VERSION 5.7 ;
BUSBITCHARS "[]" ;
DIVIDERCHAR "/" ;
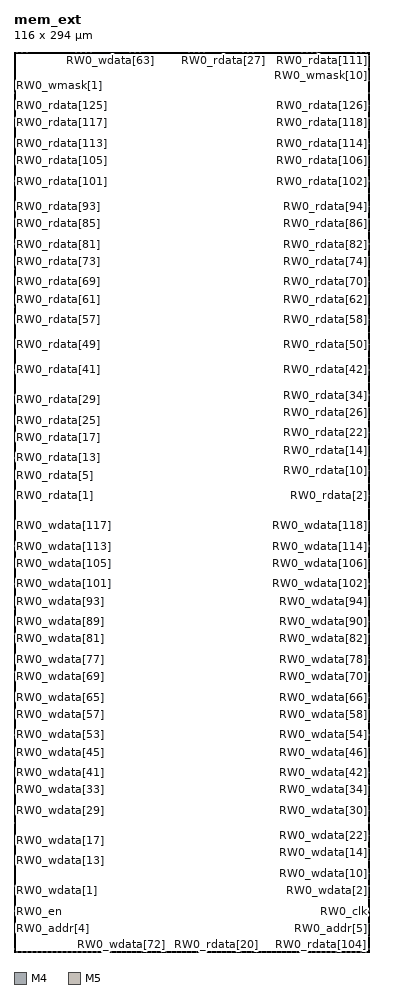
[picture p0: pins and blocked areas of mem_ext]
MACRO mem_ext
  FOREIGN mem_ext 0 0 ;
  CLASS BLOCK ;
  ORIGIN 0 0 ;
  SYMMETRY X Y R90 ;
  SIZE 116.000 BY 294.000 ;
  SITE asap7sc7p5t ;
  PIN RW0_addr[0]
    DIRECTION INPUT ;
    USE SIGNAL ;
    SHAPE ABUTMENT ;
    PORT
      LAYER M4 ;
      RECT 0.000 0.972 0.096 1.068 ;
    END
  END RW0_addr[0]
  PIN RW0_addr[1]
    DIRECTION INPUT ;
    USE SIGNAL ;
    SHAPE ABUTMENT ;
    PORT
      LAYER M4 ;
      RECT 115.904 0.972 116.000 1.068 ;
    END
  END RW0_addr[1]
  PIN RW0_addr[2]
    DIRECTION INPUT ;
    USE SIGNAL ;
    SHAPE ABUTMENT ;
    PORT
      LAYER M5 ;
      RECT 0.972 293.904 1.068 294.000 ;
    END
  END RW0_addr[2]
  PIN RW0_addr[3]
    DIRECTION INPUT ;
    USE SIGNAL ;
    SHAPE ABUTMENT ;
    PORT
      LAYER M5 ;
      RECT 0.972 0.000 1.068 0.096 ;
    END
  END RW0_addr[3]
  PIN RW0_addr[4]
    DIRECTION INPUT ;
    USE SIGNAL ;
    SHAPE ABUTMENT ;
    PORT
      LAYER M4 ;
      RECT 0.000 5.100 0.096 5.196 ;
    END
  END RW0_addr[4]
  PIN RW0_addr[5]
    DIRECTION INPUT ;
    USE SIGNAL ;
    SHAPE ABUTMENT ;
    PORT
      LAYER M4 ;
      RECT 115.904 5.100 116.000 5.196 ;
    END
  END RW0_addr[5]
  PIN RW0_addr[6]
    DIRECTION INPUT ;
    USE SIGNAL ;
    SHAPE ABUTMENT ;
    PORT
      LAYER M5 ;
      RECT 2.556 293.904 2.652 294.000 ;
    END
  END RW0_addr[6]
  PIN RW0_addr[7]
    DIRECTION INPUT ;
    USE SIGNAL ;
    SHAPE ABUTMENT ;
    PORT
      LAYER M5 ;
      RECT 2.604 0.000 2.700 0.096 ;
    END
  END RW0_addr[7]
  PIN RW0_addr[8]
    DIRECTION INPUT ;
    USE SIGNAL ;
    SHAPE ABUTMENT ;
    PORT
      LAYER M4 ;
      RECT 0.000 9.180 0.096 9.276 ;
    END
  END RW0_addr[8]
  PIN RW0_addr[9]
    DIRECTION INPUT ;
    USE SIGNAL ;
    SHAPE ABUTMENT ;
    PORT
      LAYER M4 ;
      RECT 115.904 9.180 116.000 9.276 ;
    END
  END RW0_addr[9]
  PIN RW0_addr[10]
    DIRECTION INPUT ;
    USE SIGNAL ;
    SHAPE ABUTMENT ;
    PORT
      LAYER M5 ;
      RECT 4.188 293.904 4.284 294.000 ;
    END
  END RW0_addr[10]
  PIN RW0_addr[11]
    DIRECTION INPUT ;
    USE SIGNAL ;
    SHAPE ABUTMENT ;
    PORT
      LAYER M5 ;
      RECT 4.236 0.000 4.332 0.096 ;
    END
  END RW0_addr[11]
  PIN RW0_en
    DIRECTION INPUT ;
    USE SIGNAL ;
    SHAPE ABUTMENT ;
    PORT
      LAYER M4 ;
      RECT 0.000 13.308 0.096 13.404 ;
    END
  END RW0_en
  PIN RW0_clk
    DIRECTION INPUT ;
    USE SIGNAL ;
    SHAPE ABUTMENT ;
    PORT
      LAYER M4 ;
      RECT 115.904 13.308 116.000 13.404 ;
    END
  END RW0_clk
  PIN RW0_wmode
    DIRECTION INPUT ;
    USE SIGNAL ;
    SHAPE ABUTMENT ;
    PORT
      LAYER M5 ;
      RECT 5.772 293.904 5.868 294.000 ;
    END
  END RW0_wmode
  PIN RW0_wdata[0]
    DIRECTION INPUT ;
    USE SIGNAL ;
    SHAPE ABUTMENT ;
    PORT
      LAYER M5 ;
      RECT 5.868 0.000 5.964 0.096 ;
    END
  END RW0_wdata[0]
  PIN RW0_wdata[1]
    DIRECTION INPUT ;
    USE SIGNAL ;
    SHAPE ABUTMENT ;
    PORT
      LAYER M4 ;
      RECT 0.000 17.436 0.096 17.532 ;
    END
  END RW0_wdata[1]
  PIN RW0_wdata[2]
    DIRECTION INPUT ;
    USE SIGNAL ;
    SHAPE ABUTMENT ;
    PORT
      LAYER M4 ;
      RECT 115.904 17.436 116.000 17.532 ;
    END
  END RW0_wdata[2]
  PIN RW0_wdata[3]
    DIRECTION INPUT ;
    USE SIGNAL ;
    SHAPE ABUTMENT ;
    PORT
      LAYER M5 ;
      RECT 7.404 293.904 7.500 294.000 ;
    END
  END RW0_wdata[3]
  PIN RW0_wdata[4]
    DIRECTION INPUT ;
    USE SIGNAL ;
    SHAPE ABUTMENT ;
    PORT
      LAYER M5 ;
      RECT 7.500 0.000 7.596 0.096 ;
    END
  END RW0_wdata[4]
  PIN RW0_wdata[5]
    DIRECTION INPUT ;
    USE SIGNAL ;
    SHAPE ABUTMENT ;
    PORT
      LAYER M4 ;
      RECT 0.000 21.516 0.096 21.612 ;
    END
  END RW0_wdata[5]
  PIN RW0_wdata[6]
    DIRECTION INPUT ;
    USE SIGNAL ;
    SHAPE ABUTMENT ;
    PORT
      LAYER M4 ;
      RECT 115.904 21.516 116.000 21.612 ;
    END
  END RW0_wdata[6]
  PIN RW0_wdata[7]
    DIRECTION INPUT ;
    USE SIGNAL ;
    SHAPE ABUTMENT ;
    PORT
      LAYER M5 ;
      RECT 8.988 293.904 9.084 294.000 ;
    END
  END RW0_wdata[7]
  PIN RW0_wdata[8]
    DIRECTION INPUT ;
    USE SIGNAL ;
    SHAPE ABUTMENT ;
    PORT
      LAYER M5 ;
      RECT 9.132 0.000 9.228 0.096 ;
    END
  END RW0_wdata[8]
  PIN RW0_wdata[9]
    DIRECTION INPUT ;
    USE SIGNAL ;
    SHAPE ABUTMENT ;
    PORT
      LAYER M4 ;
      RECT 0.000 25.644 0.096 25.740 ;
    END
  END RW0_wdata[9]
  PIN RW0_wdata[10]
    DIRECTION INPUT ;
    USE SIGNAL ;
    SHAPE ABUTMENT ;
    PORT
      LAYER M4 ;
      RECT 115.904 25.644 116.000 25.740 ;
    END
  END RW0_wdata[10]
  PIN RW0_wdata[11]
    DIRECTION INPUT ;
    USE SIGNAL ;
    SHAPE ABUTMENT ;
    PORT
      LAYER M5 ;
      RECT 10.620 293.904 10.716 294.000 ;
    END
  END RW0_wdata[11]
  PIN RW0_wdata[12]
    DIRECTION INPUT ;
    USE SIGNAL ;
    SHAPE ABUTMENT ;
    PORT
      LAYER M5 ;
      RECT 10.716 0.000 10.812 0.096 ;
    END
  END RW0_wdata[12]
  PIN RW0_wdata[13]
    DIRECTION INPUT ;
    USE SIGNAL ;
    SHAPE ABUTMENT ;
    PORT
      LAYER M4 ;
      RECT 0.000 29.772 0.096 29.868 ;
    END
  END RW0_wdata[13]
  PIN RW0_wdata[14]
    DIRECTION INPUT ;
    USE SIGNAL ;
    SHAPE ABUTMENT ;
    PORT
      LAYER M4 ;
      RECT 115.904 29.772 116.000 29.868 ;
    END
  END RW0_wdata[14]
  PIN RW0_wdata[15]
    DIRECTION INPUT ;
    USE SIGNAL ;
    SHAPE ABUTMENT ;
    PORT
      LAYER M5 ;
      RECT 12.204 293.904 12.300 294.000 ;
    END
  END RW0_wdata[15]
  PIN RW0_wdata[16]
    DIRECTION INPUT ;
    USE SIGNAL ;
    SHAPE ABUTMENT ;
    PORT
      LAYER M5 ;
      RECT 12.348 0.000 12.444 0.096 ;
    END
  END RW0_wdata[16]
  PIN RW0_wdata[17]
    DIRECTION INPUT ;
    USE SIGNAL ;
    SHAPE ABUTMENT ;
    PORT
      LAYER M4 ;
      RECT 0.000 33.852 0.096 33.948 ;
    END
  END RW0_wdata[17]
  PIN RW0_wdata[18]
    DIRECTION INPUT ;
    USE SIGNAL ;
    SHAPE ABUTMENT ;
    PORT
      LAYER M4 ;
      RECT 115.904 33.852 116.000 33.948 ;
    END
  END RW0_wdata[18]
  PIN RW0_wdata[19]
    DIRECTION INPUT ;
    USE SIGNAL ;
    SHAPE ABUTMENT ;
    PORT
      LAYER M5 ;
      RECT 13.788 293.904 13.884 294.000 ;
    END
  END RW0_wdata[19]
  PIN RW0_wdata[20]
    DIRECTION INPUT ;
    USE SIGNAL ;
    SHAPE ABUTMENT ;
    PORT
      LAYER M5 ;
      RECT 13.980 0.000 14.076 0.096 ;
    END
  END RW0_wdata[20]
  PIN RW0_wdata[21]
    DIRECTION INPUT ;
    USE SIGNAL ;
    SHAPE ABUTMENT ;
    PORT
      LAYER M4 ;
      RECT 0.000 37.980 0.096 38.076 ;
    END
  END RW0_wdata[21]
  PIN RW0_wdata[22]
    DIRECTION INPUT ;
    USE SIGNAL ;
    SHAPE ABUTMENT ;
    PORT
      LAYER M4 ;
      RECT 115.904 37.980 116.000 38.076 ;
    END
  END RW0_wdata[22]
  PIN RW0_wdata[23]
    DIRECTION INPUT ;
    USE SIGNAL ;
    SHAPE ABUTMENT ;
    PORT
      LAYER M5 ;
      RECT 15.420 293.904 15.516 294.000 ;
    END
  END RW0_wdata[23]
  PIN RW0_wdata[24]
    DIRECTION INPUT ;
    USE SIGNAL ;
    SHAPE ABUTMENT ;
    PORT
      LAYER M5 ;
      RECT 15.612 0.000 15.708 0.096 ;
    END
  END RW0_wdata[24]
  PIN RW0_wdata[25]
    DIRECTION INPUT ;
    USE SIGNAL ;
    SHAPE ABUTMENT ;
    PORT
      LAYER M4 ;
      RECT 0.000 42.108 0.096 42.204 ;
    END
  END RW0_wdata[25]
  PIN RW0_wdata[26]
    DIRECTION INPUT ;
    USE SIGNAL ;
    SHAPE ABUTMENT ;
    PORT
      LAYER M4 ;
      RECT 115.904 42.108 116.000 42.204 ;
    END
  END RW0_wdata[26]
  PIN RW0_wdata[27]
    DIRECTION INPUT ;
    USE SIGNAL ;
    SHAPE ABUTMENT ;
    PORT
      LAYER M5 ;
      RECT 17.004 293.904 17.100 294.000 ;
    END
  END RW0_wdata[27]
  PIN RW0_wdata[28]
    DIRECTION INPUT ;
    USE SIGNAL ;
    SHAPE ABUTMENT ;
    PORT
      LAYER M5 ;
      RECT 17.244 0.000 17.340 0.096 ;
    END
  END RW0_wdata[28]
  PIN RW0_wdata[29]
    DIRECTION INPUT ;
    USE SIGNAL ;
    SHAPE ABUTMENT ;
    PORT
      LAYER M4 ;
      RECT 0.000 46.188 0.096 46.284 ;
    END
  END RW0_wdata[29]
  PIN RW0_wdata[30]
    DIRECTION INPUT ;
    USE SIGNAL ;
    SHAPE ABUTMENT ;
    PORT
      LAYER M4 ;
      RECT 115.904 46.188 116.000 46.284 ;
    END
  END RW0_wdata[30]
  PIN RW0_wdata[31]
    DIRECTION INPUT ;
    USE SIGNAL ;
    SHAPE ABUTMENT ;
    PORT
      LAYER M5 ;
      RECT 18.636 293.904 18.732 294.000 ;
    END
  END RW0_wdata[31]
  PIN RW0_wdata[32]
    DIRECTION INPUT ;
    USE SIGNAL ;
    SHAPE ABUTMENT ;
    PORT
      LAYER M5 ;
      RECT 18.876 0.000 18.972 0.096 ;
    END
  END RW0_wdata[32]
  PIN RW0_wdata[33]
    DIRECTION INPUT ;
    USE SIGNAL ;
    SHAPE ABUTMENT ;
    PORT
      LAYER M4 ;
      RECT 0.000 50.316 0.096 50.412 ;
    END
  END RW0_wdata[33]
  PIN RW0_wdata[34]
    DIRECTION INPUT ;
    USE SIGNAL ;
    SHAPE ABUTMENT ;
    PORT
      LAYER M4 ;
      RECT 115.904 50.316 116.000 50.412 ;
    END
  END RW0_wdata[34]
  PIN RW0_wdata[35]
    DIRECTION INPUT ;
    USE SIGNAL ;
    SHAPE ABUTMENT ;
    PORT
      LAYER M5 ;
      RECT 20.220 293.904 20.316 294.000 ;
    END
  END RW0_wdata[35]
  PIN RW0_wdata[36]
    DIRECTION INPUT ;
    USE SIGNAL ;
    SHAPE ABUTMENT ;
    PORT
      LAYER M5 ;
      RECT 20.508 0.000 20.604 0.096 ;
    END
  END RW0_wdata[36]
  PIN RW0_wdata[37]
    DIRECTION INPUT ;
    USE SIGNAL ;
    SHAPE ABUTMENT ;
    PORT
      LAYER M4 ;
      RECT 0.000 54.444 0.096 54.540 ;
    END
  END RW0_wdata[37]
  PIN RW0_wdata[38]
    DIRECTION INPUT ;
    USE SIGNAL ;
    SHAPE ABUTMENT ;
    PORT
      LAYER M4 ;
      RECT 115.904 54.444 116.000 54.540 ;
    END
  END RW0_wdata[38]
  PIN RW0_wdata[39]
    DIRECTION INPUT ;
    USE SIGNAL ;
    SHAPE ABUTMENT ;
    PORT
      LAYER M5 ;
      RECT 21.852 293.904 21.948 294.000 ;
    END
  END RW0_wdata[39]
  PIN RW0_wdata[40]
    DIRECTION INPUT ;
    USE SIGNAL ;
    SHAPE ABUTMENT ;
    PORT
      LAYER M5 ;
      RECT 22.140 0.000 22.236 0.096 ;
    END
  END RW0_wdata[40]
  PIN RW0_wdata[41]
    DIRECTION INPUT ;
    USE SIGNAL ;
    SHAPE ABUTMENT ;
    PORT
      LAYER M4 ;
      RECT 0.000 58.524 0.096 58.620 ;
    END
  END RW0_wdata[41]
  PIN RW0_wdata[42]
    DIRECTION INPUT ;
    USE SIGNAL ;
    SHAPE ABUTMENT ;
    PORT
      LAYER M4 ;
      RECT 115.904 58.524 116.000 58.620 ;
    END
  END RW0_wdata[42]
  PIN RW0_wdata[43]
    DIRECTION INPUT ;
    USE SIGNAL ;
    SHAPE ABUTMENT ;
    PORT
      LAYER M5 ;
      RECT 23.436 293.904 23.532 294.000 ;
    END
  END RW0_wdata[43]
  PIN RW0_wdata[44]
    DIRECTION INPUT ;
    USE SIGNAL ;
    SHAPE ABUTMENT ;
    PORT
      LAYER M5 ;
      RECT 23.772 0.000 23.868 0.096 ;
    END
  END RW0_wdata[44]
  PIN RW0_wdata[45]
    DIRECTION INPUT ;
    USE SIGNAL ;
    SHAPE ABUTMENT ;
    PORT
      LAYER M4 ;
      RECT 0.000 62.652 0.096 62.748 ;
    END
  END RW0_wdata[45]
  PIN RW0_wdata[46]
    DIRECTION INPUT ;
    USE SIGNAL ;
    SHAPE ABUTMENT ;
    PORT
      LAYER M4 ;
      RECT 115.904 62.652 116.000 62.748 ;
    END
  END RW0_wdata[46]
  PIN RW0_wdata[47]
    DIRECTION INPUT ;
    USE SIGNAL ;
    SHAPE ABUTMENT ;
    PORT
      LAYER M5 ;
      RECT 25.068 293.904 25.164 294.000 ;
    END
  END RW0_wdata[47]
  PIN RW0_wdata[48]
    DIRECTION INPUT ;
    USE SIGNAL ;
    SHAPE ABUTMENT ;
    PORT
      LAYER M5 ;
      RECT 25.404 0.000 25.500 0.096 ;
    END
  END RW0_wdata[48]
  PIN RW0_wdata[49]
    DIRECTION INPUT ;
    USE SIGNAL ;
    SHAPE ABUTMENT ;
    PORT
      LAYER M4 ;
      RECT 0.000 66.780 0.096 66.876 ;
    END
  END RW0_wdata[49]
  PIN RW0_wdata[50]
    DIRECTION INPUT ;
    USE SIGNAL ;
    SHAPE ABUTMENT ;
    PORT
      LAYER M4 ;
      RECT 115.904 66.780 116.000 66.876 ;
    END
  END RW0_wdata[50]
  PIN RW0_wdata[51]
    DIRECTION INPUT ;
    USE SIGNAL ;
    SHAPE ABUTMENT ;
    PORT
      LAYER M5 ;
      RECT 26.652 293.904 26.748 294.000 ;
    END
  END RW0_wdata[51]
  PIN RW0_wdata[52]
    DIRECTION INPUT ;
    USE SIGNAL ;
    SHAPE ABUTMENT ;
    PORT
      LAYER M5 ;
      RECT 27.036 0.000 27.132 0.096 ;
    END
  END RW0_wdata[52]
  PIN RW0_wdata[53]
    DIRECTION INPUT ;
    USE SIGNAL ;
    SHAPE ABUTMENT ;
    PORT
      LAYER M4 ;
      RECT 0.000 70.860 0.096 70.956 ;
    END
  END RW0_wdata[53]
  PIN RW0_wdata[54]
    DIRECTION INPUT ;
    USE SIGNAL ;
    SHAPE ABUTMENT ;
    PORT
      LAYER M4 ;
      RECT 115.904 70.860 116.000 70.956 ;
    END
  END RW0_wdata[54]
  PIN RW0_wdata[55]
    DIRECTION INPUT ;
    USE SIGNAL ;
    SHAPE ABUTMENT ;
    PORT
      LAYER M5 ;
      RECT 28.236 293.904 28.332 294.000 ;
    END
  END RW0_wdata[55]
  PIN RW0_wdata[56]
    DIRECTION INPUT ;
    USE SIGNAL ;
    SHAPE ABUTMENT ;
    PORT
      LAYER M5 ;
      RECT 28.668 0.000 28.764 0.096 ;
    END
  END RW0_wdata[56]
  PIN RW0_wdata[57]
    DIRECTION INPUT ;
    USE SIGNAL ;
    SHAPE ABUTMENT ;
    PORT
      LAYER M4 ;
      RECT 0.000 74.988 0.096 75.084 ;
    END
  END RW0_wdata[57]
  PIN RW0_wdata[58]
    DIRECTION INPUT ;
    USE SIGNAL ;
    SHAPE ABUTMENT ;
    PORT
      LAYER M4 ;
      RECT 115.904 74.988 116.000 75.084 ;
    END
  END RW0_wdata[58]
  PIN RW0_wdata[59]
    DIRECTION INPUT ;
    USE SIGNAL ;
    SHAPE ABUTMENT ;
    PORT
      LAYER M5 ;
      RECT 29.868 293.904 29.964 294.000 ;
    END
  END RW0_wdata[59]
  PIN RW0_wdata[60]
    DIRECTION INPUT ;
    USE SIGNAL ;
    SHAPE ABUTMENT ;
    PORT
      LAYER M5 ;
      RECT 30.252 0.000 30.348 0.096 ;
    END
  END RW0_wdata[60]
  PIN RW0_wdata[61]
    DIRECTION INPUT ;
    USE SIGNAL ;
    SHAPE ABUTMENT ;
    PORT
      LAYER M4 ;
      RECT 0.000 79.116 0.096 79.212 ;
    END
  END RW0_wdata[61]
  PIN RW0_wdata[62]
    DIRECTION INPUT ;
    USE SIGNAL ;
    SHAPE ABUTMENT ;
    PORT
      LAYER M4 ;
      RECT 115.904 79.116 116.000 79.212 ;
    END
  END RW0_wdata[62]
  PIN RW0_wdata[63]
    DIRECTION INPUT ;
    USE SIGNAL ;
    SHAPE ABUTMENT ;
    PORT
      LAYER M5 ;
      RECT 31.452 293.904 31.548 294.000 ;
    END
  END RW0_wdata[63]
  PIN RW0_wdata[64]
    DIRECTION INPUT ;
    USE SIGNAL ;
    SHAPE ABUTMENT ;
    PORT
      LAYER M5 ;
      RECT 31.884 0.000 31.980 0.096 ;
    END
  END RW0_wdata[64]
  PIN RW0_wdata[65]
    DIRECTION INPUT ;
    USE SIGNAL ;
    SHAPE ABUTMENT ;
    PORT
      LAYER M4 ;
      RECT 0.000 83.196 0.096 83.292 ;
    END
  END RW0_wdata[65]
  PIN RW0_wdata[66]
    DIRECTION INPUT ;
    USE SIGNAL ;
    SHAPE ABUTMENT ;
    PORT
      LAYER M4 ;
      RECT 115.904 83.196 116.000 83.292 ;
    END
  END RW0_wdata[66]
  PIN RW0_wdata[67]
    DIRECTION INPUT ;
    USE SIGNAL ;
    SHAPE ABUTMENT ;
    PORT
      LAYER M5 ;
      RECT 33.084 293.904 33.180 294.000 ;
    END
  END RW0_wdata[67]
  PIN RW0_wdata[68]
    DIRECTION INPUT ;
    USE SIGNAL ;
    SHAPE ABUTMENT ;
    PORT
      LAYER M5 ;
      RECT 33.516 0.000 33.612 0.096 ;
    END
  END RW0_wdata[68]
  PIN RW0_wdata[69]
    DIRECTION INPUT ;
    USE SIGNAL ;
    SHAPE ABUTMENT ;
    PORT
      LAYER M4 ;
      RECT 0.000 87.324 0.096 87.420 ;
    END
  END RW0_wdata[69]
  PIN RW0_wdata[70]
    DIRECTION INPUT ;
    USE SIGNAL ;
    SHAPE ABUTMENT ;
    PORT
      LAYER M4 ;
      RECT 115.904 87.324 116.000 87.420 ;
    END
  END RW0_wdata[70]
  PIN RW0_wdata[71]
    DIRECTION INPUT ;
    USE SIGNAL ;
    SHAPE ABUTMENT ;
    PORT
      LAYER M5 ;
      RECT 34.668 293.904 34.764 294.000 ;
    END
  END RW0_wdata[71]
  PIN RW0_wdata[72]
    DIRECTION INPUT ;
    USE SIGNAL ;
    SHAPE ABUTMENT ;
    PORT
      LAYER M5 ;
      RECT 35.148 0.000 35.244 0.096 ;
    END
  END RW0_wdata[72]
  PIN RW0_wdata[73]
    DIRECTION INPUT ;
    USE SIGNAL ;
    SHAPE ABUTMENT ;
    PORT
      LAYER M4 ;
      RECT 0.000 91.452 0.096 91.548 ;
    END
  END RW0_wdata[73]
  PIN RW0_wdata[74]
    DIRECTION INPUT ;
    USE SIGNAL ;
    SHAPE ABUTMENT ;
    PORT
      LAYER M4 ;
      RECT 115.904 91.452 116.000 91.548 ;
    END
  END RW0_wdata[74]
  PIN RW0_wdata[75]
    DIRECTION INPUT ;
    USE SIGNAL ;
    SHAPE ABUTMENT ;
    PORT
      LAYER M5 ;
      RECT 36.300 293.904 36.396 294.000 ;
    END
  END RW0_wdata[75]
  PIN RW0_wdata[76]
    DIRECTION INPUT ;
    USE SIGNAL ;
    SHAPE ABUTMENT ;
    PORT
      LAYER M5 ;
      RECT 36.780 0.000 36.876 0.096 ;
    END
  END RW0_wdata[76]
  PIN RW0_wdata[77]
    DIRECTION INPUT ;
    USE SIGNAL ;
    SHAPE ABUTMENT ;
    PORT
      LAYER M4 ;
      RECT 0.000 95.532 0.096 95.628 ;
    END
  END RW0_wdata[77]
  PIN RW0_wdata[78]
    DIRECTION INPUT ;
    USE SIGNAL ;
    SHAPE ABUTMENT ;
    PORT
      LAYER M4 ;
      RECT 115.904 95.532 116.000 95.628 ;
    END
  END RW0_wdata[78]
  PIN RW0_wdata[79]
    DIRECTION INPUT ;
    USE SIGNAL ;
    SHAPE ABUTMENT ;
    PORT
      LAYER M5 ;
      RECT 37.884 293.904 37.980 294.000 ;
    END
  END RW0_wdata[79]
  PIN RW0_wdata[80]
    DIRECTION INPUT ;
    USE SIGNAL ;
    SHAPE ABUTMENT ;
    PORT
      LAYER M5 ;
      RECT 38.412 0.000 38.508 0.096 ;
    END
  END RW0_wdata[80]
  PIN RW0_wdata[81]
    DIRECTION INPUT ;
    USE SIGNAL ;
    SHAPE ABUTMENT ;
    PORT
      LAYER M4 ;
      RECT 0.000 99.660 0.096 99.756 ;
    END
  END RW0_wdata[81]
  PIN RW0_wdata[82]
    DIRECTION INPUT ;
    USE SIGNAL ;
    SHAPE ABUTMENT ;
    PORT
      LAYER M4 ;
      RECT 115.904 99.660 116.000 99.756 ;
    END
  END RW0_wdata[82]
  PIN RW0_wdata[83]
    DIRECTION INPUT ;
    USE SIGNAL ;
    SHAPE ABUTMENT ;
    PORT
      LAYER M5 ;
      RECT 39.468 293.904 39.564 294.000 ;
    END
  END RW0_wdata[83]
  PIN RW0_wdata[84]
    DIRECTION INPUT ;
    USE SIGNAL ;
    SHAPE ABUTMENT ;
    PORT
      LAYER M5 ;
      RECT 40.044 0.000 40.140 0.096 ;
    END
  END RW0_wdata[84]
  PIN RW0_wdata[85]
    DIRECTION INPUT ;
    USE SIGNAL ;
    SHAPE ABUTMENT ;
    PORT
      LAYER M4 ;
      RECT 0.000 103.788 0.096 103.884 ;
    END
  END RW0_wdata[85]
  PIN RW0_wdata[86]
    DIRECTION INPUT ;
    USE SIGNAL ;
    SHAPE ABUTMENT ;
    PORT
      LAYER M4 ;
      RECT 115.904 103.788 116.000 103.884 ;
    END
  END RW0_wdata[86]
  PIN RW0_wdata[87]
    DIRECTION INPUT ;
    USE SIGNAL ;
    SHAPE ABUTMENT ;
    PORT
      LAYER M5 ;
      RECT 41.100 293.904 41.196 294.000 ;
    END
  END RW0_wdata[87]
  PIN RW0_wdata[88]
    DIRECTION INPUT ;
    USE SIGNAL ;
    SHAPE ABUTMENT ;
    PORT
      LAYER M5 ;
      RECT 41.676 0.000 41.772 0.096 ;
    END
  END RW0_wdata[88]
  PIN RW0_wdata[89]
    DIRECTION INPUT ;
    USE SIGNAL ;
    SHAPE ABUTMENT ;
    PORT
      LAYER M4 ;
      RECT 0.000 107.868 0.096 107.964 ;
    END
  END RW0_wdata[89]
  PIN RW0_wdata[90]
    DIRECTION INPUT ;
    USE SIGNAL ;
    SHAPE ABUTMENT ;
    PORT
      LAYER M4 ;
      RECT 115.904 107.868 116.000 107.964 ;
    END
  END RW0_wdata[90]
  PIN RW0_wdata[91]
    DIRECTION INPUT ;
    USE SIGNAL ;
    SHAPE ABUTMENT ;
    PORT
      LAYER M5 ;
      RECT 42.684 293.904 42.780 294.000 ;
    END
  END RW0_wdata[91]
  PIN RW0_wdata[92]
    DIRECTION INPUT ;
    USE SIGNAL ;
    SHAPE ABUTMENT ;
    PORT
      LAYER M5 ;
      RECT 43.308 0.000 43.404 0.096 ;
    END
  END RW0_wdata[92]
  PIN RW0_wdata[93]
    DIRECTION INPUT ;
    USE SIGNAL ;
    SHAPE ABUTMENT ;
    PORT
      LAYER M4 ;
      RECT 0.000 111.996 0.096 112.092 ;
    END
  END RW0_wdata[93]
  PIN RW0_wdata[94]
    DIRECTION INPUT ;
    USE SIGNAL ;
    SHAPE ABUTMENT ;
    PORT
      LAYER M4 ;
      RECT 115.904 111.996 116.000 112.092 ;
    END
  END RW0_wdata[94]
  PIN RW0_wdata[95]
    DIRECTION INPUT ;
    USE SIGNAL ;
    SHAPE ABUTMENT ;
    PORT
      LAYER M5 ;
      RECT 44.316 293.904 44.412 294.000 ;
    END
  END RW0_wdata[95]
  PIN RW0_wdata[96]
    DIRECTION INPUT ;
    USE SIGNAL ;
    SHAPE ABUTMENT ;
    PORT
      LAYER M5 ;
      RECT 44.940 0.000 45.036 0.096 ;
    END
  END RW0_wdata[96]
  PIN RW0_wdata[97]
    DIRECTION INPUT ;
    USE SIGNAL ;
    SHAPE ABUTMENT ;
    PORT
      LAYER M4 ;
      RECT 0.000 116.124 0.096 116.220 ;
    END
  END RW0_wdata[97]
  PIN RW0_wdata[98]
    DIRECTION INPUT ;
    USE SIGNAL ;
    SHAPE ABUTMENT ;
    PORT
      LAYER M4 ;
      RECT 115.904 116.124 116.000 116.220 ;
    END
  END RW0_wdata[98]
  PIN RW0_wdata[99]
    DIRECTION INPUT ;
    USE SIGNAL ;
    SHAPE ABUTMENT ;
    PORT
      LAYER M5 ;
      RECT 45.900 293.904 45.996 294.000 ;
    END
  END RW0_wdata[99]
  PIN RW0_wdata[100]
    DIRECTION INPUT ;
    USE SIGNAL ;
    SHAPE ABUTMENT ;
    PORT
      LAYER M5 ;
      RECT 46.572 0.000 46.668 0.096 ;
    END
  END RW0_wdata[100]
  PIN RW0_wdata[101]
    DIRECTION INPUT ;
    USE SIGNAL ;
    SHAPE ABUTMENT ;
    PORT
      LAYER M4 ;
      RECT 0.000 120.204 0.096 120.300 ;
    END
  END RW0_wdata[101]
  PIN RW0_wdata[102]
    DIRECTION INPUT ;
    USE SIGNAL ;
    SHAPE ABUTMENT ;
    PORT
      LAYER M4 ;
      RECT 115.904 120.204 116.000 120.300 ;
    END
  END RW0_wdata[102]
  PIN RW0_wdata[103]
    DIRECTION INPUT ;
    USE SIGNAL ;
    SHAPE ABUTMENT ;
    PORT
      LAYER M5 ;
      RECT 47.532 293.904 47.628 294.000 ;
    END
  END RW0_wdata[103]
  PIN RW0_wdata[104]
    DIRECTION INPUT ;
    USE SIGNAL ;
    SHAPE ABUTMENT ;
    PORT
      LAYER M5 ;
      RECT 48.204 0.000 48.300 0.096 ;
    END
  END RW0_wdata[104]
  PIN RW0_wdata[105]
    DIRECTION INPUT ;
    USE SIGNAL ;
    SHAPE ABUTMENT ;
    PORT
      LAYER M4 ;
      RECT 0.000 124.332 0.096 124.428 ;
    END
  END RW0_wdata[105]
  PIN RW0_wdata[106]
    DIRECTION INPUT ;
    USE SIGNAL ;
    SHAPE ABUTMENT ;
    PORT
      LAYER M4 ;
      RECT 115.904 124.332 116.000 124.428 ;
    END
  END RW0_wdata[106]
  PIN RW0_wdata[107]
    DIRECTION INPUT ;
    USE SIGNAL ;
    SHAPE ABUTMENT ;
    PORT
      LAYER M5 ;
      RECT 49.116 293.904 49.212 294.000 ;
    END
  END RW0_wdata[107]
  PIN RW0_wdata[108]
    DIRECTION INPUT ;
    USE SIGNAL ;
    SHAPE ABUTMENT ;
    PORT
      LAYER M5 ;
      RECT 49.788 0.000 49.884 0.096 ;
    END
  END RW0_wdata[108]
  PIN RW0_wdata[109]
    DIRECTION INPUT ;
    USE SIGNAL ;
    SHAPE ABUTMENT ;
    PORT
      LAYER M4 ;
      RECT 0.000 128.460 0.096 128.556 ;
    END
  END RW0_wdata[109]
  PIN RW0_wdata[110]
    DIRECTION INPUT ;
    USE SIGNAL ;
    SHAPE ABUTMENT ;
    PORT
      LAYER M4 ;
      RECT 115.904 128.460 116.000 128.556 ;
    END
  END RW0_wdata[110]
  PIN RW0_wdata[111]
    DIRECTION INPUT ;
    USE SIGNAL ;
    SHAPE ABUTMENT ;
    PORT
      LAYER M5 ;
      RECT 50.748 293.904 50.844 294.000 ;
    END
  END RW0_wdata[111]
  PIN RW0_wdata[112]
    DIRECTION INPUT ;
    USE SIGNAL ;
    SHAPE ABUTMENT ;
    PORT
      LAYER M5 ;
      RECT 51.420 0.000 51.516 0.096 ;
    END
  END RW0_wdata[112]
  PIN RW0_wdata[113]
    DIRECTION INPUT ;
    USE SIGNAL ;
    SHAPE ABUTMENT ;
    PORT
      LAYER M4 ;
      RECT 0.000 132.540 0.096 132.636 ;
    END
  END RW0_wdata[113]
  PIN RW0_wdata[114]
    DIRECTION INPUT ;
    USE SIGNAL ;
    SHAPE ABUTMENT ;
    PORT
      LAYER M4 ;
      RECT 115.904 132.540 116.000 132.636 ;
    END
  END RW0_wdata[114]
  PIN RW0_wdata[115]
    DIRECTION INPUT ;
    USE SIGNAL ;
    SHAPE ABUTMENT ;
    PORT
      LAYER M5 ;
      RECT 52.332 293.904 52.428 294.000 ;
    END
  END RW0_wdata[115]
  PIN RW0_wdata[116]
    DIRECTION INPUT ;
    USE SIGNAL ;
    SHAPE ABUTMENT ;
    PORT
      LAYER M5 ;
      RECT 53.052 0.000 53.148 0.096 ;
    END
  END RW0_wdata[116]
  PIN RW0_wdata[117]
    DIRECTION INPUT ;
    USE SIGNAL ;
    SHAPE ABUTMENT ;
    PORT
      LAYER M4 ;
      RECT 0.000 136.668 0.096 136.764 ;
    END
  END RW0_wdata[117]
  PIN RW0_wdata[118]
    DIRECTION INPUT ;
    USE SIGNAL ;
    SHAPE ABUTMENT ;
    PORT
      LAYER M4 ;
      RECT 115.904 136.668 116.000 136.764 ;
    END
  END RW0_wdata[118]
  PIN RW0_wdata[119]
    DIRECTION INPUT ;
    USE SIGNAL ;
    SHAPE ABUTMENT ;
    PORT
      LAYER M5 ;
      RECT 53.916 293.904 54.012 294.000 ;
    END
  END RW0_wdata[119]
  PIN RW0_wdata[120]
    DIRECTION INPUT ;
    USE SIGNAL ;
    SHAPE ABUTMENT ;
    PORT
      LAYER M5 ;
      RECT 54.684 0.000 54.780 0.096 ;
    END
  END RW0_wdata[120]
  PIN RW0_wdata[121]
    DIRECTION INPUT ;
    USE SIGNAL ;
    SHAPE ABUTMENT ;
    PORT
      LAYER M4 ;
      RECT 0.000 140.796 0.096 140.892 ;
    END
  END RW0_wdata[121]
  PIN RW0_wdata[122]
    DIRECTION INPUT ;
    USE SIGNAL ;
    SHAPE ABUTMENT ;
    PORT
      LAYER M4 ;
      RECT 115.904 140.796 116.000 140.892 ;
    END
  END RW0_wdata[122]
  PIN RW0_wdata[123]
    DIRECTION INPUT ;
    USE SIGNAL ;
    SHAPE ABUTMENT ;
    PORT
      LAYER M5 ;
      RECT 55.548 293.904 55.644 294.000 ;
    END
  END RW0_wdata[123]
  PIN RW0_wdata[124]
    DIRECTION INPUT ;
    USE SIGNAL ;
    SHAPE ABUTMENT ;
    PORT
      LAYER M5 ;
      RECT 56.316 0.000 56.412 0.096 ;
    END
  END RW0_wdata[124]
  PIN RW0_wdata[125]
    DIRECTION INPUT ;
    USE SIGNAL ;
    SHAPE ABUTMENT ;
    PORT
      LAYER M4 ;
      RECT 0.000 144.876 0.096 144.972 ;
    END
  END RW0_wdata[125]
  PIN RW0_wdata[126]
    DIRECTION INPUT ;
    USE SIGNAL ;
    SHAPE ABUTMENT ;
    PORT
      LAYER M4 ;
      RECT 115.904 144.876 116.000 144.972 ;
    END
  END RW0_wdata[126]
  PIN RW0_wdata[127]
    DIRECTION INPUT ;
    USE SIGNAL ;
    SHAPE ABUTMENT ;
    PORT
      LAYER M5 ;
      RECT 57.132 293.904 57.228 294.000 ;
    END
  END RW0_wdata[127]
  PIN RW0_rdata[0]
    DIRECTION OUTPUT ;
    USE SIGNAL ;
    SHAPE ABUTMENT ;
    PORT
      LAYER M5 ;
      RECT 57.948 0.000 58.044 0.096 ;
    END
  END RW0_rdata[0]
  PIN RW0_rdata[1]
    DIRECTION OUTPUT ;
    USE SIGNAL ;
    SHAPE ABUTMENT ;
    PORT
      LAYER M4 ;
      RECT 0.000 149.004 0.096 149.100 ;
    END
  END RW0_rdata[1]
  PIN RW0_rdata[2]
    DIRECTION OUTPUT ;
    USE SIGNAL ;
    SHAPE ABUTMENT ;
    PORT
      LAYER M4 ;
      RECT 115.904 149.004 116.000 149.100 ;
    END
  END RW0_rdata[2]
  PIN RW0_rdata[3]
    DIRECTION OUTPUT ;
    USE SIGNAL ;
    SHAPE ABUTMENT ;
    PORT
      LAYER M5 ;
      RECT 58.764 293.904 58.860 294.000 ;
    END
  END RW0_rdata[3]
  PIN RW0_rdata[4]
    DIRECTION OUTPUT ;
    USE SIGNAL ;
    SHAPE ABUTMENT ;
    PORT
      LAYER M5 ;
      RECT 59.580 0.000 59.676 0.096 ;
    END
  END RW0_rdata[4]
  PIN RW0_rdata[5]
    DIRECTION OUTPUT ;
    USE SIGNAL ;
    SHAPE ABUTMENT ;
    PORT
      LAYER M4 ;
      RECT 0.000 153.084 0.096 153.180 ;
    END
  END RW0_rdata[5]
  PIN RW0_rdata[6]
    DIRECTION OUTPUT ;
    USE SIGNAL ;
    SHAPE ABUTMENT ;
    PORT
      LAYER M4 ;
      RECT 115.904 153.084 116.000 153.180 ;
    END
  END RW0_rdata[6]
  PIN RW0_rdata[7]
    DIRECTION OUTPUT ;
    USE SIGNAL ;
    SHAPE ABUTMENT ;
    PORT
      LAYER M5 ;
      RECT 60.348 293.904 60.444 294.000 ;
    END
  END RW0_rdata[7]
  PIN RW0_rdata[8]
    DIRECTION OUTPUT ;
    USE SIGNAL ;
    SHAPE ABUTMENT ;
    PORT
      LAYER M5 ;
      RECT 61.212 0.000 61.308 0.096 ;
    END
  END RW0_rdata[8]
  PIN RW0_rdata[9]
    DIRECTION OUTPUT ;
    USE SIGNAL ;
    SHAPE ABUTMENT ;
    PORT
      LAYER M4 ;
      RECT 0.000 157.212 0.096 157.308 ;
    END
  END RW0_rdata[9]
  PIN RW0_rdata[10]
    DIRECTION OUTPUT ;
    USE SIGNAL ;
    SHAPE ABUTMENT ;
    PORT
      LAYER M4 ;
      RECT 115.904 157.212 116.000 157.308 ;
    END
  END RW0_rdata[10]
  PIN RW0_rdata[11]
    DIRECTION OUTPUT ;
    USE SIGNAL ;
    SHAPE ABUTMENT ;
    PORT
      LAYER M5 ;
      RECT 61.980 293.904 62.076 294.000 ;
    END
  END RW0_rdata[11]
  PIN RW0_rdata[12]
    DIRECTION OUTPUT ;
    USE SIGNAL ;
    SHAPE ABUTMENT ;
    PORT
      LAYER M5 ;
      RECT 62.844 0.000 62.940 0.096 ;
    END
  END RW0_rdata[12]
  PIN RW0_rdata[13]
    DIRECTION OUTPUT ;
    USE SIGNAL ;
    SHAPE ABUTMENT ;
    PORT
      LAYER M4 ;
      RECT 0.000 161.340 0.096 161.436 ;
    END
  END RW0_rdata[13]
  PIN RW0_rdata[14]
    DIRECTION OUTPUT ;
    USE SIGNAL ;
    SHAPE ABUTMENT ;
    PORT
      LAYER M4 ;
      RECT 115.904 161.340 116.000 161.436 ;
    END
  END RW0_rdata[14]
  PIN RW0_rdata[15]
    DIRECTION OUTPUT ;
    USE SIGNAL ;
    SHAPE ABUTMENT ;
    PORT
      LAYER M5 ;
      RECT 63.564 293.904 63.660 294.000 ;
    END
  END RW0_rdata[15]
  PIN RW0_rdata[16]
    DIRECTION OUTPUT ;
    USE SIGNAL ;
    SHAPE ABUTMENT ;
    PORT
      LAYER M5 ;
      RECT 64.476 0.000 64.572 0.096 ;
    END
  END RW0_rdata[16]
  PIN RW0_rdata[17]
    DIRECTION OUTPUT ;
    USE SIGNAL ;
    SHAPE ABUTMENT ;
    PORT
      LAYER M4 ;
      RECT 0.000 165.420 0.096 165.516 ;
    END
  END RW0_rdata[17]
  PIN RW0_rdata[18]
    DIRECTION OUTPUT ;
    USE SIGNAL ;
    SHAPE ABUTMENT ;
    PORT
      LAYER M4 ;
      RECT 115.904 165.420 116.000 165.516 ;
    END
  END RW0_rdata[18]
  PIN RW0_rdata[19]
    DIRECTION OUTPUT ;
    USE SIGNAL ;
    SHAPE ABUTMENT ;
    PORT
      LAYER M5 ;
      RECT 65.148 293.904 65.244 294.000 ;
    END
  END RW0_rdata[19]
  PIN RW0_rdata[20]
    DIRECTION OUTPUT ;
    USE SIGNAL ;
    SHAPE ABUTMENT ;
    PORT
      LAYER M5 ;
      RECT 66.108 0.000 66.204 0.096 ;
    END
  END RW0_rdata[20]
  PIN RW0_rdata[21]
    DIRECTION OUTPUT ;
    USE SIGNAL ;
    SHAPE ABUTMENT ;
    PORT
      LAYER M4 ;
      RECT 0.000 169.548 0.096 169.644 ;
    END
  END RW0_rdata[21]
  PIN RW0_rdata[22]
    DIRECTION OUTPUT ;
    USE SIGNAL ;
    SHAPE ABUTMENT ;
    PORT
      LAYER M4 ;
      RECT 115.904 169.548 116.000 169.644 ;
    END
  END RW0_rdata[22]
  PIN RW0_rdata[23]
    DIRECTION OUTPUT ;
    USE SIGNAL ;
    SHAPE ABUTMENT ;
    PORT
      LAYER M5 ;
      RECT 66.780 293.904 66.876 294.000 ;
    END
  END RW0_rdata[23]
  PIN RW0_rdata[24]
    DIRECTION OUTPUT ;
    USE SIGNAL ;
    SHAPE ABUTMENT ;
    PORT
      LAYER M5 ;
      RECT 67.692 0.000 67.788 0.096 ;
    END
  END RW0_rdata[24]
  PIN RW0_rdata[25]
    DIRECTION OUTPUT ;
    USE SIGNAL ;
    SHAPE ABUTMENT ;
    PORT
      LAYER M4 ;
      RECT 0.000 173.676 0.096 173.772 ;
    END
  END RW0_rdata[25]
  PIN RW0_rdata[26]
    DIRECTION OUTPUT ;
    USE SIGNAL ;
    SHAPE ABUTMENT ;
    PORT
      LAYER M4 ;
      RECT 115.904 173.676 116.000 173.772 ;
    END
  END RW0_rdata[26]
  PIN RW0_rdata[27]
    DIRECTION OUTPUT ;
    USE SIGNAL ;
    SHAPE ABUTMENT ;
    PORT
      LAYER M5 ;
      RECT 68.364 293.904 68.460 294.000 ;
    END
  END RW0_rdata[27]
  PIN RW0_rdata[28]
    DIRECTION OUTPUT ;
    USE SIGNAL ;
    SHAPE ABUTMENT ;
    PORT
      LAYER M5 ;
      RECT 69.324 0.000 69.420 0.096 ;
    END
  END RW0_rdata[28]
  PIN RW0_rdata[29]
    DIRECTION OUTPUT ;
    USE SIGNAL ;
    SHAPE ABUTMENT ;
    PORT
      LAYER M4 ;
      RECT 0.000 177.756 0.096 177.852 ;
    END
  END RW0_rdata[29]
  PIN RW0_rdata[30]
    DIRECTION OUTPUT ;
    USE SIGNAL ;
    SHAPE ABUTMENT ;
    PORT
      LAYER M4 ;
      RECT 115.904 177.756 116.000 177.852 ;
    END
  END RW0_rdata[30]
  PIN RW0_rdata[31]
    DIRECTION OUTPUT ;
    USE SIGNAL ;
    SHAPE ABUTMENT ;
    PORT
      LAYER M5 ;
      RECT 69.996 293.904 70.092 294.000 ;
    END
  END RW0_rdata[31]
  PIN RW0_rdata[32]
    DIRECTION OUTPUT ;
    USE SIGNAL ;
    SHAPE ABUTMENT ;
    PORT
      LAYER M5 ;
      RECT 70.956 0.000 71.052 0.096 ;
    END
  END RW0_rdata[32]
  PIN RW0_rdata[33]
    DIRECTION OUTPUT ;
    USE SIGNAL ;
    SHAPE ABUTMENT ;
    PORT
      LAYER M4 ;
      RECT 0.000 181.884 0.096 181.980 ;
    END
  END RW0_rdata[33]
  PIN RW0_rdata[34]
    DIRECTION OUTPUT ;
    USE SIGNAL ;
    SHAPE ABUTMENT ;
    PORT
      LAYER M4 ;
      RECT 115.904 181.884 116.000 181.980 ;
    END
  END RW0_rdata[34]
  PIN RW0_rdata[35]
    DIRECTION OUTPUT ;
    USE SIGNAL ;
    SHAPE ABUTMENT ;
    PORT
      LAYER M5 ;
      RECT 71.580 293.904 71.676 294.000 ;
    END
  END RW0_rdata[35]
  PIN RW0_rdata[36]
    DIRECTION OUTPUT ;
    USE SIGNAL ;
    SHAPE ABUTMENT ;
    PORT
      LAYER M5 ;
      RECT 72.588 0.000 72.684 0.096 ;
    END
  END RW0_rdata[36]
  PIN RW0_rdata[37]
    DIRECTION OUTPUT ;
    USE SIGNAL ;
    SHAPE ABUTMENT ;
    PORT
      LAYER M4 ;
      RECT 0.000 186.012 0.096 186.108 ;
    END
  END RW0_rdata[37]
  PIN RW0_rdata[38]
    DIRECTION OUTPUT ;
    USE SIGNAL ;
    SHAPE ABUTMENT ;
    PORT
      LAYER M4 ;
      RECT 115.904 186.012 116.000 186.108 ;
    END
  END RW0_rdata[38]
  PIN RW0_rdata[39]
    DIRECTION OUTPUT ;
    USE SIGNAL ;
    SHAPE ABUTMENT ;
    PORT
      LAYER M5 ;
      RECT 73.212 293.904 73.308 294.000 ;
    END
  END RW0_rdata[39]
  PIN RW0_rdata[40]
    DIRECTION OUTPUT ;
    USE SIGNAL ;
    SHAPE ABUTMENT ;
    PORT
      LAYER M5 ;
      RECT 74.220 0.000 74.316 0.096 ;
    END
  END RW0_rdata[40]
  PIN RW0_rdata[41]
    DIRECTION OUTPUT ;
    USE SIGNAL ;
    SHAPE ABUTMENT ;
    PORT
      LAYER M4 ;
      RECT 0.000 190.092 0.096 190.188 ;
    END
  END RW0_rdata[41]
  PIN RW0_rdata[42]
    DIRECTION OUTPUT ;
    USE SIGNAL ;
    SHAPE ABUTMENT ;
    PORT
      LAYER M4 ;
      RECT 115.904 190.092 116.000 190.188 ;
    END
  END RW0_rdata[42]
  PIN RW0_rdata[43]
    DIRECTION OUTPUT ;
    USE SIGNAL ;
    SHAPE ABUTMENT ;
    PORT
      LAYER M5 ;
      RECT 74.796 293.904 74.892 294.000 ;
    END
  END RW0_rdata[43]
  PIN RW0_rdata[44]
    DIRECTION OUTPUT ;
    USE SIGNAL ;
    SHAPE ABUTMENT ;
    PORT
      LAYER M5 ;
      RECT 75.852 0.000 75.948 0.096 ;
    END
  END RW0_rdata[44]
  PIN RW0_rdata[45]
    DIRECTION OUTPUT ;
    USE SIGNAL ;
    SHAPE ABUTMENT ;
    PORT
      LAYER M4 ;
      RECT 0.000 194.220 0.096 194.316 ;
    END
  END RW0_rdata[45]
  PIN RW0_rdata[46]
    DIRECTION OUTPUT ;
    USE SIGNAL ;
    SHAPE ABUTMENT ;
    PORT
      LAYER M4 ;
      RECT 115.904 194.220 116.000 194.316 ;
    END
  END RW0_rdata[46]
  PIN RW0_rdata[47]
    DIRECTION OUTPUT ;
    USE SIGNAL ;
    SHAPE ABUTMENT ;
    PORT
      LAYER M5 ;
      RECT 76.428 293.904 76.524 294.000 ;
    END
  END RW0_rdata[47]
  PIN RW0_rdata[48]
    DIRECTION OUTPUT ;
    USE SIGNAL ;
    SHAPE ABUTMENT ;
    PORT
      LAYER M5 ;
      RECT 77.484 0.000 77.580 0.096 ;
    END
  END RW0_rdata[48]
  PIN RW0_rdata[49]
    DIRECTION OUTPUT ;
    USE SIGNAL ;
    SHAPE ABUTMENT ;
    PORT
      LAYER M4 ;
      RECT 0.000 198.348 0.096 198.444 ;
    END
  END RW0_rdata[49]
  PIN RW0_rdata[50]
    DIRECTION OUTPUT ;
    USE SIGNAL ;
    SHAPE ABUTMENT ;
    PORT
      LAYER M4 ;
      RECT 115.904 198.348 116.000 198.444 ;
    END
  END RW0_rdata[50]
  PIN RW0_rdata[51]
    DIRECTION OUTPUT ;
    USE SIGNAL ;
    SHAPE ABUTMENT ;
    PORT
      LAYER M5 ;
      RECT 78.012 293.904 78.108 294.000 ;
    END
  END RW0_rdata[51]
  PIN RW0_rdata[52]
    DIRECTION OUTPUT ;
    USE SIGNAL ;
    SHAPE ABUTMENT ;
    PORT
      LAYER M5 ;
      RECT 79.116 0.000 79.212 0.096 ;
    END
  END RW0_rdata[52]
  PIN RW0_rdata[53]
    DIRECTION OUTPUT ;
    USE SIGNAL ;
    SHAPE ABUTMENT ;
    PORT
      LAYER M4 ;
      RECT 0.000 202.428 0.096 202.524 ;
    END
  END RW0_rdata[53]
  PIN RW0_rdata[54]
    DIRECTION OUTPUT ;
    USE SIGNAL ;
    SHAPE ABUTMENT ;
    PORT
      LAYER M4 ;
      RECT 115.904 202.428 116.000 202.524 ;
    END
  END RW0_rdata[54]
  PIN RW0_rdata[55]
    DIRECTION OUTPUT ;
    USE SIGNAL ;
    SHAPE ABUTMENT ;
    PORT
      LAYER M5 ;
      RECT 79.596 293.904 79.692 294.000 ;
    END
  END RW0_rdata[55]
  PIN RW0_rdata[56]
    DIRECTION OUTPUT ;
    USE SIGNAL ;
    SHAPE ABUTMENT ;
    PORT
      LAYER M5 ;
      RECT 80.748 0.000 80.844 0.096 ;
    END
  END RW0_rdata[56]
  PIN RW0_rdata[57]
    DIRECTION OUTPUT ;
    USE SIGNAL ;
    SHAPE ABUTMENT ;
    PORT
      LAYER M4 ;
      RECT 0.000 206.556 0.096 206.652 ;
    END
  END RW0_rdata[57]
  PIN RW0_rdata[58]
    DIRECTION OUTPUT ;
    USE SIGNAL ;
    SHAPE ABUTMENT ;
    PORT
      LAYER M4 ;
      RECT 115.904 206.556 116.000 206.652 ;
    END
  END RW0_rdata[58]
  PIN RW0_rdata[59]
    DIRECTION OUTPUT ;
    USE SIGNAL ;
    SHAPE ABUTMENT ;
    PORT
      LAYER M5 ;
      RECT 81.228 293.904 81.324 294.000 ;
    END
  END RW0_rdata[59]
  PIN RW0_rdata[60]
    DIRECTION OUTPUT ;
    USE SIGNAL ;
    SHAPE ABUTMENT ;
    PORT
      LAYER M5 ;
      RECT 82.380 0.000 82.476 0.096 ;
    END
  END RW0_rdata[60]
  PIN RW0_rdata[61]
    DIRECTION OUTPUT ;
    USE SIGNAL ;
    SHAPE ABUTMENT ;
    PORT
      LAYER M4 ;
      RECT 0.000 210.684 0.096 210.780 ;
    END
  END RW0_rdata[61]
  PIN RW0_rdata[62]
    DIRECTION OUTPUT ;
    USE SIGNAL ;
    SHAPE ABUTMENT ;
    PORT
      LAYER M4 ;
      RECT 115.904 210.684 116.000 210.780 ;
    END
  END RW0_rdata[62]
  PIN RW0_rdata[63]
    DIRECTION OUTPUT ;
    USE SIGNAL ;
    SHAPE ABUTMENT ;
    PORT
      LAYER M5 ;
      RECT 82.812 293.904 82.908 294.000 ;
    END
  END RW0_rdata[63]
  PIN RW0_rdata[64]
    DIRECTION OUTPUT ;
    USE SIGNAL ;
    SHAPE ABUTMENT ;
    PORT
      LAYER M5 ;
      RECT 84.012 0.000 84.108 0.096 ;
    END
  END RW0_rdata[64]
  PIN RW0_rdata[65]
    DIRECTION OUTPUT ;
    USE SIGNAL ;
    SHAPE ABUTMENT ;
    PORT
      LAYER M4 ;
      RECT 0.000 214.764 0.096 214.860 ;
    END
  END RW0_rdata[65]
  PIN RW0_rdata[66]
    DIRECTION OUTPUT ;
    USE SIGNAL ;
    SHAPE ABUTMENT ;
    PORT
      LAYER M4 ;
      RECT 115.904 214.764 116.000 214.860 ;
    END
  END RW0_rdata[66]
  PIN RW0_rdata[67]
    DIRECTION OUTPUT ;
    USE SIGNAL ;
    SHAPE ABUTMENT ;
    PORT
      LAYER M5 ;
      RECT 84.444 293.904 84.540 294.000 ;
    END
  END RW0_rdata[67]
  PIN RW0_rdata[68]
    DIRECTION OUTPUT ;
    USE SIGNAL ;
    SHAPE ABUTMENT ;
    PORT
      LAYER M5 ;
      RECT 85.644 0.000 85.740 0.096 ;
    END
  END RW0_rdata[68]
  PIN RW0_rdata[69]
    DIRECTION OUTPUT ;
    USE SIGNAL ;
    SHAPE ABUTMENT ;
    PORT
      LAYER M4 ;
      RECT 0.000 218.892 0.096 218.988 ;
    END
  END RW0_rdata[69]
  PIN RW0_rdata[70]
    DIRECTION OUTPUT ;
    USE SIGNAL ;
    SHAPE ABUTMENT ;
    PORT
      LAYER M4 ;
      RECT 115.904 218.892 116.000 218.988 ;
    END
  END RW0_rdata[70]
  PIN RW0_rdata[71]
    DIRECTION OUTPUT ;
    USE SIGNAL ;
    SHAPE ABUTMENT ;
    PORT
      LAYER M5 ;
      RECT 86.028 293.904 86.124 294.000 ;
    END
  END RW0_rdata[71]
  PIN RW0_rdata[72]
    DIRECTION OUTPUT ;
    USE SIGNAL ;
    SHAPE ABUTMENT ;
    PORT
      LAYER M5 ;
      RECT 87.228 0.000 87.324 0.096 ;
    END
  END RW0_rdata[72]
  PIN RW0_rdata[73]
    DIRECTION OUTPUT ;
    USE SIGNAL ;
    SHAPE ABUTMENT ;
    PORT
      LAYER M4 ;
      RECT 0.000 223.020 0.096 223.116 ;
    END
  END RW0_rdata[73]
  PIN RW0_rdata[74]
    DIRECTION OUTPUT ;
    USE SIGNAL ;
    SHAPE ABUTMENT ;
    PORT
      LAYER M4 ;
      RECT 115.904 223.020 116.000 223.116 ;
    END
  END RW0_rdata[74]
  PIN RW0_rdata[75]
    DIRECTION OUTPUT ;
    USE SIGNAL ;
    SHAPE ABUTMENT ;
    PORT
      LAYER M5 ;
      RECT 87.660 293.904 87.756 294.000 ;
    END
  END RW0_rdata[75]
  PIN RW0_rdata[76]
    DIRECTION OUTPUT ;
    USE SIGNAL ;
    SHAPE ABUTMENT ;
    PORT
      LAYER M5 ;
      RECT 88.860 0.000 88.956 0.096 ;
    END
  END RW0_rdata[76]
  PIN RW0_rdata[77]
    DIRECTION OUTPUT ;
    USE SIGNAL ;
    SHAPE ABUTMENT ;
    PORT
      LAYER M4 ;
      RECT 0.000 227.100 0.096 227.196 ;
    END
  END RW0_rdata[77]
  PIN RW0_rdata[78]
    DIRECTION OUTPUT ;
    USE SIGNAL ;
    SHAPE ABUTMENT ;
    PORT
      LAYER M4 ;
      RECT 115.904 227.100 116.000 227.196 ;
    END
  END RW0_rdata[78]
  PIN RW0_rdata[79]
    DIRECTION OUTPUT ;
    USE SIGNAL ;
    SHAPE ABUTMENT ;
    PORT
      LAYER M5 ;
      RECT 89.244 293.904 89.340 294.000 ;
    END
  END RW0_rdata[79]
  PIN RW0_rdata[80]
    DIRECTION OUTPUT ;
    USE SIGNAL ;
    SHAPE ABUTMENT ;
    PORT
      LAYER M5 ;
      RECT 90.492 0.000 90.588 0.096 ;
    END
  END RW0_rdata[80]
  PIN RW0_rdata[81]
    DIRECTION OUTPUT ;
    USE SIGNAL ;
    SHAPE ABUTMENT ;
    PORT
      LAYER M4 ;
      RECT 0.000 231.228 0.096 231.324 ;
    END
  END RW0_rdata[81]
  PIN RW0_rdata[82]
    DIRECTION OUTPUT ;
    USE SIGNAL ;
    SHAPE ABUTMENT ;
    PORT
      LAYER M4 ;
      RECT 115.904 231.228 116.000 231.324 ;
    END
  END RW0_rdata[82]
  PIN RW0_rdata[83]
    DIRECTION OUTPUT ;
    USE SIGNAL ;
    SHAPE ABUTMENT ;
    PORT
      LAYER M5 ;
      RECT 90.828 293.904 90.924 294.000 ;
    END
  END RW0_rdata[83]
  PIN RW0_rdata[84]
    DIRECTION OUTPUT ;
    USE SIGNAL ;
    SHAPE ABUTMENT ;
    PORT
      LAYER M5 ;
      RECT 92.124 0.000 92.220 0.096 ;
    END
  END RW0_rdata[84]
  PIN RW0_rdata[85]
    DIRECTION OUTPUT ;
    USE SIGNAL ;
    SHAPE ABUTMENT ;
    PORT
      LAYER M4 ;
      RECT 0.000 235.356 0.096 235.452 ;
    END
  END RW0_rdata[85]
  PIN RW0_rdata[86]
    DIRECTION OUTPUT ;
    USE SIGNAL ;
    SHAPE ABUTMENT ;
    PORT
      LAYER M4 ;
      RECT 115.904 235.356 116.000 235.452 ;
    END
  END RW0_rdata[86]
  PIN RW0_rdata[87]
    DIRECTION OUTPUT ;
    USE SIGNAL ;
    SHAPE ABUTMENT ;
    PORT
      LAYER M5 ;
      RECT 92.460 293.904 92.556 294.000 ;
    END
  END RW0_rdata[87]
  PIN RW0_rdata[88]
    DIRECTION OUTPUT ;
    USE SIGNAL ;
    SHAPE ABUTMENT ;
    PORT
      LAYER M5 ;
      RECT 93.756 0.000 93.852 0.096 ;
    END
  END RW0_rdata[88]
  PIN RW0_rdata[89]
    DIRECTION OUTPUT ;
    USE SIGNAL ;
    SHAPE ABUTMENT ;
    PORT
      LAYER M4 ;
      RECT 0.000 239.436 0.096 239.532 ;
    END
  END RW0_rdata[89]
  PIN RW0_rdata[90]
    DIRECTION OUTPUT ;
    USE SIGNAL ;
    SHAPE ABUTMENT ;
    PORT
      LAYER M4 ;
      RECT 115.904 239.436 116.000 239.532 ;
    END
  END RW0_rdata[90]
  PIN RW0_rdata[91]
    DIRECTION OUTPUT ;
    USE SIGNAL ;
    SHAPE ABUTMENT ;
    PORT
      LAYER M5 ;
      RECT 94.044 293.904 94.140 294.000 ;
    END
  END RW0_rdata[91]
  PIN RW0_rdata[92]
    DIRECTION OUTPUT ;
    USE SIGNAL ;
    SHAPE ABUTMENT ;
    PORT
      LAYER M5 ;
      RECT 95.388 0.000 95.484 0.096 ;
    END
  END RW0_rdata[92]
  PIN RW0_rdata[93]
    DIRECTION OUTPUT ;
    USE SIGNAL ;
    SHAPE ABUTMENT ;
    PORT
      LAYER M4 ;
      RECT 0.000 243.564 0.096 243.660 ;
    END
  END RW0_rdata[93]
  PIN RW0_rdata[94]
    DIRECTION OUTPUT ;
    USE SIGNAL ;
    SHAPE ABUTMENT ;
    PORT
      LAYER M4 ;
      RECT 115.904 243.564 116.000 243.660 ;
    END
  END RW0_rdata[94]
  PIN RW0_rdata[95]
    DIRECTION OUTPUT ;
    USE SIGNAL ;
    SHAPE ABUTMENT ;
    PORT
      LAYER M5 ;
      RECT 95.676 293.904 95.772 294.000 ;
    END
  END RW0_rdata[95]
  PIN RW0_rdata[96]
    DIRECTION OUTPUT ;
    USE SIGNAL ;
    SHAPE ABUTMENT ;
    PORT
      LAYER M5 ;
      RECT 97.020 0.000 97.116 0.096 ;
    END
  END RW0_rdata[96]
  PIN RW0_rdata[97]
    DIRECTION OUTPUT ;
    USE SIGNAL ;
    SHAPE ABUTMENT ;
    PORT
      LAYER M4 ;
      RECT 0.000 247.692 0.096 247.788 ;
    END
  END RW0_rdata[97]
  PIN RW0_rdata[98]
    DIRECTION OUTPUT ;
    USE SIGNAL ;
    SHAPE ABUTMENT ;
    PORT
      LAYER M4 ;
      RECT 115.904 247.692 116.000 247.788 ;
    END
  END RW0_rdata[98]
  PIN RW0_rdata[99]
    DIRECTION OUTPUT ;
    USE SIGNAL ;
    SHAPE ABUTMENT ;
    PORT
      LAYER M5 ;
      RECT 97.260 293.904 97.356 294.000 ;
    END
  END RW0_rdata[99]
  PIN RW0_rdata[100]
    DIRECTION OUTPUT ;
    USE SIGNAL ;
    SHAPE ABUTMENT ;
    PORT
      LAYER M5 ;
      RECT 98.652 0.000 98.748 0.096 ;
    END
  END RW0_rdata[100]
  PIN RW0_rdata[101]
    DIRECTION OUTPUT ;
    USE SIGNAL ;
    SHAPE ABUTMENT ;
    PORT
      LAYER M4 ;
      RECT 0.000 251.772 0.096 251.868 ;
    END
  END RW0_rdata[101]
  PIN RW0_rdata[102]
    DIRECTION OUTPUT ;
    USE SIGNAL ;
    SHAPE ABUTMENT ;
    PORT
      LAYER M4 ;
      RECT 115.904 251.772 116.000 251.868 ;
    END
  END RW0_rdata[102]
  PIN RW0_rdata[103]
    DIRECTION OUTPUT ;
    USE SIGNAL ;
    SHAPE ABUTMENT ;
    PORT
      LAYER M5 ;
      RECT 98.892 293.904 98.988 294.000 ;
    END
  END RW0_rdata[103]
  PIN RW0_rdata[104]
    DIRECTION OUTPUT ;
    USE SIGNAL ;
    SHAPE ABUTMENT ;
    PORT
      LAYER M5 ;
      RECT 100.284 0.000 100.380 0.096 ;
    END
  END RW0_rdata[104]
  PIN RW0_rdata[105]
    DIRECTION OUTPUT ;
    USE SIGNAL ;
    SHAPE ABUTMENT ;
    PORT
      LAYER M4 ;
      RECT 0.000 255.900 0.096 255.996 ;
    END
  END RW0_rdata[105]
  PIN RW0_rdata[106]
    DIRECTION OUTPUT ;
    USE SIGNAL ;
    SHAPE ABUTMENT ;
    PORT
      LAYER M4 ;
      RECT 115.904 255.900 116.000 255.996 ;
    END
  END RW0_rdata[106]
  PIN RW0_rdata[107]
    DIRECTION OUTPUT ;
    USE SIGNAL ;
    SHAPE ABUTMENT ;
    PORT
      LAYER M5 ;
      RECT 100.476 293.904 100.572 294.000 ;
    END
  END RW0_rdata[107]
  PIN RW0_rdata[108]
    DIRECTION OUTPUT ;
    USE SIGNAL ;
    SHAPE ABUTMENT ;
    PORT
      LAYER M5 ;
      RECT 101.916 0.000 102.012 0.096 ;
    END
  END RW0_rdata[108]
  PIN RW0_rdata[109]
    DIRECTION OUTPUT ;
    USE SIGNAL ;
    SHAPE ABUTMENT ;
    PORT
      LAYER M4 ;
      RECT 0.000 260.028 0.096 260.124 ;
    END
  END RW0_rdata[109]
  PIN RW0_rdata[110]
    DIRECTION OUTPUT ;
    USE SIGNAL ;
    SHAPE ABUTMENT ;
    PORT
      LAYER M4 ;
      RECT 115.904 260.028 116.000 260.124 ;
    END
  END RW0_rdata[110]
  PIN RW0_rdata[111]
    DIRECTION OUTPUT ;
    USE SIGNAL ;
    SHAPE ABUTMENT ;
    PORT
      LAYER M5 ;
      RECT 102.108 293.904 102.204 294.000 ;
    END
  END RW0_rdata[111]
  PIN RW0_rdata[112]
    DIRECTION OUTPUT ;
    USE SIGNAL ;
    SHAPE ABUTMENT ;
    PORT
      LAYER M5 ;
      RECT 103.548 0.000 103.644 0.096 ;
    END
  END RW0_rdata[112]
  PIN RW0_rdata[113]
    DIRECTION OUTPUT ;
    USE SIGNAL ;
    SHAPE ABUTMENT ;
    PORT
      LAYER M4 ;
      RECT 0.000 264.108 0.096 264.204 ;
    END
  END RW0_rdata[113]
  PIN RW0_rdata[114]
    DIRECTION OUTPUT ;
    USE SIGNAL ;
    SHAPE ABUTMENT ;
    PORT
      LAYER M4 ;
      RECT 115.904 264.108 116.000 264.204 ;
    END
  END RW0_rdata[114]
  PIN RW0_rdata[115]
    DIRECTION OUTPUT ;
    USE SIGNAL ;
    SHAPE ABUTMENT ;
    PORT
      LAYER M5 ;
      RECT 103.692 293.904 103.788 294.000 ;
    END
  END RW0_rdata[115]
  PIN RW0_rdata[116]
    DIRECTION OUTPUT ;
    USE SIGNAL ;
    SHAPE ABUTMENT ;
    PORT
      LAYER M5 ;
      RECT 105.180 0.000 105.276 0.096 ;
    END
  END RW0_rdata[116]
  PIN RW0_rdata[117]
    DIRECTION OUTPUT ;
    USE SIGNAL ;
    SHAPE ABUTMENT ;
    PORT
      LAYER M4 ;
      RECT 0.000 268.236 0.096 268.332 ;
    END
  END RW0_rdata[117]
  PIN RW0_rdata[118]
    DIRECTION OUTPUT ;
    USE SIGNAL ;
    SHAPE ABUTMENT ;
    PORT
      LAYER M4 ;
      RECT 115.904 268.236 116.000 268.332 ;
    END
  END RW0_rdata[118]
  PIN RW0_rdata[119]
    DIRECTION OUTPUT ;
    USE SIGNAL ;
    SHAPE ABUTMENT ;
    PORT
      LAYER M5 ;
      RECT 105.276 293.904 105.372 294.000 ;
    END
  END RW0_rdata[119]
  PIN RW0_rdata[120]
    DIRECTION OUTPUT ;
    USE SIGNAL ;
    SHAPE ABUTMENT ;
    PORT
      LAYER M5 ;
      RECT 106.764 0.000 106.860 0.096 ;
    END
  END RW0_rdata[120]
  PIN RW0_rdata[121]
    DIRECTION OUTPUT ;
    USE SIGNAL ;
    SHAPE ABUTMENT ;
    PORT
      LAYER M4 ;
      RECT 0.000 272.364 0.096 272.460 ;
    END
  END RW0_rdata[121]
  PIN RW0_rdata[122]
    DIRECTION OUTPUT ;
    USE SIGNAL ;
    SHAPE ABUTMENT ;
    PORT
      LAYER M4 ;
      RECT 115.904 272.364 116.000 272.460 ;
    END
  END RW0_rdata[122]
  PIN RW0_rdata[123]
    DIRECTION OUTPUT ;
    USE SIGNAL ;
    SHAPE ABUTMENT ;
    PORT
      LAYER M5 ;
      RECT 106.908 293.904 107.004 294.000 ;
    END
  END RW0_rdata[123]
  PIN RW0_rdata[124]
    DIRECTION OUTPUT ;
    USE SIGNAL ;
    SHAPE ABUTMENT ;
    PORT
      LAYER M5 ;
      RECT 108.396 0.000 108.492 0.096 ;
    END
  END RW0_rdata[124]
  PIN RW0_rdata[125]
    DIRECTION OUTPUT ;
    USE SIGNAL ;
    SHAPE ABUTMENT ;
    PORT
      LAYER M4 ;
      RECT 0.000 276.444 0.096 276.540 ;
    END
  END RW0_rdata[125]
  PIN RW0_rdata[126]
    DIRECTION OUTPUT ;
    USE SIGNAL ;
    SHAPE ABUTMENT ;
    PORT
      LAYER M4 ;
      RECT 115.904 276.444 116.000 276.540 ;
    END
  END RW0_rdata[126]
  PIN RW0_rdata[127]
    DIRECTION OUTPUT ;
    USE SIGNAL ;
    SHAPE ABUTMENT ;
    PORT
      LAYER M5 ;
      RECT 108.492 293.904 108.588 294.000 ;
    END
  END RW0_rdata[127]
  PIN RW0_wmask[0]
    DIRECTION INPUT ;
    USE SIGNAL ;
    SHAPE ABUTMENT ;
    PORT
      LAYER M5 ;
      RECT 110.028 0.000 110.124 0.096 ;
    END
  END RW0_wmask[0]
  PIN RW0_wmask[1]
    DIRECTION INPUT ;
    USE SIGNAL ;
    SHAPE ABUTMENT ;
    PORT
      LAYER M4 ;
      RECT 0.000 280.572 0.096 280.668 ;
    END
  END RW0_wmask[1]
  PIN RW0_wmask[2]
    DIRECTION INPUT ;
    USE SIGNAL ;
    SHAPE ABUTMENT ;
    PORT
      LAYER M4 ;
      RECT 115.904 280.572 116.000 280.668 ;
    END
  END RW0_wmask[2]
  PIN RW0_wmask[3]
    DIRECTION INPUT ;
    USE SIGNAL ;
    SHAPE ABUTMENT ;
    PORT
      LAYER M5 ;
      RECT 110.124 293.904 110.220 294.000 ;
    END
  END RW0_wmask[3]
  PIN RW0_wmask[4]
    DIRECTION INPUT ;
    USE SIGNAL ;
    SHAPE ABUTMENT ;
    PORT
      LAYER M5 ;
      RECT 111.660 0.000 111.756 0.096 ;
    END
  END RW0_wmask[4]
  PIN RW0_wmask[5]
    DIRECTION INPUT ;
    USE SIGNAL ;
    SHAPE ABUTMENT ;
    PORT
      LAYER M4 ;
      RECT 0.000 284.700 0.096 284.796 ;
    END
  END RW0_wmask[5]
  PIN RW0_wmask[6]
    DIRECTION INPUT ;
    USE SIGNAL ;
    SHAPE ABUTMENT ;
    PORT
      LAYER M4 ;
      RECT 115.904 284.700 116.000 284.796 ;
    END
  END RW0_wmask[6]
  PIN RW0_wmask[7]
    DIRECTION INPUT ;
    USE SIGNAL ;
    SHAPE ABUTMENT ;
    PORT
      LAYER M5 ;
      RECT 111.708 293.904 111.804 294.000 ;
    END
  END RW0_wmask[7]
  PIN RW0_wmask[8]
    DIRECTION INPUT ;
    USE SIGNAL ;
    SHAPE ABUTMENT ;
    PORT
      LAYER M5 ;
      RECT 113.292 0.000 113.388 0.096 ;
    END
  END RW0_wmask[8]
  PIN RW0_wmask[9]
    DIRECTION INPUT ;
    USE SIGNAL ;
    SHAPE ABUTMENT ;
    PORT
      LAYER M4 ;
      RECT 0.000 288.780 0.096 288.876 ;
    END
  END RW0_wmask[9]
  PIN RW0_wmask[10]
    DIRECTION INPUT ;
    USE SIGNAL ;
    SHAPE ABUTMENT ;
    PORT
      LAYER M4 ;
      RECT 115.904 288.780 116.000 288.876 ;
    END
  END RW0_wmask[10]
  PIN RW0_wmask[11]
    DIRECTION INPUT ;
    USE SIGNAL ;
    SHAPE ABUTMENT ;
    PORT
      LAYER M5 ;
      RECT 113.340 293.904 113.436 294.000 ;
    END
  END RW0_wmask[11]
  PIN RW0_wmask[12]
    DIRECTION INPUT ;
    USE SIGNAL ;
    SHAPE ABUTMENT ;
    PORT
      LAYER M5 ;
      RECT 114.924 0.000 115.020 0.096 ;
    END
  END RW0_wmask[12]
  PIN RW0_wmask[13]
    DIRECTION INPUT ;
    USE SIGNAL ;
    SHAPE ABUTMENT ;
    PORT
      LAYER M4 ;
      RECT 0.000 292.908 0.096 293.004 ;
    END
  END RW0_wmask[13]
  PIN RW0_wmask[14]
    DIRECTION INPUT ;
    USE SIGNAL ;
    SHAPE ABUTMENT ;
    PORT
      LAYER M4 ;
      RECT 115.904 292.908 116.000 293.004 ;
    END
  END RW0_wmask[14]
  PIN RW0_wmask[15]
    DIRECTION INPUT ;
    USE SIGNAL ;
    SHAPE ABUTMENT ;
    PORT
      LAYER M5 ;
      RECT 114.924 293.904 115.020 294.000 ;
    END
  END RW0_wmask[15]
END mem_ext

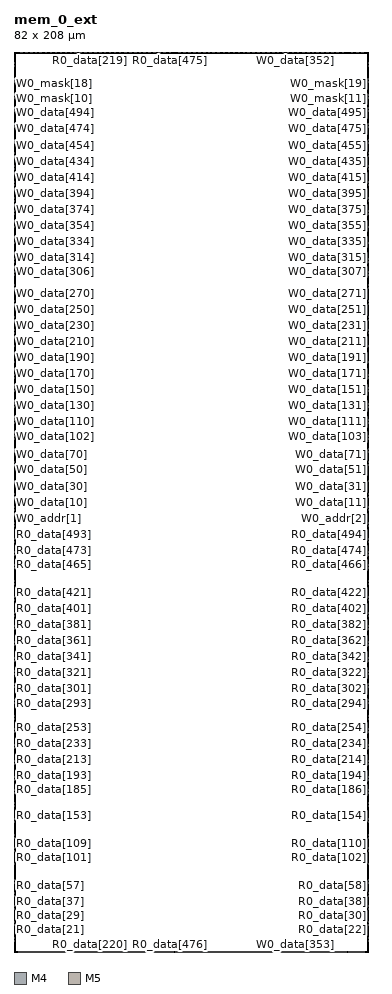
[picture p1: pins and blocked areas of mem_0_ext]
MACRO mem_0_ext
  FOREIGN mem_0_ext 0 0 ;
  CLASS BLOCK ;
  ORIGIN 0 0 ;
  SYMMETRY X Y R90 ;
  SIZE 82.000 BY 208.000 ;
  SITE asap7sc7p5t ;
  PIN R0_addr[0]
    DIRECTION INPUT ;
    USE SIGNAL ;
    SHAPE ABUTMENT ;
    PORT
      LAYER M4 ;
      RECT 0.000 0.972 0.096 1.068 ;
    END
  END R0_addr[0]
  PIN R0_addr[1]
    DIRECTION INPUT ;
    USE SIGNAL ;
    SHAPE ABUTMENT ;
    PORT
      LAYER M4 ;
      RECT 81.904 0.972 82.000 1.068 ;
    END
  END R0_addr[1]
  PIN R0_addr[2]
    DIRECTION INPUT ;
    USE SIGNAL ;
    SHAPE ABUTMENT ;
    PORT
      LAYER M5 ;
      RECT 0.972 207.904 1.068 208.000 ;
    END
  END R0_addr[2]
  PIN R0_addr[3]
    DIRECTION INPUT ;
    USE SIGNAL ;
    SHAPE ABUTMENT ;
    PORT
      LAYER M5 ;
      RECT 0.972 0.000 1.068 0.096 ;
    END
  END R0_addr[3]
  PIN R0_addr[4]
    DIRECTION INPUT ;
    USE SIGNAL ;
    SHAPE ABUTMENT ;
    PORT
      LAYER M4 ;
      RECT 0.000 1.692 0.096 1.788 ;
    END
  END R0_addr[4]
  PIN R0_addr[5]
    DIRECTION INPUT ;
    USE SIGNAL ;
    SHAPE ABUTMENT ;
    PORT
      LAYER M4 ;
      RECT 81.904 1.692 82.000 1.788 ;
    END
  END R0_addr[5]
  PIN R0_addr[6]
    DIRECTION INPUT ;
    USE SIGNAL ;
    SHAPE ABUTMENT ;
    PORT
      LAYER M5 ;
      RECT 1.260 207.904 1.356 208.000 ;
    END
  END R0_addr[6]
  PIN R0_addr[7]
    DIRECTION INPUT ;
    USE SIGNAL ;
    SHAPE ABUTMENT ;
    PORT
      LAYER M5 ;
      RECT 1.260 0.000 1.356 0.096 ;
    END
  END R0_addr[7]
  PIN R0_addr[8]
    DIRECTION INPUT ;
    USE SIGNAL ;
    SHAPE ABUTMENT ;
    PORT
      LAYER M4 ;
      RECT 0.000 2.460 0.096 2.556 ;
    END
  END R0_addr[8]
  PIN R0_en
    DIRECTION INPUT ;
    USE SIGNAL ;
    SHAPE ABUTMENT ;
    PORT
      LAYER M4 ;
      RECT 81.904 2.460 82.000 2.556 ;
    END
  END R0_en
  PIN R0_clk
    DIRECTION INPUT ;
    USE SIGNAL ;
    SHAPE ABUTMENT ;
    PORT
      LAYER M5 ;
      RECT 1.548 207.904 1.644 208.000 ;
    END
  END R0_clk
  PIN R0_data[0]
    DIRECTION OUTPUT ;
    USE SIGNAL ;
    SHAPE ABUTMENT ;
    PORT
      LAYER M5 ;
      RECT 1.548 0.000 1.644 0.096 ;
    END
  END R0_data[0]
  PIN R0_data[1]
    DIRECTION OUTPUT ;
    USE SIGNAL ;
    SHAPE ABUTMENT ;
    PORT
      LAYER M4 ;
      RECT 0.000 3.180 0.096 3.276 ;
    END
  END R0_data[1]
  PIN R0_data[2]
    DIRECTION OUTPUT ;
    USE SIGNAL ;
    SHAPE ABUTMENT ;
    PORT
      LAYER M4 ;
      RECT 81.904 3.180 82.000 3.276 ;
    END
  END R0_data[2]
  PIN R0_data[3]
    DIRECTION OUTPUT ;
    USE SIGNAL ;
    SHAPE ABUTMENT ;
    PORT
      LAYER M5 ;
      RECT 1.836 207.904 1.932 208.000 ;
    END
  END R0_data[3]
  PIN R0_data[4]
    DIRECTION OUTPUT ;
    USE SIGNAL ;
    SHAPE ABUTMENT ;
    PORT
      LAYER M5 ;
      RECT 1.836 0.000 1.932 0.096 ;
    END
  END R0_data[4]
  PIN R0_data[5]
    DIRECTION OUTPUT ;
    USE SIGNAL ;
    SHAPE ABUTMENT ;
    PORT
      LAYER M4 ;
      RECT 0.000 3.948 0.096 4.044 ;
    END
  END R0_data[5]
  PIN R0_data[6]
    DIRECTION OUTPUT ;
    USE SIGNAL ;
    SHAPE ABUTMENT ;
    PORT
      LAYER M4 ;
      RECT 81.904 3.948 82.000 4.044 ;
    END
  END R0_data[6]
  PIN R0_data[7]
    DIRECTION OUTPUT ;
    USE SIGNAL ;
    SHAPE ABUTMENT ;
    PORT
      LAYER M5 ;
      RECT 2.124 207.904 2.220 208.000 ;
    END
  END R0_data[7]
  PIN R0_data[8]
    DIRECTION OUTPUT ;
    USE SIGNAL ;
    SHAPE ABUTMENT ;
    PORT
      LAYER M5 ;
      RECT 2.124 0.000 2.220 0.096 ;
    END
  END R0_data[8]
  PIN R0_data[9]
    DIRECTION OUTPUT ;
    USE SIGNAL ;
    SHAPE ABUTMENT ;
    PORT
      LAYER M4 ;
      RECT 0.000 4.668 0.096 4.764 ;
    END
  END R0_data[9]
  PIN R0_data[10]
    DIRECTION OUTPUT ;
    USE SIGNAL ;
    SHAPE ABUTMENT ;
    PORT
      LAYER M4 ;
      RECT 81.904 4.668 82.000 4.764 ;
    END
  END R0_data[10]
  PIN R0_data[11]
    DIRECTION OUTPUT ;
    USE SIGNAL ;
    SHAPE ABUTMENT ;
    PORT
      LAYER M5 ;
      RECT 2.412 207.904 2.508 208.000 ;
    END
  END R0_data[11]
  PIN R0_data[12]
    DIRECTION OUTPUT ;
    USE SIGNAL ;
    SHAPE ABUTMENT ;
    PORT
      LAYER M5 ;
      RECT 2.412 0.000 2.508 0.096 ;
    END
  END R0_data[12]
  PIN R0_data[13]
    DIRECTION OUTPUT ;
    USE SIGNAL ;
    SHAPE ABUTMENT ;
    PORT
      LAYER M4 ;
      RECT 0.000 5.436 0.096 5.532 ;
    END
  END R0_data[13]
  PIN R0_data[14]
    DIRECTION OUTPUT ;
    USE SIGNAL ;
    SHAPE ABUTMENT ;
    PORT
      LAYER M4 ;
      RECT 81.904 5.436 82.000 5.532 ;
    END
  END R0_data[14]
  PIN R0_data[15]
    DIRECTION OUTPUT ;
    USE SIGNAL ;
    SHAPE ABUTMENT ;
    PORT
      LAYER M5 ;
      RECT 2.700 207.904 2.796 208.000 ;
    END
  END R0_data[15]
  PIN R0_data[16]
    DIRECTION OUTPUT ;
    USE SIGNAL ;
    SHAPE ABUTMENT ;
    PORT
      LAYER M5 ;
      RECT 2.700 0.000 2.796 0.096 ;
    END
  END R0_data[16]
  PIN R0_data[17]
    DIRECTION OUTPUT ;
    USE SIGNAL ;
    SHAPE ABUTMENT ;
    PORT
      LAYER M4 ;
      RECT 0.000 6.156 0.096 6.252 ;
    END
  END R0_data[17]
  PIN R0_data[18]
    DIRECTION OUTPUT ;
    USE SIGNAL ;
    SHAPE ABUTMENT ;
    PORT
      LAYER M4 ;
      RECT 81.904 6.156 82.000 6.252 ;
    END
  END R0_data[18]
  PIN R0_data[19]
    DIRECTION OUTPUT ;
    USE SIGNAL ;
    SHAPE ABUTMENT ;
    PORT
      LAYER M5 ;
      RECT 2.988 207.904 3.084 208.000 ;
    END
  END R0_data[19]
  PIN R0_data[20]
    DIRECTION OUTPUT ;
    USE SIGNAL ;
    SHAPE ABUTMENT ;
    PORT
      LAYER M5 ;
      RECT 2.988 0.000 3.084 0.096 ;
    END
  END R0_data[20]
  PIN R0_data[21]
    DIRECTION OUTPUT ;
    USE SIGNAL ;
    SHAPE ABUTMENT ;
    PORT
      LAYER M4 ;
      RECT 0.000 6.924 0.096 7.020 ;
    END
  END R0_data[21]
  PIN R0_data[22]
    DIRECTION OUTPUT ;
    USE SIGNAL ;
    SHAPE ABUTMENT ;
    PORT
      LAYER M4 ;
      RECT 81.904 6.924 82.000 7.020 ;
    END
  END R0_data[22]
  PIN R0_data[23]
    DIRECTION OUTPUT ;
    USE SIGNAL ;
    SHAPE ABUTMENT ;
    PORT
      LAYER M5 ;
      RECT 3.276 207.904 3.372 208.000 ;
    END
  END R0_data[23]
  PIN R0_data[24]
    DIRECTION OUTPUT ;
    USE SIGNAL ;
    SHAPE ABUTMENT ;
    PORT
      LAYER M5 ;
      RECT 3.276 0.000 3.372 0.096 ;
    END
  END R0_data[24]
  PIN R0_data[25]
    DIRECTION OUTPUT ;
    USE SIGNAL ;
    SHAPE ABUTMENT ;
    PORT
      LAYER M4 ;
      RECT 0.000 7.644 0.096 7.740 ;
    END
  END R0_data[25]
  PIN R0_data[26]
    DIRECTION OUTPUT ;
    USE SIGNAL ;
    SHAPE ABUTMENT ;
    PORT
      LAYER M4 ;
      RECT 81.904 7.644 82.000 7.740 ;
    END
  END R0_data[26]
  PIN R0_data[27]
    DIRECTION OUTPUT ;
    USE SIGNAL ;
    SHAPE ABUTMENT ;
    PORT
      LAYER M5 ;
      RECT 3.564 207.904 3.660 208.000 ;
    END
  END R0_data[27]
  PIN R0_data[28]
    DIRECTION OUTPUT ;
    USE SIGNAL ;
    SHAPE ABUTMENT ;
    PORT
      LAYER M5 ;
      RECT 3.564 0.000 3.660 0.096 ;
    END
  END R0_data[28]
  PIN R0_data[29]
    DIRECTION OUTPUT ;
    USE SIGNAL ;
    SHAPE ABUTMENT ;
    PORT
      LAYER M4 ;
      RECT 0.000 8.412 0.096 8.508 ;
    END
  END R0_data[29]
  PIN R0_data[30]
    DIRECTION OUTPUT ;
    USE SIGNAL ;
    SHAPE ABUTMENT ;
    PORT
      LAYER M4 ;
      RECT 81.904 8.412 82.000 8.508 ;
    END
  END R0_data[30]
  PIN R0_data[31]
    DIRECTION OUTPUT ;
    USE SIGNAL ;
    SHAPE ABUTMENT ;
    PORT
      LAYER M5 ;
      RECT 3.852 207.904 3.948 208.000 ;
    END
  END R0_data[31]
  PIN R0_data[32]
    DIRECTION OUTPUT ;
    USE SIGNAL ;
    SHAPE ABUTMENT ;
    PORT
      LAYER M5 ;
      RECT 3.852 0.000 3.948 0.096 ;
    END
  END R0_data[32]
  PIN R0_data[33]
    DIRECTION OUTPUT ;
    USE SIGNAL ;
    SHAPE ABUTMENT ;
    PORT
      LAYER M4 ;
      RECT 0.000 9.132 0.096 9.228 ;
    END
  END R0_data[33]
  PIN R0_data[34]
    DIRECTION OUTPUT ;
    USE SIGNAL ;
    SHAPE ABUTMENT ;
    PORT
      LAYER M4 ;
      RECT 81.904 9.132 82.000 9.228 ;
    END
  END R0_data[34]
  PIN R0_data[35]
    DIRECTION OUTPUT ;
    USE SIGNAL ;
    SHAPE ABUTMENT ;
    PORT
      LAYER M5 ;
      RECT 4.140 207.904 4.236 208.000 ;
    END
  END R0_data[35]
  PIN R0_data[36]
    DIRECTION OUTPUT ;
    USE SIGNAL ;
    SHAPE ABUTMENT ;
    PORT
      LAYER M5 ;
      RECT 4.140 0.000 4.236 0.096 ;
    END
  END R0_data[36]
  PIN R0_data[37]
    DIRECTION OUTPUT ;
    USE SIGNAL ;
    SHAPE ABUTMENT ;
    PORT
      LAYER M4 ;
      RECT 0.000 9.900 0.096 9.996 ;
    END
  END R0_data[37]
  PIN R0_data[38]
    DIRECTION OUTPUT ;
    USE SIGNAL ;
    SHAPE ABUTMENT ;
    PORT
      LAYER M4 ;
      RECT 81.904 9.900 82.000 9.996 ;
    END
  END R0_data[38]
  PIN R0_data[39]
    DIRECTION OUTPUT ;
    USE SIGNAL ;
    SHAPE ABUTMENT ;
    PORT
      LAYER M5 ;
      RECT 4.428 207.904 4.524 208.000 ;
    END
  END R0_data[39]
  PIN R0_data[40]
    DIRECTION OUTPUT ;
    USE SIGNAL ;
    SHAPE ABUTMENT ;
    PORT
      LAYER M5 ;
      RECT 4.428 0.000 4.524 0.096 ;
    END
  END R0_data[40]
  PIN R0_data[41]
    DIRECTION OUTPUT ;
    USE SIGNAL ;
    SHAPE ABUTMENT ;
    PORT
      LAYER M4 ;
      RECT 0.000 10.620 0.096 10.716 ;
    END
  END R0_data[41]
  PIN R0_data[42]
    DIRECTION OUTPUT ;
    USE SIGNAL ;
    SHAPE ABUTMENT ;
    PORT
      LAYER M4 ;
      RECT 81.904 10.620 82.000 10.716 ;
    END
  END R0_data[42]
  PIN R0_data[43]
    DIRECTION OUTPUT ;
    USE SIGNAL ;
    SHAPE ABUTMENT ;
    PORT
      LAYER M5 ;
      RECT 4.716 207.904 4.812 208.000 ;
    END
  END R0_data[43]
  PIN R0_data[44]
    DIRECTION OUTPUT ;
    USE SIGNAL ;
    SHAPE ABUTMENT ;
    PORT
      LAYER M5 ;
      RECT 4.716 0.000 4.812 0.096 ;
    END
  END R0_data[44]
  PIN R0_data[45]
    DIRECTION OUTPUT ;
    USE SIGNAL ;
    SHAPE ABUTMENT ;
    PORT
      LAYER M4 ;
      RECT 0.000 11.388 0.096 11.484 ;
    END
  END R0_data[45]
  PIN R0_data[46]
    DIRECTION OUTPUT ;
    USE SIGNAL ;
    SHAPE ABUTMENT ;
    PORT
      LAYER M4 ;
      RECT 81.904 11.388 82.000 11.484 ;
    END
  END R0_data[46]
  PIN R0_data[47]
    DIRECTION OUTPUT ;
    USE SIGNAL ;
    SHAPE ABUTMENT ;
    PORT
      LAYER M5 ;
      RECT 5.052 207.904 5.148 208.000 ;
    END
  END R0_data[47]
  PIN R0_data[48]
    DIRECTION OUTPUT ;
    USE SIGNAL ;
    SHAPE ABUTMENT ;
    PORT
      LAYER M5 ;
      RECT 5.052 0.000 5.148 0.096 ;
    END
  END R0_data[48]
  PIN R0_data[49]
    DIRECTION OUTPUT ;
    USE SIGNAL ;
    SHAPE ABUTMENT ;
    PORT
      LAYER M4 ;
      RECT 0.000 12.108 0.096 12.204 ;
    END
  END R0_data[49]
  PIN R0_data[50]
    DIRECTION OUTPUT ;
    USE SIGNAL ;
    SHAPE ABUTMENT ;
    PORT
      LAYER M4 ;
      RECT 81.904 12.108 82.000 12.204 ;
    END
  END R0_data[50]
  PIN R0_data[51]
    DIRECTION OUTPUT ;
    USE SIGNAL ;
    SHAPE ABUTMENT ;
    PORT
      LAYER M5 ;
      RECT 5.340 207.904 5.436 208.000 ;
    END
  END R0_data[51]
  PIN R0_data[52]
    DIRECTION OUTPUT ;
    USE SIGNAL ;
    SHAPE ABUTMENT ;
    PORT
      LAYER M5 ;
      RECT 5.340 0.000 5.436 0.096 ;
    END
  END R0_data[52]
  PIN R0_data[53]
    DIRECTION OUTPUT ;
    USE SIGNAL ;
    SHAPE ABUTMENT ;
    PORT
      LAYER M4 ;
      RECT 0.000 12.876 0.096 12.972 ;
    END
  END R0_data[53]
  PIN R0_data[54]
    DIRECTION OUTPUT ;
    USE SIGNAL ;
    SHAPE ABUTMENT ;
    PORT
      LAYER M4 ;
      RECT 81.904 12.876 82.000 12.972 ;
    END
  END R0_data[54]
  PIN R0_data[55]
    DIRECTION OUTPUT ;
    USE SIGNAL ;
    SHAPE ABUTMENT ;
    PORT
      LAYER M5 ;
      RECT 5.628 207.904 5.724 208.000 ;
    END
  END R0_data[55]
  PIN R0_data[56]
    DIRECTION OUTPUT ;
    USE SIGNAL ;
    SHAPE ABUTMENT ;
    PORT
      LAYER M5 ;
      RECT 5.628 0.000 5.724 0.096 ;
    END
  END R0_data[56]
  PIN R0_data[57]
    DIRECTION OUTPUT ;
    USE SIGNAL ;
    SHAPE ABUTMENT ;
    PORT
      LAYER M4 ;
      RECT 0.000 13.596 0.096 13.692 ;
    END
  END R0_data[57]
  PIN R0_data[58]
    DIRECTION OUTPUT ;
    USE SIGNAL ;
    SHAPE ABUTMENT ;
    PORT
      LAYER M4 ;
      RECT 81.904 13.596 82.000 13.692 ;
    END
  END R0_data[58]
  PIN R0_data[59]
    DIRECTION OUTPUT ;
    USE SIGNAL ;
    SHAPE ABUTMENT ;
    PORT
      LAYER M5 ;
      RECT 5.916 207.904 6.012 208.000 ;
    END
  END R0_data[59]
  PIN R0_data[60]
    DIRECTION OUTPUT ;
    USE SIGNAL ;
    SHAPE ABUTMENT ;
    PORT
      LAYER M5 ;
      RECT 5.916 0.000 6.012 0.096 ;
    END
  END R0_data[60]
  PIN R0_data[61]
    DIRECTION OUTPUT ;
    USE SIGNAL ;
    SHAPE ABUTMENT ;
    PORT
      LAYER M4 ;
      RECT 0.000 14.364 0.096 14.460 ;
    END
  END R0_data[61]
  PIN R0_data[62]
    DIRECTION OUTPUT ;
    USE SIGNAL ;
    SHAPE ABUTMENT ;
    PORT
      LAYER M4 ;
      RECT 81.904 14.364 82.000 14.460 ;
    END
  END R0_data[62]
  PIN R0_data[63]
    DIRECTION OUTPUT ;
    USE SIGNAL ;
    SHAPE ABUTMENT ;
    PORT
      LAYER M5 ;
      RECT 6.204 207.904 6.300 208.000 ;
    END
  END R0_data[63]
  PIN R0_data[64]
    DIRECTION OUTPUT ;
    USE SIGNAL ;
    SHAPE ABUTMENT ;
    PORT
      LAYER M5 ;
      RECT 6.204 0.000 6.300 0.096 ;
    END
  END R0_data[64]
  PIN R0_data[65]
    DIRECTION OUTPUT ;
    USE SIGNAL ;
    SHAPE ABUTMENT ;
    PORT
      LAYER M4 ;
      RECT 0.000 15.084 0.096 15.180 ;
    END
  END R0_data[65]
  PIN R0_data[66]
    DIRECTION OUTPUT ;
    USE SIGNAL ;
    SHAPE ABUTMENT ;
    PORT
      LAYER M4 ;
      RECT 81.904 15.084 82.000 15.180 ;
    END
  END R0_data[66]
  PIN R0_data[67]
    DIRECTION OUTPUT ;
    USE SIGNAL ;
    SHAPE ABUTMENT ;
    PORT
      LAYER M5 ;
      RECT 6.492 207.904 6.588 208.000 ;
    END
  END R0_data[67]
  PIN R0_data[68]
    DIRECTION OUTPUT ;
    USE SIGNAL ;
    SHAPE ABUTMENT ;
    PORT
      LAYER M5 ;
      RECT 6.492 0.000 6.588 0.096 ;
    END
  END R0_data[68]
  PIN R0_data[69]
    DIRECTION OUTPUT ;
    USE SIGNAL ;
    SHAPE ABUTMENT ;
    PORT
      LAYER M4 ;
      RECT 0.000 15.852 0.096 15.948 ;
    END
  END R0_data[69]
  PIN R0_data[70]
    DIRECTION OUTPUT ;
    USE SIGNAL ;
    SHAPE ABUTMENT ;
    PORT
      LAYER M4 ;
      RECT 81.904 15.852 82.000 15.948 ;
    END
  END R0_data[70]
  PIN R0_data[71]
    DIRECTION OUTPUT ;
    USE SIGNAL ;
    SHAPE ABUTMENT ;
    PORT
      LAYER M5 ;
      RECT 6.780 207.904 6.876 208.000 ;
    END
  END R0_data[71]
  PIN R0_data[72]
    DIRECTION OUTPUT ;
    USE SIGNAL ;
    SHAPE ABUTMENT ;
    PORT
      LAYER M5 ;
      RECT 6.780 0.000 6.876 0.096 ;
    END
  END R0_data[72]
  PIN R0_data[73]
    DIRECTION OUTPUT ;
    USE SIGNAL ;
    SHAPE ABUTMENT ;
    PORT
      LAYER M4 ;
      RECT 0.000 16.572 0.096 16.668 ;
    END
  END R0_data[73]
  PIN R0_data[74]
    DIRECTION OUTPUT ;
    USE SIGNAL ;
    SHAPE ABUTMENT ;
    PORT
      LAYER M4 ;
      RECT 81.904 16.572 82.000 16.668 ;
    END
  END R0_data[74]
  PIN R0_data[75]
    DIRECTION OUTPUT ;
    USE SIGNAL ;
    SHAPE ABUTMENT ;
    PORT
      LAYER M5 ;
      RECT 7.068 207.904 7.164 208.000 ;
    END
  END R0_data[75]
  PIN R0_data[76]
    DIRECTION OUTPUT ;
    USE SIGNAL ;
    SHAPE ABUTMENT ;
    PORT
      LAYER M5 ;
      RECT 7.068 0.000 7.164 0.096 ;
    END
  END R0_data[76]
  PIN R0_data[77]
    DIRECTION OUTPUT ;
    USE SIGNAL ;
    SHAPE ABUTMENT ;
    PORT
      LAYER M4 ;
      RECT 0.000 17.340 0.096 17.436 ;
    END
  END R0_data[77]
  PIN R0_data[78]
    DIRECTION OUTPUT ;
    USE SIGNAL ;
    SHAPE ABUTMENT ;
    PORT
      LAYER M4 ;
      RECT 81.904 17.340 82.000 17.436 ;
    END
  END R0_data[78]
  PIN R0_data[79]
    DIRECTION OUTPUT ;
    USE SIGNAL ;
    SHAPE ABUTMENT ;
    PORT
      LAYER M5 ;
      RECT 7.356 207.904 7.452 208.000 ;
    END
  END R0_data[79]
  PIN R0_data[80]
    DIRECTION OUTPUT ;
    USE SIGNAL ;
    SHAPE ABUTMENT ;
    PORT
      LAYER M5 ;
      RECT 7.356 0.000 7.452 0.096 ;
    END
  END R0_data[80]
  PIN R0_data[81]
    DIRECTION OUTPUT ;
    USE SIGNAL ;
    SHAPE ABUTMENT ;
    PORT
      LAYER M4 ;
      RECT 0.000 18.060 0.096 18.156 ;
    END
  END R0_data[81]
  PIN R0_data[82]
    DIRECTION OUTPUT ;
    USE SIGNAL ;
    SHAPE ABUTMENT ;
    PORT
      LAYER M4 ;
      RECT 81.904 18.060 82.000 18.156 ;
    END
  END R0_data[82]
  PIN R0_data[83]
    DIRECTION OUTPUT ;
    USE SIGNAL ;
    SHAPE ABUTMENT ;
    PORT
      LAYER M5 ;
      RECT 7.644 207.904 7.740 208.000 ;
    END
  END R0_data[83]
  PIN R0_data[84]
    DIRECTION OUTPUT ;
    USE SIGNAL ;
    SHAPE ABUTMENT ;
    PORT
      LAYER M5 ;
      RECT 7.644 0.000 7.740 0.096 ;
    END
  END R0_data[84]
  PIN R0_data[85]
    DIRECTION OUTPUT ;
    USE SIGNAL ;
    SHAPE ABUTMENT ;
    PORT
      LAYER M4 ;
      RECT 0.000 18.828 0.096 18.924 ;
    END
  END R0_data[85]
  PIN R0_data[86]
    DIRECTION OUTPUT ;
    USE SIGNAL ;
    SHAPE ABUTMENT ;
    PORT
      LAYER M4 ;
      RECT 81.904 18.828 82.000 18.924 ;
    END
  END R0_data[86]
  PIN R0_data[87]
    DIRECTION OUTPUT ;
    USE SIGNAL ;
    SHAPE ABUTMENT ;
    PORT
      LAYER M5 ;
      RECT 7.932 207.904 8.028 208.000 ;
    END
  END R0_data[87]
  PIN R0_data[88]
    DIRECTION OUTPUT ;
    USE SIGNAL ;
    SHAPE ABUTMENT ;
    PORT
      LAYER M5 ;
      RECT 7.932 0.000 8.028 0.096 ;
    END
  END R0_data[88]
  PIN R0_data[89]
    DIRECTION OUTPUT ;
    USE SIGNAL ;
    SHAPE ABUTMENT ;
    PORT
      LAYER M4 ;
      RECT 0.000 19.548 0.096 19.644 ;
    END
  END R0_data[89]
  PIN R0_data[90]
    DIRECTION OUTPUT ;
    USE SIGNAL ;
    SHAPE ABUTMENT ;
    PORT
      LAYER M4 ;
      RECT 81.904 19.548 82.000 19.644 ;
    END
  END R0_data[90]
  PIN R0_data[91]
    DIRECTION OUTPUT ;
    USE SIGNAL ;
    SHAPE ABUTMENT ;
    PORT
      LAYER M5 ;
      RECT 8.220 207.904 8.316 208.000 ;
    END
  END R0_data[91]
  PIN R0_data[92]
    DIRECTION OUTPUT ;
    USE SIGNAL ;
    SHAPE ABUTMENT ;
    PORT
      LAYER M5 ;
      RECT 8.220 0.000 8.316 0.096 ;
    END
  END R0_data[92]
  PIN R0_data[93]
    DIRECTION OUTPUT ;
    USE SIGNAL ;
    SHAPE ABUTMENT ;
    PORT
      LAYER M4 ;
      RECT 0.000 20.316 0.096 20.412 ;
    END
  END R0_data[93]
  PIN R0_data[94]
    DIRECTION OUTPUT ;
    USE SIGNAL ;
    SHAPE ABUTMENT ;
    PORT
      LAYER M4 ;
      RECT 81.904 20.316 82.000 20.412 ;
    END
  END R0_data[94]
  PIN R0_data[95]
    DIRECTION OUTPUT ;
    USE SIGNAL ;
    SHAPE ABUTMENT ;
    PORT
      LAYER M5 ;
      RECT 8.508 207.904 8.604 208.000 ;
    END
  END R0_data[95]
  PIN R0_data[96]
    DIRECTION OUTPUT ;
    USE SIGNAL ;
    SHAPE ABUTMENT ;
    PORT
      LAYER M5 ;
      RECT 8.508 0.000 8.604 0.096 ;
    END
  END R0_data[96]
  PIN R0_data[97]
    DIRECTION OUTPUT ;
    USE SIGNAL ;
    SHAPE ABUTMENT ;
    PORT
      LAYER M4 ;
      RECT 0.000 21.036 0.096 21.132 ;
    END
  END R0_data[97]
  PIN R0_data[98]
    DIRECTION OUTPUT ;
    USE SIGNAL ;
    SHAPE ABUTMENT ;
    PORT
      LAYER M4 ;
      RECT 81.904 21.036 82.000 21.132 ;
    END
  END R0_data[98]
  PIN R0_data[99]
    DIRECTION OUTPUT ;
    USE SIGNAL ;
    SHAPE ABUTMENT ;
    PORT
      LAYER M5 ;
      RECT 8.796 207.904 8.892 208.000 ;
    END
  END R0_data[99]
  PIN R0_data[100]
    DIRECTION OUTPUT ;
    USE SIGNAL ;
    SHAPE ABUTMENT ;
    PORT
      LAYER M5 ;
      RECT 8.796 0.000 8.892 0.096 ;
    END
  END R0_data[100]
  PIN R0_data[101]
    DIRECTION OUTPUT ;
    USE SIGNAL ;
    SHAPE ABUTMENT ;
    PORT
      LAYER M4 ;
      RECT 0.000 21.804 0.096 21.900 ;
    END
  END R0_data[101]
  PIN R0_data[102]
    DIRECTION OUTPUT ;
    USE SIGNAL ;
    SHAPE ABUTMENT ;
    PORT
      LAYER M4 ;
      RECT 81.904 21.804 82.000 21.900 ;
    END
  END R0_data[102]
  PIN R0_data[103]
    DIRECTION OUTPUT ;
    USE SIGNAL ;
    SHAPE ABUTMENT ;
    PORT
      LAYER M5 ;
      RECT 9.084 207.904 9.180 208.000 ;
    END
  END R0_data[103]
  PIN R0_data[104]
    DIRECTION OUTPUT ;
    USE SIGNAL ;
    SHAPE ABUTMENT ;
    PORT
      LAYER M5 ;
      RECT 9.084 0.000 9.180 0.096 ;
    END
  END R0_data[104]
  PIN R0_data[105]
    DIRECTION OUTPUT ;
    USE SIGNAL ;
    SHAPE ABUTMENT ;
    PORT
      LAYER M4 ;
      RECT 0.000 22.524 0.096 22.620 ;
    END
  END R0_data[105]
  PIN R0_data[106]
    DIRECTION OUTPUT ;
    USE SIGNAL ;
    SHAPE ABUTMENT ;
    PORT
      LAYER M4 ;
      RECT 81.904 22.524 82.000 22.620 ;
    END
  END R0_data[106]
  PIN R0_data[107]
    DIRECTION OUTPUT ;
    USE SIGNAL ;
    SHAPE ABUTMENT ;
    PORT
      LAYER M5 ;
      RECT 9.372 207.904 9.468 208.000 ;
    END
  END R0_data[107]
  PIN R0_data[108]
    DIRECTION OUTPUT ;
    USE SIGNAL ;
    SHAPE ABUTMENT ;
    PORT
      LAYER M5 ;
      RECT 9.372 0.000 9.468 0.096 ;
    END
  END R0_data[108]
  PIN R0_data[109]
    DIRECTION OUTPUT ;
    USE SIGNAL ;
    SHAPE ABUTMENT ;
    PORT
      LAYER M4 ;
      RECT 0.000 23.292 0.096 23.388 ;
    END
  END R0_data[109]
  PIN R0_data[110]
    DIRECTION OUTPUT ;
    USE SIGNAL ;
    SHAPE ABUTMENT ;
    PORT
      LAYER M4 ;
      RECT 81.904 23.292 82.000 23.388 ;
    END
  END R0_data[110]
  PIN R0_data[111]
    DIRECTION OUTPUT ;
    USE SIGNAL ;
    SHAPE ABUTMENT ;
    PORT
      LAYER M5 ;
      RECT 9.660 207.904 9.756 208.000 ;
    END
  END R0_data[111]
  PIN R0_data[112]
    DIRECTION OUTPUT ;
    USE SIGNAL ;
    SHAPE ABUTMENT ;
    PORT
      LAYER M5 ;
      RECT 9.660 0.000 9.756 0.096 ;
    END
  END R0_data[112]
  PIN R0_data[113]
    DIRECTION OUTPUT ;
    USE SIGNAL ;
    SHAPE ABUTMENT ;
    PORT
      LAYER M4 ;
      RECT 0.000 24.012 0.096 24.108 ;
    END
  END R0_data[113]
  PIN R0_data[114]
    DIRECTION OUTPUT ;
    USE SIGNAL ;
    SHAPE ABUTMENT ;
    PORT
      LAYER M4 ;
      RECT 81.904 24.012 82.000 24.108 ;
    END
  END R0_data[114]
  PIN R0_data[115]
    DIRECTION OUTPUT ;
    USE SIGNAL ;
    SHAPE ABUTMENT ;
    PORT
      LAYER M5 ;
      RECT 9.948 207.904 10.044 208.000 ;
    END
  END R0_data[115]
  PIN R0_data[116]
    DIRECTION OUTPUT ;
    USE SIGNAL ;
    SHAPE ABUTMENT ;
    PORT
      LAYER M5 ;
      RECT 9.948 0.000 10.044 0.096 ;
    END
  END R0_data[116]
  PIN R0_data[117]
    DIRECTION OUTPUT ;
    USE SIGNAL ;
    SHAPE ABUTMENT ;
    PORT
      LAYER M4 ;
      RECT 0.000 24.780 0.096 24.876 ;
    END
  END R0_data[117]
  PIN R0_data[118]
    DIRECTION OUTPUT ;
    USE SIGNAL ;
    SHAPE ABUTMENT ;
    PORT
      LAYER M4 ;
      RECT 81.904 24.780 82.000 24.876 ;
    END
  END R0_data[118]
  PIN R0_data[119]
    DIRECTION OUTPUT ;
    USE SIGNAL ;
    SHAPE ABUTMENT ;
    PORT
      LAYER M5 ;
      RECT 10.236 207.904 10.332 208.000 ;
    END
  END R0_data[119]
  PIN R0_data[120]
    DIRECTION OUTPUT ;
    USE SIGNAL ;
    SHAPE ABUTMENT ;
    PORT
      LAYER M5 ;
      RECT 10.236 0.000 10.332 0.096 ;
    END
  END R0_data[120]
  PIN R0_data[121]
    DIRECTION OUTPUT ;
    USE SIGNAL ;
    SHAPE ABUTMENT ;
    PORT
      LAYER M4 ;
      RECT 0.000 25.500 0.096 25.596 ;
    END
  END R0_data[121]
  PIN R0_data[122]
    DIRECTION OUTPUT ;
    USE SIGNAL ;
    SHAPE ABUTMENT ;
    PORT
      LAYER M4 ;
      RECT 81.904 25.500 82.000 25.596 ;
    END
  END R0_data[122]
  PIN R0_data[123]
    DIRECTION OUTPUT ;
    USE SIGNAL ;
    SHAPE ABUTMENT ;
    PORT
      LAYER M5 ;
      RECT 10.524 207.904 10.620 208.000 ;
    END
  END R0_data[123]
  PIN R0_data[124]
    DIRECTION OUTPUT ;
    USE SIGNAL ;
    SHAPE ABUTMENT ;
    PORT
      LAYER M5 ;
      RECT 10.524 0.000 10.620 0.096 ;
    END
  END R0_data[124]
  PIN R0_data[125]
    DIRECTION OUTPUT ;
    USE SIGNAL ;
    SHAPE ABUTMENT ;
    PORT
      LAYER M4 ;
      RECT 0.000 26.268 0.096 26.364 ;
    END
  END R0_data[125]
  PIN R0_data[126]
    DIRECTION OUTPUT ;
    USE SIGNAL ;
    SHAPE ABUTMENT ;
    PORT
      LAYER M4 ;
      RECT 81.904 26.268 82.000 26.364 ;
    END
  END R0_data[126]
  PIN R0_data[127]
    DIRECTION OUTPUT ;
    USE SIGNAL ;
    SHAPE ABUTMENT ;
    PORT
      LAYER M5 ;
      RECT 10.812 207.904 10.908 208.000 ;
    END
  END R0_data[127]
  PIN R0_data[128]
    DIRECTION OUTPUT ;
    USE SIGNAL ;
    SHAPE ABUTMENT ;
    PORT
      LAYER M5 ;
      RECT 10.812 0.000 10.908 0.096 ;
    END
  END R0_data[128]
  PIN R0_data[129]
    DIRECTION OUTPUT ;
    USE SIGNAL ;
    SHAPE ABUTMENT ;
    PORT
      LAYER M4 ;
      RECT 0.000 26.988 0.096 27.084 ;
    END
  END R0_data[129]
  PIN R0_data[130]
    DIRECTION OUTPUT ;
    USE SIGNAL ;
    SHAPE ABUTMENT ;
    PORT
      LAYER M4 ;
      RECT 81.904 26.988 82.000 27.084 ;
    END
  END R0_data[130]
  PIN R0_data[131]
    DIRECTION OUTPUT ;
    USE SIGNAL ;
    SHAPE ABUTMENT ;
    PORT
      LAYER M5 ;
      RECT 11.100 207.904 11.196 208.000 ;
    END
  END R0_data[131]
  PIN R0_data[132]
    DIRECTION OUTPUT ;
    USE SIGNAL ;
    SHAPE ABUTMENT ;
    PORT
      LAYER M5 ;
      RECT 11.100 0.000 11.196 0.096 ;
    END
  END R0_data[132]
  PIN R0_data[133]
    DIRECTION OUTPUT ;
    USE SIGNAL ;
    SHAPE ABUTMENT ;
    PORT
      LAYER M4 ;
      RECT 0.000 27.756 0.096 27.852 ;
    END
  END R0_data[133]
  PIN R0_data[134]
    DIRECTION OUTPUT ;
    USE SIGNAL ;
    SHAPE ABUTMENT ;
    PORT
      LAYER M4 ;
      RECT 81.904 27.756 82.000 27.852 ;
    END
  END R0_data[134]
  PIN R0_data[135]
    DIRECTION OUTPUT ;
    USE SIGNAL ;
    SHAPE ABUTMENT ;
    PORT
      LAYER M5 ;
      RECT 11.388 207.904 11.484 208.000 ;
    END
  END R0_data[135]
  PIN R0_data[136]
    DIRECTION OUTPUT ;
    USE SIGNAL ;
    SHAPE ABUTMENT ;
    PORT
      LAYER M5 ;
      RECT 11.388 0.000 11.484 0.096 ;
    END
  END R0_data[136]
  PIN R0_data[137]
    DIRECTION OUTPUT ;
    USE SIGNAL ;
    SHAPE ABUTMENT ;
    PORT
      LAYER M4 ;
      RECT 0.000 28.476 0.096 28.572 ;
    END
  END R0_data[137]
  PIN R0_data[138]
    DIRECTION OUTPUT ;
    USE SIGNAL ;
    SHAPE ABUTMENT ;
    PORT
      LAYER M4 ;
      RECT 81.904 28.476 82.000 28.572 ;
    END
  END R0_data[138]
  PIN R0_data[139]
    DIRECTION OUTPUT ;
    USE SIGNAL ;
    SHAPE ABUTMENT ;
    PORT
      LAYER M5 ;
      RECT 11.676 207.904 11.772 208.000 ;
    END
  END R0_data[139]
  PIN R0_data[140]
    DIRECTION OUTPUT ;
    USE SIGNAL ;
    SHAPE ABUTMENT ;
    PORT
      LAYER M5 ;
      RECT 11.676 0.000 11.772 0.096 ;
    END
  END R0_data[140]
  PIN R0_data[141]
    DIRECTION OUTPUT ;
    USE SIGNAL ;
    SHAPE ABUTMENT ;
    PORT
      LAYER M4 ;
      RECT 0.000 29.244 0.096 29.340 ;
    END
  END R0_data[141]
  PIN R0_data[142]
    DIRECTION OUTPUT ;
    USE SIGNAL ;
    SHAPE ABUTMENT ;
    PORT
      LAYER M4 ;
      RECT 81.904 29.244 82.000 29.340 ;
    END
  END R0_data[142]
  PIN R0_data[143]
    DIRECTION OUTPUT ;
    USE SIGNAL ;
    SHAPE ABUTMENT ;
    PORT
      LAYER M5 ;
      RECT 11.964 207.904 12.060 208.000 ;
    END
  END R0_data[143]
  PIN R0_data[144]
    DIRECTION OUTPUT ;
    USE SIGNAL ;
    SHAPE ABUTMENT ;
    PORT
      LAYER M5 ;
      RECT 11.964 0.000 12.060 0.096 ;
    END
  END R0_data[144]
  PIN R0_data[145]
    DIRECTION OUTPUT ;
    USE SIGNAL ;
    SHAPE ABUTMENT ;
    PORT
      LAYER M4 ;
      RECT 0.000 29.964 0.096 30.060 ;
    END
  END R0_data[145]
  PIN R0_data[146]
    DIRECTION OUTPUT ;
    USE SIGNAL ;
    SHAPE ABUTMENT ;
    PORT
      LAYER M4 ;
      RECT 81.904 29.964 82.000 30.060 ;
    END
  END R0_data[146]
  PIN R0_data[147]
    DIRECTION OUTPUT ;
    USE SIGNAL ;
    SHAPE ABUTMENT ;
    PORT
      LAYER M5 ;
      RECT 12.252 207.904 12.348 208.000 ;
    END
  END R0_data[147]
  PIN R0_data[148]
    DIRECTION OUTPUT ;
    USE SIGNAL ;
    SHAPE ABUTMENT ;
    PORT
      LAYER M5 ;
      RECT 12.252 0.000 12.348 0.096 ;
    END
  END R0_data[148]
  PIN R0_data[149]
    DIRECTION OUTPUT ;
    USE SIGNAL ;
    SHAPE ABUTMENT ;
    PORT
      LAYER M4 ;
      RECT 0.000 30.732 0.096 30.828 ;
    END
  END R0_data[149]
  PIN R0_data[150]
    DIRECTION OUTPUT ;
    USE SIGNAL ;
    SHAPE ABUTMENT ;
    PORT
      LAYER M4 ;
      RECT 81.904 30.732 82.000 30.828 ;
    END
  END R0_data[150]
  PIN R0_data[151]
    DIRECTION OUTPUT ;
    USE SIGNAL ;
    SHAPE ABUTMENT ;
    PORT
      LAYER M5 ;
      RECT 12.540 207.904 12.636 208.000 ;
    END
  END R0_data[151]
  PIN R0_data[152]
    DIRECTION OUTPUT ;
    USE SIGNAL ;
    SHAPE ABUTMENT ;
    PORT
      LAYER M5 ;
      RECT 12.540 0.000 12.636 0.096 ;
    END
  END R0_data[152]
  PIN R0_data[153]
    DIRECTION OUTPUT ;
    USE SIGNAL ;
    SHAPE ABUTMENT ;
    PORT
      LAYER M4 ;
      RECT 0.000 31.452 0.096 31.548 ;
    END
  END R0_data[153]
  PIN R0_data[154]
    DIRECTION OUTPUT ;
    USE SIGNAL ;
    SHAPE ABUTMENT ;
    PORT
      LAYER M4 ;
      RECT 81.904 31.452 82.000 31.548 ;
    END
  END R0_data[154]
  PIN R0_data[155]
    DIRECTION OUTPUT ;
    USE SIGNAL ;
    SHAPE ABUTMENT ;
    PORT
      LAYER M5 ;
      RECT 12.828 207.904 12.924 208.000 ;
    END
  END R0_data[155]
  PIN R0_data[156]
    DIRECTION OUTPUT ;
    USE SIGNAL ;
    SHAPE ABUTMENT ;
    PORT
      LAYER M5 ;
      RECT 12.828 0.000 12.924 0.096 ;
    END
  END R0_data[156]
  PIN R0_data[157]
    DIRECTION OUTPUT ;
    USE SIGNAL ;
    SHAPE ABUTMENT ;
    PORT
      LAYER M4 ;
      RECT 0.000 32.220 0.096 32.316 ;
    END
  END R0_data[157]
  PIN R0_data[158]
    DIRECTION OUTPUT ;
    USE SIGNAL ;
    SHAPE ABUTMENT ;
    PORT
      LAYER M4 ;
      RECT 81.904 32.220 82.000 32.316 ;
    END
  END R0_data[158]
  PIN R0_data[159]
    DIRECTION OUTPUT ;
    USE SIGNAL ;
    SHAPE ABUTMENT ;
    PORT
      LAYER M5 ;
      RECT 13.164 207.904 13.260 208.000 ;
    END
  END R0_data[159]
  PIN R0_data[160]
    DIRECTION OUTPUT ;
    USE SIGNAL ;
    SHAPE ABUTMENT ;
    PORT
      LAYER M5 ;
      RECT 13.164 0.000 13.260 0.096 ;
    END
  END R0_data[160]
  PIN R0_data[161]
    DIRECTION OUTPUT ;
    USE SIGNAL ;
    SHAPE ABUTMENT ;
    PORT
      LAYER M4 ;
      RECT 0.000 32.940 0.096 33.036 ;
    END
  END R0_data[161]
  PIN R0_data[162]
    DIRECTION OUTPUT ;
    USE SIGNAL ;
    SHAPE ABUTMENT ;
    PORT
      LAYER M4 ;
      RECT 81.904 32.940 82.000 33.036 ;
    END
  END R0_data[162]
  PIN R0_data[163]
    DIRECTION OUTPUT ;
    USE SIGNAL ;
    SHAPE ABUTMENT ;
    PORT
      LAYER M5 ;
      RECT 13.452 207.904 13.548 208.000 ;
    END
  END R0_data[163]
  PIN R0_data[164]
    DIRECTION OUTPUT ;
    USE SIGNAL ;
    SHAPE ABUTMENT ;
    PORT
      LAYER M5 ;
      RECT 13.452 0.000 13.548 0.096 ;
    END
  END R0_data[164]
  PIN R0_data[165]
    DIRECTION OUTPUT ;
    USE SIGNAL ;
    SHAPE ABUTMENT ;
    PORT
      LAYER M4 ;
      RECT 0.000 33.708 0.096 33.804 ;
    END
  END R0_data[165]
  PIN R0_data[166]
    DIRECTION OUTPUT ;
    USE SIGNAL ;
    SHAPE ABUTMENT ;
    PORT
      LAYER M4 ;
      RECT 81.904 33.708 82.000 33.804 ;
    END
  END R0_data[166]
  PIN R0_data[167]
    DIRECTION OUTPUT ;
    USE SIGNAL ;
    SHAPE ABUTMENT ;
    PORT
      LAYER M5 ;
      RECT 13.740 207.904 13.836 208.000 ;
    END
  END R0_data[167]
  PIN R0_data[168]
    DIRECTION OUTPUT ;
    USE SIGNAL ;
    SHAPE ABUTMENT ;
    PORT
      LAYER M5 ;
      RECT 13.740 0.000 13.836 0.096 ;
    END
  END R0_data[168]
  PIN R0_data[169]
    DIRECTION OUTPUT ;
    USE SIGNAL ;
    SHAPE ABUTMENT ;
    PORT
      LAYER M4 ;
      RECT 0.000 34.428 0.096 34.524 ;
    END
  END R0_data[169]
  PIN R0_data[170]
    DIRECTION OUTPUT ;
    USE SIGNAL ;
    SHAPE ABUTMENT ;
    PORT
      LAYER M4 ;
      RECT 81.904 34.428 82.000 34.524 ;
    END
  END R0_data[170]
  PIN R0_data[171]
    DIRECTION OUTPUT ;
    USE SIGNAL ;
    SHAPE ABUTMENT ;
    PORT
      LAYER M5 ;
      RECT 14.028 207.904 14.124 208.000 ;
    END
  END R0_data[171]
  PIN R0_data[172]
    DIRECTION OUTPUT ;
    USE SIGNAL ;
    SHAPE ABUTMENT ;
    PORT
      LAYER M5 ;
      RECT 14.028 0.000 14.124 0.096 ;
    END
  END R0_data[172]
  PIN R0_data[173]
    DIRECTION OUTPUT ;
    USE SIGNAL ;
    SHAPE ABUTMENT ;
    PORT
      LAYER M4 ;
      RECT 0.000 35.196 0.096 35.292 ;
    END
  END R0_data[173]
  PIN R0_data[174]
    DIRECTION OUTPUT ;
    USE SIGNAL ;
    SHAPE ABUTMENT ;
    PORT
      LAYER M4 ;
      RECT 81.904 35.196 82.000 35.292 ;
    END
  END R0_data[174]
  PIN R0_data[175]
    DIRECTION OUTPUT ;
    USE SIGNAL ;
    SHAPE ABUTMENT ;
    PORT
      LAYER M5 ;
      RECT 14.316 207.904 14.412 208.000 ;
    END
  END R0_data[175]
  PIN R0_data[176]
    DIRECTION OUTPUT ;
    USE SIGNAL ;
    SHAPE ABUTMENT ;
    PORT
      LAYER M5 ;
      RECT 14.316 0.000 14.412 0.096 ;
    END
  END R0_data[176]
  PIN R0_data[177]
    DIRECTION OUTPUT ;
    USE SIGNAL ;
    SHAPE ABUTMENT ;
    PORT
      LAYER M4 ;
      RECT 0.000 35.916 0.096 36.012 ;
    END
  END R0_data[177]
  PIN R0_data[178]
    DIRECTION OUTPUT ;
    USE SIGNAL ;
    SHAPE ABUTMENT ;
    PORT
      LAYER M4 ;
      RECT 81.904 35.916 82.000 36.012 ;
    END
  END R0_data[178]
  PIN R0_data[179]
    DIRECTION OUTPUT ;
    USE SIGNAL ;
    SHAPE ABUTMENT ;
    PORT
      LAYER M5 ;
      RECT 14.604 207.904 14.700 208.000 ;
    END
  END R0_data[179]
  PIN R0_data[180]
    DIRECTION OUTPUT ;
    USE SIGNAL ;
    SHAPE ABUTMENT ;
    PORT
      LAYER M5 ;
      RECT 14.604 0.000 14.700 0.096 ;
    END
  END R0_data[180]
  PIN R0_data[181]
    DIRECTION OUTPUT ;
    USE SIGNAL ;
    SHAPE ABUTMENT ;
    PORT
      LAYER M4 ;
      RECT 0.000 36.684 0.096 36.780 ;
    END
  END R0_data[181]
  PIN R0_data[182]
    DIRECTION OUTPUT ;
    USE SIGNAL ;
    SHAPE ABUTMENT ;
    PORT
      LAYER M4 ;
      RECT 81.904 36.684 82.000 36.780 ;
    END
  END R0_data[182]
  PIN R0_data[183]
    DIRECTION OUTPUT ;
    USE SIGNAL ;
    SHAPE ABUTMENT ;
    PORT
      LAYER M5 ;
      RECT 14.892 207.904 14.988 208.000 ;
    END
  END R0_data[183]
  PIN R0_data[184]
    DIRECTION OUTPUT ;
    USE SIGNAL ;
    SHAPE ABUTMENT ;
    PORT
      LAYER M5 ;
      RECT 14.892 0.000 14.988 0.096 ;
    END
  END R0_data[184]
  PIN R0_data[185]
    DIRECTION OUTPUT ;
    USE SIGNAL ;
    SHAPE ABUTMENT ;
    PORT
      LAYER M4 ;
      RECT 0.000 37.404 0.096 37.500 ;
    END
  END R0_data[185]
  PIN R0_data[186]
    DIRECTION OUTPUT ;
    USE SIGNAL ;
    SHAPE ABUTMENT ;
    PORT
      LAYER M4 ;
      RECT 81.904 37.404 82.000 37.500 ;
    END
  END R0_data[186]
  PIN R0_data[187]
    DIRECTION OUTPUT ;
    USE SIGNAL ;
    SHAPE ABUTMENT ;
    PORT
      LAYER M5 ;
      RECT 15.180 207.904 15.276 208.000 ;
    END
  END R0_data[187]
  PIN R0_data[188]
    DIRECTION OUTPUT ;
    USE SIGNAL ;
    SHAPE ABUTMENT ;
    PORT
      LAYER M5 ;
      RECT 15.180 0.000 15.276 0.096 ;
    END
  END R0_data[188]
  PIN R0_data[189]
    DIRECTION OUTPUT ;
    USE SIGNAL ;
    SHAPE ABUTMENT ;
    PORT
      LAYER M4 ;
      RECT 0.000 38.172 0.096 38.268 ;
    END
  END R0_data[189]
  PIN R0_data[190]
    DIRECTION OUTPUT ;
    USE SIGNAL ;
    SHAPE ABUTMENT ;
    PORT
      LAYER M4 ;
      RECT 81.904 38.172 82.000 38.268 ;
    END
  END R0_data[190]
  PIN R0_data[191]
    DIRECTION OUTPUT ;
    USE SIGNAL ;
    SHAPE ABUTMENT ;
    PORT
      LAYER M5 ;
      RECT 15.468 207.904 15.564 208.000 ;
    END
  END R0_data[191]
  PIN R0_data[192]
    DIRECTION OUTPUT ;
    USE SIGNAL ;
    SHAPE ABUTMENT ;
    PORT
      LAYER M5 ;
      RECT 15.468 0.000 15.564 0.096 ;
    END
  END R0_data[192]
  PIN R0_data[193]
    DIRECTION OUTPUT ;
    USE SIGNAL ;
    SHAPE ABUTMENT ;
    PORT
      LAYER M4 ;
      RECT 0.000 38.892 0.096 38.988 ;
    END
  END R0_data[193]
  PIN R0_data[194]
    DIRECTION OUTPUT ;
    USE SIGNAL ;
    SHAPE ABUTMENT ;
    PORT
      LAYER M4 ;
      RECT 81.904 38.892 82.000 38.988 ;
    END
  END R0_data[194]
  PIN R0_data[195]
    DIRECTION OUTPUT ;
    USE SIGNAL ;
    SHAPE ABUTMENT ;
    PORT
      LAYER M5 ;
      RECT 15.756 207.904 15.852 208.000 ;
    END
  END R0_data[195]
  PIN R0_data[196]
    DIRECTION OUTPUT ;
    USE SIGNAL ;
    SHAPE ABUTMENT ;
    PORT
      LAYER M5 ;
      RECT 15.756 0.000 15.852 0.096 ;
    END
  END R0_data[196]
  PIN R0_data[197]
    DIRECTION OUTPUT ;
    USE SIGNAL ;
    SHAPE ABUTMENT ;
    PORT
      LAYER M4 ;
      RECT 0.000 39.660 0.096 39.756 ;
    END
  END R0_data[197]
  PIN R0_data[198]
    DIRECTION OUTPUT ;
    USE SIGNAL ;
    SHAPE ABUTMENT ;
    PORT
      LAYER M4 ;
      RECT 81.904 39.660 82.000 39.756 ;
    END
  END R0_data[198]
  PIN R0_data[199]
    DIRECTION OUTPUT ;
    USE SIGNAL ;
    SHAPE ABUTMENT ;
    PORT
      LAYER M5 ;
      RECT 16.044 207.904 16.140 208.000 ;
    END
  END R0_data[199]
  PIN R0_data[200]
    DIRECTION OUTPUT ;
    USE SIGNAL ;
    SHAPE ABUTMENT ;
    PORT
      LAYER M5 ;
      RECT 16.044 0.000 16.140 0.096 ;
    END
  END R0_data[200]
  PIN R0_data[201]
    DIRECTION OUTPUT ;
    USE SIGNAL ;
    SHAPE ABUTMENT ;
    PORT
      LAYER M4 ;
      RECT 0.000 40.380 0.096 40.476 ;
    END
  END R0_data[201]
  PIN R0_data[202]
    DIRECTION OUTPUT ;
    USE SIGNAL ;
    SHAPE ABUTMENT ;
    PORT
      LAYER M4 ;
      RECT 81.904 40.380 82.000 40.476 ;
    END
  END R0_data[202]
  PIN R0_data[203]
    DIRECTION OUTPUT ;
    USE SIGNAL ;
    SHAPE ABUTMENT ;
    PORT
      LAYER M5 ;
      RECT 16.332 207.904 16.428 208.000 ;
    END
  END R0_data[203]
  PIN R0_data[204]
    DIRECTION OUTPUT ;
    USE SIGNAL ;
    SHAPE ABUTMENT ;
    PORT
      LAYER M5 ;
      RECT 16.332 0.000 16.428 0.096 ;
    END
  END R0_data[204]
  PIN R0_data[205]
    DIRECTION OUTPUT ;
    USE SIGNAL ;
    SHAPE ABUTMENT ;
    PORT
      LAYER M4 ;
      RECT 0.000 41.148 0.096 41.244 ;
    END
  END R0_data[205]
  PIN R0_data[206]
    DIRECTION OUTPUT ;
    USE SIGNAL ;
    SHAPE ABUTMENT ;
    PORT
      LAYER M4 ;
      RECT 81.904 41.148 82.000 41.244 ;
    END
  END R0_data[206]
  PIN R0_data[207]
    DIRECTION OUTPUT ;
    USE SIGNAL ;
    SHAPE ABUTMENT ;
    PORT
      LAYER M5 ;
      RECT 16.620 207.904 16.716 208.000 ;
    END
  END R0_data[207]
  PIN R0_data[208]
    DIRECTION OUTPUT ;
    USE SIGNAL ;
    SHAPE ABUTMENT ;
    PORT
      LAYER M5 ;
      RECT 16.620 0.000 16.716 0.096 ;
    END
  END R0_data[208]
  PIN R0_data[209]
    DIRECTION OUTPUT ;
    USE SIGNAL ;
    SHAPE ABUTMENT ;
    PORT
      LAYER M4 ;
      RECT 0.000 41.868 0.096 41.964 ;
    END
  END R0_data[209]
  PIN R0_data[210]
    DIRECTION OUTPUT ;
    USE SIGNAL ;
    SHAPE ABUTMENT ;
    PORT
      LAYER M4 ;
      RECT 81.904 41.868 82.000 41.964 ;
    END
  END R0_data[210]
  PIN R0_data[211]
    DIRECTION OUTPUT ;
    USE SIGNAL ;
    SHAPE ABUTMENT ;
    PORT
      LAYER M5 ;
      RECT 16.908 207.904 17.004 208.000 ;
    END
  END R0_data[211]
  PIN R0_data[212]
    DIRECTION OUTPUT ;
    USE SIGNAL ;
    SHAPE ABUTMENT ;
    PORT
      LAYER M5 ;
      RECT 16.908 0.000 17.004 0.096 ;
    END
  END R0_data[212]
  PIN R0_data[213]
    DIRECTION OUTPUT ;
    USE SIGNAL ;
    SHAPE ABUTMENT ;
    PORT
      LAYER M4 ;
      RECT 0.000 42.588 0.096 42.684 ;
    END
  END R0_data[213]
  PIN R0_data[214]
    DIRECTION OUTPUT ;
    USE SIGNAL ;
    SHAPE ABUTMENT ;
    PORT
      LAYER M4 ;
      RECT 81.904 42.588 82.000 42.684 ;
    END
  END R0_data[214]
  PIN R0_data[215]
    DIRECTION OUTPUT ;
    USE SIGNAL ;
    SHAPE ABUTMENT ;
    PORT
      LAYER M5 ;
      RECT 17.196 207.904 17.292 208.000 ;
    END
  END R0_data[215]
  PIN R0_data[216]
    DIRECTION OUTPUT ;
    USE SIGNAL ;
    SHAPE ABUTMENT ;
    PORT
      LAYER M5 ;
      RECT 17.196 0.000 17.292 0.096 ;
    END
  END R0_data[216]
  PIN R0_data[217]
    DIRECTION OUTPUT ;
    USE SIGNAL ;
    SHAPE ABUTMENT ;
    PORT
      LAYER M4 ;
      RECT 0.000 43.356 0.096 43.452 ;
    END
  END R0_data[217]
  PIN R0_data[218]
    DIRECTION OUTPUT ;
    USE SIGNAL ;
    SHAPE ABUTMENT ;
    PORT
      LAYER M4 ;
      RECT 81.904 43.356 82.000 43.452 ;
    END
  END R0_data[218]
  PIN R0_data[219]
    DIRECTION OUTPUT ;
    USE SIGNAL ;
    SHAPE ABUTMENT ;
    PORT
      LAYER M5 ;
      RECT 17.484 207.904 17.580 208.000 ;
    END
  END R0_data[219]
  PIN R0_data[220]
    DIRECTION OUTPUT ;
    USE SIGNAL ;
    SHAPE ABUTMENT ;
    PORT
      LAYER M5 ;
      RECT 17.484 0.000 17.580 0.096 ;
    END
  END R0_data[220]
  PIN R0_data[221]
    DIRECTION OUTPUT ;
    USE SIGNAL ;
    SHAPE ABUTMENT ;
    PORT
      LAYER M4 ;
      RECT 0.000 44.076 0.096 44.172 ;
    END
  END R0_data[221]
  PIN R0_data[222]
    DIRECTION OUTPUT ;
    USE SIGNAL ;
    SHAPE ABUTMENT ;
    PORT
      LAYER M4 ;
      RECT 81.904 44.076 82.000 44.172 ;
    END
  END R0_data[222]
  PIN R0_data[223]
    DIRECTION OUTPUT ;
    USE SIGNAL ;
    SHAPE ABUTMENT ;
    PORT
      LAYER M5 ;
      RECT 17.772 207.904 17.868 208.000 ;
    END
  END R0_data[223]
  PIN R0_data[224]
    DIRECTION OUTPUT ;
    USE SIGNAL ;
    SHAPE ABUTMENT ;
    PORT
      LAYER M5 ;
      RECT 17.772 0.000 17.868 0.096 ;
    END
  END R0_data[224]
  PIN R0_data[225]
    DIRECTION OUTPUT ;
    USE SIGNAL ;
    SHAPE ABUTMENT ;
    PORT
      LAYER M4 ;
      RECT 0.000 44.844 0.096 44.940 ;
    END
  END R0_data[225]
  PIN R0_data[226]
    DIRECTION OUTPUT ;
    USE SIGNAL ;
    SHAPE ABUTMENT ;
    PORT
      LAYER M4 ;
      RECT 81.904 44.844 82.000 44.940 ;
    END
  END R0_data[226]
  PIN R0_data[227]
    DIRECTION OUTPUT ;
    USE SIGNAL ;
    SHAPE ABUTMENT ;
    PORT
      LAYER M5 ;
      RECT 18.060 207.904 18.156 208.000 ;
    END
  END R0_data[227]
  PIN R0_data[228]
    DIRECTION OUTPUT ;
    USE SIGNAL ;
    SHAPE ABUTMENT ;
    PORT
      LAYER M5 ;
      RECT 18.060 0.000 18.156 0.096 ;
    END
  END R0_data[228]
  PIN R0_data[229]
    DIRECTION OUTPUT ;
    USE SIGNAL ;
    SHAPE ABUTMENT ;
    PORT
      LAYER M4 ;
      RECT 0.000 45.564 0.096 45.660 ;
    END
  END R0_data[229]
  PIN R0_data[230]
    DIRECTION OUTPUT ;
    USE SIGNAL ;
    SHAPE ABUTMENT ;
    PORT
      LAYER M4 ;
      RECT 81.904 45.564 82.000 45.660 ;
    END
  END R0_data[230]
  PIN R0_data[231]
    DIRECTION OUTPUT ;
    USE SIGNAL ;
    SHAPE ABUTMENT ;
    PORT
      LAYER M5 ;
      RECT 18.348 207.904 18.444 208.000 ;
    END
  END R0_data[231]
  PIN R0_data[232]
    DIRECTION OUTPUT ;
    USE SIGNAL ;
    SHAPE ABUTMENT ;
    PORT
      LAYER M5 ;
      RECT 18.348 0.000 18.444 0.096 ;
    END
  END R0_data[232]
  PIN R0_data[233]
    DIRECTION OUTPUT ;
    USE SIGNAL ;
    SHAPE ABUTMENT ;
    PORT
      LAYER M4 ;
      RECT 0.000 46.332 0.096 46.428 ;
    END
  END R0_data[233]
  PIN R0_data[234]
    DIRECTION OUTPUT ;
    USE SIGNAL ;
    SHAPE ABUTMENT ;
    PORT
      LAYER M4 ;
      RECT 81.904 46.332 82.000 46.428 ;
    END
  END R0_data[234]
  PIN R0_data[235]
    DIRECTION OUTPUT ;
    USE SIGNAL ;
    SHAPE ABUTMENT ;
    PORT
      LAYER M5 ;
      RECT 18.636 207.904 18.732 208.000 ;
    END
  END R0_data[235]
  PIN R0_data[236]
    DIRECTION OUTPUT ;
    USE SIGNAL ;
    SHAPE ABUTMENT ;
    PORT
      LAYER M5 ;
      RECT 18.636 0.000 18.732 0.096 ;
    END
  END R0_data[236]
  PIN R0_data[237]
    DIRECTION OUTPUT ;
    USE SIGNAL ;
    SHAPE ABUTMENT ;
    PORT
      LAYER M4 ;
      RECT 0.000 47.052 0.096 47.148 ;
    END
  END R0_data[237]
  PIN R0_data[238]
    DIRECTION OUTPUT ;
    USE SIGNAL ;
    SHAPE ABUTMENT ;
    PORT
      LAYER M4 ;
      RECT 81.904 47.052 82.000 47.148 ;
    END
  END R0_data[238]
  PIN R0_data[239]
    DIRECTION OUTPUT ;
    USE SIGNAL ;
    SHAPE ABUTMENT ;
    PORT
      LAYER M5 ;
      RECT 18.924 207.904 19.020 208.000 ;
    END
  END R0_data[239]
  PIN R0_data[240]
    DIRECTION OUTPUT ;
    USE SIGNAL ;
    SHAPE ABUTMENT ;
    PORT
      LAYER M5 ;
      RECT 18.924 0.000 19.020 0.096 ;
    END
  END R0_data[240]
  PIN R0_data[241]
    DIRECTION OUTPUT ;
    USE SIGNAL ;
    SHAPE ABUTMENT ;
    PORT
      LAYER M4 ;
      RECT 0.000 47.820 0.096 47.916 ;
    END
  END R0_data[241]
  PIN R0_data[242]
    DIRECTION OUTPUT ;
    USE SIGNAL ;
    SHAPE ABUTMENT ;
    PORT
      LAYER M4 ;
      RECT 81.904 47.820 82.000 47.916 ;
    END
  END R0_data[242]
  PIN R0_data[243]
    DIRECTION OUTPUT ;
    USE SIGNAL ;
    SHAPE ABUTMENT ;
    PORT
      LAYER M5 ;
      RECT 19.212 207.904 19.308 208.000 ;
    END
  END R0_data[243]
  PIN R0_data[244]
    DIRECTION OUTPUT ;
    USE SIGNAL ;
    SHAPE ABUTMENT ;
    PORT
      LAYER M5 ;
      RECT 19.212 0.000 19.308 0.096 ;
    END
  END R0_data[244]
  PIN R0_data[245]
    DIRECTION OUTPUT ;
    USE SIGNAL ;
    SHAPE ABUTMENT ;
    PORT
      LAYER M4 ;
      RECT 0.000 48.540 0.096 48.636 ;
    END
  END R0_data[245]
  PIN R0_data[246]
    DIRECTION OUTPUT ;
    USE SIGNAL ;
    SHAPE ABUTMENT ;
    PORT
      LAYER M4 ;
      RECT 81.904 48.540 82.000 48.636 ;
    END
  END R0_data[246]
  PIN R0_data[247]
    DIRECTION OUTPUT ;
    USE SIGNAL ;
    SHAPE ABUTMENT ;
    PORT
      LAYER M5 ;
      RECT 19.500 207.904 19.596 208.000 ;
    END
  END R0_data[247]
  PIN R0_data[248]
    DIRECTION OUTPUT ;
    USE SIGNAL ;
    SHAPE ABUTMENT ;
    PORT
      LAYER M5 ;
      RECT 19.500 0.000 19.596 0.096 ;
    END
  END R0_data[248]
  PIN R0_data[249]
    DIRECTION OUTPUT ;
    USE SIGNAL ;
    SHAPE ABUTMENT ;
    PORT
      LAYER M4 ;
      RECT 0.000 49.308 0.096 49.404 ;
    END
  END R0_data[249]
  PIN R0_data[250]
    DIRECTION OUTPUT ;
    USE SIGNAL ;
    SHAPE ABUTMENT ;
    PORT
      LAYER M4 ;
      RECT 81.904 49.308 82.000 49.404 ;
    END
  END R0_data[250]
  PIN R0_data[251]
    DIRECTION OUTPUT ;
    USE SIGNAL ;
    SHAPE ABUTMENT ;
    PORT
      LAYER M5 ;
      RECT 19.788 207.904 19.884 208.000 ;
    END
  END R0_data[251]
  PIN R0_data[252]
    DIRECTION OUTPUT ;
    USE SIGNAL ;
    SHAPE ABUTMENT ;
    PORT
      LAYER M5 ;
      RECT 19.788 0.000 19.884 0.096 ;
    END
  END R0_data[252]
  PIN R0_data[253]
    DIRECTION OUTPUT ;
    USE SIGNAL ;
    SHAPE ABUTMENT ;
    PORT
      LAYER M4 ;
      RECT 0.000 50.028 0.096 50.124 ;
    END
  END R0_data[253]
  PIN R0_data[254]
    DIRECTION OUTPUT ;
    USE SIGNAL ;
    SHAPE ABUTMENT ;
    PORT
      LAYER M4 ;
      RECT 81.904 50.028 82.000 50.124 ;
    END
  END R0_data[254]
  PIN R0_data[255]
    DIRECTION OUTPUT ;
    USE SIGNAL ;
    SHAPE ABUTMENT ;
    PORT
      LAYER M5 ;
      RECT 20.076 207.904 20.172 208.000 ;
    END
  END R0_data[255]
  PIN R0_data[256]
    DIRECTION OUTPUT ;
    USE SIGNAL ;
    SHAPE ABUTMENT ;
    PORT
      LAYER M5 ;
      RECT 20.076 0.000 20.172 0.096 ;
    END
  END R0_data[256]
  PIN R0_data[257]
    DIRECTION OUTPUT ;
    USE SIGNAL ;
    SHAPE ABUTMENT ;
    PORT
      LAYER M4 ;
      RECT 0.000 50.796 0.096 50.892 ;
    END
  END R0_data[257]
  PIN R0_data[258]
    DIRECTION OUTPUT ;
    USE SIGNAL ;
    SHAPE ABUTMENT ;
    PORT
      LAYER M4 ;
      RECT 81.904 50.796 82.000 50.892 ;
    END
  END R0_data[258]
  PIN R0_data[259]
    DIRECTION OUTPUT ;
    USE SIGNAL ;
    SHAPE ABUTMENT ;
    PORT
      LAYER M5 ;
      RECT 20.364 207.904 20.460 208.000 ;
    END
  END R0_data[259]
  PIN R0_data[260]
    DIRECTION OUTPUT ;
    USE SIGNAL ;
    SHAPE ABUTMENT ;
    PORT
      LAYER M5 ;
      RECT 20.364 0.000 20.460 0.096 ;
    END
  END R0_data[260]
  PIN R0_data[261]
    DIRECTION OUTPUT ;
    USE SIGNAL ;
    SHAPE ABUTMENT ;
    PORT
      LAYER M4 ;
      RECT 0.000 51.516 0.096 51.612 ;
    END
  END R0_data[261]
  PIN R0_data[262]
    DIRECTION OUTPUT ;
    USE SIGNAL ;
    SHAPE ABUTMENT ;
    PORT
      LAYER M4 ;
      RECT 81.904 51.516 82.000 51.612 ;
    END
  END R0_data[262]
  PIN R0_data[263]
    DIRECTION OUTPUT ;
    USE SIGNAL ;
    SHAPE ABUTMENT ;
    PORT
      LAYER M5 ;
      RECT 20.652 207.904 20.748 208.000 ;
    END
  END R0_data[263]
  PIN R0_data[264]
    DIRECTION OUTPUT ;
    USE SIGNAL ;
    SHAPE ABUTMENT ;
    PORT
      LAYER M5 ;
      RECT 20.652 0.000 20.748 0.096 ;
    END
  END R0_data[264]
  PIN R0_data[265]
    DIRECTION OUTPUT ;
    USE SIGNAL ;
    SHAPE ABUTMENT ;
    PORT
      LAYER M4 ;
      RECT 0.000 52.284 0.096 52.380 ;
    END
  END R0_data[265]
  PIN R0_data[266]
    DIRECTION OUTPUT ;
    USE SIGNAL ;
    SHAPE ABUTMENT ;
    PORT
      LAYER M4 ;
      RECT 81.904 52.284 82.000 52.380 ;
    END
  END R0_data[266]
  PIN R0_data[267]
    DIRECTION OUTPUT ;
    USE SIGNAL ;
    SHAPE ABUTMENT ;
    PORT
      LAYER M5 ;
      RECT 20.940 207.904 21.036 208.000 ;
    END
  END R0_data[267]
  PIN R0_data[268]
    DIRECTION OUTPUT ;
    USE SIGNAL ;
    SHAPE ABUTMENT ;
    PORT
      LAYER M5 ;
      RECT 20.940 0.000 21.036 0.096 ;
    END
  END R0_data[268]
  PIN R0_data[269]
    DIRECTION OUTPUT ;
    USE SIGNAL ;
    SHAPE ABUTMENT ;
    PORT
      LAYER M4 ;
      RECT 0.000 53.004 0.096 53.100 ;
    END
  END R0_data[269]
  PIN R0_data[270]
    DIRECTION OUTPUT ;
    USE SIGNAL ;
    SHAPE ABUTMENT ;
    PORT
      LAYER M4 ;
      RECT 81.904 53.004 82.000 53.100 ;
    END
  END R0_data[270]
  PIN R0_data[271]
    DIRECTION OUTPUT ;
    USE SIGNAL ;
    SHAPE ABUTMENT ;
    PORT
      LAYER M5 ;
      RECT 21.276 207.904 21.372 208.000 ;
    END
  END R0_data[271]
  PIN R0_data[272]
    DIRECTION OUTPUT ;
    USE SIGNAL ;
    SHAPE ABUTMENT ;
    PORT
      LAYER M5 ;
      RECT 21.276 0.000 21.372 0.096 ;
    END
  END R0_data[272]
  PIN R0_data[273]
    DIRECTION OUTPUT ;
    USE SIGNAL ;
    SHAPE ABUTMENT ;
    PORT
      LAYER M4 ;
      RECT 0.000 53.772 0.096 53.868 ;
    END
  END R0_data[273]
  PIN R0_data[274]
    DIRECTION OUTPUT ;
    USE SIGNAL ;
    SHAPE ABUTMENT ;
    PORT
      LAYER M4 ;
      RECT 81.904 53.772 82.000 53.868 ;
    END
  END R0_data[274]
  PIN R0_data[275]
    DIRECTION OUTPUT ;
    USE SIGNAL ;
    SHAPE ABUTMENT ;
    PORT
      LAYER M5 ;
      RECT 21.564 207.904 21.660 208.000 ;
    END
  END R0_data[275]
  PIN R0_data[276]
    DIRECTION OUTPUT ;
    USE SIGNAL ;
    SHAPE ABUTMENT ;
    PORT
      LAYER M5 ;
      RECT 21.564 0.000 21.660 0.096 ;
    END
  END R0_data[276]
  PIN R0_data[277]
    DIRECTION OUTPUT ;
    USE SIGNAL ;
    SHAPE ABUTMENT ;
    PORT
      LAYER M4 ;
      RECT 0.000 54.492 0.096 54.588 ;
    END
  END R0_data[277]
  PIN R0_data[278]
    DIRECTION OUTPUT ;
    USE SIGNAL ;
    SHAPE ABUTMENT ;
    PORT
      LAYER M4 ;
      RECT 81.904 54.492 82.000 54.588 ;
    END
  END R0_data[278]
  PIN R0_data[279]
    DIRECTION OUTPUT ;
    USE SIGNAL ;
    SHAPE ABUTMENT ;
    PORT
      LAYER M5 ;
      RECT 21.852 207.904 21.948 208.000 ;
    END
  END R0_data[279]
  PIN R0_data[280]
    DIRECTION OUTPUT ;
    USE SIGNAL ;
    SHAPE ABUTMENT ;
    PORT
      LAYER M5 ;
      RECT 21.852 0.000 21.948 0.096 ;
    END
  END R0_data[280]
  PIN R0_data[281]
    DIRECTION OUTPUT ;
    USE SIGNAL ;
    SHAPE ABUTMENT ;
    PORT
      LAYER M4 ;
      RECT 0.000 55.260 0.096 55.356 ;
    END
  END R0_data[281]
  PIN R0_data[282]
    DIRECTION OUTPUT ;
    USE SIGNAL ;
    SHAPE ABUTMENT ;
    PORT
      LAYER M4 ;
      RECT 81.904 55.260 82.000 55.356 ;
    END
  END R0_data[282]
  PIN R0_data[283]
    DIRECTION OUTPUT ;
    USE SIGNAL ;
    SHAPE ABUTMENT ;
    PORT
      LAYER M5 ;
      RECT 22.140 207.904 22.236 208.000 ;
    END
  END R0_data[283]
  PIN R0_data[284]
    DIRECTION OUTPUT ;
    USE SIGNAL ;
    SHAPE ABUTMENT ;
    PORT
      LAYER M5 ;
      RECT 22.140 0.000 22.236 0.096 ;
    END
  END R0_data[284]
  PIN R0_data[285]
    DIRECTION OUTPUT ;
    USE SIGNAL ;
    SHAPE ABUTMENT ;
    PORT
      LAYER M4 ;
      RECT 0.000 55.980 0.096 56.076 ;
    END
  END R0_data[285]
  PIN R0_data[286]
    DIRECTION OUTPUT ;
    USE SIGNAL ;
    SHAPE ABUTMENT ;
    PORT
      LAYER M4 ;
      RECT 81.904 55.980 82.000 56.076 ;
    END
  END R0_data[286]
  PIN R0_data[287]
    DIRECTION OUTPUT ;
    USE SIGNAL ;
    SHAPE ABUTMENT ;
    PORT
      LAYER M5 ;
      RECT 22.428 207.904 22.524 208.000 ;
    END
  END R0_data[287]
  PIN R0_data[288]
    DIRECTION OUTPUT ;
    USE SIGNAL ;
    SHAPE ABUTMENT ;
    PORT
      LAYER M5 ;
      RECT 22.428 0.000 22.524 0.096 ;
    END
  END R0_data[288]
  PIN R0_data[289]
    DIRECTION OUTPUT ;
    USE SIGNAL ;
    SHAPE ABUTMENT ;
    PORT
      LAYER M4 ;
      RECT 0.000 56.748 0.096 56.844 ;
    END
  END R0_data[289]
  PIN R0_data[290]
    DIRECTION OUTPUT ;
    USE SIGNAL ;
    SHAPE ABUTMENT ;
    PORT
      LAYER M4 ;
      RECT 81.904 56.748 82.000 56.844 ;
    END
  END R0_data[290]
  PIN R0_data[291]
    DIRECTION OUTPUT ;
    USE SIGNAL ;
    SHAPE ABUTMENT ;
    PORT
      LAYER M5 ;
      RECT 22.716 207.904 22.812 208.000 ;
    END
  END R0_data[291]
  PIN R0_data[292]
    DIRECTION OUTPUT ;
    USE SIGNAL ;
    SHAPE ABUTMENT ;
    PORT
      LAYER M5 ;
      RECT 22.716 0.000 22.812 0.096 ;
    END
  END R0_data[292]
  PIN R0_data[293]
    DIRECTION OUTPUT ;
    USE SIGNAL ;
    SHAPE ABUTMENT ;
    PORT
      LAYER M4 ;
      RECT 0.000 57.468 0.096 57.564 ;
    END
  END R0_data[293]
  PIN R0_data[294]
    DIRECTION OUTPUT ;
    USE SIGNAL ;
    SHAPE ABUTMENT ;
    PORT
      LAYER M4 ;
      RECT 81.904 57.468 82.000 57.564 ;
    END
  END R0_data[294]
  PIN R0_data[295]
    DIRECTION OUTPUT ;
    USE SIGNAL ;
    SHAPE ABUTMENT ;
    PORT
      LAYER M5 ;
      RECT 23.004 207.904 23.100 208.000 ;
    END
  END R0_data[295]
  PIN R0_data[296]
    DIRECTION OUTPUT ;
    USE SIGNAL ;
    SHAPE ABUTMENT ;
    PORT
      LAYER M5 ;
      RECT 23.004 0.000 23.100 0.096 ;
    END
  END R0_data[296]
  PIN R0_data[297]
    DIRECTION OUTPUT ;
    USE SIGNAL ;
    SHAPE ABUTMENT ;
    PORT
      LAYER M4 ;
      RECT 0.000 58.236 0.096 58.332 ;
    END
  END R0_data[297]
  PIN R0_data[298]
    DIRECTION OUTPUT ;
    USE SIGNAL ;
    SHAPE ABUTMENT ;
    PORT
      LAYER M4 ;
      RECT 81.904 58.236 82.000 58.332 ;
    END
  END R0_data[298]
  PIN R0_data[299]
    DIRECTION OUTPUT ;
    USE SIGNAL ;
    SHAPE ABUTMENT ;
    PORT
      LAYER M5 ;
      RECT 23.292 207.904 23.388 208.000 ;
    END
  END R0_data[299]
  PIN R0_data[300]
    DIRECTION OUTPUT ;
    USE SIGNAL ;
    SHAPE ABUTMENT ;
    PORT
      LAYER M5 ;
      RECT 23.292 0.000 23.388 0.096 ;
    END
  END R0_data[300]
  PIN R0_data[301]
    DIRECTION OUTPUT ;
    USE SIGNAL ;
    SHAPE ABUTMENT ;
    PORT
      LAYER M4 ;
      RECT 0.000 58.956 0.096 59.052 ;
    END
  END R0_data[301]
  PIN R0_data[302]
    DIRECTION OUTPUT ;
    USE SIGNAL ;
    SHAPE ABUTMENT ;
    PORT
      LAYER M4 ;
      RECT 81.904 58.956 82.000 59.052 ;
    END
  END R0_data[302]
  PIN R0_data[303]
    DIRECTION OUTPUT ;
    USE SIGNAL ;
    SHAPE ABUTMENT ;
    PORT
      LAYER M5 ;
      RECT 23.580 207.904 23.676 208.000 ;
    END
  END R0_data[303]
  PIN R0_data[304]
    DIRECTION OUTPUT ;
    USE SIGNAL ;
    SHAPE ABUTMENT ;
    PORT
      LAYER M5 ;
      RECT 23.580 0.000 23.676 0.096 ;
    END
  END R0_data[304]
  PIN R0_data[305]
    DIRECTION OUTPUT ;
    USE SIGNAL ;
    SHAPE ABUTMENT ;
    PORT
      LAYER M4 ;
      RECT 0.000 59.724 0.096 59.820 ;
    END
  END R0_data[305]
  PIN R0_data[306]
    DIRECTION OUTPUT ;
    USE SIGNAL ;
    SHAPE ABUTMENT ;
    PORT
      LAYER M4 ;
      RECT 81.904 59.724 82.000 59.820 ;
    END
  END R0_data[306]
  PIN R0_data[307]
    DIRECTION OUTPUT ;
    USE SIGNAL ;
    SHAPE ABUTMENT ;
    PORT
      LAYER M5 ;
      RECT 23.868 207.904 23.964 208.000 ;
    END
  END R0_data[307]
  PIN R0_data[308]
    DIRECTION OUTPUT ;
    USE SIGNAL ;
    SHAPE ABUTMENT ;
    PORT
      LAYER M5 ;
      RECT 23.868 0.000 23.964 0.096 ;
    END
  END R0_data[308]
  PIN R0_data[309]
    DIRECTION OUTPUT ;
    USE SIGNAL ;
    SHAPE ABUTMENT ;
    PORT
      LAYER M4 ;
      RECT 0.000 60.444 0.096 60.540 ;
    END
  END R0_data[309]
  PIN R0_data[310]
    DIRECTION OUTPUT ;
    USE SIGNAL ;
    SHAPE ABUTMENT ;
    PORT
      LAYER M4 ;
      RECT 81.904 60.444 82.000 60.540 ;
    END
  END R0_data[310]
  PIN R0_data[311]
    DIRECTION OUTPUT ;
    USE SIGNAL ;
    SHAPE ABUTMENT ;
    PORT
      LAYER M5 ;
      RECT 24.156 207.904 24.252 208.000 ;
    END
  END R0_data[311]
  PIN R0_data[312]
    DIRECTION OUTPUT ;
    USE SIGNAL ;
    SHAPE ABUTMENT ;
    PORT
      LAYER M5 ;
      RECT 24.156 0.000 24.252 0.096 ;
    END
  END R0_data[312]
  PIN R0_data[313]
    DIRECTION OUTPUT ;
    USE SIGNAL ;
    SHAPE ABUTMENT ;
    PORT
      LAYER M4 ;
      RECT 0.000 61.212 0.096 61.308 ;
    END
  END R0_data[313]
  PIN R0_data[314]
    DIRECTION OUTPUT ;
    USE SIGNAL ;
    SHAPE ABUTMENT ;
    PORT
      LAYER M4 ;
      RECT 81.904 61.212 82.000 61.308 ;
    END
  END R0_data[314]
  PIN R0_data[315]
    DIRECTION OUTPUT ;
    USE SIGNAL ;
    SHAPE ABUTMENT ;
    PORT
      LAYER M5 ;
      RECT 24.444 207.904 24.540 208.000 ;
    END
  END R0_data[315]
  PIN R0_data[316]
    DIRECTION OUTPUT ;
    USE SIGNAL ;
    SHAPE ABUTMENT ;
    PORT
      LAYER M5 ;
      RECT 24.444 0.000 24.540 0.096 ;
    END
  END R0_data[316]
  PIN R0_data[317]
    DIRECTION OUTPUT ;
    USE SIGNAL ;
    SHAPE ABUTMENT ;
    PORT
      LAYER M4 ;
      RECT 0.000 61.932 0.096 62.028 ;
    END
  END R0_data[317]
  PIN R0_data[318]
    DIRECTION OUTPUT ;
    USE SIGNAL ;
    SHAPE ABUTMENT ;
    PORT
      LAYER M4 ;
      RECT 81.904 61.932 82.000 62.028 ;
    END
  END R0_data[318]
  PIN R0_data[319]
    DIRECTION OUTPUT ;
    USE SIGNAL ;
    SHAPE ABUTMENT ;
    PORT
      LAYER M5 ;
      RECT 24.732 207.904 24.828 208.000 ;
    END
  END R0_data[319]
  PIN R0_data[320]
    DIRECTION OUTPUT ;
    USE SIGNAL ;
    SHAPE ABUTMENT ;
    PORT
      LAYER M5 ;
      RECT 24.732 0.000 24.828 0.096 ;
    END
  END R0_data[320]
  PIN R0_data[321]
    DIRECTION OUTPUT ;
    USE SIGNAL ;
    SHAPE ABUTMENT ;
    PORT
      LAYER M4 ;
      RECT 0.000 62.700 0.096 62.796 ;
    END
  END R0_data[321]
  PIN R0_data[322]
    DIRECTION OUTPUT ;
    USE SIGNAL ;
    SHAPE ABUTMENT ;
    PORT
      LAYER M4 ;
      RECT 81.904 62.700 82.000 62.796 ;
    END
  END R0_data[322]
  PIN R0_data[323]
    DIRECTION OUTPUT ;
    USE SIGNAL ;
    SHAPE ABUTMENT ;
    PORT
      LAYER M5 ;
      RECT 25.020 207.904 25.116 208.000 ;
    END
  END R0_data[323]
  PIN R0_data[324]
    DIRECTION OUTPUT ;
    USE SIGNAL ;
    SHAPE ABUTMENT ;
    PORT
      LAYER M5 ;
      RECT 25.020 0.000 25.116 0.096 ;
    END
  END R0_data[324]
  PIN R0_data[325]
    DIRECTION OUTPUT ;
    USE SIGNAL ;
    SHAPE ABUTMENT ;
    PORT
      LAYER M4 ;
      RECT 0.000 63.420 0.096 63.516 ;
    END
  END R0_data[325]
  PIN R0_data[326]
    DIRECTION OUTPUT ;
    USE SIGNAL ;
    SHAPE ABUTMENT ;
    PORT
      LAYER M4 ;
      RECT 81.904 63.420 82.000 63.516 ;
    END
  END R0_data[326]
  PIN R0_data[327]
    DIRECTION OUTPUT ;
    USE SIGNAL ;
    SHAPE ABUTMENT ;
    PORT
      LAYER M5 ;
      RECT 25.308 207.904 25.404 208.000 ;
    END
  END R0_data[327]
  PIN R0_data[328]
    DIRECTION OUTPUT ;
    USE SIGNAL ;
    SHAPE ABUTMENT ;
    PORT
      LAYER M5 ;
      RECT 25.308 0.000 25.404 0.096 ;
    END
  END R0_data[328]
  PIN R0_data[329]
    DIRECTION OUTPUT ;
    USE SIGNAL ;
    SHAPE ABUTMENT ;
    PORT
      LAYER M4 ;
      RECT 0.000 64.188 0.096 64.284 ;
    END
  END R0_data[329]
  PIN R0_data[330]
    DIRECTION OUTPUT ;
    USE SIGNAL ;
    SHAPE ABUTMENT ;
    PORT
      LAYER M4 ;
      RECT 81.904 64.188 82.000 64.284 ;
    END
  END R0_data[330]
  PIN R0_data[331]
    DIRECTION OUTPUT ;
    USE SIGNAL ;
    SHAPE ABUTMENT ;
    PORT
      LAYER M5 ;
      RECT 25.596 207.904 25.692 208.000 ;
    END
  END R0_data[331]
  PIN R0_data[332]
    DIRECTION OUTPUT ;
    USE SIGNAL ;
    SHAPE ABUTMENT ;
    PORT
      LAYER M5 ;
      RECT 25.596 0.000 25.692 0.096 ;
    END
  END R0_data[332]
  PIN R0_data[333]
    DIRECTION OUTPUT ;
    USE SIGNAL ;
    SHAPE ABUTMENT ;
    PORT
      LAYER M4 ;
      RECT 0.000 64.908 0.096 65.004 ;
    END
  END R0_data[333]
  PIN R0_data[334]
    DIRECTION OUTPUT ;
    USE SIGNAL ;
    SHAPE ABUTMENT ;
    PORT
      LAYER M4 ;
      RECT 81.904 64.908 82.000 65.004 ;
    END
  END R0_data[334]
  PIN R0_data[335]
    DIRECTION OUTPUT ;
    USE SIGNAL ;
    SHAPE ABUTMENT ;
    PORT
      LAYER M5 ;
      RECT 25.884 207.904 25.980 208.000 ;
    END
  END R0_data[335]
  PIN R0_data[336]
    DIRECTION OUTPUT ;
    USE SIGNAL ;
    SHAPE ABUTMENT ;
    PORT
      LAYER M5 ;
      RECT 25.884 0.000 25.980 0.096 ;
    END
  END R0_data[336]
  PIN R0_data[337]
    DIRECTION OUTPUT ;
    USE SIGNAL ;
    SHAPE ABUTMENT ;
    PORT
      LAYER M4 ;
      RECT 0.000 65.676 0.096 65.772 ;
    END
  END R0_data[337]
  PIN R0_data[338]
    DIRECTION OUTPUT ;
    USE SIGNAL ;
    SHAPE ABUTMENT ;
    PORT
      LAYER M4 ;
      RECT 81.904 65.676 82.000 65.772 ;
    END
  END R0_data[338]
  PIN R0_data[339]
    DIRECTION OUTPUT ;
    USE SIGNAL ;
    SHAPE ABUTMENT ;
    PORT
      LAYER M5 ;
      RECT 26.172 207.904 26.268 208.000 ;
    END
  END R0_data[339]
  PIN R0_data[340]
    DIRECTION OUTPUT ;
    USE SIGNAL ;
    SHAPE ABUTMENT ;
    PORT
      LAYER M5 ;
      RECT 26.172 0.000 26.268 0.096 ;
    END
  END R0_data[340]
  PIN R0_data[341]
    DIRECTION OUTPUT ;
    USE SIGNAL ;
    SHAPE ABUTMENT ;
    PORT
      LAYER M4 ;
      RECT 0.000 66.396 0.096 66.492 ;
    END
  END R0_data[341]
  PIN R0_data[342]
    DIRECTION OUTPUT ;
    USE SIGNAL ;
    SHAPE ABUTMENT ;
    PORT
      LAYER M4 ;
      RECT 81.904 66.396 82.000 66.492 ;
    END
  END R0_data[342]
  PIN R0_data[343]
    DIRECTION OUTPUT ;
    USE SIGNAL ;
    SHAPE ABUTMENT ;
    PORT
      LAYER M5 ;
      RECT 26.460 207.904 26.556 208.000 ;
    END
  END R0_data[343]
  PIN R0_data[344]
    DIRECTION OUTPUT ;
    USE SIGNAL ;
    SHAPE ABUTMENT ;
    PORT
      LAYER M5 ;
      RECT 26.460 0.000 26.556 0.096 ;
    END
  END R0_data[344]
  PIN R0_data[345]
    DIRECTION OUTPUT ;
    USE SIGNAL ;
    SHAPE ABUTMENT ;
    PORT
      LAYER M4 ;
      RECT 0.000 67.164 0.096 67.260 ;
    END
  END R0_data[345]
  PIN R0_data[346]
    DIRECTION OUTPUT ;
    USE SIGNAL ;
    SHAPE ABUTMENT ;
    PORT
      LAYER M4 ;
      RECT 81.904 67.164 82.000 67.260 ;
    END
  END R0_data[346]
  PIN R0_data[347]
    DIRECTION OUTPUT ;
    USE SIGNAL ;
    SHAPE ABUTMENT ;
    PORT
      LAYER M5 ;
      RECT 26.748 207.904 26.844 208.000 ;
    END
  END R0_data[347]
  PIN R0_data[348]
    DIRECTION OUTPUT ;
    USE SIGNAL ;
    SHAPE ABUTMENT ;
    PORT
      LAYER M5 ;
      RECT 26.748 0.000 26.844 0.096 ;
    END
  END R0_data[348]
  PIN R0_data[349]
    DIRECTION OUTPUT ;
    USE SIGNAL ;
    SHAPE ABUTMENT ;
    PORT
      LAYER M4 ;
      RECT 0.000 67.884 0.096 67.980 ;
    END
  END R0_data[349]
  PIN R0_data[350]
    DIRECTION OUTPUT ;
    USE SIGNAL ;
    SHAPE ABUTMENT ;
    PORT
      LAYER M4 ;
      RECT 81.904 67.884 82.000 67.980 ;
    END
  END R0_data[350]
  PIN R0_data[351]
    DIRECTION OUTPUT ;
    USE SIGNAL ;
    SHAPE ABUTMENT ;
    PORT
      LAYER M5 ;
      RECT 27.036 207.904 27.132 208.000 ;
    END
  END R0_data[351]
  PIN R0_data[352]
    DIRECTION OUTPUT ;
    USE SIGNAL ;
    SHAPE ABUTMENT ;
    PORT
      LAYER M5 ;
      RECT 27.036 0.000 27.132 0.096 ;
    END
  END R0_data[352]
  PIN R0_data[353]
    DIRECTION OUTPUT ;
    USE SIGNAL ;
    SHAPE ABUTMENT ;
    PORT
      LAYER M4 ;
      RECT 0.000 68.652 0.096 68.748 ;
    END
  END R0_data[353]
  PIN R0_data[354]
    DIRECTION OUTPUT ;
    USE SIGNAL ;
    SHAPE ABUTMENT ;
    PORT
      LAYER M4 ;
      RECT 81.904 68.652 82.000 68.748 ;
    END
  END R0_data[354]
  PIN R0_data[355]
    DIRECTION OUTPUT ;
    USE SIGNAL ;
    SHAPE ABUTMENT ;
    PORT
      LAYER M5 ;
      RECT 27.324 207.904 27.420 208.000 ;
    END
  END R0_data[355]
  PIN R0_data[356]
    DIRECTION OUTPUT ;
    USE SIGNAL ;
    SHAPE ABUTMENT ;
    PORT
      LAYER M5 ;
      RECT 27.324 0.000 27.420 0.096 ;
    END
  END R0_data[356]
  PIN R0_data[357]
    DIRECTION OUTPUT ;
    USE SIGNAL ;
    SHAPE ABUTMENT ;
    PORT
      LAYER M4 ;
      RECT 0.000 69.372 0.096 69.468 ;
    END
  END R0_data[357]
  PIN R0_data[358]
    DIRECTION OUTPUT ;
    USE SIGNAL ;
    SHAPE ABUTMENT ;
    PORT
      LAYER M4 ;
      RECT 81.904 69.372 82.000 69.468 ;
    END
  END R0_data[358]
  PIN R0_data[359]
    DIRECTION OUTPUT ;
    USE SIGNAL ;
    SHAPE ABUTMENT ;
    PORT
      LAYER M5 ;
      RECT 27.612 207.904 27.708 208.000 ;
    END
  END R0_data[359]
  PIN R0_data[360]
    DIRECTION OUTPUT ;
    USE SIGNAL ;
    SHAPE ABUTMENT ;
    PORT
      LAYER M5 ;
      RECT 27.612 0.000 27.708 0.096 ;
    END
  END R0_data[360]
  PIN R0_data[361]
    DIRECTION OUTPUT ;
    USE SIGNAL ;
    SHAPE ABUTMENT ;
    PORT
      LAYER M4 ;
      RECT 0.000 70.140 0.096 70.236 ;
    END
  END R0_data[361]
  PIN R0_data[362]
    DIRECTION OUTPUT ;
    USE SIGNAL ;
    SHAPE ABUTMENT ;
    PORT
      LAYER M4 ;
      RECT 81.904 70.140 82.000 70.236 ;
    END
  END R0_data[362]
  PIN R0_data[363]
    DIRECTION OUTPUT ;
    USE SIGNAL ;
    SHAPE ABUTMENT ;
    PORT
      LAYER M5 ;
      RECT 27.900 207.904 27.996 208.000 ;
    END
  END R0_data[363]
  PIN R0_data[364]
    DIRECTION OUTPUT ;
    USE SIGNAL ;
    SHAPE ABUTMENT ;
    PORT
      LAYER M5 ;
      RECT 27.900 0.000 27.996 0.096 ;
    END
  END R0_data[364]
  PIN R0_data[365]
    DIRECTION OUTPUT ;
    USE SIGNAL ;
    SHAPE ABUTMENT ;
    PORT
      LAYER M4 ;
      RECT 0.000 70.860 0.096 70.956 ;
    END
  END R0_data[365]
  PIN R0_data[366]
    DIRECTION OUTPUT ;
    USE SIGNAL ;
    SHAPE ABUTMENT ;
    PORT
      LAYER M4 ;
      RECT 81.904 70.860 82.000 70.956 ;
    END
  END R0_data[366]
  PIN R0_data[367]
    DIRECTION OUTPUT ;
    USE SIGNAL ;
    SHAPE ABUTMENT ;
    PORT
      LAYER M5 ;
      RECT 28.188 207.904 28.284 208.000 ;
    END
  END R0_data[367]
  PIN R0_data[368]
    DIRECTION OUTPUT ;
    USE SIGNAL ;
    SHAPE ABUTMENT ;
    PORT
      LAYER M5 ;
      RECT 28.188 0.000 28.284 0.096 ;
    END
  END R0_data[368]
  PIN R0_data[369]
    DIRECTION OUTPUT ;
    USE SIGNAL ;
    SHAPE ABUTMENT ;
    PORT
      LAYER M4 ;
      RECT 0.000 71.628 0.096 71.724 ;
    END
  END R0_data[369]
  PIN R0_data[370]
    DIRECTION OUTPUT ;
    USE SIGNAL ;
    SHAPE ABUTMENT ;
    PORT
      LAYER M4 ;
      RECT 81.904 71.628 82.000 71.724 ;
    END
  END R0_data[370]
  PIN R0_data[371]
    DIRECTION OUTPUT ;
    USE SIGNAL ;
    SHAPE ABUTMENT ;
    PORT
      LAYER M5 ;
      RECT 28.476 207.904 28.572 208.000 ;
    END
  END R0_data[371]
  PIN R0_data[372]
    DIRECTION OUTPUT ;
    USE SIGNAL ;
    SHAPE ABUTMENT ;
    PORT
      LAYER M5 ;
      RECT 28.476 0.000 28.572 0.096 ;
    END
  END R0_data[372]
  PIN R0_data[373]
    DIRECTION OUTPUT ;
    USE SIGNAL ;
    SHAPE ABUTMENT ;
    PORT
      LAYER M4 ;
      RECT 0.000 72.348 0.096 72.444 ;
    END
  END R0_data[373]
  PIN R0_data[374]
    DIRECTION OUTPUT ;
    USE SIGNAL ;
    SHAPE ABUTMENT ;
    PORT
      LAYER M4 ;
      RECT 81.904 72.348 82.000 72.444 ;
    END
  END R0_data[374]
  PIN R0_data[375]
    DIRECTION OUTPUT ;
    USE SIGNAL ;
    SHAPE ABUTMENT ;
    PORT
      LAYER M5 ;
      RECT 28.764 207.904 28.860 208.000 ;
    END
  END R0_data[375]
  PIN R0_data[376]
    DIRECTION OUTPUT ;
    USE SIGNAL ;
    SHAPE ABUTMENT ;
    PORT
      LAYER M5 ;
      RECT 28.764 0.000 28.860 0.096 ;
    END
  END R0_data[376]
  PIN R0_data[377]
    DIRECTION OUTPUT ;
    USE SIGNAL ;
    SHAPE ABUTMENT ;
    PORT
      LAYER M4 ;
      RECT 0.000 73.116 0.096 73.212 ;
    END
  END R0_data[377]
  PIN R0_data[378]
    DIRECTION OUTPUT ;
    USE SIGNAL ;
    SHAPE ABUTMENT ;
    PORT
      LAYER M4 ;
      RECT 81.904 73.116 82.000 73.212 ;
    END
  END R0_data[378]
  PIN R0_data[379]
    DIRECTION OUTPUT ;
    USE SIGNAL ;
    SHAPE ABUTMENT ;
    PORT
      LAYER M5 ;
      RECT 29.100 207.904 29.196 208.000 ;
    END
  END R0_data[379]
  PIN R0_data[380]
    DIRECTION OUTPUT ;
    USE SIGNAL ;
    SHAPE ABUTMENT ;
    PORT
      LAYER M5 ;
      RECT 29.100 0.000 29.196 0.096 ;
    END
  END R0_data[380]
  PIN R0_data[381]
    DIRECTION OUTPUT ;
    USE SIGNAL ;
    SHAPE ABUTMENT ;
    PORT
      LAYER M4 ;
      RECT 0.000 73.836 0.096 73.932 ;
    END
  END R0_data[381]
  PIN R0_data[382]
    DIRECTION OUTPUT ;
    USE SIGNAL ;
    SHAPE ABUTMENT ;
    PORT
      LAYER M4 ;
      RECT 81.904 73.836 82.000 73.932 ;
    END
  END R0_data[382]
  PIN R0_data[383]
    DIRECTION OUTPUT ;
    USE SIGNAL ;
    SHAPE ABUTMENT ;
    PORT
      LAYER M5 ;
      RECT 29.388 207.904 29.484 208.000 ;
    END
  END R0_data[383]
  PIN R0_data[384]
    DIRECTION OUTPUT ;
    USE SIGNAL ;
    SHAPE ABUTMENT ;
    PORT
      LAYER M5 ;
      RECT 29.388 0.000 29.484 0.096 ;
    END
  END R0_data[384]
  PIN R0_data[385]
    DIRECTION OUTPUT ;
    USE SIGNAL ;
    SHAPE ABUTMENT ;
    PORT
      LAYER M4 ;
      RECT 0.000 74.604 0.096 74.700 ;
    END
  END R0_data[385]
  PIN R0_data[386]
    DIRECTION OUTPUT ;
    USE SIGNAL ;
    SHAPE ABUTMENT ;
    PORT
      LAYER M4 ;
      RECT 81.904 74.604 82.000 74.700 ;
    END
  END R0_data[386]
  PIN R0_data[387]
    DIRECTION OUTPUT ;
    USE SIGNAL ;
    SHAPE ABUTMENT ;
    PORT
      LAYER M5 ;
      RECT 29.676 207.904 29.772 208.000 ;
    END
  END R0_data[387]
  PIN R0_data[388]
    DIRECTION OUTPUT ;
    USE SIGNAL ;
    SHAPE ABUTMENT ;
    PORT
      LAYER M5 ;
      RECT 29.676 0.000 29.772 0.096 ;
    END
  END R0_data[388]
  PIN R0_data[389]
    DIRECTION OUTPUT ;
    USE SIGNAL ;
    SHAPE ABUTMENT ;
    PORT
      LAYER M4 ;
      RECT 0.000 75.324 0.096 75.420 ;
    END
  END R0_data[389]
  PIN R0_data[390]
    DIRECTION OUTPUT ;
    USE SIGNAL ;
    SHAPE ABUTMENT ;
    PORT
      LAYER M4 ;
      RECT 81.904 75.324 82.000 75.420 ;
    END
  END R0_data[390]
  PIN R0_data[391]
    DIRECTION OUTPUT ;
    USE SIGNAL ;
    SHAPE ABUTMENT ;
    PORT
      LAYER M5 ;
      RECT 29.964 207.904 30.060 208.000 ;
    END
  END R0_data[391]
  PIN R0_data[392]
    DIRECTION OUTPUT ;
    USE SIGNAL ;
    SHAPE ABUTMENT ;
    PORT
      LAYER M5 ;
      RECT 29.964 0.000 30.060 0.096 ;
    END
  END R0_data[392]
  PIN R0_data[393]
    DIRECTION OUTPUT ;
    USE SIGNAL ;
    SHAPE ABUTMENT ;
    PORT
      LAYER M4 ;
      RECT 0.000 76.092 0.096 76.188 ;
    END
  END R0_data[393]
  PIN R0_data[394]
    DIRECTION OUTPUT ;
    USE SIGNAL ;
    SHAPE ABUTMENT ;
    PORT
      LAYER M4 ;
      RECT 81.904 76.092 82.000 76.188 ;
    END
  END R0_data[394]
  PIN R0_data[395]
    DIRECTION OUTPUT ;
    USE SIGNAL ;
    SHAPE ABUTMENT ;
    PORT
      LAYER M5 ;
      RECT 30.252 207.904 30.348 208.000 ;
    END
  END R0_data[395]
  PIN R0_data[396]
    DIRECTION OUTPUT ;
    USE SIGNAL ;
    SHAPE ABUTMENT ;
    PORT
      LAYER M5 ;
      RECT 30.252 0.000 30.348 0.096 ;
    END
  END R0_data[396]
  PIN R0_data[397]
    DIRECTION OUTPUT ;
    USE SIGNAL ;
    SHAPE ABUTMENT ;
    PORT
      LAYER M4 ;
      RECT 0.000 76.812 0.096 76.908 ;
    END
  END R0_data[397]
  PIN R0_data[398]
    DIRECTION OUTPUT ;
    USE SIGNAL ;
    SHAPE ABUTMENT ;
    PORT
      LAYER M4 ;
      RECT 81.904 76.812 82.000 76.908 ;
    END
  END R0_data[398]
  PIN R0_data[399]
    DIRECTION OUTPUT ;
    USE SIGNAL ;
    SHAPE ABUTMENT ;
    PORT
      LAYER M5 ;
      RECT 30.540 207.904 30.636 208.000 ;
    END
  END R0_data[399]
  PIN R0_data[400]
    DIRECTION OUTPUT ;
    USE SIGNAL ;
    SHAPE ABUTMENT ;
    PORT
      LAYER M5 ;
      RECT 30.540 0.000 30.636 0.096 ;
    END
  END R0_data[400]
  PIN R0_data[401]
    DIRECTION OUTPUT ;
    USE SIGNAL ;
    SHAPE ABUTMENT ;
    PORT
      LAYER M4 ;
      RECT 0.000 77.580 0.096 77.676 ;
    END
  END R0_data[401]
  PIN R0_data[402]
    DIRECTION OUTPUT ;
    USE SIGNAL ;
    SHAPE ABUTMENT ;
    PORT
      LAYER M4 ;
      RECT 81.904 77.580 82.000 77.676 ;
    END
  END R0_data[402]
  PIN R0_data[403]
    DIRECTION OUTPUT ;
    USE SIGNAL ;
    SHAPE ABUTMENT ;
    PORT
      LAYER M5 ;
      RECT 30.828 207.904 30.924 208.000 ;
    END
  END R0_data[403]
  PIN R0_data[404]
    DIRECTION OUTPUT ;
    USE SIGNAL ;
    SHAPE ABUTMENT ;
    PORT
      LAYER M5 ;
      RECT 30.828 0.000 30.924 0.096 ;
    END
  END R0_data[404]
  PIN R0_data[405]
    DIRECTION OUTPUT ;
    USE SIGNAL ;
    SHAPE ABUTMENT ;
    PORT
      LAYER M4 ;
      RECT 0.000 78.300 0.096 78.396 ;
    END
  END R0_data[405]
  PIN R0_data[406]
    DIRECTION OUTPUT ;
    USE SIGNAL ;
    SHAPE ABUTMENT ;
    PORT
      LAYER M4 ;
      RECT 81.904 78.300 82.000 78.396 ;
    END
  END R0_data[406]
  PIN R0_data[407]
    DIRECTION OUTPUT ;
    USE SIGNAL ;
    SHAPE ABUTMENT ;
    PORT
      LAYER M5 ;
      RECT 31.116 207.904 31.212 208.000 ;
    END
  END R0_data[407]
  PIN R0_data[408]
    DIRECTION OUTPUT ;
    USE SIGNAL ;
    SHAPE ABUTMENT ;
    PORT
      LAYER M5 ;
      RECT 31.116 0.000 31.212 0.096 ;
    END
  END R0_data[408]
  PIN R0_data[409]
    DIRECTION OUTPUT ;
    USE SIGNAL ;
    SHAPE ABUTMENT ;
    PORT
      LAYER M4 ;
      RECT 0.000 79.068 0.096 79.164 ;
    END
  END R0_data[409]
  PIN R0_data[410]
    DIRECTION OUTPUT ;
    USE SIGNAL ;
    SHAPE ABUTMENT ;
    PORT
      LAYER M4 ;
      RECT 81.904 79.068 82.000 79.164 ;
    END
  END R0_data[410]
  PIN R0_data[411]
    DIRECTION OUTPUT ;
    USE SIGNAL ;
    SHAPE ABUTMENT ;
    PORT
      LAYER M5 ;
      RECT 31.404 207.904 31.500 208.000 ;
    END
  END R0_data[411]
  PIN R0_data[412]
    DIRECTION OUTPUT ;
    USE SIGNAL ;
    SHAPE ABUTMENT ;
    PORT
      LAYER M5 ;
      RECT 31.404 0.000 31.500 0.096 ;
    END
  END R0_data[412]
  PIN R0_data[413]
    DIRECTION OUTPUT ;
    USE SIGNAL ;
    SHAPE ABUTMENT ;
    PORT
      LAYER M4 ;
      RECT 0.000 79.788 0.096 79.884 ;
    END
  END R0_data[413]
  PIN R0_data[414]
    DIRECTION OUTPUT ;
    USE SIGNAL ;
    SHAPE ABUTMENT ;
    PORT
      LAYER M4 ;
      RECT 81.904 79.788 82.000 79.884 ;
    END
  END R0_data[414]
  PIN R0_data[415]
    DIRECTION OUTPUT ;
    USE SIGNAL ;
    SHAPE ABUTMENT ;
    PORT
      LAYER M5 ;
      RECT 31.692 207.904 31.788 208.000 ;
    END
  END R0_data[415]
  PIN R0_data[416]
    DIRECTION OUTPUT ;
    USE SIGNAL ;
    SHAPE ABUTMENT ;
    PORT
      LAYER M5 ;
      RECT 31.692 0.000 31.788 0.096 ;
    END
  END R0_data[416]
  PIN R0_data[417]
    DIRECTION OUTPUT ;
    USE SIGNAL ;
    SHAPE ABUTMENT ;
    PORT
      LAYER M4 ;
      RECT 0.000 80.556 0.096 80.652 ;
    END
  END R0_data[417]
  PIN R0_data[418]
    DIRECTION OUTPUT ;
    USE SIGNAL ;
    SHAPE ABUTMENT ;
    PORT
      LAYER M4 ;
      RECT 81.904 80.556 82.000 80.652 ;
    END
  END R0_data[418]
  PIN R0_data[419]
    DIRECTION OUTPUT ;
    USE SIGNAL ;
    SHAPE ABUTMENT ;
    PORT
      LAYER M5 ;
      RECT 31.980 207.904 32.076 208.000 ;
    END
  END R0_data[419]
  PIN R0_data[420]
    DIRECTION OUTPUT ;
    USE SIGNAL ;
    SHAPE ABUTMENT ;
    PORT
      LAYER M5 ;
      RECT 31.980 0.000 32.076 0.096 ;
    END
  END R0_data[420]
  PIN R0_data[421]
    DIRECTION OUTPUT ;
    USE SIGNAL ;
    SHAPE ABUTMENT ;
    PORT
      LAYER M4 ;
      RECT 0.000 81.276 0.096 81.372 ;
    END
  END R0_data[421]
  PIN R0_data[422]
    DIRECTION OUTPUT ;
    USE SIGNAL ;
    SHAPE ABUTMENT ;
    PORT
      LAYER M4 ;
      RECT 81.904 81.276 82.000 81.372 ;
    END
  END R0_data[422]
  PIN R0_data[423]
    DIRECTION OUTPUT ;
    USE SIGNAL ;
    SHAPE ABUTMENT ;
    PORT
      LAYER M5 ;
      RECT 32.268 207.904 32.364 208.000 ;
    END
  END R0_data[423]
  PIN R0_data[424]
    DIRECTION OUTPUT ;
    USE SIGNAL ;
    SHAPE ABUTMENT ;
    PORT
      LAYER M5 ;
      RECT 32.268 0.000 32.364 0.096 ;
    END
  END R0_data[424]
  PIN R0_data[425]
    DIRECTION OUTPUT ;
    USE SIGNAL ;
    SHAPE ABUTMENT ;
    PORT
      LAYER M4 ;
      RECT 0.000 82.044 0.096 82.140 ;
    END
  END R0_data[425]
  PIN R0_data[426]
    DIRECTION OUTPUT ;
    USE SIGNAL ;
    SHAPE ABUTMENT ;
    PORT
      LAYER M4 ;
      RECT 81.904 82.044 82.000 82.140 ;
    END
  END R0_data[426]
  PIN R0_data[427]
    DIRECTION OUTPUT ;
    USE SIGNAL ;
    SHAPE ABUTMENT ;
    PORT
      LAYER M5 ;
      RECT 32.556 207.904 32.652 208.000 ;
    END
  END R0_data[427]
  PIN R0_data[428]
    DIRECTION OUTPUT ;
    USE SIGNAL ;
    SHAPE ABUTMENT ;
    PORT
      LAYER M5 ;
      RECT 32.556 0.000 32.652 0.096 ;
    END
  END R0_data[428]
  PIN R0_data[429]
    DIRECTION OUTPUT ;
    USE SIGNAL ;
    SHAPE ABUTMENT ;
    PORT
      LAYER M4 ;
      RECT 0.000 82.764 0.096 82.860 ;
    END
  END R0_data[429]
  PIN R0_data[430]
    DIRECTION OUTPUT ;
    USE SIGNAL ;
    SHAPE ABUTMENT ;
    PORT
      LAYER M4 ;
      RECT 81.904 82.764 82.000 82.860 ;
    END
  END R0_data[430]
  PIN R0_data[431]
    DIRECTION OUTPUT ;
    USE SIGNAL ;
    SHAPE ABUTMENT ;
    PORT
      LAYER M5 ;
      RECT 32.844 207.904 32.940 208.000 ;
    END
  END R0_data[431]
  PIN R0_data[432]
    DIRECTION OUTPUT ;
    USE SIGNAL ;
    SHAPE ABUTMENT ;
    PORT
      LAYER M5 ;
      RECT 32.844 0.000 32.940 0.096 ;
    END
  END R0_data[432]
  PIN R0_data[433]
    DIRECTION OUTPUT ;
    USE SIGNAL ;
    SHAPE ABUTMENT ;
    PORT
      LAYER M4 ;
      RECT 0.000 83.484 0.096 83.580 ;
    END
  END R0_data[433]
  PIN R0_data[434]
    DIRECTION OUTPUT ;
    USE SIGNAL ;
    SHAPE ABUTMENT ;
    PORT
      LAYER M4 ;
      RECT 81.904 83.484 82.000 83.580 ;
    END
  END R0_data[434]
  PIN R0_data[435]
    DIRECTION OUTPUT ;
    USE SIGNAL ;
    SHAPE ABUTMENT ;
    PORT
      LAYER M5 ;
      RECT 33.132 207.904 33.228 208.000 ;
    END
  END R0_data[435]
  PIN R0_data[436]
    DIRECTION OUTPUT ;
    USE SIGNAL ;
    SHAPE ABUTMENT ;
    PORT
      LAYER M5 ;
      RECT 33.132 0.000 33.228 0.096 ;
    END
  END R0_data[436]
  PIN R0_data[437]
    DIRECTION OUTPUT ;
    USE SIGNAL ;
    SHAPE ABUTMENT ;
    PORT
      LAYER M4 ;
      RECT 0.000 84.252 0.096 84.348 ;
    END
  END R0_data[437]
  PIN R0_data[438]
    DIRECTION OUTPUT ;
    USE SIGNAL ;
    SHAPE ABUTMENT ;
    PORT
      LAYER M4 ;
      RECT 81.904 84.252 82.000 84.348 ;
    END
  END R0_data[438]
  PIN R0_data[439]
    DIRECTION OUTPUT ;
    USE SIGNAL ;
    SHAPE ABUTMENT ;
    PORT
      LAYER M5 ;
      RECT 33.420 207.904 33.516 208.000 ;
    END
  END R0_data[439]
  PIN R0_data[440]
    DIRECTION OUTPUT ;
    USE SIGNAL ;
    SHAPE ABUTMENT ;
    PORT
      LAYER M5 ;
      RECT 33.420 0.000 33.516 0.096 ;
    END
  END R0_data[440]
  PIN R0_data[441]
    DIRECTION OUTPUT ;
    USE SIGNAL ;
    SHAPE ABUTMENT ;
    PORT
      LAYER M4 ;
      RECT 0.000 84.972 0.096 85.068 ;
    END
  END R0_data[441]
  PIN R0_data[442]
    DIRECTION OUTPUT ;
    USE SIGNAL ;
    SHAPE ABUTMENT ;
    PORT
      LAYER M4 ;
      RECT 81.904 84.972 82.000 85.068 ;
    END
  END R0_data[442]
  PIN R0_data[443]
    DIRECTION OUTPUT ;
    USE SIGNAL ;
    SHAPE ABUTMENT ;
    PORT
      LAYER M5 ;
      RECT 33.708 207.904 33.804 208.000 ;
    END
  END R0_data[443]
  PIN R0_data[444]
    DIRECTION OUTPUT ;
    USE SIGNAL ;
    SHAPE ABUTMENT ;
    PORT
      LAYER M5 ;
      RECT 33.708 0.000 33.804 0.096 ;
    END
  END R0_data[444]
  PIN R0_data[445]
    DIRECTION OUTPUT ;
    USE SIGNAL ;
    SHAPE ABUTMENT ;
    PORT
      LAYER M4 ;
      RECT 0.000 85.740 0.096 85.836 ;
    END
  END R0_data[445]
  PIN R0_data[446]
    DIRECTION OUTPUT ;
    USE SIGNAL ;
    SHAPE ABUTMENT ;
    PORT
      LAYER M4 ;
      RECT 81.904 85.740 82.000 85.836 ;
    END
  END R0_data[446]
  PIN R0_data[447]
    DIRECTION OUTPUT ;
    USE SIGNAL ;
    SHAPE ABUTMENT ;
    PORT
      LAYER M5 ;
      RECT 33.996 207.904 34.092 208.000 ;
    END
  END R0_data[447]
  PIN R0_data[448]
    DIRECTION OUTPUT ;
    USE SIGNAL ;
    SHAPE ABUTMENT ;
    PORT
      LAYER M5 ;
      RECT 33.996 0.000 34.092 0.096 ;
    END
  END R0_data[448]
  PIN R0_data[449]
    DIRECTION OUTPUT ;
    USE SIGNAL ;
    SHAPE ABUTMENT ;
    PORT
      LAYER M4 ;
      RECT 0.000 86.460 0.096 86.556 ;
    END
  END R0_data[449]
  PIN R0_data[450]
    DIRECTION OUTPUT ;
    USE SIGNAL ;
    SHAPE ABUTMENT ;
    PORT
      LAYER M4 ;
      RECT 81.904 86.460 82.000 86.556 ;
    END
  END R0_data[450]
  PIN R0_data[451]
    DIRECTION OUTPUT ;
    USE SIGNAL ;
    SHAPE ABUTMENT ;
    PORT
      LAYER M5 ;
      RECT 34.284 207.904 34.380 208.000 ;
    END
  END R0_data[451]
  PIN R0_data[452]
    DIRECTION OUTPUT ;
    USE SIGNAL ;
    SHAPE ABUTMENT ;
    PORT
      LAYER M5 ;
      RECT 34.284 0.000 34.380 0.096 ;
    END
  END R0_data[452]
  PIN R0_data[453]
    DIRECTION OUTPUT ;
    USE SIGNAL ;
    SHAPE ABUTMENT ;
    PORT
      LAYER M4 ;
      RECT 0.000 87.228 0.096 87.324 ;
    END
  END R0_data[453]
  PIN R0_data[454]
    DIRECTION OUTPUT ;
    USE SIGNAL ;
    SHAPE ABUTMENT ;
    PORT
      LAYER M4 ;
      RECT 81.904 87.228 82.000 87.324 ;
    END
  END R0_data[454]
  PIN R0_data[455]
    DIRECTION OUTPUT ;
    USE SIGNAL ;
    SHAPE ABUTMENT ;
    PORT
      LAYER M5 ;
      RECT 34.572 207.904 34.668 208.000 ;
    END
  END R0_data[455]
  PIN R0_data[456]
    DIRECTION OUTPUT ;
    USE SIGNAL ;
    SHAPE ABUTMENT ;
    PORT
      LAYER M5 ;
      RECT 34.572 0.000 34.668 0.096 ;
    END
  END R0_data[456]
  PIN R0_data[457]
    DIRECTION OUTPUT ;
    USE SIGNAL ;
    SHAPE ABUTMENT ;
    PORT
      LAYER M4 ;
      RECT 0.000 87.948 0.096 88.044 ;
    END
  END R0_data[457]
  PIN R0_data[458]
    DIRECTION OUTPUT ;
    USE SIGNAL ;
    SHAPE ABUTMENT ;
    PORT
      LAYER M4 ;
      RECT 81.904 87.948 82.000 88.044 ;
    END
  END R0_data[458]
  PIN R0_data[459]
    DIRECTION OUTPUT ;
    USE SIGNAL ;
    SHAPE ABUTMENT ;
    PORT
      LAYER M5 ;
      RECT 34.860 207.904 34.956 208.000 ;
    END
  END R0_data[459]
  PIN R0_data[460]
    DIRECTION OUTPUT ;
    USE SIGNAL ;
    SHAPE ABUTMENT ;
    PORT
      LAYER M5 ;
      RECT 34.860 0.000 34.956 0.096 ;
    END
  END R0_data[460]
  PIN R0_data[461]
    DIRECTION OUTPUT ;
    USE SIGNAL ;
    SHAPE ABUTMENT ;
    PORT
      LAYER M4 ;
      RECT 0.000 88.716 0.096 88.812 ;
    END
  END R0_data[461]
  PIN R0_data[462]
    DIRECTION OUTPUT ;
    USE SIGNAL ;
    SHAPE ABUTMENT ;
    PORT
      LAYER M4 ;
      RECT 81.904 88.716 82.000 88.812 ;
    END
  END R0_data[462]
  PIN R0_data[463]
    DIRECTION OUTPUT ;
    USE SIGNAL ;
    SHAPE ABUTMENT ;
    PORT
      LAYER M5 ;
      RECT 35.148 207.904 35.244 208.000 ;
    END
  END R0_data[463]
  PIN R0_data[464]
    DIRECTION OUTPUT ;
    USE SIGNAL ;
    SHAPE ABUTMENT ;
    PORT
      LAYER M5 ;
      RECT 35.148 0.000 35.244 0.096 ;
    END
  END R0_data[464]
  PIN R0_data[465]
    DIRECTION OUTPUT ;
    USE SIGNAL ;
    SHAPE ABUTMENT ;
    PORT
      LAYER M4 ;
      RECT 0.000 89.436 0.096 89.532 ;
    END
  END R0_data[465]
  PIN R0_data[466]
    DIRECTION OUTPUT ;
    USE SIGNAL ;
    SHAPE ABUTMENT ;
    PORT
      LAYER M4 ;
      RECT 81.904 89.436 82.000 89.532 ;
    END
  END R0_data[466]
  PIN R0_data[467]
    DIRECTION OUTPUT ;
    USE SIGNAL ;
    SHAPE ABUTMENT ;
    PORT
      LAYER M5 ;
      RECT 35.436 207.904 35.532 208.000 ;
    END
  END R0_data[467]
  PIN R0_data[468]
    DIRECTION OUTPUT ;
    USE SIGNAL ;
    SHAPE ABUTMENT ;
    PORT
      LAYER M5 ;
      RECT 35.436 0.000 35.532 0.096 ;
    END
  END R0_data[468]
  PIN R0_data[469]
    DIRECTION OUTPUT ;
    USE SIGNAL ;
    SHAPE ABUTMENT ;
    PORT
      LAYER M4 ;
      RECT 0.000 90.204 0.096 90.300 ;
    END
  END R0_data[469]
  PIN R0_data[470]
    DIRECTION OUTPUT ;
    USE SIGNAL ;
    SHAPE ABUTMENT ;
    PORT
      LAYER M4 ;
      RECT 81.904 90.204 82.000 90.300 ;
    END
  END R0_data[470]
  PIN R0_data[471]
    DIRECTION OUTPUT ;
    USE SIGNAL ;
    SHAPE ABUTMENT ;
    PORT
      LAYER M5 ;
      RECT 35.724 207.904 35.820 208.000 ;
    END
  END R0_data[471]
  PIN R0_data[472]
    DIRECTION OUTPUT ;
    USE SIGNAL ;
    SHAPE ABUTMENT ;
    PORT
      LAYER M5 ;
      RECT 35.724 0.000 35.820 0.096 ;
    END
  END R0_data[472]
  PIN R0_data[473]
    DIRECTION OUTPUT ;
    USE SIGNAL ;
    SHAPE ABUTMENT ;
    PORT
      LAYER M4 ;
      RECT 0.000 90.924 0.096 91.020 ;
    END
  END R0_data[473]
  PIN R0_data[474]
    DIRECTION OUTPUT ;
    USE SIGNAL ;
    SHAPE ABUTMENT ;
    PORT
      LAYER M4 ;
      RECT 81.904 90.924 82.000 91.020 ;
    END
  END R0_data[474]
  PIN R0_data[475]
    DIRECTION OUTPUT ;
    USE SIGNAL ;
    SHAPE ABUTMENT ;
    PORT
      LAYER M5 ;
      RECT 36.012 207.904 36.108 208.000 ;
    END
  END R0_data[475]
  PIN R0_data[476]
    DIRECTION OUTPUT ;
    USE SIGNAL ;
    SHAPE ABUTMENT ;
    PORT
      LAYER M5 ;
      RECT 36.012 0.000 36.108 0.096 ;
    END
  END R0_data[476]
  PIN R0_data[477]
    DIRECTION OUTPUT ;
    USE SIGNAL ;
    SHAPE ABUTMENT ;
    PORT
      LAYER M4 ;
      RECT 0.000 91.692 0.096 91.788 ;
    END
  END R0_data[477]
  PIN R0_data[478]
    DIRECTION OUTPUT ;
    USE SIGNAL ;
    SHAPE ABUTMENT ;
    PORT
      LAYER M4 ;
      RECT 81.904 91.692 82.000 91.788 ;
    END
  END R0_data[478]
  PIN R0_data[479]
    DIRECTION OUTPUT ;
    USE SIGNAL ;
    SHAPE ABUTMENT ;
    PORT
      LAYER M5 ;
      RECT 36.300 207.904 36.396 208.000 ;
    END
  END R0_data[479]
  PIN R0_data[480]
    DIRECTION OUTPUT ;
    USE SIGNAL ;
    SHAPE ABUTMENT ;
    PORT
      LAYER M5 ;
      RECT 36.300 0.000 36.396 0.096 ;
    END
  END R0_data[480]
  PIN R0_data[481]
    DIRECTION OUTPUT ;
    USE SIGNAL ;
    SHAPE ABUTMENT ;
    PORT
      LAYER M4 ;
      RECT 0.000 92.412 0.096 92.508 ;
    END
  END R0_data[481]
  PIN R0_data[482]
    DIRECTION OUTPUT ;
    USE SIGNAL ;
    SHAPE ABUTMENT ;
    PORT
      LAYER M4 ;
      RECT 81.904 92.412 82.000 92.508 ;
    END
  END R0_data[482]
  PIN R0_data[483]
    DIRECTION OUTPUT ;
    USE SIGNAL ;
    SHAPE ABUTMENT ;
    PORT
      LAYER M5 ;
      RECT 36.588 207.904 36.684 208.000 ;
    END
  END R0_data[483]
  PIN R0_data[484]
    DIRECTION OUTPUT ;
    USE SIGNAL ;
    SHAPE ABUTMENT ;
    PORT
      LAYER M5 ;
      RECT 36.588 0.000 36.684 0.096 ;
    END
  END R0_data[484]
  PIN R0_data[485]
    DIRECTION OUTPUT ;
    USE SIGNAL ;
    SHAPE ABUTMENT ;
    PORT
      LAYER M4 ;
      RECT 0.000 93.180 0.096 93.276 ;
    END
  END R0_data[485]
  PIN R0_data[486]
    DIRECTION OUTPUT ;
    USE SIGNAL ;
    SHAPE ABUTMENT ;
    PORT
      LAYER M4 ;
      RECT 81.904 93.180 82.000 93.276 ;
    END
  END R0_data[486]
  PIN R0_data[487]
    DIRECTION OUTPUT ;
    USE SIGNAL ;
    SHAPE ABUTMENT ;
    PORT
      LAYER M5 ;
      RECT 36.876 207.904 36.972 208.000 ;
    END
  END R0_data[487]
  PIN R0_data[488]
    DIRECTION OUTPUT ;
    USE SIGNAL ;
    SHAPE ABUTMENT ;
    PORT
      LAYER M5 ;
      RECT 36.876 0.000 36.972 0.096 ;
    END
  END R0_data[488]
  PIN R0_data[489]
    DIRECTION OUTPUT ;
    USE SIGNAL ;
    SHAPE ABUTMENT ;
    PORT
      LAYER M4 ;
      RECT 0.000 93.900 0.096 93.996 ;
    END
  END R0_data[489]
  PIN R0_data[490]
    DIRECTION OUTPUT ;
    USE SIGNAL ;
    SHAPE ABUTMENT ;
    PORT
      LAYER M4 ;
      RECT 81.904 93.900 82.000 93.996 ;
    END
  END R0_data[490]
  PIN R0_data[491]
    DIRECTION OUTPUT ;
    USE SIGNAL ;
    SHAPE ABUTMENT ;
    PORT
      LAYER M5 ;
      RECT 37.212 207.904 37.308 208.000 ;
    END
  END R0_data[491]
  PIN R0_data[492]
    DIRECTION OUTPUT ;
    USE SIGNAL ;
    SHAPE ABUTMENT ;
    PORT
      LAYER M5 ;
      RECT 37.212 0.000 37.308 0.096 ;
    END
  END R0_data[492]
  PIN R0_data[493]
    DIRECTION OUTPUT ;
    USE SIGNAL ;
    SHAPE ABUTMENT ;
    PORT
      LAYER M4 ;
      RECT 0.000 94.668 0.096 94.764 ;
    END
  END R0_data[493]
  PIN R0_data[494]
    DIRECTION OUTPUT ;
    USE SIGNAL ;
    SHAPE ABUTMENT ;
    PORT
      LAYER M4 ;
      RECT 81.904 94.668 82.000 94.764 ;
    END
  END R0_data[494]
  PIN R0_data[495]
    DIRECTION OUTPUT ;
    USE SIGNAL ;
    SHAPE ABUTMENT ;
    PORT
      LAYER M5 ;
      RECT 37.500 207.904 37.596 208.000 ;
    END
  END R0_data[495]
  PIN R0_data[496]
    DIRECTION OUTPUT ;
    USE SIGNAL ;
    SHAPE ABUTMENT ;
    PORT
      LAYER M5 ;
      RECT 37.500 0.000 37.596 0.096 ;
    END
  END R0_data[496]
  PIN R0_data[497]
    DIRECTION OUTPUT ;
    USE SIGNAL ;
    SHAPE ABUTMENT ;
    PORT
      LAYER M4 ;
      RECT 0.000 95.388 0.096 95.484 ;
    END
  END R0_data[497]
  PIN R0_data[498]
    DIRECTION OUTPUT ;
    USE SIGNAL ;
    SHAPE ABUTMENT ;
    PORT
      LAYER M4 ;
      RECT 81.904 95.388 82.000 95.484 ;
    END
  END R0_data[498]
  PIN R0_data[499]
    DIRECTION OUTPUT ;
    USE SIGNAL ;
    SHAPE ABUTMENT ;
    PORT
      LAYER M5 ;
      RECT 37.788 207.904 37.884 208.000 ;
    END
  END R0_data[499]
  PIN R0_data[500]
    DIRECTION OUTPUT ;
    USE SIGNAL ;
    SHAPE ABUTMENT ;
    PORT
      LAYER M5 ;
      RECT 37.788 0.000 37.884 0.096 ;
    END
  END R0_data[500]
  PIN R0_data[501]
    DIRECTION OUTPUT ;
    USE SIGNAL ;
    SHAPE ABUTMENT ;
    PORT
      LAYER M4 ;
      RECT 0.000 96.156 0.096 96.252 ;
    END
  END R0_data[501]
  PIN R0_data[502]
    DIRECTION OUTPUT ;
    USE SIGNAL ;
    SHAPE ABUTMENT ;
    PORT
      LAYER M4 ;
      RECT 81.904 96.156 82.000 96.252 ;
    END
  END R0_data[502]
  PIN R0_data[503]
    DIRECTION OUTPUT ;
    USE SIGNAL ;
    SHAPE ABUTMENT ;
    PORT
      LAYER M5 ;
      RECT 38.076 207.904 38.172 208.000 ;
    END
  END R0_data[503]
  PIN R0_data[504]
    DIRECTION OUTPUT ;
    USE SIGNAL ;
    SHAPE ABUTMENT ;
    PORT
      LAYER M5 ;
      RECT 38.076 0.000 38.172 0.096 ;
    END
  END R0_data[504]
  PIN R0_data[505]
    DIRECTION OUTPUT ;
    USE SIGNAL ;
    SHAPE ABUTMENT ;
    PORT
      LAYER M4 ;
      RECT 0.000 96.876 0.096 96.972 ;
    END
  END R0_data[505]
  PIN R0_data[506]
    DIRECTION OUTPUT ;
    USE SIGNAL ;
    SHAPE ABUTMENT ;
    PORT
      LAYER M4 ;
      RECT 81.904 96.876 82.000 96.972 ;
    END
  END R0_data[506]
  PIN R0_data[507]
    DIRECTION OUTPUT ;
    USE SIGNAL ;
    SHAPE ABUTMENT ;
    PORT
      LAYER M5 ;
      RECT 38.364 207.904 38.460 208.000 ;
    END
  END R0_data[507]
  PIN R0_data[508]
    DIRECTION OUTPUT ;
    USE SIGNAL ;
    SHAPE ABUTMENT ;
    PORT
      LAYER M5 ;
      RECT 38.364 0.000 38.460 0.096 ;
    END
  END R0_data[508]
  PIN R0_data[509]
    DIRECTION OUTPUT ;
    USE SIGNAL ;
    SHAPE ABUTMENT ;
    PORT
      LAYER M4 ;
      RECT 0.000 97.644 0.096 97.740 ;
    END
  END R0_data[509]
  PIN R0_data[510]
    DIRECTION OUTPUT ;
    USE SIGNAL ;
    SHAPE ABUTMENT ;
    PORT
      LAYER M4 ;
      RECT 81.904 97.644 82.000 97.740 ;
    END
  END R0_data[510]
  PIN R0_data[511]
    DIRECTION OUTPUT ;
    USE SIGNAL ;
    SHAPE ABUTMENT ;
    PORT
      LAYER M5 ;
      RECT 38.652 207.904 38.748 208.000 ;
    END
  END R0_data[511]
  PIN W0_addr[0]
    DIRECTION INPUT ;
    USE SIGNAL ;
    SHAPE ABUTMENT ;
    PORT
      LAYER M5 ;
      RECT 38.652 0.000 38.748 0.096 ;
    END
  END W0_addr[0]
  PIN W0_addr[1]
    DIRECTION INPUT ;
    USE SIGNAL ;
    SHAPE ABUTMENT ;
    PORT
      LAYER M4 ;
      RECT 0.000 98.364 0.096 98.460 ;
    END
  END W0_addr[1]
  PIN W0_addr[2]
    DIRECTION INPUT ;
    USE SIGNAL ;
    SHAPE ABUTMENT ;
    PORT
      LAYER M4 ;
      RECT 81.904 98.364 82.000 98.460 ;
    END
  END W0_addr[2]
  PIN W0_addr[3]
    DIRECTION INPUT ;
    USE SIGNAL ;
    SHAPE ABUTMENT ;
    PORT
      LAYER M5 ;
      RECT 38.940 207.904 39.036 208.000 ;
    END
  END W0_addr[3]
  PIN W0_addr[4]
    DIRECTION INPUT ;
    USE SIGNAL ;
    SHAPE ABUTMENT ;
    PORT
      LAYER M5 ;
      RECT 38.940 0.000 39.036 0.096 ;
    END
  END W0_addr[4]
  PIN W0_addr[5]
    DIRECTION INPUT ;
    USE SIGNAL ;
    SHAPE ABUTMENT ;
    PORT
      LAYER M4 ;
      RECT 0.000 99.132 0.096 99.228 ;
    END
  END W0_addr[5]
  PIN W0_addr[6]
    DIRECTION INPUT ;
    USE SIGNAL ;
    SHAPE ABUTMENT ;
    PORT
      LAYER M4 ;
      RECT 81.904 99.132 82.000 99.228 ;
    END
  END W0_addr[6]
  PIN W0_addr[7]
    DIRECTION INPUT ;
    USE SIGNAL ;
    SHAPE ABUTMENT ;
    PORT
      LAYER M5 ;
      RECT 39.228 207.904 39.324 208.000 ;
    END
  END W0_addr[7]
  PIN W0_addr[8]
    DIRECTION INPUT ;
    USE SIGNAL ;
    SHAPE ABUTMENT ;
    PORT
      LAYER M5 ;
      RECT 39.228 0.000 39.324 0.096 ;
    END
  END W0_addr[8]
  PIN W0_en
    DIRECTION INPUT ;
    USE SIGNAL ;
    SHAPE ABUTMENT ;
    PORT
      LAYER M4 ;
      RECT 0.000 99.852 0.096 99.948 ;
    END
  END W0_en
  PIN W0_clk
    DIRECTION INPUT ;
    USE SIGNAL ;
    SHAPE ABUTMENT ;
    PORT
      LAYER M4 ;
      RECT 81.904 99.852 82.000 99.948 ;
    END
  END W0_clk
  PIN W0_data[0]
    DIRECTION INPUT ;
    USE SIGNAL ;
    SHAPE ABUTMENT ;
    PORT
      LAYER M5 ;
      RECT 39.516 207.904 39.612 208.000 ;
    END
  END W0_data[0]
  PIN W0_data[1]
    DIRECTION INPUT ;
    USE SIGNAL ;
    SHAPE ABUTMENT ;
    PORT
      LAYER M5 ;
      RECT 39.516 0.000 39.612 0.096 ;
    END
  END W0_data[1]
  PIN W0_data[2]
    DIRECTION INPUT ;
    USE SIGNAL ;
    SHAPE ABUTMENT ;
    PORT
      LAYER M4 ;
      RECT 0.000 100.620 0.096 100.716 ;
    END
  END W0_data[2]
  PIN W0_data[3]
    DIRECTION INPUT ;
    USE SIGNAL ;
    SHAPE ABUTMENT ;
    PORT
      LAYER M4 ;
      RECT 81.904 100.620 82.000 100.716 ;
    END
  END W0_data[3]
  PIN W0_data[4]
    DIRECTION INPUT ;
    USE SIGNAL ;
    SHAPE ABUTMENT ;
    PORT
      LAYER M5 ;
      RECT 39.804 207.904 39.900 208.000 ;
    END
  END W0_data[4]
  PIN W0_data[5]
    DIRECTION INPUT ;
    USE SIGNAL ;
    SHAPE ABUTMENT ;
    PORT
      LAYER M5 ;
      RECT 39.804 0.000 39.900 0.096 ;
    END
  END W0_data[5]
  PIN W0_data[6]
    DIRECTION INPUT ;
    USE SIGNAL ;
    SHAPE ABUTMENT ;
    PORT
      LAYER M4 ;
      RECT 0.000 101.340 0.096 101.436 ;
    END
  END W0_data[6]
  PIN W0_data[7]
    DIRECTION INPUT ;
    USE SIGNAL ;
    SHAPE ABUTMENT ;
    PORT
      LAYER M4 ;
      RECT 81.904 101.340 82.000 101.436 ;
    END
  END W0_data[7]
  PIN W0_data[8]
    DIRECTION INPUT ;
    USE SIGNAL ;
    SHAPE ABUTMENT ;
    PORT
      LAYER M5 ;
      RECT 40.092 207.904 40.188 208.000 ;
    END
  END W0_data[8]
  PIN W0_data[9]
    DIRECTION INPUT ;
    USE SIGNAL ;
    SHAPE ABUTMENT ;
    PORT
      LAYER M5 ;
      RECT 40.092 0.000 40.188 0.096 ;
    END
  END W0_data[9]
  PIN W0_data[10]
    DIRECTION INPUT ;
    USE SIGNAL ;
    SHAPE ABUTMENT ;
    PORT
      LAYER M4 ;
      RECT 0.000 102.108 0.096 102.204 ;
    END
  END W0_data[10]
  PIN W0_data[11]
    DIRECTION INPUT ;
    USE SIGNAL ;
    SHAPE ABUTMENT ;
    PORT
      LAYER M4 ;
      RECT 81.904 102.108 82.000 102.204 ;
    END
  END W0_data[11]
  PIN W0_data[12]
    DIRECTION INPUT ;
    USE SIGNAL ;
    SHAPE ABUTMENT ;
    PORT
      LAYER M5 ;
      RECT 40.380 207.904 40.476 208.000 ;
    END
  END W0_data[12]
  PIN W0_data[13]
    DIRECTION INPUT ;
    USE SIGNAL ;
    SHAPE ABUTMENT ;
    PORT
      LAYER M5 ;
      RECT 40.380 0.000 40.476 0.096 ;
    END
  END W0_data[13]
  PIN W0_data[14]
    DIRECTION INPUT ;
    USE SIGNAL ;
    SHAPE ABUTMENT ;
    PORT
      LAYER M4 ;
      RECT 0.000 102.828 0.096 102.924 ;
    END
  END W0_data[14]
  PIN W0_data[15]
    DIRECTION INPUT ;
    USE SIGNAL ;
    SHAPE ABUTMENT ;
    PORT
      LAYER M4 ;
      RECT 81.904 102.828 82.000 102.924 ;
    END
  END W0_data[15]
  PIN W0_data[16]
    DIRECTION INPUT ;
    USE SIGNAL ;
    SHAPE ABUTMENT ;
    PORT
      LAYER M5 ;
      RECT 40.668 207.904 40.764 208.000 ;
    END
  END W0_data[16]
  PIN W0_data[17]
    DIRECTION INPUT ;
    USE SIGNAL ;
    SHAPE ABUTMENT ;
    PORT
      LAYER M5 ;
      RECT 40.668 0.000 40.764 0.096 ;
    END
  END W0_data[17]
  PIN W0_data[18]
    DIRECTION INPUT ;
    USE SIGNAL ;
    SHAPE ABUTMENT ;
    PORT
      LAYER M4 ;
      RECT 0.000 103.596 0.096 103.692 ;
    END
  END W0_data[18]
  PIN W0_data[19]
    DIRECTION INPUT ;
    USE SIGNAL ;
    SHAPE ABUTMENT ;
    PORT
      LAYER M4 ;
      RECT 81.904 103.596 82.000 103.692 ;
    END
  END W0_data[19]
  PIN W0_data[20]
    DIRECTION INPUT ;
    USE SIGNAL ;
    SHAPE ABUTMENT ;
    PORT
      LAYER M5 ;
      RECT 40.956 207.904 41.052 208.000 ;
    END
  END W0_data[20]
  PIN W0_data[21]
    DIRECTION INPUT ;
    USE SIGNAL ;
    SHAPE ABUTMENT ;
    PORT
      LAYER M5 ;
      RECT 40.956 0.000 41.052 0.096 ;
    END
  END W0_data[21]
  PIN W0_data[22]
    DIRECTION INPUT ;
    USE SIGNAL ;
    SHAPE ABUTMENT ;
    PORT
      LAYER M4 ;
      RECT 0.000 104.316 0.096 104.412 ;
    END
  END W0_data[22]
  PIN W0_data[23]
    DIRECTION INPUT ;
    USE SIGNAL ;
    SHAPE ABUTMENT ;
    PORT
      LAYER M4 ;
      RECT 81.904 104.316 82.000 104.412 ;
    END
  END W0_data[23]
  PIN W0_data[24]
    DIRECTION INPUT ;
    USE SIGNAL ;
    SHAPE ABUTMENT ;
    PORT
      LAYER M5 ;
      RECT 41.244 207.904 41.340 208.000 ;
    END
  END W0_data[24]
  PIN W0_data[25]
    DIRECTION INPUT ;
    USE SIGNAL ;
    SHAPE ABUTMENT ;
    PORT
      LAYER M5 ;
      RECT 41.244 0.000 41.340 0.096 ;
    END
  END W0_data[25]
  PIN W0_data[26]
    DIRECTION INPUT ;
    USE SIGNAL ;
    SHAPE ABUTMENT ;
    PORT
      LAYER M4 ;
      RECT 0.000 105.084 0.096 105.180 ;
    END
  END W0_data[26]
  PIN W0_data[27]
    DIRECTION INPUT ;
    USE SIGNAL ;
    SHAPE ABUTMENT ;
    PORT
      LAYER M4 ;
      RECT 81.904 105.084 82.000 105.180 ;
    END
  END W0_data[27]
  PIN W0_data[28]
    DIRECTION INPUT ;
    USE SIGNAL ;
    SHAPE ABUTMENT ;
    PORT
      LAYER M5 ;
      RECT 41.532 207.904 41.628 208.000 ;
    END
  END W0_data[28]
  PIN W0_data[29]
    DIRECTION INPUT ;
    USE SIGNAL ;
    SHAPE ABUTMENT ;
    PORT
      LAYER M5 ;
      RECT 41.532 0.000 41.628 0.096 ;
    END
  END W0_data[29]
  PIN W0_data[30]
    DIRECTION INPUT ;
    USE SIGNAL ;
    SHAPE ABUTMENT ;
    PORT
      LAYER M4 ;
      RECT 0.000 105.804 0.096 105.900 ;
    END
  END W0_data[30]
  PIN W0_data[31]
    DIRECTION INPUT ;
    USE SIGNAL ;
    SHAPE ABUTMENT ;
    PORT
      LAYER M4 ;
      RECT 81.904 105.804 82.000 105.900 ;
    END
  END W0_data[31]
  PIN W0_data[32]
    DIRECTION INPUT ;
    USE SIGNAL ;
    SHAPE ABUTMENT ;
    PORT
      LAYER M5 ;
      RECT 41.820 207.904 41.916 208.000 ;
    END
  END W0_data[32]
  PIN W0_data[33]
    DIRECTION INPUT ;
    USE SIGNAL ;
    SHAPE ABUTMENT ;
    PORT
      LAYER M5 ;
      RECT 41.820 0.000 41.916 0.096 ;
    END
  END W0_data[33]
  PIN W0_data[34]
    DIRECTION INPUT ;
    USE SIGNAL ;
    SHAPE ABUTMENT ;
    PORT
      LAYER M4 ;
      RECT 0.000 106.572 0.096 106.668 ;
    END
  END W0_data[34]
  PIN W0_data[35]
    DIRECTION INPUT ;
    USE SIGNAL ;
    SHAPE ABUTMENT ;
    PORT
      LAYER M4 ;
      RECT 81.904 106.572 82.000 106.668 ;
    END
  END W0_data[35]
  PIN W0_data[36]
    DIRECTION INPUT ;
    USE SIGNAL ;
    SHAPE ABUTMENT ;
    PORT
      LAYER M5 ;
      RECT 42.108 207.904 42.204 208.000 ;
    END
  END W0_data[36]
  PIN W0_data[37]
    DIRECTION INPUT ;
    USE SIGNAL ;
    SHAPE ABUTMENT ;
    PORT
      LAYER M5 ;
      RECT 42.108 0.000 42.204 0.096 ;
    END
  END W0_data[37]
  PIN W0_data[38]
    DIRECTION INPUT ;
    USE SIGNAL ;
    SHAPE ABUTMENT ;
    PORT
      LAYER M4 ;
      RECT 0.000 107.292 0.096 107.388 ;
    END
  END W0_data[38]
  PIN W0_data[39]
    DIRECTION INPUT ;
    USE SIGNAL ;
    SHAPE ABUTMENT ;
    PORT
      LAYER M4 ;
      RECT 81.904 107.292 82.000 107.388 ;
    END
  END W0_data[39]
  PIN W0_data[40]
    DIRECTION INPUT ;
    USE SIGNAL ;
    SHAPE ABUTMENT ;
    PORT
      LAYER M5 ;
      RECT 42.396 207.904 42.492 208.000 ;
    END
  END W0_data[40]
  PIN W0_data[41]
    DIRECTION INPUT ;
    USE SIGNAL ;
    SHAPE ABUTMENT ;
    PORT
      LAYER M5 ;
      RECT 42.396 0.000 42.492 0.096 ;
    END
  END W0_data[41]
  PIN W0_data[42]
    DIRECTION INPUT ;
    USE SIGNAL ;
    SHAPE ABUTMENT ;
    PORT
      LAYER M4 ;
      RECT 0.000 108.060 0.096 108.156 ;
    END
  END W0_data[42]
  PIN W0_data[43]
    DIRECTION INPUT ;
    USE SIGNAL ;
    SHAPE ABUTMENT ;
    PORT
      LAYER M4 ;
      RECT 81.904 108.060 82.000 108.156 ;
    END
  END W0_data[43]
  PIN W0_data[44]
    DIRECTION INPUT ;
    USE SIGNAL ;
    SHAPE ABUTMENT ;
    PORT
      LAYER M5 ;
      RECT 42.684 207.904 42.780 208.000 ;
    END
  END W0_data[44]
  PIN W0_data[45]
    DIRECTION INPUT ;
    USE SIGNAL ;
    SHAPE ABUTMENT ;
    PORT
      LAYER M5 ;
      RECT 42.684 0.000 42.780 0.096 ;
    END
  END W0_data[45]
  PIN W0_data[46]
    DIRECTION INPUT ;
    USE SIGNAL ;
    SHAPE ABUTMENT ;
    PORT
      LAYER M4 ;
      RECT 0.000 108.780 0.096 108.876 ;
    END
  END W0_data[46]
  PIN W0_data[47]
    DIRECTION INPUT ;
    USE SIGNAL ;
    SHAPE ABUTMENT ;
    PORT
      LAYER M4 ;
      RECT 81.904 108.780 82.000 108.876 ;
    END
  END W0_data[47]
  PIN W0_data[48]
    DIRECTION INPUT ;
    USE SIGNAL ;
    SHAPE ABUTMENT ;
    PORT
      LAYER M5 ;
      RECT 42.972 207.904 43.068 208.000 ;
    END
  END W0_data[48]
  PIN W0_data[49]
    DIRECTION INPUT ;
    USE SIGNAL ;
    SHAPE ABUTMENT ;
    PORT
      LAYER M5 ;
      RECT 42.972 0.000 43.068 0.096 ;
    END
  END W0_data[49]
  PIN W0_data[50]
    DIRECTION INPUT ;
    USE SIGNAL ;
    SHAPE ABUTMENT ;
    PORT
      LAYER M4 ;
      RECT 0.000 109.548 0.096 109.644 ;
    END
  END W0_data[50]
  PIN W0_data[51]
    DIRECTION INPUT ;
    USE SIGNAL ;
    SHAPE ABUTMENT ;
    PORT
      LAYER M4 ;
      RECT 81.904 109.548 82.000 109.644 ;
    END
  END W0_data[51]
  PIN W0_data[52]
    DIRECTION INPUT ;
    USE SIGNAL ;
    SHAPE ABUTMENT ;
    PORT
      LAYER M5 ;
      RECT 43.260 207.904 43.356 208.000 ;
    END
  END W0_data[52]
  PIN W0_data[53]
    DIRECTION INPUT ;
    USE SIGNAL ;
    SHAPE ABUTMENT ;
    PORT
      LAYER M5 ;
      RECT 43.260 0.000 43.356 0.096 ;
    END
  END W0_data[53]
  PIN W0_data[54]
    DIRECTION INPUT ;
    USE SIGNAL ;
    SHAPE ABUTMENT ;
    PORT
      LAYER M4 ;
      RECT 0.000 110.268 0.096 110.364 ;
    END
  END W0_data[54]
  PIN W0_data[55]
    DIRECTION INPUT ;
    USE SIGNAL ;
    SHAPE ABUTMENT ;
    PORT
      LAYER M4 ;
      RECT 81.904 110.268 82.000 110.364 ;
    END
  END W0_data[55]
  PIN W0_data[56]
    DIRECTION INPUT ;
    USE SIGNAL ;
    SHAPE ABUTMENT ;
    PORT
      LAYER M5 ;
      RECT 43.548 207.904 43.644 208.000 ;
    END
  END W0_data[56]
  PIN W0_data[57]
    DIRECTION INPUT ;
    USE SIGNAL ;
    SHAPE ABUTMENT ;
    PORT
      LAYER M5 ;
      RECT 43.548 0.000 43.644 0.096 ;
    END
  END W0_data[57]
  PIN W0_data[58]
    DIRECTION INPUT ;
    USE SIGNAL ;
    SHAPE ABUTMENT ;
    PORT
      LAYER M4 ;
      RECT 0.000 111.036 0.096 111.132 ;
    END
  END W0_data[58]
  PIN W0_data[59]
    DIRECTION INPUT ;
    USE SIGNAL ;
    SHAPE ABUTMENT ;
    PORT
      LAYER M4 ;
      RECT 81.904 111.036 82.000 111.132 ;
    END
  END W0_data[59]
  PIN W0_data[60]
    DIRECTION INPUT ;
    USE SIGNAL ;
    SHAPE ABUTMENT ;
    PORT
      LAYER M5 ;
      RECT 43.836 207.904 43.932 208.000 ;
    END
  END W0_data[60]
  PIN W0_data[61]
    DIRECTION INPUT ;
    USE SIGNAL ;
    SHAPE ABUTMENT ;
    PORT
      LAYER M5 ;
      RECT 43.836 0.000 43.932 0.096 ;
    END
  END W0_data[61]
  PIN W0_data[62]
    DIRECTION INPUT ;
    USE SIGNAL ;
    SHAPE ABUTMENT ;
    PORT
      LAYER M4 ;
      RECT 0.000 111.756 0.096 111.852 ;
    END
  END W0_data[62]
  PIN W0_data[63]
    DIRECTION INPUT ;
    USE SIGNAL ;
    SHAPE ABUTMENT ;
    PORT
      LAYER M4 ;
      RECT 81.904 111.756 82.000 111.852 ;
    END
  END W0_data[63]
  PIN W0_data[64]
    DIRECTION INPUT ;
    USE SIGNAL ;
    SHAPE ABUTMENT ;
    PORT
      LAYER M5 ;
      RECT 44.124 207.904 44.220 208.000 ;
    END
  END W0_data[64]
  PIN W0_data[65]
    DIRECTION INPUT ;
    USE SIGNAL ;
    SHAPE ABUTMENT ;
    PORT
      LAYER M5 ;
      RECT 44.124 0.000 44.220 0.096 ;
    END
  END W0_data[65]
  PIN W0_data[66]
    DIRECTION INPUT ;
    USE SIGNAL ;
    SHAPE ABUTMENT ;
    PORT
      LAYER M4 ;
      RECT 0.000 112.524 0.096 112.620 ;
    END
  END W0_data[66]
  PIN W0_data[67]
    DIRECTION INPUT ;
    USE SIGNAL ;
    SHAPE ABUTMENT ;
    PORT
      LAYER M4 ;
      RECT 81.904 112.524 82.000 112.620 ;
    END
  END W0_data[67]
  PIN W0_data[68]
    DIRECTION INPUT ;
    USE SIGNAL ;
    SHAPE ABUTMENT ;
    PORT
      LAYER M5 ;
      RECT 44.412 207.904 44.508 208.000 ;
    END
  END W0_data[68]
  PIN W0_data[69]
    DIRECTION INPUT ;
    USE SIGNAL ;
    SHAPE ABUTMENT ;
    PORT
      LAYER M5 ;
      RECT 44.412 0.000 44.508 0.096 ;
    END
  END W0_data[69]
  PIN W0_data[70]
    DIRECTION INPUT ;
    USE SIGNAL ;
    SHAPE ABUTMENT ;
    PORT
      LAYER M4 ;
      RECT 0.000 113.244 0.096 113.340 ;
    END
  END W0_data[70]
  PIN W0_data[71]
    DIRECTION INPUT ;
    USE SIGNAL ;
    SHAPE ABUTMENT ;
    PORT
      LAYER M4 ;
      RECT 81.904 113.244 82.000 113.340 ;
    END
  END W0_data[71]
  PIN W0_data[72]
    DIRECTION INPUT ;
    USE SIGNAL ;
    SHAPE ABUTMENT ;
    PORT
      LAYER M5 ;
      RECT 44.700 207.904 44.796 208.000 ;
    END
  END W0_data[72]
  PIN W0_data[73]
    DIRECTION INPUT ;
    USE SIGNAL ;
    SHAPE ABUTMENT ;
    PORT
      LAYER M5 ;
      RECT 44.700 0.000 44.796 0.096 ;
    END
  END W0_data[73]
  PIN W0_data[74]
    DIRECTION INPUT ;
    USE SIGNAL ;
    SHAPE ABUTMENT ;
    PORT
      LAYER M4 ;
      RECT 0.000 114.012 0.096 114.108 ;
    END
  END W0_data[74]
  PIN W0_data[75]
    DIRECTION INPUT ;
    USE SIGNAL ;
    SHAPE ABUTMENT ;
    PORT
      LAYER M4 ;
      RECT 81.904 114.012 82.000 114.108 ;
    END
  END W0_data[75]
  PIN W0_data[76]
    DIRECTION INPUT ;
    USE SIGNAL ;
    SHAPE ABUTMENT ;
    PORT
      LAYER M5 ;
      RECT 45.036 207.904 45.132 208.000 ;
    END
  END W0_data[76]
  PIN W0_data[77]
    DIRECTION INPUT ;
    USE SIGNAL ;
    SHAPE ABUTMENT ;
    PORT
      LAYER M5 ;
      RECT 45.036 0.000 45.132 0.096 ;
    END
  END W0_data[77]
  PIN W0_data[78]
    DIRECTION INPUT ;
    USE SIGNAL ;
    SHAPE ABUTMENT ;
    PORT
      LAYER M4 ;
      RECT 0.000 114.732 0.096 114.828 ;
    END
  END W0_data[78]
  PIN W0_data[79]
    DIRECTION INPUT ;
    USE SIGNAL ;
    SHAPE ABUTMENT ;
    PORT
      LAYER M4 ;
      RECT 81.904 114.732 82.000 114.828 ;
    END
  END W0_data[79]
  PIN W0_data[80]
    DIRECTION INPUT ;
    USE SIGNAL ;
    SHAPE ABUTMENT ;
    PORT
      LAYER M5 ;
      RECT 45.324 207.904 45.420 208.000 ;
    END
  END W0_data[80]
  PIN W0_data[81]
    DIRECTION INPUT ;
    USE SIGNAL ;
    SHAPE ABUTMENT ;
    PORT
      LAYER M5 ;
      RECT 45.324 0.000 45.420 0.096 ;
    END
  END W0_data[81]
  PIN W0_data[82]
    DIRECTION INPUT ;
    USE SIGNAL ;
    SHAPE ABUTMENT ;
    PORT
      LAYER M4 ;
      RECT 0.000 115.500 0.096 115.596 ;
    END
  END W0_data[82]
  PIN W0_data[83]
    DIRECTION INPUT ;
    USE SIGNAL ;
    SHAPE ABUTMENT ;
    PORT
      LAYER M4 ;
      RECT 81.904 115.500 82.000 115.596 ;
    END
  END W0_data[83]
  PIN W0_data[84]
    DIRECTION INPUT ;
    USE SIGNAL ;
    SHAPE ABUTMENT ;
    PORT
      LAYER M5 ;
      RECT 45.612 207.904 45.708 208.000 ;
    END
  END W0_data[84]
  PIN W0_data[85]
    DIRECTION INPUT ;
    USE SIGNAL ;
    SHAPE ABUTMENT ;
    PORT
      LAYER M5 ;
      RECT 45.612 0.000 45.708 0.096 ;
    END
  END W0_data[85]
  PIN W0_data[86]
    DIRECTION INPUT ;
    USE SIGNAL ;
    SHAPE ABUTMENT ;
    PORT
      LAYER M4 ;
      RECT 0.000 116.220 0.096 116.316 ;
    END
  END W0_data[86]
  PIN W0_data[87]
    DIRECTION INPUT ;
    USE SIGNAL ;
    SHAPE ABUTMENT ;
    PORT
      LAYER M4 ;
      RECT 81.904 116.220 82.000 116.316 ;
    END
  END W0_data[87]
  PIN W0_data[88]
    DIRECTION INPUT ;
    USE SIGNAL ;
    SHAPE ABUTMENT ;
    PORT
      LAYER M5 ;
      RECT 45.900 207.904 45.996 208.000 ;
    END
  END W0_data[88]
  PIN W0_data[89]
    DIRECTION INPUT ;
    USE SIGNAL ;
    SHAPE ABUTMENT ;
    PORT
      LAYER M5 ;
      RECT 45.900 0.000 45.996 0.096 ;
    END
  END W0_data[89]
  PIN W0_data[90]
    DIRECTION INPUT ;
    USE SIGNAL ;
    SHAPE ABUTMENT ;
    PORT
      LAYER M4 ;
      RECT 0.000 116.988 0.096 117.084 ;
    END
  END W0_data[90]
  PIN W0_data[91]
    DIRECTION INPUT ;
    USE SIGNAL ;
    SHAPE ABUTMENT ;
    PORT
      LAYER M4 ;
      RECT 81.904 116.988 82.000 117.084 ;
    END
  END W0_data[91]
  PIN W0_data[92]
    DIRECTION INPUT ;
    USE SIGNAL ;
    SHAPE ABUTMENT ;
    PORT
      LAYER M5 ;
      RECT 46.188 207.904 46.284 208.000 ;
    END
  END W0_data[92]
  PIN W0_data[93]
    DIRECTION INPUT ;
    USE SIGNAL ;
    SHAPE ABUTMENT ;
    PORT
      LAYER M5 ;
      RECT 46.188 0.000 46.284 0.096 ;
    END
  END W0_data[93]
  PIN W0_data[94]
    DIRECTION INPUT ;
    USE SIGNAL ;
    SHAPE ABUTMENT ;
    PORT
      LAYER M4 ;
      RECT 0.000 117.708 0.096 117.804 ;
    END
  END W0_data[94]
  PIN W0_data[95]
    DIRECTION INPUT ;
    USE SIGNAL ;
    SHAPE ABUTMENT ;
    PORT
      LAYER M4 ;
      RECT 81.904 117.708 82.000 117.804 ;
    END
  END W0_data[95]
  PIN W0_data[96]
    DIRECTION INPUT ;
    USE SIGNAL ;
    SHAPE ABUTMENT ;
    PORT
      LAYER M5 ;
      RECT 46.476 207.904 46.572 208.000 ;
    END
  END W0_data[96]
  PIN W0_data[97]
    DIRECTION INPUT ;
    USE SIGNAL ;
    SHAPE ABUTMENT ;
    PORT
      LAYER M5 ;
      RECT 46.476 0.000 46.572 0.096 ;
    END
  END W0_data[97]
  PIN W0_data[98]
    DIRECTION INPUT ;
    USE SIGNAL ;
    SHAPE ABUTMENT ;
    PORT
      LAYER M4 ;
      RECT 0.000 118.476 0.096 118.572 ;
    END
  END W0_data[98]
  PIN W0_data[99]
    DIRECTION INPUT ;
    USE SIGNAL ;
    SHAPE ABUTMENT ;
    PORT
      LAYER M4 ;
      RECT 81.904 118.476 82.000 118.572 ;
    END
  END W0_data[99]
  PIN W0_data[100]
    DIRECTION INPUT ;
    USE SIGNAL ;
    SHAPE ABUTMENT ;
    PORT
      LAYER M5 ;
      RECT 46.764 207.904 46.860 208.000 ;
    END
  END W0_data[100]
  PIN W0_data[101]
    DIRECTION INPUT ;
    USE SIGNAL ;
    SHAPE ABUTMENT ;
    PORT
      LAYER M5 ;
      RECT 46.764 0.000 46.860 0.096 ;
    END
  END W0_data[101]
  PIN W0_data[102]
    DIRECTION INPUT ;
    USE SIGNAL ;
    SHAPE ABUTMENT ;
    PORT
      LAYER M4 ;
      RECT 0.000 119.196 0.096 119.292 ;
    END
  END W0_data[102]
  PIN W0_data[103]
    DIRECTION INPUT ;
    USE SIGNAL ;
    SHAPE ABUTMENT ;
    PORT
      LAYER M4 ;
      RECT 81.904 119.196 82.000 119.292 ;
    END
  END W0_data[103]
  PIN W0_data[104]
    DIRECTION INPUT ;
    USE SIGNAL ;
    SHAPE ABUTMENT ;
    PORT
      LAYER M5 ;
      RECT 47.052 207.904 47.148 208.000 ;
    END
  END W0_data[104]
  PIN W0_data[105]
    DIRECTION INPUT ;
    USE SIGNAL ;
    SHAPE ABUTMENT ;
    PORT
      LAYER M5 ;
      RECT 47.052 0.000 47.148 0.096 ;
    END
  END W0_data[105]
  PIN W0_data[106]
    DIRECTION INPUT ;
    USE SIGNAL ;
    SHAPE ABUTMENT ;
    PORT
      LAYER M4 ;
      RECT 0.000 119.964 0.096 120.060 ;
    END
  END W0_data[106]
  PIN W0_data[107]
    DIRECTION INPUT ;
    USE SIGNAL ;
    SHAPE ABUTMENT ;
    PORT
      LAYER M4 ;
      RECT 81.904 119.964 82.000 120.060 ;
    END
  END W0_data[107]
  PIN W0_data[108]
    DIRECTION INPUT ;
    USE SIGNAL ;
    SHAPE ABUTMENT ;
    PORT
      LAYER M5 ;
      RECT 47.340 207.904 47.436 208.000 ;
    END
  END W0_data[108]
  PIN W0_data[109]
    DIRECTION INPUT ;
    USE SIGNAL ;
    SHAPE ABUTMENT ;
    PORT
      LAYER M5 ;
      RECT 47.340 0.000 47.436 0.096 ;
    END
  END W0_data[109]
  PIN W0_data[110]
    DIRECTION INPUT ;
    USE SIGNAL ;
    SHAPE ABUTMENT ;
    PORT
      LAYER M4 ;
      RECT 0.000 120.684 0.096 120.780 ;
    END
  END W0_data[110]
  PIN W0_data[111]
    DIRECTION INPUT ;
    USE SIGNAL ;
    SHAPE ABUTMENT ;
    PORT
      LAYER M4 ;
      RECT 81.904 120.684 82.000 120.780 ;
    END
  END W0_data[111]
  PIN W0_data[112]
    DIRECTION INPUT ;
    USE SIGNAL ;
    SHAPE ABUTMENT ;
    PORT
      LAYER M5 ;
      RECT 47.628 207.904 47.724 208.000 ;
    END
  END W0_data[112]
  PIN W0_data[113]
    DIRECTION INPUT ;
    USE SIGNAL ;
    SHAPE ABUTMENT ;
    PORT
      LAYER M5 ;
      RECT 47.628 0.000 47.724 0.096 ;
    END
  END W0_data[113]
  PIN W0_data[114]
    DIRECTION INPUT ;
    USE SIGNAL ;
    SHAPE ABUTMENT ;
    PORT
      LAYER M4 ;
      RECT 0.000 121.452 0.096 121.548 ;
    END
  END W0_data[114]
  PIN W0_data[115]
    DIRECTION INPUT ;
    USE SIGNAL ;
    SHAPE ABUTMENT ;
    PORT
      LAYER M4 ;
      RECT 81.904 121.452 82.000 121.548 ;
    END
  END W0_data[115]
  PIN W0_data[116]
    DIRECTION INPUT ;
    USE SIGNAL ;
    SHAPE ABUTMENT ;
    PORT
      LAYER M5 ;
      RECT 47.916 207.904 48.012 208.000 ;
    END
  END W0_data[116]
  PIN W0_data[117]
    DIRECTION INPUT ;
    USE SIGNAL ;
    SHAPE ABUTMENT ;
    PORT
      LAYER M5 ;
      RECT 47.916 0.000 48.012 0.096 ;
    END
  END W0_data[117]
  PIN W0_data[118]
    DIRECTION INPUT ;
    USE SIGNAL ;
    SHAPE ABUTMENT ;
    PORT
      LAYER M4 ;
      RECT 0.000 122.172 0.096 122.268 ;
    END
  END W0_data[118]
  PIN W0_data[119]
    DIRECTION INPUT ;
    USE SIGNAL ;
    SHAPE ABUTMENT ;
    PORT
      LAYER M4 ;
      RECT 81.904 122.172 82.000 122.268 ;
    END
  END W0_data[119]
  PIN W0_data[120]
    DIRECTION INPUT ;
    USE SIGNAL ;
    SHAPE ABUTMENT ;
    PORT
      LAYER M5 ;
      RECT 48.204 207.904 48.300 208.000 ;
    END
  END W0_data[120]
  PIN W0_data[121]
    DIRECTION INPUT ;
    USE SIGNAL ;
    SHAPE ABUTMENT ;
    PORT
      LAYER M5 ;
      RECT 48.204 0.000 48.300 0.096 ;
    END
  END W0_data[121]
  PIN W0_data[122]
    DIRECTION INPUT ;
    USE SIGNAL ;
    SHAPE ABUTMENT ;
    PORT
      LAYER M4 ;
      RECT 0.000 122.940 0.096 123.036 ;
    END
  END W0_data[122]
  PIN W0_data[123]
    DIRECTION INPUT ;
    USE SIGNAL ;
    SHAPE ABUTMENT ;
    PORT
      LAYER M4 ;
      RECT 81.904 122.940 82.000 123.036 ;
    END
  END W0_data[123]
  PIN W0_data[124]
    DIRECTION INPUT ;
    USE SIGNAL ;
    SHAPE ABUTMENT ;
    PORT
      LAYER M5 ;
      RECT 48.492 207.904 48.588 208.000 ;
    END
  END W0_data[124]
  PIN W0_data[125]
    DIRECTION INPUT ;
    USE SIGNAL ;
    SHAPE ABUTMENT ;
    PORT
      LAYER M5 ;
      RECT 48.492 0.000 48.588 0.096 ;
    END
  END W0_data[125]
  PIN W0_data[126]
    DIRECTION INPUT ;
    USE SIGNAL ;
    SHAPE ABUTMENT ;
    PORT
      LAYER M4 ;
      RECT 0.000 123.660 0.096 123.756 ;
    END
  END W0_data[126]
  PIN W0_data[127]
    DIRECTION INPUT ;
    USE SIGNAL ;
    SHAPE ABUTMENT ;
    PORT
      LAYER M4 ;
      RECT 81.904 123.660 82.000 123.756 ;
    END
  END W0_data[127]
  PIN W0_data[128]
    DIRECTION INPUT ;
    USE SIGNAL ;
    SHAPE ABUTMENT ;
    PORT
      LAYER M5 ;
      RECT 48.780 207.904 48.876 208.000 ;
    END
  END W0_data[128]
  PIN W0_data[129]
    DIRECTION INPUT ;
    USE SIGNAL ;
    SHAPE ABUTMENT ;
    PORT
      LAYER M5 ;
      RECT 48.780 0.000 48.876 0.096 ;
    END
  END W0_data[129]
  PIN W0_data[130]
    DIRECTION INPUT ;
    USE SIGNAL ;
    SHAPE ABUTMENT ;
    PORT
      LAYER M4 ;
      RECT 0.000 124.428 0.096 124.524 ;
    END
  END W0_data[130]
  PIN W0_data[131]
    DIRECTION INPUT ;
    USE SIGNAL ;
    SHAPE ABUTMENT ;
    PORT
      LAYER M4 ;
      RECT 81.904 124.428 82.000 124.524 ;
    END
  END W0_data[131]
  PIN W0_data[132]
    DIRECTION INPUT ;
    USE SIGNAL ;
    SHAPE ABUTMENT ;
    PORT
      LAYER M5 ;
      RECT 49.068 207.904 49.164 208.000 ;
    END
  END W0_data[132]
  PIN W0_data[133]
    DIRECTION INPUT ;
    USE SIGNAL ;
    SHAPE ABUTMENT ;
    PORT
      LAYER M5 ;
      RECT 49.068 0.000 49.164 0.096 ;
    END
  END W0_data[133]
  PIN W0_data[134]
    DIRECTION INPUT ;
    USE SIGNAL ;
    SHAPE ABUTMENT ;
    PORT
      LAYER M4 ;
      RECT 0.000 125.148 0.096 125.244 ;
    END
  END W0_data[134]
  PIN W0_data[135]
    DIRECTION INPUT ;
    USE SIGNAL ;
    SHAPE ABUTMENT ;
    PORT
      LAYER M4 ;
      RECT 81.904 125.148 82.000 125.244 ;
    END
  END W0_data[135]
  PIN W0_data[136]
    DIRECTION INPUT ;
    USE SIGNAL ;
    SHAPE ABUTMENT ;
    PORT
      LAYER M5 ;
      RECT 49.356 207.904 49.452 208.000 ;
    END
  END W0_data[136]
  PIN W0_data[137]
    DIRECTION INPUT ;
    USE SIGNAL ;
    SHAPE ABUTMENT ;
    PORT
      LAYER M5 ;
      RECT 49.356 0.000 49.452 0.096 ;
    END
  END W0_data[137]
  PIN W0_data[138]
    DIRECTION INPUT ;
    USE SIGNAL ;
    SHAPE ABUTMENT ;
    PORT
      LAYER M4 ;
      RECT 0.000 125.868 0.096 125.964 ;
    END
  END W0_data[138]
  PIN W0_data[139]
    DIRECTION INPUT ;
    USE SIGNAL ;
    SHAPE ABUTMENT ;
    PORT
      LAYER M4 ;
      RECT 81.904 125.868 82.000 125.964 ;
    END
  END W0_data[139]
  PIN W0_data[140]
    DIRECTION INPUT ;
    USE SIGNAL ;
    SHAPE ABUTMENT ;
    PORT
      LAYER M5 ;
      RECT 49.644 207.904 49.740 208.000 ;
    END
  END W0_data[140]
  PIN W0_data[141]
    DIRECTION INPUT ;
    USE SIGNAL ;
    SHAPE ABUTMENT ;
    PORT
      LAYER M5 ;
      RECT 49.644 0.000 49.740 0.096 ;
    END
  END W0_data[141]
  PIN W0_data[142]
    DIRECTION INPUT ;
    USE SIGNAL ;
    SHAPE ABUTMENT ;
    PORT
      LAYER M4 ;
      RECT 0.000 126.636 0.096 126.732 ;
    END
  END W0_data[142]
  PIN W0_data[143]
    DIRECTION INPUT ;
    USE SIGNAL ;
    SHAPE ABUTMENT ;
    PORT
      LAYER M4 ;
      RECT 81.904 126.636 82.000 126.732 ;
    END
  END W0_data[143]
  PIN W0_data[144]
    DIRECTION INPUT ;
    USE SIGNAL ;
    SHAPE ABUTMENT ;
    PORT
      LAYER M5 ;
      RECT 49.932 207.904 50.028 208.000 ;
    END
  END W0_data[144]
  PIN W0_data[145]
    DIRECTION INPUT ;
    USE SIGNAL ;
    SHAPE ABUTMENT ;
    PORT
      LAYER M5 ;
      RECT 49.932 0.000 50.028 0.096 ;
    END
  END W0_data[145]
  PIN W0_data[146]
    DIRECTION INPUT ;
    USE SIGNAL ;
    SHAPE ABUTMENT ;
    PORT
      LAYER M4 ;
      RECT 0.000 127.356 0.096 127.452 ;
    END
  END W0_data[146]
  PIN W0_data[147]
    DIRECTION INPUT ;
    USE SIGNAL ;
    SHAPE ABUTMENT ;
    PORT
      LAYER M4 ;
      RECT 81.904 127.356 82.000 127.452 ;
    END
  END W0_data[147]
  PIN W0_data[148]
    DIRECTION INPUT ;
    USE SIGNAL ;
    SHAPE ABUTMENT ;
    PORT
      LAYER M5 ;
      RECT 50.220 207.904 50.316 208.000 ;
    END
  END W0_data[148]
  PIN W0_data[149]
    DIRECTION INPUT ;
    USE SIGNAL ;
    SHAPE ABUTMENT ;
    PORT
      LAYER M5 ;
      RECT 50.220 0.000 50.316 0.096 ;
    END
  END W0_data[149]
  PIN W0_data[150]
    DIRECTION INPUT ;
    USE SIGNAL ;
    SHAPE ABUTMENT ;
    PORT
      LAYER M4 ;
      RECT 0.000 128.124 0.096 128.220 ;
    END
  END W0_data[150]
  PIN W0_data[151]
    DIRECTION INPUT ;
    USE SIGNAL ;
    SHAPE ABUTMENT ;
    PORT
      LAYER M4 ;
      RECT 81.904 128.124 82.000 128.220 ;
    END
  END W0_data[151]
  PIN W0_data[152]
    DIRECTION INPUT ;
    USE SIGNAL ;
    SHAPE ABUTMENT ;
    PORT
      LAYER M5 ;
      RECT 50.508 207.904 50.604 208.000 ;
    END
  END W0_data[152]
  PIN W0_data[153]
    DIRECTION INPUT ;
    USE SIGNAL ;
    SHAPE ABUTMENT ;
    PORT
      LAYER M5 ;
      RECT 50.508 0.000 50.604 0.096 ;
    END
  END W0_data[153]
  PIN W0_data[154]
    DIRECTION INPUT ;
    USE SIGNAL ;
    SHAPE ABUTMENT ;
    PORT
      LAYER M4 ;
      RECT 0.000 128.844 0.096 128.940 ;
    END
  END W0_data[154]
  PIN W0_data[155]
    DIRECTION INPUT ;
    USE SIGNAL ;
    SHAPE ABUTMENT ;
    PORT
      LAYER M4 ;
      RECT 81.904 128.844 82.000 128.940 ;
    END
  END W0_data[155]
  PIN W0_data[156]
    DIRECTION INPUT ;
    USE SIGNAL ;
    SHAPE ABUTMENT ;
    PORT
      LAYER M5 ;
      RECT 50.796 207.904 50.892 208.000 ;
    END
  END W0_data[156]
  PIN W0_data[157]
    DIRECTION INPUT ;
    USE SIGNAL ;
    SHAPE ABUTMENT ;
    PORT
      LAYER M5 ;
      RECT 50.796 0.000 50.892 0.096 ;
    END
  END W0_data[157]
  PIN W0_data[158]
    DIRECTION INPUT ;
    USE SIGNAL ;
    SHAPE ABUTMENT ;
    PORT
      LAYER M4 ;
      RECT 0.000 129.612 0.096 129.708 ;
    END
  END W0_data[158]
  PIN W0_data[159]
    DIRECTION INPUT ;
    USE SIGNAL ;
    SHAPE ABUTMENT ;
    PORT
      LAYER M4 ;
      RECT 81.904 129.612 82.000 129.708 ;
    END
  END W0_data[159]
  PIN W0_data[160]
    DIRECTION INPUT ;
    USE SIGNAL ;
    SHAPE ABUTMENT ;
    PORT
      LAYER M5 ;
      RECT 51.084 207.904 51.180 208.000 ;
    END
  END W0_data[160]
  PIN W0_data[161]
    DIRECTION INPUT ;
    USE SIGNAL ;
    SHAPE ABUTMENT ;
    PORT
      LAYER M5 ;
      RECT 51.084 0.000 51.180 0.096 ;
    END
  END W0_data[161]
  PIN W0_data[162]
    DIRECTION INPUT ;
    USE SIGNAL ;
    SHAPE ABUTMENT ;
    PORT
      LAYER M4 ;
      RECT 0.000 130.332 0.096 130.428 ;
    END
  END W0_data[162]
  PIN W0_data[163]
    DIRECTION INPUT ;
    USE SIGNAL ;
    SHAPE ABUTMENT ;
    PORT
      LAYER M4 ;
      RECT 81.904 130.332 82.000 130.428 ;
    END
  END W0_data[163]
  PIN W0_data[164]
    DIRECTION INPUT ;
    USE SIGNAL ;
    SHAPE ABUTMENT ;
    PORT
      LAYER M5 ;
      RECT 51.372 207.904 51.468 208.000 ;
    END
  END W0_data[164]
  PIN W0_data[165]
    DIRECTION INPUT ;
    USE SIGNAL ;
    SHAPE ABUTMENT ;
    PORT
      LAYER M5 ;
      RECT 51.372 0.000 51.468 0.096 ;
    END
  END W0_data[165]
  PIN W0_data[166]
    DIRECTION INPUT ;
    USE SIGNAL ;
    SHAPE ABUTMENT ;
    PORT
      LAYER M4 ;
      RECT 0.000 131.100 0.096 131.196 ;
    END
  END W0_data[166]
  PIN W0_data[167]
    DIRECTION INPUT ;
    USE SIGNAL ;
    SHAPE ABUTMENT ;
    PORT
      LAYER M4 ;
      RECT 81.904 131.100 82.000 131.196 ;
    END
  END W0_data[167]
  PIN W0_data[168]
    DIRECTION INPUT ;
    USE SIGNAL ;
    SHAPE ABUTMENT ;
    PORT
      LAYER M5 ;
      RECT 51.660 207.904 51.756 208.000 ;
    END
  END W0_data[168]
  PIN W0_data[169]
    DIRECTION INPUT ;
    USE SIGNAL ;
    SHAPE ABUTMENT ;
    PORT
      LAYER M5 ;
      RECT 51.660 0.000 51.756 0.096 ;
    END
  END W0_data[169]
  PIN W0_data[170]
    DIRECTION INPUT ;
    USE SIGNAL ;
    SHAPE ABUTMENT ;
    PORT
      LAYER M4 ;
      RECT 0.000 131.820 0.096 131.916 ;
    END
  END W0_data[170]
  PIN W0_data[171]
    DIRECTION INPUT ;
    USE SIGNAL ;
    SHAPE ABUTMENT ;
    PORT
      LAYER M4 ;
      RECT 81.904 131.820 82.000 131.916 ;
    END
  END W0_data[171]
  PIN W0_data[172]
    DIRECTION INPUT ;
    USE SIGNAL ;
    SHAPE ABUTMENT ;
    PORT
      LAYER M5 ;
      RECT 51.948 207.904 52.044 208.000 ;
    END
  END W0_data[172]
  PIN W0_data[173]
    DIRECTION INPUT ;
    USE SIGNAL ;
    SHAPE ABUTMENT ;
    PORT
      LAYER M5 ;
      RECT 51.948 0.000 52.044 0.096 ;
    END
  END W0_data[173]
  PIN W0_data[174]
    DIRECTION INPUT ;
    USE SIGNAL ;
    SHAPE ABUTMENT ;
    PORT
      LAYER M4 ;
      RECT 0.000 132.588 0.096 132.684 ;
    END
  END W0_data[174]
  PIN W0_data[175]
    DIRECTION INPUT ;
    USE SIGNAL ;
    SHAPE ABUTMENT ;
    PORT
      LAYER M4 ;
      RECT 81.904 132.588 82.000 132.684 ;
    END
  END W0_data[175]
  PIN W0_data[176]
    DIRECTION INPUT ;
    USE SIGNAL ;
    SHAPE ABUTMENT ;
    PORT
      LAYER M5 ;
      RECT 52.236 207.904 52.332 208.000 ;
    END
  END W0_data[176]
  PIN W0_data[177]
    DIRECTION INPUT ;
    USE SIGNAL ;
    SHAPE ABUTMENT ;
    PORT
      LAYER M5 ;
      RECT 52.236 0.000 52.332 0.096 ;
    END
  END W0_data[177]
  PIN W0_data[178]
    DIRECTION INPUT ;
    USE SIGNAL ;
    SHAPE ABUTMENT ;
    PORT
      LAYER M4 ;
      RECT 0.000 133.308 0.096 133.404 ;
    END
  END W0_data[178]
  PIN W0_data[179]
    DIRECTION INPUT ;
    USE SIGNAL ;
    SHAPE ABUTMENT ;
    PORT
      LAYER M4 ;
      RECT 81.904 133.308 82.000 133.404 ;
    END
  END W0_data[179]
  PIN W0_data[180]
    DIRECTION INPUT ;
    USE SIGNAL ;
    SHAPE ABUTMENT ;
    PORT
      LAYER M5 ;
      RECT 52.524 207.904 52.620 208.000 ;
    END
  END W0_data[180]
  PIN W0_data[181]
    DIRECTION INPUT ;
    USE SIGNAL ;
    SHAPE ABUTMENT ;
    PORT
      LAYER M5 ;
      RECT 52.524 0.000 52.620 0.096 ;
    END
  END W0_data[181]
  PIN W0_data[182]
    DIRECTION INPUT ;
    USE SIGNAL ;
    SHAPE ABUTMENT ;
    PORT
      LAYER M4 ;
      RECT 0.000 134.076 0.096 134.172 ;
    END
  END W0_data[182]
  PIN W0_data[183]
    DIRECTION INPUT ;
    USE SIGNAL ;
    SHAPE ABUTMENT ;
    PORT
      LAYER M4 ;
      RECT 81.904 134.076 82.000 134.172 ;
    END
  END W0_data[183]
  PIN W0_data[184]
    DIRECTION INPUT ;
    USE SIGNAL ;
    SHAPE ABUTMENT ;
    PORT
      LAYER M5 ;
      RECT 52.812 207.904 52.908 208.000 ;
    END
  END W0_data[184]
  PIN W0_data[185]
    DIRECTION INPUT ;
    USE SIGNAL ;
    SHAPE ABUTMENT ;
    PORT
      LAYER M5 ;
      RECT 52.812 0.000 52.908 0.096 ;
    END
  END W0_data[185]
  PIN W0_data[186]
    DIRECTION INPUT ;
    USE SIGNAL ;
    SHAPE ABUTMENT ;
    PORT
      LAYER M4 ;
      RECT 0.000 134.796 0.096 134.892 ;
    END
  END W0_data[186]
  PIN W0_data[187]
    DIRECTION INPUT ;
    USE SIGNAL ;
    SHAPE ABUTMENT ;
    PORT
      LAYER M4 ;
      RECT 81.904 134.796 82.000 134.892 ;
    END
  END W0_data[187]
  PIN W0_data[188]
    DIRECTION INPUT ;
    USE SIGNAL ;
    SHAPE ABUTMENT ;
    PORT
      LAYER M5 ;
      RECT 53.148 207.904 53.244 208.000 ;
    END
  END W0_data[188]
  PIN W0_data[189]
    DIRECTION INPUT ;
    USE SIGNAL ;
    SHAPE ABUTMENT ;
    PORT
      LAYER M5 ;
      RECT 53.148 0.000 53.244 0.096 ;
    END
  END W0_data[189]
  PIN W0_data[190]
    DIRECTION INPUT ;
    USE SIGNAL ;
    SHAPE ABUTMENT ;
    PORT
      LAYER M4 ;
      RECT 0.000 135.564 0.096 135.660 ;
    END
  END W0_data[190]
  PIN W0_data[191]
    DIRECTION INPUT ;
    USE SIGNAL ;
    SHAPE ABUTMENT ;
    PORT
      LAYER M4 ;
      RECT 81.904 135.564 82.000 135.660 ;
    END
  END W0_data[191]
  PIN W0_data[192]
    DIRECTION INPUT ;
    USE SIGNAL ;
    SHAPE ABUTMENT ;
    PORT
      LAYER M5 ;
      RECT 53.436 207.904 53.532 208.000 ;
    END
  END W0_data[192]
  PIN W0_data[193]
    DIRECTION INPUT ;
    USE SIGNAL ;
    SHAPE ABUTMENT ;
    PORT
      LAYER M5 ;
      RECT 53.436 0.000 53.532 0.096 ;
    END
  END W0_data[193]
  PIN W0_data[194]
    DIRECTION INPUT ;
    USE SIGNAL ;
    SHAPE ABUTMENT ;
    PORT
      LAYER M4 ;
      RECT 0.000 136.284 0.096 136.380 ;
    END
  END W0_data[194]
  PIN W0_data[195]
    DIRECTION INPUT ;
    USE SIGNAL ;
    SHAPE ABUTMENT ;
    PORT
      LAYER M4 ;
      RECT 81.904 136.284 82.000 136.380 ;
    END
  END W0_data[195]
  PIN W0_data[196]
    DIRECTION INPUT ;
    USE SIGNAL ;
    SHAPE ABUTMENT ;
    PORT
      LAYER M5 ;
      RECT 53.724 207.904 53.820 208.000 ;
    END
  END W0_data[196]
  PIN W0_data[197]
    DIRECTION INPUT ;
    USE SIGNAL ;
    SHAPE ABUTMENT ;
    PORT
      LAYER M5 ;
      RECT 53.724 0.000 53.820 0.096 ;
    END
  END W0_data[197]
  PIN W0_data[198]
    DIRECTION INPUT ;
    USE SIGNAL ;
    SHAPE ABUTMENT ;
    PORT
      LAYER M4 ;
      RECT 0.000 137.052 0.096 137.148 ;
    END
  END W0_data[198]
  PIN W0_data[199]
    DIRECTION INPUT ;
    USE SIGNAL ;
    SHAPE ABUTMENT ;
    PORT
      LAYER M4 ;
      RECT 81.904 137.052 82.000 137.148 ;
    END
  END W0_data[199]
  PIN W0_data[200]
    DIRECTION INPUT ;
    USE SIGNAL ;
    SHAPE ABUTMENT ;
    PORT
      LAYER M5 ;
      RECT 54.012 207.904 54.108 208.000 ;
    END
  END W0_data[200]
  PIN W0_data[201]
    DIRECTION INPUT ;
    USE SIGNAL ;
    SHAPE ABUTMENT ;
    PORT
      LAYER M5 ;
      RECT 54.012 0.000 54.108 0.096 ;
    END
  END W0_data[201]
  PIN W0_data[202]
    DIRECTION INPUT ;
    USE SIGNAL ;
    SHAPE ABUTMENT ;
    PORT
      LAYER M4 ;
      RECT 0.000 137.772 0.096 137.868 ;
    END
  END W0_data[202]
  PIN W0_data[203]
    DIRECTION INPUT ;
    USE SIGNAL ;
    SHAPE ABUTMENT ;
    PORT
      LAYER M4 ;
      RECT 81.904 137.772 82.000 137.868 ;
    END
  END W0_data[203]
  PIN W0_data[204]
    DIRECTION INPUT ;
    USE SIGNAL ;
    SHAPE ABUTMENT ;
    PORT
      LAYER M5 ;
      RECT 54.300 207.904 54.396 208.000 ;
    END
  END W0_data[204]
  PIN W0_data[205]
    DIRECTION INPUT ;
    USE SIGNAL ;
    SHAPE ABUTMENT ;
    PORT
      LAYER M5 ;
      RECT 54.300 0.000 54.396 0.096 ;
    END
  END W0_data[205]
  PIN W0_data[206]
    DIRECTION INPUT ;
    USE SIGNAL ;
    SHAPE ABUTMENT ;
    PORT
      LAYER M4 ;
      RECT 0.000 138.540 0.096 138.636 ;
    END
  END W0_data[206]
  PIN W0_data[207]
    DIRECTION INPUT ;
    USE SIGNAL ;
    SHAPE ABUTMENT ;
    PORT
      LAYER M4 ;
      RECT 81.904 138.540 82.000 138.636 ;
    END
  END W0_data[207]
  PIN W0_data[208]
    DIRECTION INPUT ;
    USE SIGNAL ;
    SHAPE ABUTMENT ;
    PORT
      LAYER M5 ;
      RECT 54.588 207.904 54.684 208.000 ;
    END
  END W0_data[208]
  PIN W0_data[209]
    DIRECTION INPUT ;
    USE SIGNAL ;
    SHAPE ABUTMENT ;
    PORT
      LAYER M5 ;
      RECT 54.588 0.000 54.684 0.096 ;
    END
  END W0_data[209]
  PIN W0_data[210]
    DIRECTION INPUT ;
    USE SIGNAL ;
    SHAPE ABUTMENT ;
    PORT
      LAYER M4 ;
      RECT 0.000 139.260 0.096 139.356 ;
    END
  END W0_data[210]
  PIN W0_data[211]
    DIRECTION INPUT ;
    USE SIGNAL ;
    SHAPE ABUTMENT ;
    PORT
      LAYER M4 ;
      RECT 81.904 139.260 82.000 139.356 ;
    END
  END W0_data[211]
  PIN W0_data[212]
    DIRECTION INPUT ;
    USE SIGNAL ;
    SHAPE ABUTMENT ;
    PORT
      LAYER M5 ;
      RECT 54.876 207.904 54.972 208.000 ;
    END
  END W0_data[212]
  PIN W0_data[213]
    DIRECTION INPUT ;
    USE SIGNAL ;
    SHAPE ABUTMENT ;
    PORT
      LAYER M5 ;
      RECT 54.876 0.000 54.972 0.096 ;
    END
  END W0_data[213]
  PIN W0_data[214]
    DIRECTION INPUT ;
    USE SIGNAL ;
    SHAPE ABUTMENT ;
    PORT
      LAYER M4 ;
      RECT 0.000 140.028 0.096 140.124 ;
    END
  END W0_data[214]
  PIN W0_data[215]
    DIRECTION INPUT ;
    USE SIGNAL ;
    SHAPE ABUTMENT ;
    PORT
      LAYER M4 ;
      RECT 81.904 140.028 82.000 140.124 ;
    END
  END W0_data[215]
  PIN W0_data[216]
    DIRECTION INPUT ;
    USE SIGNAL ;
    SHAPE ABUTMENT ;
    PORT
      LAYER M5 ;
      RECT 55.164 207.904 55.260 208.000 ;
    END
  END W0_data[216]
  PIN W0_data[217]
    DIRECTION INPUT ;
    USE SIGNAL ;
    SHAPE ABUTMENT ;
    PORT
      LAYER M5 ;
      RECT 55.164 0.000 55.260 0.096 ;
    END
  END W0_data[217]
  PIN W0_data[218]
    DIRECTION INPUT ;
    USE SIGNAL ;
    SHAPE ABUTMENT ;
    PORT
      LAYER M4 ;
      RECT 0.000 140.748 0.096 140.844 ;
    END
  END W0_data[218]
  PIN W0_data[219]
    DIRECTION INPUT ;
    USE SIGNAL ;
    SHAPE ABUTMENT ;
    PORT
      LAYER M4 ;
      RECT 81.904 140.748 82.000 140.844 ;
    END
  END W0_data[219]
  PIN W0_data[220]
    DIRECTION INPUT ;
    USE SIGNAL ;
    SHAPE ABUTMENT ;
    PORT
      LAYER M5 ;
      RECT 55.452 207.904 55.548 208.000 ;
    END
  END W0_data[220]
  PIN W0_data[221]
    DIRECTION INPUT ;
    USE SIGNAL ;
    SHAPE ABUTMENT ;
    PORT
      LAYER M5 ;
      RECT 55.452 0.000 55.548 0.096 ;
    END
  END W0_data[221]
  PIN W0_data[222]
    DIRECTION INPUT ;
    USE SIGNAL ;
    SHAPE ABUTMENT ;
    PORT
      LAYER M4 ;
      RECT 0.000 141.516 0.096 141.612 ;
    END
  END W0_data[222]
  PIN W0_data[223]
    DIRECTION INPUT ;
    USE SIGNAL ;
    SHAPE ABUTMENT ;
    PORT
      LAYER M4 ;
      RECT 81.904 141.516 82.000 141.612 ;
    END
  END W0_data[223]
  PIN W0_data[224]
    DIRECTION INPUT ;
    USE SIGNAL ;
    SHAPE ABUTMENT ;
    PORT
      LAYER M5 ;
      RECT 55.740 207.904 55.836 208.000 ;
    END
  END W0_data[224]
  PIN W0_data[225]
    DIRECTION INPUT ;
    USE SIGNAL ;
    SHAPE ABUTMENT ;
    PORT
      LAYER M5 ;
      RECT 55.740 0.000 55.836 0.096 ;
    END
  END W0_data[225]
  PIN W0_data[226]
    DIRECTION INPUT ;
    USE SIGNAL ;
    SHAPE ABUTMENT ;
    PORT
      LAYER M4 ;
      RECT 0.000 142.236 0.096 142.332 ;
    END
  END W0_data[226]
  PIN W0_data[227]
    DIRECTION INPUT ;
    USE SIGNAL ;
    SHAPE ABUTMENT ;
    PORT
      LAYER M4 ;
      RECT 81.904 142.236 82.000 142.332 ;
    END
  END W0_data[227]
  PIN W0_data[228]
    DIRECTION INPUT ;
    USE SIGNAL ;
    SHAPE ABUTMENT ;
    PORT
      LAYER M5 ;
      RECT 56.028 207.904 56.124 208.000 ;
    END
  END W0_data[228]
  PIN W0_data[229]
    DIRECTION INPUT ;
    USE SIGNAL ;
    SHAPE ABUTMENT ;
    PORT
      LAYER M5 ;
      RECT 56.028 0.000 56.124 0.096 ;
    END
  END W0_data[229]
  PIN W0_data[230]
    DIRECTION INPUT ;
    USE SIGNAL ;
    SHAPE ABUTMENT ;
    PORT
      LAYER M4 ;
      RECT 0.000 143.004 0.096 143.100 ;
    END
  END W0_data[230]
  PIN W0_data[231]
    DIRECTION INPUT ;
    USE SIGNAL ;
    SHAPE ABUTMENT ;
    PORT
      LAYER M4 ;
      RECT 81.904 143.004 82.000 143.100 ;
    END
  END W0_data[231]
  PIN W0_data[232]
    DIRECTION INPUT ;
    USE SIGNAL ;
    SHAPE ABUTMENT ;
    PORT
      LAYER M5 ;
      RECT 56.316 207.904 56.412 208.000 ;
    END
  END W0_data[232]
  PIN W0_data[233]
    DIRECTION INPUT ;
    USE SIGNAL ;
    SHAPE ABUTMENT ;
    PORT
      LAYER M5 ;
      RECT 56.316 0.000 56.412 0.096 ;
    END
  END W0_data[233]
  PIN W0_data[234]
    DIRECTION INPUT ;
    USE SIGNAL ;
    SHAPE ABUTMENT ;
    PORT
      LAYER M4 ;
      RECT 0.000 143.724 0.096 143.820 ;
    END
  END W0_data[234]
  PIN W0_data[235]
    DIRECTION INPUT ;
    USE SIGNAL ;
    SHAPE ABUTMENT ;
    PORT
      LAYER M4 ;
      RECT 81.904 143.724 82.000 143.820 ;
    END
  END W0_data[235]
  PIN W0_data[236]
    DIRECTION INPUT ;
    USE SIGNAL ;
    SHAPE ABUTMENT ;
    PORT
      LAYER M5 ;
      RECT 56.604 207.904 56.700 208.000 ;
    END
  END W0_data[236]
  PIN W0_data[237]
    DIRECTION INPUT ;
    USE SIGNAL ;
    SHAPE ABUTMENT ;
    PORT
      LAYER M5 ;
      RECT 56.604 0.000 56.700 0.096 ;
    END
  END W0_data[237]
  PIN W0_data[238]
    DIRECTION INPUT ;
    USE SIGNAL ;
    SHAPE ABUTMENT ;
    PORT
      LAYER M4 ;
      RECT 0.000 144.492 0.096 144.588 ;
    END
  END W0_data[238]
  PIN W0_data[239]
    DIRECTION INPUT ;
    USE SIGNAL ;
    SHAPE ABUTMENT ;
    PORT
      LAYER M4 ;
      RECT 81.904 144.492 82.000 144.588 ;
    END
  END W0_data[239]
  PIN W0_data[240]
    DIRECTION INPUT ;
    USE SIGNAL ;
    SHAPE ABUTMENT ;
    PORT
      LAYER M5 ;
      RECT 56.892 207.904 56.988 208.000 ;
    END
  END W0_data[240]
  PIN W0_data[241]
    DIRECTION INPUT ;
    USE SIGNAL ;
    SHAPE ABUTMENT ;
    PORT
      LAYER M5 ;
      RECT 56.892 0.000 56.988 0.096 ;
    END
  END W0_data[241]
  PIN W0_data[242]
    DIRECTION INPUT ;
    USE SIGNAL ;
    SHAPE ABUTMENT ;
    PORT
      LAYER M4 ;
      RECT 0.000 145.212 0.096 145.308 ;
    END
  END W0_data[242]
  PIN W0_data[243]
    DIRECTION INPUT ;
    USE SIGNAL ;
    SHAPE ABUTMENT ;
    PORT
      LAYER M4 ;
      RECT 81.904 145.212 82.000 145.308 ;
    END
  END W0_data[243]
  PIN W0_data[244]
    DIRECTION INPUT ;
    USE SIGNAL ;
    SHAPE ABUTMENT ;
    PORT
      LAYER M5 ;
      RECT 57.180 207.904 57.276 208.000 ;
    END
  END W0_data[244]
  PIN W0_data[245]
    DIRECTION INPUT ;
    USE SIGNAL ;
    SHAPE ABUTMENT ;
    PORT
      LAYER M5 ;
      RECT 57.180 0.000 57.276 0.096 ;
    END
  END W0_data[245]
  PIN W0_data[246]
    DIRECTION INPUT ;
    USE SIGNAL ;
    SHAPE ABUTMENT ;
    PORT
      LAYER M4 ;
      RECT 0.000 145.980 0.096 146.076 ;
    END
  END W0_data[246]
  PIN W0_data[247]
    DIRECTION INPUT ;
    USE SIGNAL ;
    SHAPE ABUTMENT ;
    PORT
      LAYER M4 ;
      RECT 81.904 145.980 82.000 146.076 ;
    END
  END W0_data[247]
  PIN W0_data[248]
    DIRECTION INPUT ;
    USE SIGNAL ;
    SHAPE ABUTMENT ;
    PORT
      LAYER M5 ;
      RECT 57.468 207.904 57.564 208.000 ;
    END
  END W0_data[248]
  PIN W0_data[249]
    DIRECTION INPUT ;
    USE SIGNAL ;
    SHAPE ABUTMENT ;
    PORT
      LAYER M5 ;
      RECT 57.468 0.000 57.564 0.096 ;
    END
  END W0_data[249]
  PIN W0_data[250]
    DIRECTION INPUT ;
    USE SIGNAL ;
    SHAPE ABUTMENT ;
    PORT
      LAYER M4 ;
      RECT 0.000 146.700 0.096 146.796 ;
    END
  END W0_data[250]
  PIN W0_data[251]
    DIRECTION INPUT ;
    USE SIGNAL ;
    SHAPE ABUTMENT ;
    PORT
      LAYER M4 ;
      RECT 81.904 146.700 82.000 146.796 ;
    END
  END W0_data[251]
  PIN W0_data[252]
    DIRECTION INPUT ;
    USE SIGNAL ;
    SHAPE ABUTMENT ;
    PORT
      LAYER M5 ;
      RECT 57.756 207.904 57.852 208.000 ;
    END
  END W0_data[252]
  PIN W0_data[253]
    DIRECTION INPUT ;
    USE SIGNAL ;
    SHAPE ABUTMENT ;
    PORT
      LAYER M5 ;
      RECT 57.756 0.000 57.852 0.096 ;
    END
  END W0_data[253]
  PIN W0_data[254]
    DIRECTION INPUT ;
    USE SIGNAL ;
    SHAPE ABUTMENT ;
    PORT
      LAYER M4 ;
      RECT 0.000 147.468 0.096 147.564 ;
    END
  END W0_data[254]
  PIN W0_data[255]
    DIRECTION INPUT ;
    USE SIGNAL ;
    SHAPE ABUTMENT ;
    PORT
      LAYER M4 ;
      RECT 81.904 147.468 82.000 147.564 ;
    END
  END W0_data[255]
  PIN W0_data[256]
    DIRECTION INPUT ;
    USE SIGNAL ;
    SHAPE ABUTMENT ;
    PORT
      LAYER M5 ;
      RECT 58.044 207.904 58.140 208.000 ;
    END
  END W0_data[256]
  PIN W0_data[257]
    DIRECTION INPUT ;
    USE SIGNAL ;
    SHAPE ABUTMENT ;
    PORT
      LAYER M5 ;
      RECT 58.044 0.000 58.140 0.096 ;
    END
  END W0_data[257]
  PIN W0_data[258]
    DIRECTION INPUT ;
    USE SIGNAL ;
    SHAPE ABUTMENT ;
    PORT
      LAYER M4 ;
      RECT 0.000 148.188 0.096 148.284 ;
    END
  END W0_data[258]
  PIN W0_data[259]
    DIRECTION INPUT ;
    USE SIGNAL ;
    SHAPE ABUTMENT ;
    PORT
      LAYER M4 ;
      RECT 81.904 148.188 82.000 148.284 ;
    END
  END W0_data[259]
  PIN W0_data[260]
    DIRECTION INPUT ;
    USE SIGNAL ;
    SHAPE ABUTMENT ;
    PORT
      LAYER M5 ;
      RECT 58.332 207.904 58.428 208.000 ;
    END
  END W0_data[260]
  PIN W0_data[261]
    DIRECTION INPUT ;
    USE SIGNAL ;
    SHAPE ABUTMENT ;
    PORT
      LAYER M5 ;
      RECT 58.332 0.000 58.428 0.096 ;
    END
  END W0_data[261]
  PIN W0_data[262]
    DIRECTION INPUT ;
    USE SIGNAL ;
    SHAPE ABUTMENT ;
    PORT
      LAYER M4 ;
      RECT 0.000 148.956 0.096 149.052 ;
    END
  END W0_data[262]
  PIN W0_data[263]
    DIRECTION INPUT ;
    USE SIGNAL ;
    SHAPE ABUTMENT ;
    PORT
      LAYER M4 ;
      RECT 81.904 148.956 82.000 149.052 ;
    END
  END W0_data[263]
  PIN W0_data[264]
    DIRECTION INPUT ;
    USE SIGNAL ;
    SHAPE ABUTMENT ;
    PORT
      LAYER M5 ;
      RECT 58.620 207.904 58.716 208.000 ;
    END
  END W0_data[264]
  PIN W0_data[265]
    DIRECTION INPUT ;
    USE SIGNAL ;
    SHAPE ABUTMENT ;
    PORT
      LAYER M5 ;
      RECT 58.620 0.000 58.716 0.096 ;
    END
  END W0_data[265]
  PIN W0_data[266]
    DIRECTION INPUT ;
    USE SIGNAL ;
    SHAPE ABUTMENT ;
    PORT
      LAYER M4 ;
      RECT 0.000 149.676 0.096 149.772 ;
    END
  END W0_data[266]
  PIN W0_data[267]
    DIRECTION INPUT ;
    USE SIGNAL ;
    SHAPE ABUTMENT ;
    PORT
      LAYER M4 ;
      RECT 81.904 149.676 82.000 149.772 ;
    END
  END W0_data[267]
  PIN W0_data[268]
    DIRECTION INPUT ;
    USE SIGNAL ;
    SHAPE ABUTMENT ;
    PORT
      LAYER M5 ;
      RECT 58.908 207.904 59.004 208.000 ;
    END
  END W0_data[268]
  PIN W0_data[269]
    DIRECTION INPUT ;
    USE SIGNAL ;
    SHAPE ABUTMENT ;
    PORT
      LAYER M5 ;
      RECT 58.908 0.000 59.004 0.096 ;
    END
  END W0_data[269]
  PIN W0_data[270]
    DIRECTION INPUT ;
    USE SIGNAL ;
    SHAPE ABUTMENT ;
    PORT
      LAYER M4 ;
      RECT 0.000 150.444 0.096 150.540 ;
    END
  END W0_data[270]
  PIN W0_data[271]
    DIRECTION INPUT ;
    USE SIGNAL ;
    SHAPE ABUTMENT ;
    PORT
      LAYER M4 ;
      RECT 81.904 150.444 82.000 150.540 ;
    END
  END W0_data[271]
  PIN W0_data[272]
    DIRECTION INPUT ;
    USE SIGNAL ;
    SHAPE ABUTMENT ;
    PORT
      LAYER M5 ;
      RECT 59.196 207.904 59.292 208.000 ;
    END
  END W0_data[272]
  PIN W0_data[273]
    DIRECTION INPUT ;
    USE SIGNAL ;
    SHAPE ABUTMENT ;
    PORT
      LAYER M5 ;
      RECT 59.196 0.000 59.292 0.096 ;
    END
  END W0_data[273]
  PIN W0_data[274]
    DIRECTION INPUT ;
    USE SIGNAL ;
    SHAPE ABUTMENT ;
    PORT
      LAYER M4 ;
      RECT 0.000 151.164 0.096 151.260 ;
    END
  END W0_data[274]
  PIN W0_data[275]
    DIRECTION INPUT ;
    USE SIGNAL ;
    SHAPE ABUTMENT ;
    PORT
      LAYER M4 ;
      RECT 81.904 151.164 82.000 151.260 ;
    END
  END W0_data[275]
  PIN W0_data[276]
    DIRECTION INPUT ;
    USE SIGNAL ;
    SHAPE ABUTMENT ;
    PORT
      LAYER M5 ;
      RECT 59.484 207.904 59.580 208.000 ;
    END
  END W0_data[276]
  PIN W0_data[277]
    DIRECTION INPUT ;
    USE SIGNAL ;
    SHAPE ABUTMENT ;
    PORT
      LAYER M5 ;
      RECT 59.484 0.000 59.580 0.096 ;
    END
  END W0_data[277]
  PIN W0_data[278]
    DIRECTION INPUT ;
    USE SIGNAL ;
    SHAPE ABUTMENT ;
    PORT
      LAYER M4 ;
      RECT 0.000 151.932 0.096 152.028 ;
    END
  END W0_data[278]
  PIN W0_data[279]
    DIRECTION INPUT ;
    USE SIGNAL ;
    SHAPE ABUTMENT ;
    PORT
      LAYER M4 ;
      RECT 81.904 151.932 82.000 152.028 ;
    END
  END W0_data[279]
  PIN W0_data[280]
    DIRECTION INPUT ;
    USE SIGNAL ;
    SHAPE ABUTMENT ;
    PORT
      LAYER M5 ;
      RECT 59.772 207.904 59.868 208.000 ;
    END
  END W0_data[280]
  PIN W0_data[281]
    DIRECTION INPUT ;
    USE SIGNAL ;
    SHAPE ABUTMENT ;
    PORT
      LAYER M5 ;
      RECT 59.772 0.000 59.868 0.096 ;
    END
  END W0_data[281]
  PIN W0_data[282]
    DIRECTION INPUT ;
    USE SIGNAL ;
    SHAPE ABUTMENT ;
    PORT
      LAYER M4 ;
      RECT 0.000 152.652 0.096 152.748 ;
    END
  END W0_data[282]
  PIN W0_data[283]
    DIRECTION INPUT ;
    USE SIGNAL ;
    SHAPE ABUTMENT ;
    PORT
      LAYER M4 ;
      RECT 81.904 152.652 82.000 152.748 ;
    END
  END W0_data[283]
  PIN W0_data[284]
    DIRECTION INPUT ;
    USE SIGNAL ;
    SHAPE ABUTMENT ;
    PORT
      LAYER M5 ;
      RECT 60.060 207.904 60.156 208.000 ;
    END
  END W0_data[284]
  PIN W0_data[285]
    DIRECTION INPUT ;
    USE SIGNAL ;
    SHAPE ABUTMENT ;
    PORT
      LAYER M5 ;
      RECT 60.060 0.000 60.156 0.096 ;
    END
  END W0_data[285]
  PIN W0_data[286]
    DIRECTION INPUT ;
    USE SIGNAL ;
    SHAPE ABUTMENT ;
    PORT
      LAYER M4 ;
      RECT 0.000 153.420 0.096 153.516 ;
    END
  END W0_data[286]
  PIN W0_data[287]
    DIRECTION INPUT ;
    USE SIGNAL ;
    SHAPE ABUTMENT ;
    PORT
      LAYER M4 ;
      RECT 81.904 153.420 82.000 153.516 ;
    END
  END W0_data[287]
  PIN W0_data[288]
    DIRECTION INPUT ;
    USE SIGNAL ;
    SHAPE ABUTMENT ;
    PORT
      LAYER M5 ;
      RECT 60.348 207.904 60.444 208.000 ;
    END
  END W0_data[288]
  PIN W0_data[289]
    DIRECTION INPUT ;
    USE SIGNAL ;
    SHAPE ABUTMENT ;
    PORT
      LAYER M5 ;
      RECT 60.348 0.000 60.444 0.096 ;
    END
  END W0_data[289]
  PIN W0_data[290]
    DIRECTION INPUT ;
    USE SIGNAL ;
    SHAPE ABUTMENT ;
    PORT
      LAYER M4 ;
      RECT 0.000 154.140 0.096 154.236 ;
    END
  END W0_data[290]
  PIN W0_data[291]
    DIRECTION INPUT ;
    USE SIGNAL ;
    SHAPE ABUTMENT ;
    PORT
      LAYER M4 ;
      RECT 81.904 154.140 82.000 154.236 ;
    END
  END W0_data[291]
  PIN W0_data[292]
    DIRECTION INPUT ;
    USE SIGNAL ;
    SHAPE ABUTMENT ;
    PORT
      LAYER M5 ;
      RECT 60.636 207.904 60.732 208.000 ;
    END
  END W0_data[292]
  PIN W0_data[293]
    DIRECTION INPUT ;
    USE SIGNAL ;
    SHAPE ABUTMENT ;
    PORT
      LAYER M5 ;
      RECT 60.636 0.000 60.732 0.096 ;
    END
  END W0_data[293]
  PIN W0_data[294]
    DIRECTION INPUT ;
    USE SIGNAL ;
    SHAPE ABUTMENT ;
    PORT
      LAYER M4 ;
      RECT 0.000 154.908 0.096 155.004 ;
    END
  END W0_data[294]
  PIN W0_data[295]
    DIRECTION INPUT ;
    USE SIGNAL ;
    SHAPE ABUTMENT ;
    PORT
      LAYER M4 ;
      RECT 81.904 154.908 82.000 155.004 ;
    END
  END W0_data[295]
  PIN W0_data[296]
    DIRECTION INPUT ;
    USE SIGNAL ;
    SHAPE ABUTMENT ;
    PORT
      LAYER M5 ;
      RECT 60.972 207.904 61.068 208.000 ;
    END
  END W0_data[296]
  PIN W0_data[297]
    DIRECTION INPUT ;
    USE SIGNAL ;
    SHAPE ABUTMENT ;
    PORT
      LAYER M5 ;
      RECT 60.972 0.000 61.068 0.096 ;
    END
  END W0_data[297]
  PIN W0_data[298]
    DIRECTION INPUT ;
    USE SIGNAL ;
    SHAPE ABUTMENT ;
    PORT
      LAYER M4 ;
      RECT 0.000 155.628 0.096 155.724 ;
    END
  END W0_data[298]
  PIN W0_data[299]
    DIRECTION INPUT ;
    USE SIGNAL ;
    SHAPE ABUTMENT ;
    PORT
      LAYER M4 ;
      RECT 81.904 155.628 82.000 155.724 ;
    END
  END W0_data[299]
  PIN W0_data[300]
    DIRECTION INPUT ;
    USE SIGNAL ;
    SHAPE ABUTMENT ;
    PORT
      LAYER M5 ;
      RECT 61.260 207.904 61.356 208.000 ;
    END
  END W0_data[300]
  PIN W0_data[301]
    DIRECTION INPUT ;
    USE SIGNAL ;
    SHAPE ABUTMENT ;
    PORT
      LAYER M5 ;
      RECT 61.260 0.000 61.356 0.096 ;
    END
  END W0_data[301]
  PIN W0_data[302]
    DIRECTION INPUT ;
    USE SIGNAL ;
    SHAPE ABUTMENT ;
    PORT
      LAYER M4 ;
      RECT 0.000 156.396 0.096 156.492 ;
    END
  END W0_data[302]
  PIN W0_data[303]
    DIRECTION INPUT ;
    USE SIGNAL ;
    SHAPE ABUTMENT ;
    PORT
      LAYER M4 ;
      RECT 81.904 156.396 82.000 156.492 ;
    END
  END W0_data[303]
  PIN W0_data[304]
    DIRECTION INPUT ;
    USE SIGNAL ;
    SHAPE ABUTMENT ;
    PORT
      LAYER M5 ;
      RECT 61.548 207.904 61.644 208.000 ;
    END
  END W0_data[304]
  PIN W0_data[305]
    DIRECTION INPUT ;
    USE SIGNAL ;
    SHAPE ABUTMENT ;
    PORT
      LAYER M5 ;
      RECT 61.548 0.000 61.644 0.096 ;
    END
  END W0_data[305]
  PIN W0_data[306]
    DIRECTION INPUT ;
    USE SIGNAL ;
    SHAPE ABUTMENT ;
    PORT
      LAYER M4 ;
      RECT 0.000 157.116 0.096 157.212 ;
    END
  END W0_data[306]
  PIN W0_data[307]
    DIRECTION INPUT ;
    USE SIGNAL ;
    SHAPE ABUTMENT ;
    PORT
      LAYER M4 ;
      RECT 81.904 157.116 82.000 157.212 ;
    END
  END W0_data[307]
  PIN W0_data[308]
    DIRECTION INPUT ;
    USE SIGNAL ;
    SHAPE ABUTMENT ;
    PORT
      LAYER M5 ;
      RECT 61.836 207.904 61.932 208.000 ;
    END
  END W0_data[308]
  PIN W0_data[309]
    DIRECTION INPUT ;
    USE SIGNAL ;
    SHAPE ABUTMENT ;
    PORT
      LAYER M5 ;
      RECT 61.836 0.000 61.932 0.096 ;
    END
  END W0_data[309]
  PIN W0_data[310]
    DIRECTION INPUT ;
    USE SIGNAL ;
    SHAPE ABUTMENT ;
    PORT
      LAYER M4 ;
      RECT 0.000 157.884 0.096 157.980 ;
    END
  END W0_data[310]
  PIN W0_data[311]
    DIRECTION INPUT ;
    USE SIGNAL ;
    SHAPE ABUTMENT ;
    PORT
      LAYER M4 ;
      RECT 81.904 157.884 82.000 157.980 ;
    END
  END W0_data[311]
  PIN W0_data[312]
    DIRECTION INPUT ;
    USE SIGNAL ;
    SHAPE ABUTMENT ;
    PORT
      LAYER M5 ;
      RECT 62.124 207.904 62.220 208.000 ;
    END
  END W0_data[312]
  PIN W0_data[313]
    DIRECTION INPUT ;
    USE SIGNAL ;
    SHAPE ABUTMENT ;
    PORT
      LAYER M5 ;
      RECT 62.124 0.000 62.220 0.096 ;
    END
  END W0_data[313]
  PIN W0_data[314]
    DIRECTION INPUT ;
    USE SIGNAL ;
    SHAPE ABUTMENT ;
    PORT
      LAYER M4 ;
      RECT 0.000 158.604 0.096 158.700 ;
    END
  END W0_data[314]
  PIN W0_data[315]
    DIRECTION INPUT ;
    USE SIGNAL ;
    SHAPE ABUTMENT ;
    PORT
      LAYER M4 ;
      RECT 81.904 158.604 82.000 158.700 ;
    END
  END W0_data[315]
  PIN W0_data[316]
    DIRECTION INPUT ;
    USE SIGNAL ;
    SHAPE ABUTMENT ;
    PORT
      LAYER M5 ;
      RECT 62.412 207.904 62.508 208.000 ;
    END
  END W0_data[316]
  PIN W0_data[317]
    DIRECTION INPUT ;
    USE SIGNAL ;
    SHAPE ABUTMENT ;
    PORT
      LAYER M5 ;
      RECT 62.412 0.000 62.508 0.096 ;
    END
  END W0_data[317]
  PIN W0_data[318]
    DIRECTION INPUT ;
    USE SIGNAL ;
    SHAPE ABUTMENT ;
    PORT
      LAYER M4 ;
      RECT 0.000 159.372 0.096 159.468 ;
    END
  END W0_data[318]
  PIN W0_data[319]
    DIRECTION INPUT ;
    USE SIGNAL ;
    SHAPE ABUTMENT ;
    PORT
      LAYER M4 ;
      RECT 81.904 159.372 82.000 159.468 ;
    END
  END W0_data[319]
  PIN W0_data[320]
    DIRECTION INPUT ;
    USE SIGNAL ;
    SHAPE ABUTMENT ;
    PORT
      LAYER M5 ;
      RECT 62.700 207.904 62.796 208.000 ;
    END
  END W0_data[320]
  PIN W0_data[321]
    DIRECTION INPUT ;
    USE SIGNAL ;
    SHAPE ABUTMENT ;
    PORT
      LAYER M5 ;
      RECT 62.700 0.000 62.796 0.096 ;
    END
  END W0_data[321]
  PIN W0_data[322]
    DIRECTION INPUT ;
    USE SIGNAL ;
    SHAPE ABUTMENT ;
    PORT
      LAYER M4 ;
      RECT 0.000 160.092 0.096 160.188 ;
    END
  END W0_data[322]
  PIN W0_data[323]
    DIRECTION INPUT ;
    USE SIGNAL ;
    SHAPE ABUTMENT ;
    PORT
      LAYER M4 ;
      RECT 81.904 160.092 82.000 160.188 ;
    END
  END W0_data[323]
  PIN W0_data[324]
    DIRECTION INPUT ;
    USE SIGNAL ;
    SHAPE ABUTMENT ;
    PORT
      LAYER M5 ;
      RECT 62.988 207.904 63.084 208.000 ;
    END
  END W0_data[324]
  PIN W0_data[325]
    DIRECTION INPUT ;
    USE SIGNAL ;
    SHAPE ABUTMENT ;
    PORT
      LAYER M5 ;
      RECT 62.988 0.000 63.084 0.096 ;
    END
  END W0_data[325]
  PIN W0_data[326]
    DIRECTION INPUT ;
    USE SIGNAL ;
    SHAPE ABUTMENT ;
    PORT
      LAYER M4 ;
      RECT 0.000 160.860 0.096 160.956 ;
    END
  END W0_data[326]
  PIN W0_data[327]
    DIRECTION INPUT ;
    USE SIGNAL ;
    SHAPE ABUTMENT ;
    PORT
      LAYER M4 ;
      RECT 81.904 160.860 82.000 160.956 ;
    END
  END W0_data[327]
  PIN W0_data[328]
    DIRECTION INPUT ;
    USE SIGNAL ;
    SHAPE ABUTMENT ;
    PORT
      LAYER M5 ;
      RECT 63.276 207.904 63.372 208.000 ;
    END
  END W0_data[328]
  PIN W0_data[329]
    DIRECTION INPUT ;
    USE SIGNAL ;
    SHAPE ABUTMENT ;
    PORT
      LAYER M5 ;
      RECT 63.276 0.000 63.372 0.096 ;
    END
  END W0_data[329]
  PIN W0_data[330]
    DIRECTION INPUT ;
    USE SIGNAL ;
    SHAPE ABUTMENT ;
    PORT
      LAYER M4 ;
      RECT 0.000 161.580 0.096 161.676 ;
    END
  END W0_data[330]
  PIN W0_data[331]
    DIRECTION INPUT ;
    USE SIGNAL ;
    SHAPE ABUTMENT ;
    PORT
      LAYER M4 ;
      RECT 81.904 161.580 82.000 161.676 ;
    END
  END W0_data[331]
  PIN W0_data[332]
    DIRECTION INPUT ;
    USE SIGNAL ;
    SHAPE ABUTMENT ;
    PORT
      LAYER M5 ;
      RECT 63.564 207.904 63.660 208.000 ;
    END
  END W0_data[332]
  PIN W0_data[333]
    DIRECTION INPUT ;
    USE SIGNAL ;
    SHAPE ABUTMENT ;
    PORT
      LAYER M5 ;
      RECT 63.564 0.000 63.660 0.096 ;
    END
  END W0_data[333]
  PIN W0_data[334]
    DIRECTION INPUT ;
    USE SIGNAL ;
    SHAPE ABUTMENT ;
    PORT
      LAYER M4 ;
      RECT 0.000 162.348 0.096 162.444 ;
    END
  END W0_data[334]
  PIN W0_data[335]
    DIRECTION INPUT ;
    USE SIGNAL ;
    SHAPE ABUTMENT ;
    PORT
      LAYER M4 ;
      RECT 81.904 162.348 82.000 162.444 ;
    END
  END W0_data[335]
  PIN W0_data[336]
    DIRECTION INPUT ;
    USE SIGNAL ;
    SHAPE ABUTMENT ;
    PORT
      LAYER M5 ;
      RECT 63.852 207.904 63.948 208.000 ;
    END
  END W0_data[336]
  PIN W0_data[337]
    DIRECTION INPUT ;
    USE SIGNAL ;
    SHAPE ABUTMENT ;
    PORT
      LAYER M5 ;
      RECT 63.852 0.000 63.948 0.096 ;
    END
  END W0_data[337]
  PIN W0_data[338]
    DIRECTION INPUT ;
    USE SIGNAL ;
    SHAPE ABUTMENT ;
    PORT
      LAYER M4 ;
      RECT 0.000 163.068 0.096 163.164 ;
    END
  END W0_data[338]
  PIN W0_data[339]
    DIRECTION INPUT ;
    USE SIGNAL ;
    SHAPE ABUTMENT ;
    PORT
      LAYER M4 ;
      RECT 81.904 163.068 82.000 163.164 ;
    END
  END W0_data[339]
  PIN W0_data[340]
    DIRECTION INPUT ;
    USE SIGNAL ;
    SHAPE ABUTMENT ;
    PORT
      LAYER M5 ;
      RECT 64.140 207.904 64.236 208.000 ;
    END
  END W0_data[340]
  PIN W0_data[341]
    DIRECTION INPUT ;
    USE SIGNAL ;
    SHAPE ABUTMENT ;
    PORT
      LAYER M5 ;
      RECT 64.140 0.000 64.236 0.096 ;
    END
  END W0_data[341]
  PIN W0_data[342]
    DIRECTION INPUT ;
    USE SIGNAL ;
    SHAPE ABUTMENT ;
    PORT
      LAYER M4 ;
      RECT 0.000 163.836 0.096 163.932 ;
    END
  END W0_data[342]
  PIN W0_data[343]
    DIRECTION INPUT ;
    USE SIGNAL ;
    SHAPE ABUTMENT ;
    PORT
      LAYER M4 ;
      RECT 81.904 163.836 82.000 163.932 ;
    END
  END W0_data[343]
  PIN W0_data[344]
    DIRECTION INPUT ;
    USE SIGNAL ;
    SHAPE ABUTMENT ;
    PORT
      LAYER M5 ;
      RECT 64.428 207.904 64.524 208.000 ;
    END
  END W0_data[344]
  PIN W0_data[345]
    DIRECTION INPUT ;
    USE SIGNAL ;
    SHAPE ABUTMENT ;
    PORT
      LAYER M5 ;
      RECT 64.428 0.000 64.524 0.096 ;
    END
  END W0_data[345]
  PIN W0_data[346]
    DIRECTION INPUT ;
    USE SIGNAL ;
    SHAPE ABUTMENT ;
    PORT
      LAYER M4 ;
      RECT 0.000 164.556 0.096 164.652 ;
    END
  END W0_data[346]
  PIN W0_data[347]
    DIRECTION INPUT ;
    USE SIGNAL ;
    SHAPE ABUTMENT ;
    PORT
      LAYER M4 ;
      RECT 81.904 164.556 82.000 164.652 ;
    END
  END W0_data[347]
  PIN W0_data[348]
    DIRECTION INPUT ;
    USE SIGNAL ;
    SHAPE ABUTMENT ;
    PORT
      LAYER M5 ;
      RECT 64.716 207.904 64.812 208.000 ;
    END
  END W0_data[348]
  PIN W0_data[349]
    DIRECTION INPUT ;
    USE SIGNAL ;
    SHAPE ABUTMENT ;
    PORT
      LAYER M5 ;
      RECT 64.716 0.000 64.812 0.096 ;
    END
  END W0_data[349]
  PIN W0_data[350]
    DIRECTION INPUT ;
    USE SIGNAL ;
    SHAPE ABUTMENT ;
    PORT
      LAYER M4 ;
      RECT 0.000 165.324 0.096 165.420 ;
    END
  END W0_data[350]
  PIN W0_data[351]
    DIRECTION INPUT ;
    USE SIGNAL ;
    SHAPE ABUTMENT ;
    PORT
      LAYER M4 ;
      RECT 81.904 165.324 82.000 165.420 ;
    END
  END W0_data[351]
  PIN W0_data[352]
    DIRECTION INPUT ;
    USE SIGNAL ;
    SHAPE ABUTMENT ;
    PORT
      LAYER M5 ;
      RECT 65.004 207.904 65.100 208.000 ;
    END
  END W0_data[352]
  PIN W0_data[353]
    DIRECTION INPUT ;
    USE SIGNAL ;
    SHAPE ABUTMENT ;
    PORT
      LAYER M5 ;
      RECT 65.004 0.000 65.100 0.096 ;
    END
  END W0_data[353]
  PIN W0_data[354]
    DIRECTION INPUT ;
    USE SIGNAL ;
    SHAPE ABUTMENT ;
    PORT
      LAYER M4 ;
      RECT 0.000 166.044 0.096 166.140 ;
    END
  END W0_data[354]
  PIN W0_data[355]
    DIRECTION INPUT ;
    USE SIGNAL ;
    SHAPE ABUTMENT ;
    PORT
      LAYER M4 ;
      RECT 81.904 166.044 82.000 166.140 ;
    END
  END W0_data[355]
  PIN W0_data[356]
    DIRECTION INPUT ;
    USE SIGNAL ;
    SHAPE ABUTMENT ;
    PORT
      LAYER M5 ;
      RECT 65.292 207.904 65.388 208.000 ;
    END
  END W0_data[356]
  PIN W0_data[357]
    DIRECTION INPUT ;
    USE SIGNAL ;
    SHAPE ABUTMENT ;
    PORT
      LAYER M5 ;
      RECT 65.292 0.000 65.388 0.096 ;
    END
  END W0_data[357]
  PIN W0_data[358]
    DIRECTION INPUT ;
    USE SIGNAL ;
    SHAPE ABUTMENT ;
    PORT
      LAYER M4 ;
      RECT 0.000 166.764 0.096 166.860 ;
    END
  END W0_data[358]
  PIN W0_data[359]
    DIRECTION INPUT ;
    USE SIGNAL ;
    SHAPE ABUTMENT ;
    PORT
      LAYER M4 ;
      RECT 81.904 166.764 82.000 166.860 ;
    END
  END W0_data[359]
  PIN W0_data[360]
    DIRECTION INPUT ;
    USE SIGNAL ;
    SHAPE ABUTMENT ;
    PORT
      LAYER M5 ;
      RECT 65.580 207.904 65.676 208.000 ;
    END
  END W0_data[360]
  PIN W0_data[361]
    DIRECTION INPUT ;
    USE SIGNAL ;
    SHAPE ABUTMENT ;
    PORT
      LAYER M5 ;
      RECT 65.580 0.000 65.676 0.096 ;
    END
  END W0_data[361]
  PIN W0_data[362]
    DIRECTION INPUT ;
    USE SIGNAL ;
    SHAPE ABUTMENT ;
    PORT
      LAYER M4 ;
      RECT 0.000 167.532 0.096 167.628 ;
    END
  END W0_data[362]
  PIN W0_data[363]
    DIRECTION INPUT ;
    USE SIGNAL ;
    SHAPE ABUTMENT ;
    PORT
      LAYER M4 ;
      RECT 81.904 167.532 82.000 167.628 ;
    END
  END W0_data[363]
  PIN W0_data[364]
    DIRECTION INPUT ;
    USE SIGNAL ;
    SHAPE ABUTMENT ;
    PORT
      LAYER M5 ;
      RECT 65.868 207.904 65.964 208.000 ;
    END
  END W0_data[364]
  PIN W0_data[365]
    DIRECTION INPUT ;
    USE SIGNAL ;
    SHAPE ABUTMENT ;
    PORT
      LAYER M5 ;
      RECT 65.868 0.000 65.964 0.096 ;
    END
  END W0_data[365]
  PIN W0_data[366]
    DIRECTION INPUT ;
    USE SIGNAL ;
    SHAPE ABUTMENT ;
    PORT
      LAYER M4 ;
      RECT 0.000 168.252 0.096 168.348 ;
    END
  END W0_data[366]
  PIN W0_data[367]
    DIRECTION INPUT ;
    USE SIGNAL ;
    SHAPE ABUTMENT ;
    PORT
      LAYER M4 ;
      RECT 81.904 168.252 82.000 168.348 ;
    END
  END W0_data[367]
  PIN W0_data[368]
    DIRECTION INPUT ;
    USE SIGNAL ;
    SHAPE ABUTMENT ;
    PORT
      LAYER M5 ;
      RECT 66.156 207.904 66.252 208.000 ;
    END
  END W0_data[368]
  PIN W0_data[369]
    DIRECTION INPUT ;
    USE SIGNAL ;
    SHAPE ABUTMENT ;
    PORT
      LAYER M5 ;
      RECT 66.156 0.000 66.252 0.096 ;
    END
  END W0_data[369]
  PIN W0_data[370]
    DIRECTION INPUT ;
    USE SIGNAL ;
    SHAPE ABUTMENT ;
    PORT
      LAYER M4 ;
      RECT 0.000 169.020 0.096 169.116 ;
    END
  END W0_data[370]
  PIN W0_data[371]
    DIRECTION INPUT ;
    USE SIGNAL ;
    SHAPE ABUTMENT ;
    PORT
      LAYER M4 ;
      RECT 81.904 169.020 82.000 169.116 ;
    END
  END W0_data[371]
  PIN W0_data[372]
    DIRECTION INPUT ;
    USE SIGNAL ;
    SHAPE ABUTMENT ;
    PORT
      LAYER M5 ;
      RECT 66.444 207.904 66.540 208.000 ;
    END
  END W0_data[372]
  PIN W0_data[373]
    DIRECTION INPUT ;
    USE SIGNAL ;
    SHAPE ABUTMENT ;
    PORT
      LAYER M5 ;
      RECT 66.444 0.000 66.540 0.096 ;
    END
  END W0_data[373]
  PIN W0_data[374]
    DIRECTION INPUT ;
    USE SIGNAL ;
    SHAPE ABUTMENT ;
    PORT
      LAYER M4 ;
      RECT 0.000 169.740 0.096 169.836 ;
    END
  END W0_data[374]
  PIN W0_data[375]
    DIRECTION INPUT ;
    USE SIGNAL ;
    SHAPE ABUTMENT ;
    PORT
      LAYER M4 ;
      RECT 81.904 169.740 82.000 169.836 ;
    END
  END W0_data[375]
  PIN W0_data[376]
    DIRECTION INPUT ;
    USE SIGNAL ;
    SHAPE ABUTMENT ;
    PORT
      LAYER M5 ;
      RECT 66.732 207.904 66.828 208.000 ;
    END
  END W0_data[376]
  PIN W0_data[377]
    DIRECTION INPUT ;
    USE SIGNAL ;
    SHAPE ABUTMENT ;
    PORT
      LAYER M5 ;
      RECT 66.732 0.000 66.828 0.096 ;
    END
  END W0_data[377]
  PIN W0_data[378]
    DIRECTION INPUT ;
    USE SIGNAL ;
    SHAPE ABUTMENT ;
    PORT
      LAYER M4 ;
      RECT 0.000 170.508 0.096 170.604 ;
    END
  END W0_data[378]
  PIN W0_data[379]
    DIRECTION INPUT ;
    USE SIGNAL ;
    SHAPE ABUTMENT ;
    PORT
      LAYER M4 ;
      RECT 81.904 170.508 82.000 170.604 ;
    END
  END W0_data[379]
  PIN W0_data[380]
    DIRECTION INPUT ;
    USE SIGNAL ;
    SHAPE ABUTMENT ;
    PORT
      LAYER M5 ;
      RECT 67.020 207.904 67.116 208.000 ;
    END
  END W0_data[380]
  PIN W0_data[381]
    DIRECTION INPUT ;
    USE SIGNAL ;
    SHAPE ABUTMENT ;
    PORT
      LAYER M5 ;
      RECT 67.020 0.000 67.116 0.096 ;
    END
  END W0_data[381]
  PIN W0_data[382]
    DIRECTION INPUT ;
    USE SIGNAL ;
    SHAPE ABUTMENT ;
    PORT
      LAYER M4 ;
      RECT 0.000 171.228 0.096 171.324 ;
    END
  END W0_data[382]
  PIN W0_data[383]
    DIRECTION INPUT ;
    USE SIGNAL ;
    SHAPE ABUTMENT ;
    PORT
      LAYER M4 ;
      RECT 81.904 171.228 82.000 171.324 ;
    END
  END W0_data[383]
  PIN W0_data[384]
    DIRECTION INPUT ;
    USE SIGNAL ;
    SHAPE ABUTMENT ;
    PORT
      LAYER M5 ;
      RECT 67.308 207.904 67.404 208.000 ;
    END
  END W0_data[384]
  PIN W0_data[385]
    DIRECTION INPUT ;
    USE SIGNAL ;
    SHAPE ABUTMENT ;
    PORT
      LAYER M5 ;
      RECT 67.308 0.000 67.404 0.096 ;
    END
  END W0_data[385]
  PIN W0_data[386]
    DIRECTION INPUT ;
    USE SIGNAL ;
    SHAPE ABUTMENT ;
    PORT
      LAYER M4 ;
      RECT 0.000 171.996 0.096 172.092 ;
    END
  END W0_data[386]
  PIN W0_data[387]
    DIRECTION INPUT ;
    USE SIGNAL ;
    SHAPE ABUTMENT ;
    PORT
      LAYER M4 ;
      RECT 81.904 171.996 82.000 172.092 ;
    END
  END W0_data[387]
  PIN W0_data[388]
    DIRECTION INPUT ;
    USE SIGNAL ;
    SHAPE ABUTMENT ;
    PORT
      LAYER M5 ;
      RECT 67.596 207.904 67.692 208.000 ;
    END
  END W0_data[388]
  PIN W0_data[389]
    DIRECTION INPUT ;
    USE SIGNAL ;
    SHAPE ABUTMENT ;
    PORT
      LAYER M5 ;
      RECT 67.596 0.000 67.692 0.096 ;
    END
  END W0_data[389]
  PIN W0_data[390]
    DIRECTION INPUT ;
    USE SIGNAL ;
    SHAPE ABUTMENT ;
    PORT
      LAYER M4 ;
      RECT 0.000 172.716 0.096 172.812 ;
    END
  END W0_data[390]
  PIN W0_data[391]
    DIRECTION INPUT ;
    USE SIGNAL ;
    SHAPE ABUTMENT ;
    PORT
      LAYER M4 ;
      RECT 81.904 172.716 82.000 172.812 ;
    END
  END W0_data[391]
  PIN W0_data[392]
    DIRECTION INPUT ;
    USE SIGNAL ;
    SHAPE ABUTMENT ;
    PORT
      LAYER M5 ;
      RECT 67.884 207.904 67.980 208.000 ;
    END
  END W0_data[392]
  PIN W0_data[393]
    DIRECTION INPUT ;
    USE SIGNAL ;
    SHAPE ABUTMENT ;
    PORT
      LAYER M5 ;
      RECT 67.884 0.000 67.980 0.096 ;
    END
  END W0_data[393]
  PIN W0_data[394]
    DIRECTION INPUT ;
    USE SIGNAL ;
    SHAPE ABUTMENT ;
    PORT
      LAYER M4 ;
      RECT 0.000 173.484 0.096 173.580 ;
    END
  END W0_data[394]
  PIN W0_data[395]
    DIRECTION INPUT ;
    USE SIGNAL ;
    SHAPE ABUTMENT ;
    PORT
      LAYER M4 ;
      RECT 81.904 173.484 82.000 173.580 ;
    END
  END W0_data[395]
  PIN W0_data[396]
    DIRECTION INPUT ;
    USE SIGNAL ;
    SHAPE ABUTMENT ;
    PORT
      LAYER M5 ;
      RECT 68.172 207.904 68.268 208.000 ;
    END
  END W0_data[396]
  PIN W0_data[397]
    DIRECTION INPUT ;
    USE SIGNAL ;
    SHAPE ABUTMENT ;
    PORT
      LAYER M5 ;
      RECT 68.172 0.000 68.268 0.096 ;
    END
  END W0_data[397]
  PIN W0_data[398]
    DIRECTION INPUT ;
    USE SIGNAL ;
    SHAPE ABUTMENT ;
    PORT
      LAYER M4 ;
      RECT 0.000 174.204 0.096 174.300 ;
    END
  END W0_data[398]
  PIN W0_data[399]
    DIRECTION INPUT ;
    USE SIGNAL ;
    SHAPE ABUTMENT ;
    PORT
      LAYER M4 ;
      RECT 81.904 174.204 82.000 174.300 ;
    END
  END W0_data[399]
  PIN W0_data[400]
    DIRECTION INPUT ;
    USE SIGNAL ;
    SHAPE ABUTMENT ;
    PORT
      LAYER M5 ;
      RECT 68.460 207.904 68.556 208.000 ;
    END
  END W0_data[400]
  PIN W0_data[401]
    DIRECTION INPUT ;
    USE SIGNAL ;
    SHAPE ABUTMENT ;
    PORT
      LAYER M5 ;
      RECT 68.460 0.000 68.556 0.096 ;
    END
  END W0_data[401]
  PIN W0_data[402]
    DIRECTION INPUT ;
    USE SIGNAL ;
    SHAPE ABUTMENT ;
    PORT
      LAYER M4 ;
      RECT 0.000 174.972 0.096 175.068 ;
    END
  END W0_data[402]
  PIN W0_data[403]
    DIRECTION INPUT ;
    USE SIGNAL ;
    SHAPE ABUTMENT ;
    PORT
      LAYER M4 ;
      RECT 81.904 174.972 82.000 175.068 ;
    END
  END W0_data[403]
  PIN W0_data[404]
    DIRECTION INPUT ;
    USE SIGNAL ;
    SHAPE ABUTMENT ;
    PORT
      LAYER M5 ;
      RECT 68.748 207.904 68.844 208.000 ;
    END
  END W0_data[404]
  PIN W0_data[405]
    DIRECTION INPUT ;
    USE SIGNAL ;
    SHAPE ABUTMENT ;
    PORT
      LAYER M5 ;
      RECT 68.748 0.000 68.844 0.096 ;
    END
  END W0_data[405]
  PIN W0_data[406]
    DIRECTION INPUT ;
    USE SIGNAL ;
    SHAPE ABUTMENT ;
    PORT
      LAYER M4 ;
      RECT 0.000 175.692 0.096 175.788 ;
    END
  END W0_data[406]
  PIN W0_data[407]
    DIRECTION INPUT ;
    USE SIGNAL ;
    SHAPE ABUTMENT ;
    PORT
      LAYER M4 ;
      RECT 81.904 175.692 82.000 175.788 ;
    END
  END W0_data[407]
  PIN W0_data[408]
    DIRECTION INPUT ;
    USE SIGNAL ;
    SHAPE ABUTMENT ;
    PORT
      LAYER M5 ;
      RECT 69.084 207.904 69.180 208.000 ;
    END
  END W0_data[408]
  PIN W0_data[409]
    DIRECTION INPUT ;
    USE SIGNAL ;
    SHAPE ABUTMENT ;
    PORT
      LAYER M5 ;
      RECT 69.084 0.000 69.180 0.096 ;
    END
  END W0_data[409]
  PIN W0_data[410]
    DIRECTION INPUT ;
    USE SIGNAL ;
    SHAPE ABUTMENT ;
    PORT
      LAYER M4 ;
      RECT 0.000 176.460 0.096 176.556 ;
    END
  END W0_data[410]
  PIN W0_data[411]
    DIRECTION INPUT ;
    USE SIGNAL ;
    SHAPE ABUTMENT ;
    PORT
      LAYER M4 ;
      RECT 81.904 176.460 82.000 176.556 ;
    END
  END W0_data[411]
  PIN W0_data[412]
    DIRECTION INPUT ;
    USE SIGNAL ;
    SHAPE ABUTMENT ;
    PORT
      LAYER M5 ;
      RECT 69.372 207.904 69.468 208.000 ;
    END
  END W0_data[412]
  PIN W0_data[413]
    DIRECTION INPUT ;
    USE SIGNAL ;
    SHAPE ABUTMENT ;
    PORT
      LAYER M5 ;
      RECT 69.372 0.000 69.468 0.096 ;
    END
  END W0_data[413]
  PIN W0_data[414]
    DIRECTION INPUT ;
    USE SIGNAL ;
    SHAPE ABUTMENT ;
    PORT
      LAYER M4 ;
      RECT 0.000 177.180 0.096 177.276 ;
    END
  END W0_data[414]
  PIN W0_data[415]
    DIRECTION INPUT ;
    USE SIGNAL ;
    SHAPE ABUTMENT ;
    PORT
      LAYER M4 ;
      RECT 81.904 177.180 82.000 177.276 ;
    END
  END W0_data[415]
  PIN W0_data[416]
    DIRECTION INPUT ;
    USE SIGNAL ;
    SHAPE ABUTMENT ;
    PORT
      LAYER M5 ;
      RECT 69.660 207.904 69.756 208.000 ;
    END
  END W0_data[416]
  PIN W0_data[417]
    DIRECTION INPUT ;
    USE SIGNAL ;
    SHAPE ABUTMENT ;
    PORT
      LAYER M5 ;
      RECT 69.660 0.000 69.756 0.096 ;
    END
  END W0_data[417]
  PIN W0_data[418]
    DIRECTION INPUT ;
    USE SIGNAL ;
    SHAPE ABUTMENT ;
    PORT
      LAYER M4 ;
      RECT 0.000 177.948 0.096 178.044 ;
    END
  END W0_data[418]
  PIN W0_data[419]
    DIRECTION INPUT ;
    USE SIGNAL ;
    SHAPE ABUTMENT ;
    PORT
      LAYER M4 ;
      RECT 81.904 177.948 82.000 178.044 ;
    END
  END W0_data[419]
  PIN W0_data[420]
    DIRECTION INPUT ;
    USE SIGNAL ;
    SHAPE ABUTMENT ;
    PORT
      LAYER M5 ;
      RECT 69.948 207.904 70.044 208.000 ;
    END
  END W0_data[420]
  PIN W0_data[421]
    DIRECTION INPUT ;
    USE SIGNAL ;
    SHAPE ABUTMENT ;
    PORT
      LAYER M5 ;
      RECT 69.948 0.000 70.044 0.096 ;
    END
  END W0_data[421]
  PIN W0_data[422]
    DIRECTION INPUT ;
    USE SIGNAL ;
    SHAPE ABUTMENT ;
    PORT
      LAYER M4 ;
      RECT 0.000 178.668 0.096 178.764 ;
    END
  END W0_data[422]
  PIN W0_data[423]
    DIRECTION INPUT ;
    USE SIGNAL ;
    SHAPE ABUTMENT ;
    PORT
      LAYER M4 ;
      RECT 81.904 178.668 82.000 178.764 ;
    END
  END W0_data[423]
  PIN W0_data[424]
    DIRECTION INPUT ;
    USE SIGNAL ;
    SHAPE ABUTMENT ;
    PORT
      LAYER M5 ;
      RECT 70.236 207.904 70.332 208.000 ;
    END
  END W0_data[424]
  PIN W0_data[425]
    DIRECTION INPUT ;
    USE SIGNAL ;
    SHAPE ABUTMENT ;
    PORT
      LAYER M5 ;
      RECT 70.236 0.000 70.332 0.096 ;
    END
  END W0_data[425]
  PIN W0_data[426]
    DIRECTION INPUT ;
    USE SIGNAL ;
    SHAPE ABUTMENT ;
    PORT
      LAYER M4 ;
      RECT 0.000 179.436 0.096 179.532 ;
    END
  END W0_data[426]
  PIN W0_data[427]
    DIRECTION INPUT ;
    USE SIGNAL ;
    SHAPE ABUTMENT ;
    PORT
      LAYER M4 ;
      RECT 81.904 179.436 82.000 179.532 ;
    END
  END W0_data[427]
  PIN W0_data[428]
    DIRECTION INPUT ;
    USE SIGNAL ;
    SHAPE ABUTMENT ;
    PORT
      LAYER M5 ;
      RECT 70.524 207.904 70.620 208.000 ;
    END
  END W0_data[428]
  PIN W0_data[429]
    DIRECTION INPUT ;
    USE SIGNAL ;
    SHAPE ABUTMENT ;
    PORT
      LAYER M5 ;
      RECT 70.524 0.000 70.620 0.096 ;
    END
  END W0_data[429]
  PIN W0_data[430]
    DIRECTION INPUT ;
    USE SIGNAL ;
    SHAPE ABUTMENT ;
    PORT
      LAYER M4 ;
      RECT 0.000 180.156 0.096 180.252 ;
    END
  END W0_data[430]
  PIN W0_data[431]
    DIRECTION INPUT ;
    USE SIGNAL ;
    SHAPE ABUTMENT ;
    PORT
      LAYER M4 ;
      RECT 81.904 180.156 82.000 180.252 ;
    END
  END W0_data[431]
  PIN W0_data[432]
    DIRECTION INPUT ;
    USE SIGNAL ;
    SHAPE ABUTMENT ;
    PORT
      LAYER M5 ;
      RECT 70.812 207.904 70.908 208.000 ;
    END
  END W0_data[432]
  PIN W0_data[433]
    DIRECTION INPUT ;
    USE SIGNAL ;
    SHAPE ABUTMENT ;
    PORT
      LAYER M5 ;
      RECT 70.812 0.000 70.908 0.096 ;
    END
  END W0_data[433]
  PIN W0_data[434]
    DIRECTION INPUT ;
    USE SIGNAL ;
    SHAPE ABUTMENT ;
    PORT
      LAYER M4 ;
      RECT 0.000 180.924 0.096 181.020 ;
    END
  END W0_data[434]
  PIN W0_data[435]
    DIRECTION INPUT ;
    USE SIGNAL ;
    SHAPE ABUTMENT ;
    PORT
      LAYER M4 ;
      RECT 81.904 180.924 82.000 181.020 ;
    END
  END W0_data[435]
  PIN W0_data[436]
    DIRECTION INPUT ;
    USE SIGNAL ;
    SHAPE ABUTMENT ;
    PORT
      LAYER M5 ;
      RECT 71.100 207.904 71.196 208.000 ;
    END
  END W0_data[436]
  PIN W0_data[437]
    DIRECTION INPUT ;
    USE SIGNAL ;
    SHAPE ABUTMENT ;
    PORT
      LAYER M5 ;
      RECT 71.100 0.000 71.196 0.096 ;
    END
  END W0_data[437]
  PIN W0_data[438]
    DIRECTION INPUT ;
    USE SIGNAL ;
    SHAPE ABUTMENT ;
    PORT
      LAYER M4 ;
      RECT 0.000 181.644 0.096 181.740 ;
    END
  END W0_data[438]
  PIN W0_data[439]
    DIRECTION INPUT ;
    USE SIGNAL ;
    SHAPE ABUTMENT ;
    PORT
      LAYER M4 ;
      RECT 81.904 181.644 82.000 181.740 ;
    END
  END W0_data[439]
  PIN W0_data[440]
    DIRECTION INPUT ;
    USE SIGNAL ;
    SHAPE ABUTMENT ;
    PORT
      LAYER M5 ;
      RECT 71.388 207.904 71.484 208.000 ;
    END
  END W0_data[440]
  PIN W0_data[441]
    DIRECTION INPUT ;
    USE SIGNAL ;
    SHAPE ABUTMENT ;
    PORT
      LAYER M5 ;
      RECT 71.388 0.000 71.484 0.096 ;
    END
  END W0_data[441]
  PIN W0_data[442]
    DIRECTION INPUT ;
    USE SIGNAL ;
    SHAPE ABUTMENT ;
    PORT
      LAYER M4 ;
      RECT 0.000 182.412 0.096 182.508 ;
    END
  END W0_data[442]
  PIN W0_data[443]
    DIRECTION INPUT ;
    USE SIGNAL ;
    SHAPE ABUTMENT ;
    PORT
      LAYER M4 ;
      RECT 81.904 182.412 82.000 182.508 ;
    END
  END W0_data[443]
  PIN W0_data[444]
    DIRECTION INPUT ;
    USE SIGNAL ;
    SHAPE ABUTMENT ;
    PORT
      LAYER M5 ;
      RECT 71.676 207.904 71.772 208.000 ;
    END
  END W0_data[444]
  PIN W0_data[445]
    DIRECTION INPUT ;
    USE SIGNAL ;
    SHAPE ABUTMENT ;
    PORT
      LAYER M5 ;
      RECT 71.676 0.000 71.772 0.096 ;
    END
  END W0_data[445]
  PIN W0_data[446]
    DIRECTION INPUT ;
    USE SIGNAL ;
    SHAPE ABUTMENT ;
    PORT
      LAYER M4 ;
      RECT 0.000 183.132 0.096 183.228 ;
    END
  END W0_data[446]
  PIN W0_data[447]
    DIRECTION INPUT ;
    USE SIGNAL ;
    SHAPE ABUTMENT ;
    PORT
      LAYER M4 ;
      RECT 81.904 183.132 82.000 183.228 ;
    END
  END W0_data[447]
  PIN W0_data[448]
    DIRECTION INPUT ;
    USE SIGNAL ;
    SHAPE ABUTMENT ;
    PORT
      LAYER M5 ;
      RECT 71.964 207.904 72.060 208.000 ;
    END
  END W0_data[448]
  PIN W0_data[449]
    DIRECTION INPUT ;
    USE SIGNAL ;
    SHAPE ABUTMENT ;
    PORT
      LAYER M5 ;
      RECT 71.964 0.000 72.060 0.096 ;
    END
  END W0_data[449]
  PIN W0_data[450]
    DIRECTION INPUT ;
    USE SIGNAL ;
    SHAPE ABUTMENT ;
    PORT
      LAYER M4 ;
      RECT 0.000 183.900 0.096 183.996 ;
    END
  END W0_data[450]
  PIN W0_data[451]
    DIRECTION INPUT ;
    USE SIGNAL ;
    SHAPE ABUTMENT ;
    PORT
      LAYER M4 ;
      RECT 81.904 183.900 82.000 183.996 ;
    END
  END W0_data[451]
  PIN W0_data[452]
    DIRECTION INPUT ;
    USE SIGNAL ;
    SHAPE ABUTMENT ;
    PORT
      LAYER M5 ;
      RECT 72.252 207.904 72.348 208.000 ;
    END
  END W0_data[452]
  PIN W0_data[453]
    DIRECTION INPUT ;
    USE SIGNAL ;
    SHAPE ABUTMENT ;
    PORT
      LAYER M5 ;
      RECT 72.252 0.000 72.348 0.096 ;
    END
  END W0_data[453]
  PIN W0_data[454]
    DIRECTION INPUT ;
    USE SIGNAL ;
    SHAPE ABUTMENT ;
    PORT
      LAYER M4 ;
      RECT 0.000 184.620 0.096 184.716 ;
    END
  END W0_data[454]
  PIN W0_data[455]
    DIRECTION INPUT ;
    USE SIGNAL ;
    SHAPE ABUTMENT ;
    PORT
      LAYER M4 ;
      RECT 81.904 184.620 82.000 184.716 ;
    END
  END W0_data[455]
  PIN W0_data[456]
    DIRECTION INPUT ;
    USE SIGNAL ;
    SHAPE ABUTMENT ;
    PORT
      LAYER M5 ;
      RECT 72.540 207.904 72.636 208.000 ;
    END
  END W0_data[456]
  PIN W0_data[457]
    DIRECTION INPUT ;
    USE SIGNAL ;
    SHAPE ABUTMENT ;
    PORT
      LAYER M5 ;
      RECT 72.540 0.000 72.636 0.096 ;
    END
  END W0_data[457]
  PIN W0_data[458]
    DIRECTION INPUT ;
    USE SIGNAL ;
    SHAPE ABUTMENT ;
    PORT
      LAYER M4 ;
      RECT 0.000 185.388 0.096 185.484 ;
    END
  END W0_data[458]
  PIN W0_data[459]
    DIRECTION INPUT ;
    USE SIGNAL ;
    SHAPE ABUTMENT ;
    PORT
      LAYER M4 ;
      RECT 81.904 185.388 82.000 185.484 ;
    END
  END W0_data[459]
  PIN W0_data[460]
    DIRECTION INPUT ;
    USE SIGNAL ;
    SHAPE ABUTMENT ;
    PORT
      LAYER M5 ;
      RECT 72.828 207.904 72.924 208.000 ;
    END
  END W0_data[460]
  PIN W0_data[461]
    DIRECTION INPUT ;
    USE SIGNAL ;
    SHAPE ABUTMENT ;
    PORT
      LAYER M5 ;
      RECT 72.828 0.000 72.924 0.096 ;
    END
  END W0_data[461]
  PIN W0_data[462]
    DIRECTION INPUT ;
    USE SIGNAL ;
    SHAPE ABUTMENT ;
    PORT
      LAYER M4 ;
      RECT 0.000 186.108 0.096 186.204 ;
    END
  END W0_data[462]
  PIN W0_data[463]
    DIRECTION INPUT ;
    USE SIGNAL ;
    SHAPE ABUTMENT ;
    PORT
      LAYER M4 ;
      RECT 81.904 186.108 82.000 186.204 ;
    END
  END W0_data[463]
  PIN W0_data[464]
    DIRECTION INPUT ;
    USE SIGNAL ;
    SHAPE ABUTMENT ;
    PORT
      LAYER M5 ;
      RECT 73.116 207.904 73.212 208.000 ;
    END
  END W0_data[464]
  PIN W0_data[465]
    DIRECTION INPUT ;
    USE SIGNAL ;
    SHAPE ABUTMENT ;
    PORT
      LAYER M5 ;
      RECT 73.116 0.000 73.212 0.096 ;
    END
  END W0_data[465]
  PIN W0_data[466]
    DIRECTION INPUT ;
    USE SIGNAL ;
    SHAPE ABUTMENT ;
    PORT
      LAYER M4 ;
      RECT 0.000 186.876 0.096 186.972 ;
    END
  END W0_data[466]
  PIN W0_data[467]
    DIRECTION INPUT ;
    USE SIGNAL ;
    SHAPE ABUTMENT ;
    PORT
      LAYER M4 ;
      RECT 81.904 186.876 82.000 186.972 ;
    END
  END W0_data[467]
  PIN W0_data[468]
    DIRECTION INPUT ;
    USE SIGNAL ;
    SHAPE ABUTMENT ;
    PORT
      LAYER M5 ;
      RECT 73.404 207.904 73.500 208.000 ;
    END
  END W0_data[468]
  PIN W0_data[469]
    DIRECTION INPUT ;
    USE SIGNAL ;
    SHAPE ABUTMENT ;
    PORT
      LAYER M5 ;
      RECT 73.404 0.000 73.500 0.096 ;
    END
  END W0_data[469]
  PIN W0_data[470]
    DIRECTION INPUT ;
    USE SIGNAL ;
    SHAPE ABUTMENT ;
    PORT
      LAYER M4 ;
      RECT 0.000 187.596 0.096 187.692 ;
    END
  END W0_data[470]
  PIN W0_data[471]
    DIRECTION INPUT ;
    USE SIGNAL ;
    SHAPE ABUTMENT ;
    PORT
      LAYER M4 ;
      RECT 81.904 187.596 82.000 187.692 ;
    END
  END W0_data[471]
  PIN W0_data[472]
    DIRECTION INPUT ;
    USE SIGNAL ;
    SHAPE ABUTMENT ;
    PORT
      LAYER M5 ;
      RECT 73.692 207.904 73.788 208.000 ;
    END
  END W0_data[472]
  PIN W0_data[473]
    DIRECTION INPUT ;
    USE SIGNAL ;
    SHAPE ABUTMENT ;
    PORT
      LAYER M5 ;
      RECT 73.692 0.000 73.788 0.096 ;
    END
  END W0_data[473]
  PIN W0_data[474]
    DIRECTION INPUT ;
    USE SIGNAL ;
    SHAPE ABUTMENT ;
    PORT
      LAYER M4 ;
      RECT 0.000 188.364 0.096 188.460 ;
    END
  END W0_data[474]
  PIN W0_data[475]
    DIRECTION INPUT ;
    USE SIGNAL ;
    SHAPE ABUTMENT ;
    PORT
      LAYER M4 ;
      RECT 81.904 188.364 82.000 188.460 ;
    END
  END W0_data[475]
  PIN W0_data[476]
    DIRECTION INPUT ;
    USE SIGNAL ;
    SHAPE ABUTMENT ;
    PORT
      LAYER M5 ;
      RECT 73.980 207.904 74.076 208.000 ;
    END
  END W0_data[476]
  PIN W0_data[477]
    DIRECTION INPUT ;
    USE SIGNAL ;
    SHAPE ABUTMENT ;
    PORT
      LAYER M5 ;
      RECT 73.980 0.000 74.076 0.096 ;
    END
  END W0_data[477]
  PIN W0_data[478]
    DIRECTION INPUT ;
    USE SIGNAL ;
    SHAPE ABUTMENT ;
    PORT
      LAYER M4 ;
      RECT 0.000 189.084 0.096 189.180 ;
    END
  END W0_data[478]
  PIN W0_data[479]
    DIRECTION INPUT ;
    USE SIGNAL ;
    SHAPE ABUTMENT ;
    PORT
      LAYER M4 ;
      RECT 81.904 189.084 82.000 189.180 ;
    END
  END W0_data[479]
  PIN W0_data[480]
    DIRECTION INPUT ;
    USE SIGNAL ;
    SHAPE ABUTMENT ;
    PORT
      LAYER M5 ;
      RECT 74.268 207.904 74.364 208.000 ;
    END
  END W0_data[480]
  PIN W0_data[481]
    DIRECTION INPUT ;
    USE SIGNAL ;
    SHAPE ABUTMENT ;
    PORT
      LAYER M5 ;
      RECT 74.268 0.000 74.364 0.096 ;
    END
  END W0_data[481]
  PIN W0_data[482]
    DIRECTION INPUT ;
    USE SIGNAL ;
    SHAPE ABUTMENT ;
    PORT
      LAYER M4 ;
      RECT 0.000 189.852 0.096 189.948 ;
    END
  END W0_data[482]
  PIN W0_data[483]
    DIRECTION INPUT ;
    USE SIGNAL ;
    SHAPE ABUTMENT ;
    PORT
      LAYER M4 ;
      RECT 81.904 189.852 82.000 189.948 ;
    END
  END W0_data[483]
  PIN W0_data[484]
    DIRECTION INPUT ;
    USE SIGNAL ;
    SHAPE ABUTMENT ;
    PORT
      LAYER M5 ;
      RECT 74.556 207.904 74.652 208.000 ;
    END
  END W0_data[484]
  PIN W0_data[485]
    DIRECTION INPUT ;
    USE SIGNAL ;
    SHAPE ABUTMENT ;
    PORT
      LAYER M5 ;
      RECT 74.556 0.000 74.652 0.096 ;
    END
  END W0_data[485]
  PIN W0_data[486]
    DIRECTION INPUT ;
    USE SIGNAL ;
    SHAPE ABUTMENT ;
    PORT
      LAYER M4 ;
      RECT 0.000 190.572 0.096 190.668 ;
    END
  END W0_data[486]
  PIN W0_data[487]
    DIRECTION INPUT ;
    USE SIGNAL ;
    SHAPE ABUTMENT ;
    PORT
      LAYER M4 ;
      RECT 81.904 190.572 82.000 190.668 ;
    END
  END W0_data[487]
  PIN W0_data[488]
    DIRECTION INPUT ;
    USE SIGNAL ;
    SHAPE ABUTMENT ;
    PORT
      LAYER M5 ;
      RECT 74.844 207.904 74.940 208.000 ;
    END
  END W0_data[488]
  PIN W0_data[489]
    DIRECTION INPUT ;
    USE SIGNAL ;
    SHAPE ABUTMENT ;
    PORT
      LAYER M5 ;
      RECT 74.844 0.000 74.940 0.096 ;
    END
  END W0_data[489]
  PIN W0_data[490]
    DIRECTION INPUT ;
    USE SIGNAL ;
    SHAPE ABUTMENT ;
    PORT
      LAYER M4 ;
      RECT 0.000 191.340 0.096 191.436 ;
    END
  END W0_data[490]
  PIN W0_data[491]
    DIRECTION INPUT ;
    USE SIGNAL ;
    SHAPE ABUTMENT ;
    PORT
      LAYER M4 ;
      RECT 81.904 191.340 82.000 191.436 ;
    END
  END W0_data[491]
  PIN W0_data[492]
    DIRECTION INPUT ;
    USE SIGNAL ;
    SHAPE ABUTMENT ;
    PORT
      LAYER M5 ;
      RECT 75.132 207.904 75.228 208.000 ;
    END
  END W0_data[492]
  PIN W0_data[493]
    DIRECTION INPUT ;
    USE SIGNAL ;
    SHAPE ABUTMENT ;
    PORT
      LAYER M5 ;
      RECT 75.132 0.000 75.228 0.096 ;
    END
  END W0_data[493]
  PIN W0_data[494]
    DIRECTION INPUT ;
    USE SIGNAL ;
    SHAPE ABUTMENT ;
    PORT
      LAYER M4 ;
      RECT 0.000 192.060 0.096 192.156 ;
    END
  END W0_data[494]
  PIN W0_data[495]
    DIRECTION INPUT ;
    USE SIGNAL ;
    SHAPE ABUTMENT ;
    PORT
      LAYER M4 ;
      RECT 81.904 192.060 82.000 192.156 ;
    END
  END W0_data[495]
  PIN W0_data[496]
    DIRECTION INPUT ;
    USE SIGNAL ;
    SHAPE ABUTMENT ;
    PORT
      LAYER M5 ;
      RECT 75.420 207.904 75.516 208.000 ;
    END
  END W0_data[496]
  PIN W0_data[497]
    DIRECTION INPUT ;
    USE SIGNAL ;
    SHAPE ABUTMENT ;
    PORT
      LAYER M5 ;
      RECT 75.420 0.000 75.516 0.096 ;
    END
  END W0_data[497]
  PIN W0_data[498]
    DIRECTION INPUT ;
    USE SIGNAL ;
    SHAPE ABUTMENT ;
    PORT
      LAYER M4 ;
      RECT 0.000 192.828 0.096 192.924 ;
    END
  END W0_data[498]
  PIN W0_data[499]
    DIRECTION INPUT ;
    USE SIGNAL ;
    SHAPE ABUTMENT ;
    PORT
      LAYER M4 ;
      RECT 81.904 192.828 82.000 192.924 ;
    END
  END W0_data[499]
  PIN W0_data[500]
    DIRECTION INPUT ;
    USE SIGNAL ;
    SHAPE ABUTMENT ;
    PORT
      LAYER M5 ;
      RECT 75.708 207.904 75.804 208.000 ;
    END
  END W0_data[500]
  PIN W0_data[501]
    DIRECTION INPUT ;
    USE SIGNAL ;
    SHAPE ABUTMENT ;
    PORT
      LAYER M5 ;
      RECT 75.708 0.000 75.804 0.096 ;
    END
  END W0_data[501]
  PIN W0_data[502]
    DIRECTION INPUT ;
    USE SIGNAL ;
    SHAPE ABUTMENT ;
    PORT
      LAYER M4 ;
      RECT 0.000 193.548 0.096 193.644 ;
    END
  END W0_data[502]
  PIN W0_data[503]
    DIRECTION INPUT ;
    USE SIGNAL ;
    SHAPE ABUTMENT ;
    PORT
      LAYER M4 ;
      RECT 81.904 193.548 82.000 193.644 ;
    END
  END W0_data[503]
  PIN W0_data[504]
    DIRECTION INPUT ;
    USE SIGNAL ;
    SHAPE ABUTMENT ;
    PORT
      LAYER M5 ;
      RECT 75.996 207.904 76.092 208.000 ;
    END
  END W0_data[504]
  PIN W0_data[505]
    DIRECTION INPUT ;
    USE SIGNAL ;
    SHAPE ABUTMENT ;
    PORT
      LAYER M5 ;
      RECT 75.996 0.000 76.092 0.096 ;
    END
  END W0_data[505]
  PIN W0_data[506]
    DIRECTION INPUT ;
    USE SIGNAL ;
    SHAPE ABUTMENT ;
    PORT
      LAYER M4 ;
      RECT 0.000 194.316 0.096 194.412 ;
    END
  END W0_data[506]
  PIN W0_data[507]
    DIRECTION INPUT ;
    USE SIGNAL ;
    SHAPE ABUTMENT ;
    PORT
      LAYER M4 ;
      RECT 81.904 194.316 82.000 194.412 ;
    END
  END W0_data[507]
  PIN W0_data[508]
    DIRECTION INPUT ;
    USE SIGNAL ;
    SHAPE ABUTMENT ;
    PORT
      LAYER M5 ;
      RECT 76.284 207.904 76.380 208.000 ;
    END
  END W0_data[508]
  PIN W0_data[509]
    DIRECTION INPUT ;
    USE SIGNAL ;
    SHAPE ABUTMENT ;
    PORT
      LAYER M5 ;
      RECT 76.284 0.000 76.380 0.096 ;
    END
  END W0_data[509]
  PIN W0_data[510]
    DIRECTION INPUT ;
    USE SIGNAL ;
    SHAPE ABUTMENT ;
    PORT
      LAYER M4 ;
      RECT 0.000 195.036 0.096 195.132 ;
    END
  END W0_data[510]
  PIN W0_data[511]
    DIRECTION INPUT ;
    USE SIGNAL ;
    SHAPE ABUTMENT ;
    PORT
      LAYER M4 ;
      RECT 81.904 195.036 82.000 195.132 ;
    END
  END W0_data[511]
  PIN W0_mask[0]
    DIRECTION INPUT ;
    USE SIGNAL ;
    SHAPE ABUTMENT ;
    PORT
      LAYER M5 ;
      RECT 76.572 207.904 76.668 208.000 ;
    END
  END W0_mask[0]
  PIN W0_mask[1]
    DIRECTION INPUT ;
    USE SIGNAL ;
    SHAPE ABUTMENT ;
    PORT
      LAYER M5 ;
      RECT 76.572 0.000 76.668 0.096 ;
    END
  END W0_mask[1]
  PIN W0_mask[2]
    DIRECTION INPUT ;
    USE SIGNAL ;
    SHAPE ABUTMENT ;
    PORT
      LAYER M4 ;
      RECT 0.000 195.804 0.096 195.900 ;
    END
  END W0_mask[2]
  PIN W0_mask[3]
    DIRECTION INPUT ;
    USE SIGNAL ;
    SHAPE ABUTMENT ;
    PORT
      LAYER M4 ;
      RECT 81.904 195.804 82.000 195.900 ;
    END
  END W0_mask[3]
  PIN W0_mask[4]
    DIRECTION INPUT ;
    USE SIGNAL ;
    SHAPE ABUTMENT ;
    PORT
      LAYER M5 ;
      RECT 76.860 207.904 76.956 208.000 ;
    END
  END W0_mask[4]
  PIN W0_mask[5]
    DIRECTION INPUT ;
    USE SIGNAL ;
    SHAPE ABUTMENT ;
    PORT
      LAYER M5 ;
      RECT 76.860 0.000 76.956 0.096 ;
    END
  END W0_mask[5]
  PIN W0_mask[6]
    DIRECTION INPUT ;
    USE SIGNAL ;
    SHAPE ABUTMENT ;
    PORT
      LAYER M4 ;
      RECT 0.000 196.524 0.096 196.620 ;
    END
  END W0_mask[6]
  PIN W0_mask[7]
    DIRECTION INPUT ;
    USE SIGNAL ;
    SHAPE ABUTMENT ;
    PORT
      LAYER M4 ;
      RECT 81.904 196.524 82.000 196.620 ;
    END
  END W0_mask[7]
  PIN W0_mask[8]
    DIRECTION INPUT ;
    USE SIGNAL ;
    SHAPE ABUTMENT ;
    PORT
      LAYER M5 ;
      RECT 77.196 207.904 77.292 208.000 ;
    END
  END W0_mask[8]
  PIN W0_mask[9]
    DIRECTION INPUT ;
    USE SIGNAL ;
    SHAPE ABUTMENT ;
    PORT
      LAYER M5 ;
      RECT 77.196 0.000 77.292 0.096 ;
    END
  END W0_mask[9]
  PIN W0_mask[10]
    DIRECTION INPUT ;
    USE SIGNAL ;
    SHAPE ABUTMENT ;
    PORT
      LAYER M4 ;
      RECT 0.000 197.292 0.096 197.388 ;
    END
  END W0_mask[10]
  PIN W0_mask[11]
    DIRECTION INPUT ;
    USE SIGNAL ;
    SHAPE ABUTMENT ;
    PORT
      LAYER M4 ;
      RECT 81.904 197.292 82.000 197.388 ;
    END
  END W0_mask[11]
  PIN W0_mask[12]
    DIRECTION INPUT ;
    USE SIGNAL ;
    SHAPE ABUTMENT ;
    PORT
      LAYER M5 ;
      RECT 77.484 207.904 77.580 208.000 ;
    END
  END W0_mask[12]
  PIN W0_mask[13]
    DIRECTION INPUT ;
    USE SIGNAL ;
    SHAPE ABUTMENT ;
    PORT
      LAYER M5 ;
      RECT 77.484 0.000 77.580 0.096 ;
    END
  END W0_mask[13]
  PIN W0_mask[14]
    DIRECTION INPUT ;
    USE SIGNAL ;
    SHAPE ABUTMENT ;
    PORT
      LAYER M4 ;
      RECT 0.000 198.012 0.096 198.108 ;
    END
  END W0_mask[14]
  PIN W0_mask[15]
    DIRECTION INPUT ;
    USE SIGNAL ;
    SHAPE ABUTMENT ;
    PORT
      LAYER M4 ;
      RECT 81.904 198.012 82.000 198.108 ;
    END
  END W0_mask[15]
  PIN W0_mask[16]
    DIRECTION INPUT ;
    USE SIGNAL ;
    SHAPE ABUTMENT ;
    PORT
      LAYER M5 ;
      RECT 77.772 207.904 77.868 208.000 ;
    END
  END W0_mask[16]
  PIN W0_mask[17]
    DIRECTION INPUT ;
    USE SIGNAL ;
    SHAPE ABUTMENT ;
    PORT
      LAYER M5 ;
      RECT 77.772 0.000 77.868 0.096 ;
    END
  END W0_mask[17]
  PIN W0_mask[18]
    DIRECTION INPUT ;
    USE SIGNAL ;
    SHAPE ABUTMENT ;
    PORT
      LAYER M4 ;
      RECT 0.000 198.780 0.096 198.876 ;
    END
  END W0_mask[18]
  PIN W0_mask[19]
    DIRECTION INPUT ;
    USE SIGNAL ;
    SHAPE ABUTMENT ;
    PORT
      LAYER M4 ;
      RECT 81.904 198.780 82.000 198.876 ;
    END
  END W0_mask[19]
  PIN W0_mask[20]
    DIRECTION INPUT ;
    USE SIGNAL ;
    SHAPE ABUTMENT ;
    PORT
      LAYER M5 ;
      RECT 78.060 207.904 78.156 208.000 ;
    END
  END W0_mask[20]
  PIN W0_mask[21]
    DIRECTION INPUT ;
    USE SIGNAL ;
    SHAPE ABUTMENT ;
    PORT
      LAYER M5 ;
      RECT 78.060 0.000 78.156 0.096 ;
    END
  END W0_mask[21]
  PIN W0_mask[22]
    DIRECTION INPUT ;
    USE SIGNAL ;
    SHAPE ABUTMENT ;
    PORT
      LAYER M4 ;
      RECT 0.000 199.500 0.096 199.596 ;
    END
  END W0_mask[22]
  PIN W0_mask[23]
    DIRECTION INPUT ;
    USE SIGNAL ;
    SHAPE ABUTMENT ;
    PORT
      LAYER M4 ;
      RECT 81.904 199.500 82.000 199.596 ;
    END
  END W0_mask[23]
  PIN W0_mask[24]
    DIRECTION INPUT ;
    USE SIGNAL ;
    SHAPE ABUTMENT ;
    PORT
      LAYER M5 ;
      RECT 78.348 207.904 78.444 208.000 ;
    END
  END W0_mask[24]
  PIN W0_mask[25]
    DIRECTION INPUT ;
    USE SIGNAL ;
    SHAPE ABUTMENT ;
    PORT
      LAYER M5 ;
      RECT 78.348 0.000 78.444 0.096 ;
    END
  END W0_mask[25]
  PIN W0_mask[26]
    DIRECTION INPUT ;
    USE SIGNAL ;
    SHAPE ABUTMENT ;
    PORT
      LAYER M4 ;
      RECT 0.000 200.268 0.096 200.364 ;
    END
  END W0_mask[26]
  PIN W0_mask[27]
    DIRECTION INPUT ;
    USE SIGNAL ;
    SHAPE ABUTMENT ;
    PORT
      LAYER M4 ;
      RECT 81.904 200.268 82.000 200.364 ;
    END
  END W0_mask[27]
  PIN W0_mask[28]
    DIRECTION INPUT ;
    USE SIGNAL ;
    SHAPE ABUTMENT ;
    PORT
      LAYER M5 ;
      RECT 78.636 207.904 78.732 208.000 ;
    END
  END W0_mask[28]
  PIN W0_mask[29]
    DIRECTION INPUT ;
    USE SIGNAL ;
    SHAPE ABUTMENT ;
    PORT
      LAYER M5 ;
      RECT 78.636 0.000 78.732 0.096 ;
    END
  END W0_mask[29]
  PIN W0_mask[30]
    DIRECTION INPUT ;
    USE SIGNAL ;
    SHAPE ABUTMENT ;
    PORT
      LAYER M4 ;
      RECT 0.000 200.988 0.096 201.084 ;
    END
  END W0_mask[30]
  PIN W0_mask[31]
    DIRECTION INPUT ;
    USE SIGNAL ;
    SHAPE ABUTMENT ;
    PORT
      LAYER M4 ;
      RECT 81.904 200.988 82.000 201.084 ;
    END
  END W0_mask[31]
  PIN W0_mask[32]
    DIRECTION INPUT ;
    USE SIGNAL ;
    SHAPE ABUTMENT ;
    PORT
      LAYER M5 ;
      RECT 78.924 207.904 79.020 208.000 ;
    END
  END W0_mask[32]
  PIN W0_mask[33]
    DIRECTION INPUT ;
    USE SIGNAL ;
    SHAPE ABUTMENT ;
    PORT
      LAYER M5 ;
      RECT 78.924 0.000 79.020 0.096 ;
    END
  END W0_mask[33]
  PIN W0_mask[34]
    DIRECTION INPUT ;
    USE SIGNAL ;
    SHAPE ABUTMENT ;
    PORT
      LAYER M4 ;
      RECT 0.000 201.756 0.096 201.852 ;
    END
  END W0_mask[34]
  PIN W0_mask[35]
    DIRECTION INPUT ;
    USE SIGNAL ;
    SHAPE ABUTMENT ;
    PORT
      LAYER M4 ;
      RECT 81.904 201.756 82.000 201.852 ;
    END
  END W0_mask[35]
  PIN W0_mask[36]
    DIRECTION INPUT ;
    USE SIGNAL ;
    SHAPE ABUTMENT ;
    PORT
      LAYER M5 ;
      RECT 79.212 207.904 79.308 208.000 ;
    END
  END W0_mask[36]
  PIN W0_mask[37]
    DIRECTION INPUT ;
    USE SIGNAL ;
    SHAPE ABUTMENT ;
    PORT
      LAYER M5 ;
      RECT 79.212 0.000 79.308 0.096 ;
    END
  END W0_mask[37]
  PIN W0_mask[38]
    DIRECTION INPUT ;
    USE SIGNAL ;
    SHAPE ABUTMENT ;
    PORT
      LAYER M4 ;
      RECT 0.000 202.476 0.096 202.572 ;
    END
  END W0_mask[38]
  PIN W0_mask[39]
    DIRECTION INPUT ;
    USE SIGNAL ;
    SHAPE ABUTMENT ;
    PORT
      LAYER M4 ;
      RECT 81.904 202.476 82.000 202.572 ;
    END
  END W0_mask[39]
  PIN W0_mask[40]
    DIRECTION INPUT ;
    USE SIGNAL ;
    SHAPE ABUTMENT ;
    PORT
      LAYER M5 ;
      RECT 79.500 207.904 79.596 208.000 ;
    END
  END W0_mask[40]
  PIN W0_mask[41]
    DIRECTION INPUT ;
    USE SIGNAL ;
    SHAPE ABUTMENT ;
    PORT
      LAYER M5 ;
      RECT 79.500 0.000 79.596 0.096 ;
    END
  END W0_mask[41]
  PIN W0_mask[42]
    DIRECTION INPUT ;
    USE SIGNAL ;
    SHAPE ABUTMENT ;
    PORT
      LAYER M4 ;
      RECT 0.000 203.244 0.096 203.340 ;
    END
  END W0_mask[42]
  PIN W0_mask[43]
    DIRECTION INPUT ;
    USE SIGNAL ;
    SHAPE ABUTMENT ;
    PORT
      LAYER M4 ;
      RECT 81.904 203.244 82.000 203.340 ;
    END
  END W0_mask[43]
  PIN W0_mask[44]
    DIRECTION INPUT ;
    USE SIGNAL ;
    SHAPE ABUTMENT ;
    PORT
      LAYER M5 ;
      RECT 79.788 207.904 79.884 208.000 ;
    END
  END W0_mask[44]
  PIN W0_mask[45]
    DIRECTION INPUT ;
    USE SIGNAL ;
    SHAPE ABUTMENT ;
    PORT
      LAYER M5 ;
      RECT 79.788 0.000 79.884 0.096 ;
    END
  END W0_mask[45]
  PIN W0_mask[46]
    DIRECTION INPUT ;
    USE SIGNAL ;
    SHAPE ABUTMENT ;
    PORT
      LAYER M4 ;
      RECT 0.000 203.964 0.096 204.060 ;
    END
  END W0_mask[46]
  PIN W0_mask[47]
    DIRECTION INPUT ;
    USE SIGNAL ;
    SHAPE ABUTMENT ;
    PORT
      LAYER M4 ;
      RECT 81.904 203.964 82.000 204.060 ;
    END
  END W0_mask[47]
  PIN W0_mask[48]
    DIRECTION INPUT ;
    USE SIGNAL ;
    SHAPE ABUTMENT ;
    PORT
      LAYER M5 ;
      RECT 80.076 207.904 80.172 208.000 ;
    END
  END W0_mask[48]
  PIN W0_mask[49]
    DIRECTION INPUT ;
    USE SIGNAL ;
    SHAPE ABUTMENT ;
    PORT
      LAYER M5 ;
      RECT 80.076 0.000 80.172 0.096 ;
    END
  END W0_mask[49]
  PIN W0_mask[50]
    DIRECTION INPUT ;
    USE SIGNAL ;
    SHAPE ABUTMENT ;
    PORT
      LAYER M4 ;
      RECT 0.000 204.732 0.096 204.828 ;
    END
  END W0_mask[50]
  PIN W0_mask[51]
    DIRECTION INPUT ;
    USE SIGNAL ;
    SHAPE ABUTMENT ;
    PORT
      LAYER M4 ;
      RECT 81.904 204.732 82.000 204.828 ;
    END
  END W0_mask[51]
  PIN W0_mask[52]
    DIRECTION INPUT ;
    USE SIGNAL ;
    SHAPE ABUTMENT ;
    PORT
      LAYER M5 ;
      RECT 80.364 207.904 80.460 208.000 ;
    END
  END W0_mask[52]
  PIN W0_mask[53]
    DIRECTION INPUT ;
    USE SIGNAL ;
    SHAPE ABUTMENT ;
    PORT
      LAYER M5 ;
      RECT 80.364 0.000 80.460 0.096 ;
    END
  END W0_mask[53]
  PIN W0_mask[54]
    DIRECTION INPUT ;
    USE SIGNAL ;
    SHAPE ABUTMENT ;
    PORT
      LAYER M4 ;
      RECT 0.000 205.452 0.096 205.548 ;
    END
  END W0_mask[54]
  PIN W0_mask[55]
    DIRECTION INPUT ;
    USE SIGNAL ;
    SHAPE ABUTMENT ;
    PORT
      LAYER M4 ;
      RECT 81.904 205.452 82.000 205.548 ;
    END
  END W0_mask[55]
  PIN W0_mask[56]
    DIRECTION INPUT ;
    USE SIGNAL ;
    SHAPE ABUTMENT ;
    PORT
      LAYER M5 ;
      RECT 80.652 207.904 80.748 208.000 ;
    END
  END W0_mask[56]
  PIN W0_mask[57]
    DIRECTION INPUT ;
    USE SIGNAL ;
    SHAPE ABUTMENT ;
    PORT
      LAYER M5 ;
      RECT 80.652 0.000 80.748 0.096 ;
    END
  END W0_mask[57]
  PIN W0_mask[58]
    DIRECTION INPUT ;
    USE SIGNAL ;
    SHAPE ABUTMENT ;
    PORT
      LAYER M4 ;
      RECT 0.000 206.220 0.096 206.316 ;
    END
  END W0_mask[58]
  PIN W0_mask[59]
    DIRECTION INPUT ;
    USE SIGNAL ;
    SHAPE ABUTMENT ;
    PORT
      LAYER M4 ;
      RECT 81.904 206.220 82.000 206.316 ;
    END
  END W0_mask[59]
  PIN W0_mask[60]
    DIRECTION INPUT ;
    USE SIGNAL ;
    SHAPE ABUTMENT ;
    PORT
      LAYER M5 ;
      RECT 80.940 207.904 81.036 208.000 ;
    END
  END W0_mask[60]
  PIN W0_mask[61]
    DIRECTION INPUT ;
    USE SIGNAL ;
    SHAPE ABUTMENT ;
    PORT
      LAYER M5 ;
      RECT 80.940 0.000 81.036 0.096 ;
    END
  END W0_mask[61]
  PIN W0_mask[62]
    DIRECTION INPUT ;
    USE SIGNAL ;
    SHAPE ABUTMENT ;
    PORT
      LAYER M4 ;
      RECT 0.000 206.940 0.096 207.036 ;
    END
  END W0_mask[62]
  PIN W0_mask[63]
    DIRECTION INPUT ;
    USE SIGNAL ;
    SHAPE ABUTMENT ;
    PORT
      LAYER M4 ;
      RECT 81.904 206.940 82.000 207.036 ;
    END
  END W0_mask[63]
END mem_0_ext

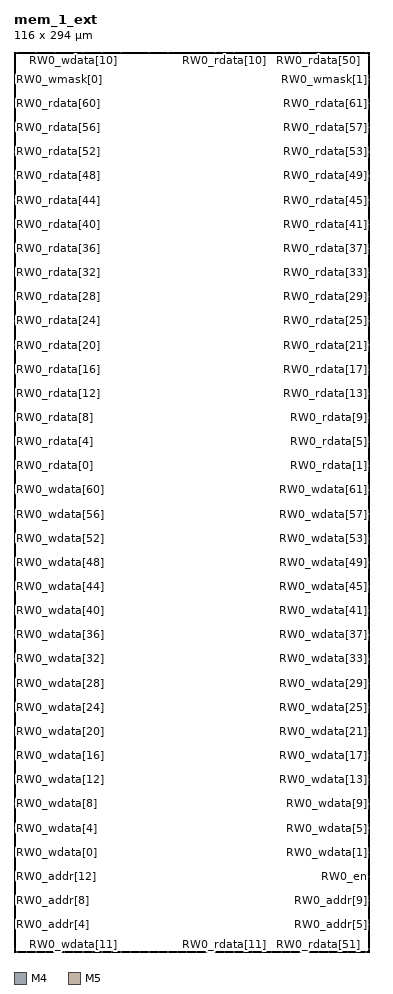
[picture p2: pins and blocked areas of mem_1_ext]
MACRO mem_1_ext
  FOREIGN mem_1_ext 0 0 ;
  CLASS BLOCK ;
  ORIGIN 0 0 ;
  SYMMETRY X Y R90 ;
  SIZE 116.000 BY 294.000 ;
  SITE asap7sc7p5t ;
  PIN RW0_addr[0]
    DIRECTION INPUT ;
    USE SIGNAL ;
    SHAPE ABUTMENT ;
    PORT
      LAYER M4 ;
      RECT 0.000 0.972 0.096 1.068 ;
    END
  END RW0_addr[0]
  PIN RW0_addr[1]
    DIRECTION INPUT ;
    USE SIGNAL ;
    SHAPE ABUTMENT ;
    PORT
      LAYER M4 ;
      RECT 115.904 0.972 116.000 1.068 ;
    END
  END RW0_addr[1]
  PIN RW0_addr[2]
    DIRECTION INPUT ;
    USE SIGNAL ;
    SHAPE ABUTMENT ;
    PORT
      LAYER M5 ;
      RECT 0.972 293.904 1.068 294.000 ;
    END
  END RW0_addr[2]
  PIN RW0_addr[3]
    DIRECTION INPUT ;
    USE SIGNAL ;
    SHAPE ABUTMENT ;
    PORT
      LAYER M5 ;
      RECT 0.972 0.000 1.068 0.096 ;
    END
  END RW0_addr[3]
  PIN RW0_addr[4]
    DIRECTION INPUT ;
    USE SIGNAL ;
    SHAPE ABUTMENT ;
    PORT
      LAYER M4 ;
      RECT 0.000 8.844 0.096 8.940 ;
    END
  END RW0_addr[4]
  PIN RW0_addr[5]
    DIRECTION INPUT ;
    USE SIGNAL ;
    SHAPE ABUTMENT ;
    PORT
      LAYER M4 ;
      RECT 115.904 8.844 116.000 8.940 ;
    END
  END RW0_addr[5]
  PIN RW0_addr[6]
    DIRECTION INPUT ;
    USE SIGNAL ;
    SHAPE ABUTMENT ;
    PORT
      LAYER M5 ;
      RECT 4.044 293.904 4.140 294.000 ;
    END
  END RW0_addr[6]
  PIN RW0_addr[7]
    DIRECTION INPUT ;
    USE SIGNAL ;
    SHAPE ABUTMENT ;
    PORT
      LAYER M5 ;
      RECT 4.044 0.000 4.140 0.096 ;
    END
  END RW0_addr[7]
  PIN RW0_addr[8]
    DIRECTION INPUT ;
    USE SIGNAL ;
    SHAPE ABUTMENT ;
    PORT
      LAYER M4 ;
      RECT 0.000 16.764 0.096 16.860 ;
    END
  END RW0_addr[8]
  PIN RW0_addr[9]
    DIRECTION INPUT ;
    USE SIGNAL ;
    SHAPE ABUTMENT ;
    PORT
      LAYER M4 ;
      RECT 115.904 16.764 116.000 16.860 ;
    END
  END RW0_addr[9]
  PIN RW0_addr[10]
    DIRECTION INPUT ;
    USE SIGNAL ;
    SHAPE ABUTMENT ;
    PORT
      LAYER M5 ;
      RECT 7.116 293.904 7.212 294.000 ;
    END
  END RW0_addr[10]
  PIN RW0_addr[11]
    DIRECTION INPUT ;
    USE SIGNAL ;
    SHAPE ABUTMENT ;
    PORT
      LAYER M5 ;
      RECT 7.116 0.000 7.212 0.096 ;
    END
  END RW0_addr[11]
  PIN RW0_addr[12]
    DIRECTION INPUT ;
    USE SIGNAL ;
    SHAPE ABUTMENT ;
    PORT
      LAYER M4 ;
      RECT 0.000 24.636 0.096 24.732 ;
    END
  END RW0_addr[12]
  PIN RW0_en
    DIRECTION INPUT ;
    USE SIGNAL ;
    SHAPE ABUTMENT ;
    PORT
      LAYER M4 ;
      RECT 115.904 24.636 116.000 24.732 ;
    END
  END RW0_en
  PIN RW0_clk
    DIRECTION INPUT ;
    USE SIGNAL ;
    SHAPE ABUTMENT ;
    PORT
      LAYER M5 ;
      RECT 10.188 293.904 10.284 294.000 ;
    END
  END RW0_clk
  PIN RW0_wmode
    DIRECTION INPUT ;
    USE SIGNAL ;
    SHAPE ABUTMENT ;
    PORT
      LAYER M5 ;
      RECT 10.188 0.000 10.284 0.096 ;
    END
  END RW0_wmode
  PIN RW0_wdata[0]
    DIRECTION INPUT ;
    USE SIGNAL ;
    SHAPE ABUTMENT ;
    PORT
      LAYER M4 ;
      RECT 0.000 32.556 0.096 32.652 ;
    END
  END RW0_wdata[0]
  PIN RW0_wdata[1]
    DIRECTION INPUT ;
    USE SIGNAL ;
    SHAPE ABUTMENT ;
    PORT
      LAYER M4 ;
      RECT 115.904 32.556 116.000 32.652 ;
    END
  END RW0_wdata[1]
  PIN RW0_wdata[2]
    DIRECTION INPUT ;
    USE SIGNAL ;
    SHAPE ABUTMENT ;
    PORT
      LAYER M5 ;
      RECT 13.308 293.904 13.404 294.000 ;
    END
  END RW0_wdata[2]
  PIN RW0_wdata[3]
    DIRECTION INPUT ;
    USE SIGNAL ;
    SHAPE ABUTMENT ;
    PORT
      LAYER M5 ;
      RECT 13.308 0.000 13.404 0.096 ;
    END
  END RW0_wdata[3]
  PIN RW0_wdata[4]
    DIRECTION INPUT ;
    USE SIGNAL ;
    SHAPE ABUTMENT ;
    PORT
      LAYER M4 ;
      RECT 0.000 40.428 0.096 40.524 ;
    END
  END RW0_wdata[4]
  PIN RW0_wdata[5]
    DIRECTION INPUT ;
    USE SIGNAL ;
    SHAPE ABUTMENT ;
    PORT
      LAYER M4 ;
      RECT 115.904 40.428 116.000 40.524 ;
    END
  END RW0_wdata[5]
  PIN RW0_wdata[6]
    DIRECTION INPUT ;
    USE SIGNAL ;
    SHAPE ABUTMENT ;
    PORT
      LAYER M5 ;
      RECT 16.380 293.904 16.476 294.000 ;
    END
  END RW0_wdata[6]
  PIN RW0_wdata[7]
    DIRECTION INPUT ;
    USE SIGNAL ;
    SHAPE ABUTMENT ;
    PORT
      LAYER M5 ;
      RECT 16.380 0.000 16.476 0.096 ;
    END
  END RW0_wdata[7]
  PIN RW0_wdata[8]
    DIRECTION INPUT ;
    USE SIGNAL ;
    SHAPE ABUTMENT ;
    PORT
      LAYER M4 ;
      RECT 0.000 48.300 0.096 48.396 ;
    END
  END RW0_wdata[8]
  PIN RW0_wdata[9]
    DIRECTION INPUT ;
    USE SIGNAL ;
    SHAPE ABUTMENT ;
    PORT
      LAYER M4 ;
      RECT 115.904 48.300 116.000 48.396 ;
    END
  END RW0_wdata[9]
  PIN RW0_wdata[10]
    DIRECTION INPUT ;
    USE SIGNAL ;
    SHAPE ABUTMENT ;
    PORT
      LAYER M5 ;
      RECT 19.452 293.904 19.548 294.000 ;
    END
  END RW0_wdata[10]
  PIN RW0_wdata[11]
    DIRECTION INPUT ;
    USE SIGNAL ;
    SHAPE ABUTMENT ;
    PORT
      LAYER M5 ;
      RECT 19.452 0.000 19.548 0.096 ;
    END
  END RW0_wdata[11]
  PIN RW0_wdata[12]
    DIRECTION INPUT ;
    USE SIGNAL ;
    SHAPE ABUTMENT ;
    PORT
      LAYER M4 ;
      RECT 0.000 56.220 0.096 56.316 ;
    END
  END RW0_wdata[12]
  PIN RW0_wdata[13]
    DIRECTION INPUT ;
    USE SIGNAL ;
    SHAPE ABUTMENT ;
    PORT
      LAYER M4 ;
      RECT 115.904 56.220 116.000 56.316 ;
    END
  END RW0_wdata[13]
  PIN RW0_wdata[14]
    DIRECTION INPUT ;
    USE SIGNAL ;
    SHAPE ABUTMENT ;
    PORT
      LAYER M5 ;
      RECT 22.524 293.904 22.620 294.000 ;
    END
  END RW0_wdata[14]
  PIN RW0_wdata[15]
    DIRECTION INPUT ;
    USE SIGNAL ;
    SHAPE ABUTMENT ;
    PORT
      LAYER M5 ;
      RECT 22.524 0.000 22.620 0.096 ;
    END
  END RW0_wdata[15]
  PIN RW0_wdata[16]
    DIRECTION INPUT ;
    USE SIGNAL ;
    SHAPE ABUTMENT ;
    PORT
      LAYER M4 ;
      RECT 0.000 64.092 0.096 64.188 ;
    END
  END RW0_wdata[16]
  PIN RW0_wdata[17]
    DIRECTION INPUT ;
    USE SIGNAL ;
    SHAPE ABUTMENT ;
    PORT
      LAYER M4 ;
      RECT 115.904 64.092 116.000 64.188 ;
    END
  END RW0_wdata[17]
  PIN RW0_wdata[18]
    DIRECTION INPUT ;
    USE SIGNAL ;
    SHAPE ABUTMENT ;
    PORT
      LAYER M5 ;
      RECT 25.596 293.904 25.692 294.000 ;
    END
  END RW0_wdata[18]
  PIN RW0_wdata[19]
    DIRECTION INPUT ;
    USE SIGNAL ;
    SHAPE ABUTMENT ;
    PORT
      LAYER M5 ;
      RECT 25.596 0.000 25.692 0.096 ;
    END
  END RW0_wdata[19]
  PIN RW0_wdata[20]
    DIRECTION INPUT ;
    USE SIGNAL ;
    SHAPE ABUTMENT ;
    PORT
      LAYER M4 ;
      RECT 0.000 71.964 0.096 72.060 ;
    END
  END RW0_wdata[20]
  PIN RW0_wdata[21]
    DIRECTION INPUT ;
    USE SIGNAL ;
    SHAPE ABUTMENT ;
    PORT
      LAYER M4 ;
      RECT 115.904 71.964 116.000 72.060 ;
    END
  END RW0_wdata[21]
  PIN RW0_wdata[22]
    DIRECTION INPUT ;
    USE SIGNAL ;
    SHAPE ABUTMENT ;
    PORT
      LAYER M5 ;
      RECT 28.668 293.904 28.764 294.000 ;
    END
  END RW0_wdata[22]
  PIN RW0_wdata[23]
    DIRECTION INPUT ;
    USE SIGNAL ;
    SHAPE ABUTMENT ;
    PORT
      LAYER M5 ;
      RECT 28.668 0.000 28.764 0.096 ;
    END
  END RW0_wdata[23]
  PIN RW0_wdata[24]
    DIRECTION INPUT ;
    USE SIGNAL ;
    SHAPE ABUTMENT ;
    PORT
      LAYER M4 ;
      RECT 0.000 79.884 0.096 79.980 ;
    END
  END RW0_wdata[24]
  PIN RW0_wdata[25]
    DIRECTION INPUT ;
    USE SIGNAL ;
    SHAPE ABUTMENT ;
    PORT
      LAYER M4 ;
      RECT 115.904 79.884 116.000 79.980 ;
    END
  END RW0_wdata[25]
  PIN RW0_wdata[26]
    DIRECTION INPUT ;
    USE SIGNAL ;
    SHAPE ABUTMENT ;
    PORT
      LAYER M5 ;
      RECT 31.788 293.904 31.884 294.000 ;
    END
  END RW0_wdata[26]
  PIN RW0_wdata[27]
    DIRECTION INPUT ;
    USE SIGNAL ;
    SHAPE ABUTMENT ;
    PORT
      LAYER M5 ;
      RECT 31.788 0.000 31.884 0.096 ;
    END
  END RW0_wdata[27]
  PIN RW0_wdata[28]
    DIRECTION INPUT ;
    USE SIGNAL ;
    SHAPE ABUTMENT ;
    PORT
      LAYER M4 ;
      RECT 0.000 87.756 0.096 87.852 ;
    END
  END RW0_wdata[28]
  PIN RW0_wdata[29]
    DIRECTION INPUT ;
    USE SIGNAL ;
    SHAPE ABUTMENT ;
    PORT
      LAYER M4 ;
      RECT 115.904 87.756 116.000 87.852 ;
    END
  END RW0_wdata[29]
  PIN RW0_wdata[30]
    DIRECTION INPUT ;
    USE SIGNAL ;
    SHAPE ABUTMENT ;
    PORT
      LAYER M5 ;
      RECT 34.860 293.904 34.956 294.000 ;
    END
  END RW0_wdata[30]
  PIN RW0_wdata[31]
    DIRECTION INPUT ;
    USE SIGNAL ;
    SHAPE ABUTMENT ;
    PORT
      LAYER M5 ;
      RECT 34.860 0.000 34.956 0.096 ;
    END
  END RW0_wdata[31]
  PIN RW0_wdata[32]
    DIRECTION INPUT ;
    USE SIGNAL ;
    SHAPE ABUTMENT ;
    PORT
      LAYER M4 ;
      RECT 0.000 95.676 0.096 95.772 ;
    END
  END RW0_wdata[32]
  PIN RW0_wdata[33]
    DIRECTION INPUT ;
    USE SIGNAL ;
    SHAPE ABUTMENT ;
    PORT
      LAYER M4 ;
      RECT 115.904 95.676 116.000 95.772 ;
    END
  END RW0_wdata[33]
  PIN RW0_wdata[34]
    DIRECTION INPUT ;
    USE SIGNAL ;
    SHAPE ABUTMENT ;
    PORT
      LAYER M5 ;
      RECT 37.932 293.904 38.028 294.000 ;
    END
  END RW0_wdata[34]
  PIN RW0_wdata[35]
    DIRECTION INPUT ;
    USE SIGNAL ;
    SHAPE ABUTMENT ;
    PORT
      LAYER M5 ;
      RECT 37.932 0.000 38.028 0.096 ;
    END
  END RW0_wdata[35]
  PIN RW0_wdata[36]
    DIRECTION INPUT ;
    USE SIGNAL ;
    SHAPE ABUTMENT ;
    PORT
      LAYER M4 ;
      RECT 0.000 103.548 0.096 103.644 ;
    END
  END RW0_wdata[36]
  PIN RW0_wdata[37]
    DIRECTION INPUT ;
    USE SIGNAL ;
    SHAPE ABUTMENT ;
    PORT
      LAYER M4 ;
      RECT 115.904 103.548 116.000 103.644 ;
    END
  END RW0_wdata[37]
  PIN RW0_wdata[38]
    DIRECTION INPUT ;
    USE SIGNAL ;
    SHAPE ABUTMENT ;
    PORT
      LAYER M5 ;
      RECT 41.004 293.904 41.100 294.000 ;
    END
  END RW0_wdata[38]
  PIN RW0_wdata[39]
    DIRECTION INPUT ;
    USE SIGNAL ;
    SHAPE ABUTMENT ;
    PORT
      LAYER M5 ;
      RECT 41.004 0.000 41.100 0.096 ;
    END
  END RW0_wdata[39]
  PIN RW0_wdata[40]
    DIRECTION INPUT ;
    USE SIGNAL ;
    SHAPE ABUTMENT ;
    PORT
      LAYER M4 ;
      RECT 0.000 111.420 0.096 111.516 ;
    END
  END RW0_wdata[40]
  PIN RW0_wdata[41]
    DIRECTION INPUT ;
    USE SIGNAL ;
    SHAPE ABUTMENT ;
    PORT
      LAYER M4 ;
      RECT 115.904 111.420 116.000 111.516 ;
    END
  END RW0_wdata[41]
  PIN RW0_wdata[42]
    DIRECTION INPUT ;
    USE SIGNAL ;
    SHAPE ABUTMENT ;
    PORT
      LAYER M5 ;
      RECT 44.076 293.904 44.172 294.000 ;
    END
  END RW0_wdata[42]
  PIN RW0_wdata[43]
    DIRECTION INPUT ;
    USE SIGNAL ;
    SHAPE ABUTMENT ;
    PORT
      LAYER M5 ;
      RECT 44.076 0.000 44.172 0.096 ;
    END
  END RW0_wdata[43]
  PIN RW0_wdata[44]
    DIRECTION INPUT ;
    USE SIGNAL ;
    SHAPE ABUTMENT ;
    PORT
      LAYER M4 ;
      RECT 0.000 119.340 0.096 119.436 ;
    END
  END RW0_wdata[44]
  PIN RW0_wdata[45]
    DIRECTION INPUT ;
    USE SIGNAL ;
    SHAPE ABUTMENT ;
    PORT
      LAYER M4 ;
      RECT 115.904 119.340 116.000 119.436 ;
    END
  END RW0_wdata[45]
  PIN RW0_wdata[46]
    DIRECTION INPUT ;
    USE SIGNAL ;
    SHAPE ABUTMENT ;
    PORT
      LAYER M5 ;
      RECT 47.148 293.904 47.244 294.000 ;
    END
  END RW0_wdata[46]
  PIN RW0_wdata[47]
    DIRECTION INPUT ;
    USE SIGNAL ;
    SHAPE ABUTMENT ;
    PORT
      LAYER M5 ;
      RECT 47.148 0.000 47.244 0.096 ;
    END
  END RW0_wdata[47]
  PIN RW0_wdata[48]
    DIRECTION INPUT ;
    USE SIGNAL ;
    SHAPE ABUTMENT ;
    PORT
      LAYER M4 ;
      RECT 0.000 127.212 0.096 127.308 ;
    END
  END RW0_wdata[48]
  PIN RW0_wdata[49]
    DIRECTION INPUT ;
    USE SIGNAL ;
    SHAPE ABUTMENT ;
    PORT
      LAYER M4 ;
      RECT 115.904 127.212 116.000 127.308 ;
    END
  END RW0_wdata[49]
  PIN RW0_wdata[50]
    DIRECTION INPUT ;
    USE SIGNAL ;
    SHAPE ABUTMENT ;
    PORT
      LAYER M5 ;
      RECT 50.268 293.904 50.364 294.000 ;
    END
  END RW0_wdata[50]
  PIN RW0_wdata[51]
    DIRECTION INPUT ;
    USE SIGNAL ;
    SHAPE ABUTMENT ;
    PORT
      LAYER M5 ;
      RECT 50.268 0.000 50.364 0.096 ;
    END
  END RW0_wdata[51]
  PIN RW0_wdata[52]
    DIRECTION INPUT ;
    USE SIGNAL ;
    SHAPE ABUTMENT ;
    PORT
      LAYER M4 ;
      RECT 0.000 135.084 0.096 135.180 ;
    END
  END RW0_wdata[52]
  PIN RW0_wdata[53]
    DIRECTION INPUT ;
    USE SIGNAL ;
    SHAPE ABUTMENT ;
    PORT
      LAYER M4 ;
      RECT 115.904 135.084 116.000 135.180 ;
    END
  END RW0_wdata[53]
  PIN RW0_wdata[54]
    DIRECTION INPUT ;
    USE SIGNAL ;
    SHAPE ABUTMENT ;
    PORT
      LAYER M5 ;
      RECT 53.340 293.904 53.436 294.000 ;
    END
  END RW0_wdata[54]
  PIN RW0_wdata[55]
    DIRECTION INPUT ;
    USE SIGNAL ;
    SHAPE ABUTMENT ;
    PORT
      LAYER M5 ;
      RECT 53.340 0.000 53.436 0.096 ;
    END
  END RW0_wdata[55]
  PIN RW0_wdata[56]
    DIRECTION INPUT ;
    USE SIGNAL ;
    SHAPE ABUTMENT ;
    PORT
      LAYER M4 ;
      RECT 0.000 143.004 0.096 143.100 ;
    END
  END RW0_wdata[56]
  PIN RW0_wdata[57]
    DIRECTION INPUT ;
    USE SIGNAL ;
    SHAPE ABUTMENT ;
    PORT
      LAYER M4 ;
      RECT 115.904 143.004 116.000 143.100 ;
    END
  END RW0_wdata[57]
  PIN RW0_wdata[58]
    DIRECTION INPUT ;
    USE SIGNAL ;
    SHAPE ABUTMENT ;
    PORT
      LAYER M5 ;
      RECT 56.412 293.904 56.508 294.000 ;
    END
  END RW0_wdata[58]
  PIN RW0_wdata[59]
    DIRECTION INPUT ;
    USE SIGNAL ;
    SHAPE ABUTMENT ;
    PORT
      LAYER M5 ;
      RECT 56.412 0.000 56.508 0.096 ;
    END
  END RW0_wdata[59]
  PIN RW0_wdata[60]
    DIRECTION INPUT ;
    USE SIGNAL ;
    SHAPE ABUTMENT ;
    PORT
      LAYER M4 ;
      RECT 0.000 150.876 0.096 150.972 ;
    END
  END RW0_wdata[60]
  PIN RW0_wdata[61]
    DIRECTION INPUT ;
    USE SIGNAL ;
    SHAPE ABUTMENT ;
    PORT
      LAYER M4 ;
      RECT 115.904 150.876 116.000 150.972 ;
    END
  END RW0_wdata[61]
  PIN RW0_wdata[62]
    DIRECTION INPUT ;
    USE SIGNAL ;
    SHAPE ABUTMENT ;
    PORT
      LAYER M5 ;
      RECT 59.484 293.904 59.580 294.000 ;
    END
  END RW0_wdata[62]
  PIN RW0_wdata[63]
    DIRECTION INPUT ;
    USE SIGNAL ;
    SHAPE ABUTMENT ;
    PORT
      LAYER M5 ;
      RECT 59.484 0.000 59.580 0.096 ;
    END
  END RW0_wdata[63]
  PIN RW0_rdata[0]
    DIRECTION OUTPUT ;
    USE SIGNAL ;
    SHAPE ABUTMENT ;
    PORT
      LAYER M4 ;
      RECT 0.000 158.796 0.096 158.892 ;
    END
  END RW0_rdata[0]
  PIN RW0_rdata[1]
    DIRECTION OUTPUT ;
    USE SIGNAL ;
    SHAPE ABUTMENT ;
    PORT
      LAYER M4 ;
      RECT 115.904 158.796 116.000 158.892 ;
    END
  END RW0_rdata[1]
  PIN RW0_rdata[2]
    DIRECTION OUTPUT ;
    USE SIGNAL ;
    SHAPE ABUTMENT ;
    PORT
      LAYER M5 ;
      RECT 62.556 293.904 62.652 294.000 ;
    END
  END RW0_rdata[2]
  PIN RW0_rdata[3]
    DIRECTION OUTPUT ;
    USE SIGNAL ;
    SHAPE ABUTMENT ;
    PORT
      LAYER M5 ;
      RECT 62.556 0.000 62.652 0.096 ;
    END
  END RW0_rdata[3]
  PIN RW0_rdata[4]
    DIRECTION OUTPUT ;
    USE SIGNAL ;
    SHAPE ABUTMENT ;
    PORT
      LAYER M4 ;
      RECT 0.000 166.668 0.096 166.764 ;
    END
  END RW0_rdata[4]
  PIN RW0_rdata[5]
    DIRECTION OUTPUT ;
    USE SIGNAL ;
    SHAPE ABUTMENT ;
    PORT
      LAYER M4 ;
      RECT 115.904 166.668 116.000 166.764 ;
    END
  END RW0_rdata[5]
  PIN RW0_rdata[6]
    DIRECTION OUTPUT ;
    USE SIGNAL ;
    SHAPE ABUTMENT ;
    PORT
      LAYER M5 ;
      RECT 65.628 293.904 65.724 294.000 ;
    END
  END RW0_rdata[6]
  PIN RW0_rdata[7]
    DIRECTION OUTPUT ;
    USE SIGNAL ;
    SHAPE ABUTMENT ;
    PORT
      LAYER M5 ;
      RECT 65.628 0.000 65.724 0.096 ;
    END
  END RW0_rdata[7]
  PIN RW0_rdata[8]
    DIRECTION OUTPUT ;
    USE SIGNAL ;
    SHAPE ABUTMENT ;
    PORT
      LAYER M4 ;
      RECT 0.000 174.540 0.096 174.636 ;
    END
  END RW0_rdata[8]
  PIN RW0_rdata[9]
    DIRECTION OUTPUT ;
    USE SIGNAL ;
    SHAPE ABUTMENT ;
    PORT
      LAYER M4 ;
      RECT 115.904 174.540 116.000 174.636 ;
    END
  END RW0_rdata[9]
  PIN RW0_rdata[10]
    DIRECTION OUTPUT ;
    USE SIGNAL ;
    SHAPE ABUTMENT ;
    PORT
      LAYER M5 ;
      RECT 68.748 293.904 68.844 294.000 ;
    END
  END RW0_rdata[10]
  PIN RW0_rdata[11]
    DIRECTION OUTPUT ;
    USE SIGNAL ;
    SHAPE ABUTMENT ;
    PORT
      LAYER M5 ;
      RECT 68.748 0.000 68.844 0.096 ;
    END
  END RW0_rdata[11]
  PIN RW0_rdata[12]
    DIRECTION OUTPUT ;
    USE SIGNAL ;
    SHAPE ABUTMENT ;
    PORT
      LAYER M4 ;
      RECT 0.000 182.460 0.096 182.556 ;
    END
  END RW0_rdata[12]
  PIN RW0_rdata[13]
    DIRECTION OUTPUT ;
    USE SIGNAL ;
    SHAPE ABUTMENT ;
    PORT
      LAYER M4 ;
      RECT 115.904 182.460 116.000 182.556 ;
    END
  END RW0_rdata[13]
  PIN RW0_rdata[14]
    DIRECTION OUTPUT ;
    USE SIGNAL ;
    SHAPE ABUTMENT ;
    PORT
      LAYER M5 ;
      RECT 71.820 293.904 71.916 294.000 ;
    END
  END RW0_rdata[14]
  PIN RW0_rdata[15]
    DIRECTION OUTPUT ;
    USE SIGNAL ;
    SHAPE ABUTMENT ;
    PORT
      LAYER M5 ;
      RECT 71.820 0.000 71.916 0.096 ;
    END
  END RW0_rdata[15]
  PIN RW0_rdata[16]
    DIRECTION OUTPUT ;
    USE SIGNAL ;
    SHAPE ABUTMENT ;
    PORT
      LAYER M4 ;
      RECT 0.000 190.332 0.096 190.428 ;
    END
  END RW0_rdata[16]
  PIN RW0_rdata[17]
    DIRECTION OUTPUT ;
    USE SIGNAL ;
    SHAPE ABUTMENT ;
    PORT
      LAYER M4 ;
      RECT 115.904 190.332 116.000 190.428 ;
    END
  END RW0_rdata[17]
  PIN RW0_rdata[18]
    DIRECTION OUTPUT ;
    USE SIGNAL ;
    SHAPE ABUTMENT ;
    PORT
      LAYER M5 ;
      RECT 74.892 293.904 74.988 294.000 ;
    END
  END RW0_rdata[18]
  PIN RW0_rdata[19]
    DIRECTION OUTPUT ;
    USE SIGNAL ;
    SHAPE ABUTMENT ;
    PORT
      LAYER M5 ;
      RECT 74.892 0.000 74.988 0.096 ;
    END
  END RW0_rdata[19]
  PIN RW0_rdata[20]
    DIRECTION OUTPUT ;
    USE SIGNAL ;
    SHAPE ABUTMENT ;
    PORT
      LAYER M4 ;
      RECT 0.000 198.204 0.096 198.300 ;
    END
  END RW0_rdata[20]
  PIN RW0_rdata[21]
    DIRECTION OUTPUT ;
    USE SIGNAL ;
    SHAPE ABUTMENT ;
    PORT
      LAYER M4 ;
      RECT 115.904 198.204 116.000 198.300 ;
    END
  END RW0_rdata[21]
  PIN RW0_rdata[22]
    DIRECTION OUTPUT ;
    USE SIGNAL ;
    SHAPE ABUTMENT ;
    PORT
      LAYER M5 ;
      RECT 77.964 293.904 78.060 294.000 ;
    END
  END RW0_rdata[22]
  PIN RW0_rdata[23]
    DIRECTION OUTPUT ;
    USE SIGNAL ;
    SHAPE ABUTMENT ;
    PORT
      LAYER M5 ;
      RECT 77.964 0.000 78.060 0.096 ;
    END
  END RW0_rdata[23]
  PIN RW0_rdata[24]
    DIRECTION OUTPUT ;
    USE SIGNAL ;
    SHAPE ABUTMENT ;
    PORT
      LAYER M4 ;
      RECT 0.000 206.124 0.096 206.220 ;
    END
  END RW0_rdata[24]
  PIN RW0_rdata[25]
    DIRECTION OUTPUT ;
    USE SIGNAL ;
    SHAPE ABUTMENT ;
    PORT
      LAYER M4 ;
      RECT 115.904 206.124 116.000 206.220 ;
    END
  END RW0_rdata[25]
  PIN RW0_rdata[26]
    DIRECTION OUTPUT ;
    USE SIGNAL ;
    SHAPE ABUTMENT ;
    PORT
      LAYER M5 ;
      RECT 81.036 293.904 81.132 294.000 ;
    END
  END RW0_rdata[26]
  PIN RW0_rdata[27]
    DIRECTION OUTPUT ;
    USE SIGNAL ;
    SHAPE ABUTMENT ;
    PORT
      LAYER M5 ;
      RECT 81.036 0.000 81.132 0.096 ;
    END
  END RW0_rdata[27]
  PIN RW0_rdata[28]
    DIRECTION OUTPUT ;
    USE SIGNAL ;
    SHAPE ABUTMENT ;
    PORT
      LAYER M4 ;
      RECT 0.000 213.996 0.096 214.092 ;
    END
  END RW0_rdata[28]
  PIN RW0_rdata[29]
    DIRECTION OUTPUT ;
    USE SIGNAL ;
    SHAPE ABUTMENT ;
    PORT
      LAYER M4 ;
      RECT 115.904 213.996 116.000 214.092 ;
    END
  END RW0_rdata[29]
  PIN RW0_rdata[30]
    DIRECTION OUTPUT ;
    USE SIGNAL ;
    SHAPE ABUTMENT ;
    PORT
      LAYER M5 ;
      RECT 84.108 293.904 84.204 294.000 ;
    END
  END RW0_rdata[30]
  PIN RW0_rdata[31]
    DIRECTION OUTPUT ;
    USE SIGNAL ;
    SHAPE ABUTMENT ;
    PORT
      LAYER M5 ;
      RECT 84.108 0.000 84.204 0.096 ;
    END
  END RW0_rdata[31]
  PIN RW0_rdata[32]
    DIRECTION OUTPUT ;
    USE SIGNAL ;
    SHAPE ABUTMENT ;
    PORT
      LAYER M4 ;
      RECT 0.000 221.916 0.096 222.012 ;
    END
  END RW0_rdata[32]
  PIN RW0_rdata[33]
    DIRECTION OUTPUT ;
    USE SIGNAL ;
    SHAPE ABUTMENT ;
    PORT
      LAYER M4 ;
      RECT 115.904 221.916 116.000 222.012 ;
    END
  END RW0_rdata[33]
  PIN RW0_rdata[34]
    DIRECTION OUTPUT ;
    USE SIGNAL ;
    SHAPE ABUTMENT ;
    PORT
      LAYER M5 ;
      RECT 87.228 293.904 87.324 294.000 ;
    END
  END RW0_rdata[34]
  PIN RW0_rdata[35]
    DIRECTION OUTPUT ;
    USE SIGNAL ;
    SHAPE ABUTMENT ;
    PORT
      LAYER M5 ;
      RECT 87.228 0.000 87.324 0.096 ;
    END
  END RW0_rdata[35]
  PIN RW0_rdata[36]
    DIRECTION OUTPUT ;
    USE SIGNAL ;
    SHAPE ABUTMENT ;
    PORT
      LAYER M4 ;
      RECT 0.000 229.788 0.096 229.884 ;
    END
  END RW0_rdata[36]
  PIN RW0_rdata[37]
    DIRECTION OUTPUT ;
    USE SIGNAL ;
    SHAPE ABUTMENT ;
    PORT
      LAYER M4 ;
      RECT 115.904 229.788 116.000 229.884 ;
    END
  END RW0_rdata[37]
  PIN RW0_rdata[38]
    DIRECTION OUTPUT ;
    USE SIGNAL ;
    SHAPE ABUTMENT ;
    PORT
      LAYER M5 ;
      RECT 90.300 293.904 90.396 294.000 ;
    END
  END RW0_rdata[38]
  PIN RW0_rdata[39]
    DIRECTION OUTPUT ;
    USE SIGNAL ;
    SHAPE ABUTMENT ;
    PORT
      LAYER M5 ;
      RECT 90.300 0.000 90.396 0.096 ;
    END
  END RW0_rdata[39]
  PIN RW0_rdata[40]
    DIRECTION OUTPUT ;
    USE SIGNAL ;
    SHAPE ABUTMENT ;
    PORT
      LAYER M4 ;
      RECT 0.000 237.660 0.096 237.756 ;
    END
  END RW0_rdata[40]
  PIN RW0_rdata[41]
    DIRECTION OUTPUT ;
    USE SIGNAL ;
    SHAPE ABUTMENT ;
    PORT
      LAYER M4 ;
      RECT 115.904 237.660 116.000 237.756 ;
    END
  END RW0_rdata[41]
  PIN RW0_rdata[42]
    DIRECTION OUTPUT ;
    USE SIGNAL ;
    SHAPE ABUTMENT ;
    PORT
      LAYER M5 ;
      RECT 93.372 293.904 93.468 294.000 ;
    END
  END RW0_rdata[42]
  PIN RW0_rdata[43]
    DIRECTION OUTPUT ;
    USE SIGNAL ;
    SHAPE ABUTMENT ;
    PORT
      LAYER M5 ;
      RECT 93.372 0.000 93.468 0.096 ;
    END
  END RW0_rdata[43]
  PIN RW0_rdata[44]
    DIRECTION OUTPUT ;
    USE SIGNAL ;
    SHAPE ABUTMENT ;
    PORT
      LAYER M4 ;
      RECT 0.000 245.580 0.096 245.676 ;
    END
  END RW0_rdata[44]
  PIN RW0_rdata[45]
    DIRECTION OUTPUT ;
    USE SIGNAL ;
    SHAPE ABUTMENT ;
    PORT
      LAYER M4 ;
      RECT 115.904 245.580 116.000 245.676 ;
    END
  END RW0_rdata[45]
  PIN RW0_rdata[46]
    DIRECTION OUTPUT ;
    USE SIGNAL ;
    SHAPE ABUTMENT ;
    PORT
      LAYER M5 ;
      RECT 96.444 293.904 96.540 294.000 ;
    END
  END RW0_rdata[46]
  PIN RW0_rdata[47]
    DIRECTION OUTPUT ;
    USE SIGNAL ;
    SHAPE ABUTMENT ;
    PORT
      LAYER M5 ;
      RECT 96.444 0.000 96.540 0.096 ;
    END
  END RW0_rdata[47]
  PIN RW0_rdata[48]
    DIRECTION OUTPUT ;
    USE SIGNAL ;
    SHAPE ABUTMENT ;
    PORT
      LAYER M4 ;
      RECT 0.000 253.452 0.096 253.548 ;
    END
  END RW0_rdata[48]
  PIN RW0_rdata[49]
    DIRECTION OUTPUT ;
    USE SIGNAL ;
    SHAPE ABUTMENT ;
    PORT
      LAYER M4 ;
      RECT 115.904 253.452 116.000 253.548 ;
    END
  END RW0_rdata[49]
  PIN RW0_rdata[50]
    DIRECTION OUTPUT ;
    USE SIGNAL ;
    SHAPE ABUTMENT ;
    PORT
      LAYER M5 ;
      RECT 99.516 293.904 99.612 294.000 ;
    END
  END RW0_rdata[50]
  PIN RW0_rdata[51]
    DIRECTION OUTPUT ;
    USE SIGNAL ;
    SHAPE ABUTMENT ;
    PORT
      LAYER M5 ;
      RECT 99.516 0.000 99.612 0.096 ;
    END
  END RW0_rdata[51]
  PIN RW0_rdata[52]
    DIRECTION OUTPUT ;
    USE SIGNAL ;
    SHAPE ABUTMENT ;
    PORT
      LAYER M4 ;
      RECT 0.000 261.324 0.096 261.420 ;
    END
  END RW0_rdata[52]
  PIN RW0_rdata[53]
    DIRECTION OUTPUT ;
    USE SIGNAL ;
    SHAPE ABUTMENT ;
    PORT
      LAYER M4 ;
      RECT 115.904 261.324 116.000 261.420 ;
    END
  END RW0_rdata[53]
  PIN RW0_rdata[54]
    DIRECTION OUTPUT ;
    USE SIGNAL ;
    SHAPE ABUTMENT ;
    PORT
      LAYER M5 ;
      RECT 102.588 293.904 102.684 294.000 ;
    END
  END RW0_rdata[54]
  PIN RW0_rdata[55]
    DIRECTION OUTPUT ;
    USE SIGNAL ;
    SHAPE ABUTMENT ;
    PORT
      LAYER M5 ;
      RECT 102.588 0.000 102.684 0.096 ;
    END
  END RW0_rdata[55]
  PIN RW0_rdata[56]
    DIRECTION OUTPUT ;
    USE SIGNAL ;
    SHAPE ABUTMENT ;
    PORT
      LAYER M4 ;
      RECT 0.000 269.244 0.096 269.340 ;
    END
  END RW0_rdata[56]
  PIN RW0_rdata[57]
    DIRECTION OUTPUT ;
    USE SIGNAL ;
    SHAPE ABUTMENT ;
    PORT
      LAYER M4 ;
      RECT 115.904 269.244 116.000 269.340 ;
    END
  END RW0_rdata[57]
  PIN RW0_rdata[58]
    DIRECTION OUTPUT ;
    USE SIGNAL ;
    SHAPE ABUTMENT ;
    PORT
      LAYER M5 ;
      RECT 105.708 293.904 105.804 294.000 ;
    END
  END RW0_rdata[58]
  PIN RW0_rdata[59]
    DIRECTION OUTPUT ;
    USE SIGNAL ;
    SHAPE ABUTMENT ;
    PORT
      LAYER M5 ;
      RECT 105.708 0.000 105.804 0.096 ;
    END
  END RW0_rdata[59]
  PIN RW0_rdata[60]
    DIRECTION OUTPUT ;
    USE SIGNAL ;
    SHAPE ABUTMENT ;
    PORT
      LAYER M4 ;
      RECT 0.000 277.116 0.096 277.212 ;
    END
  END RW0_rdata[60]
  PIN RW0_rdata[61]
    DIRECTION OUTPUT ;
    USE SIGNAL ;
    SHAPE ABUTMENT ;
    PORT
      LAYER M4 ;
      RECT 115.904 277.116 116.000 277.212 ;
    END
  END RW0_rdata[61]
  PIN RW0_rdata[62]
    DIRECTION OUTPUT ;
    USE SIGNAL ;
    SHAPE ABUTMENT ;
    PORT
      LAYER M5 ;
      RECT 108.780 293.904 108.876 294.000 ;
    END
  END RW0_rdata[62]
  PIN RW0_rdata[63]
    DIRECTION OUTPUT ;
    USE SIGNAL ;
    SHAPE ABUTMENT ;
    PORT
      LAYER M5 ;
      RECT 108.780 0.000 108.876 0.096 ;
    END
  END RW0_rdata[63]
  PIN RW0_wmask[0]
    DIRECTION INPUT ;
    USE SIGNAL ;
    SHAPE ABUTMENT ;
    PORT
      LAYER M4 ;
      RECT 0.000 285.036 0.096 285.132 ;
    END
  END RW0_wmask[0]
  PIN RW0_wmask[1]
    DIRECTION INPUT ;
    USE SIGNAL ;
    SHAPE ABUTMENT ;
    PORT
      LAYER M4 ;
      RECT 115.904 285.036 116.000 285.132 ;
    END
  END RW0_wmask[1]
  PIN RW0_wmask[2]
    DIRECTION INPUT ;
    USE SIGNAL ;
    SHAPE ABUTMENT ;
    PORT
      LAYER M5 ;
      RECT 111.852 293.904 111.948 294.000 ;
    END
  END RW0_wmask[2]
  PIN RW0_wmask[3]
    DIRECTION INPUT ;
    USE SIGNAL ;
    SHAPE ABUTMENT ;
    PORT
      LAYER M5 ;
      RECT 111.852 0.000 111.948 0.096 ;
    END
  END RW0_wmask[3]
  PIN RW0_wmask[4]
    DIRECTION INPUT ;
    USE SIGNAL ;
    SHAPE ABUTMENT ;
    PORT
      LAYER M4 ;
      RECT 0.000 292.908 0.096 293.004 ;
    END
  END RW0_wmask[4]
  PIN RW0_wmask[5]
    DIRECTION INPUT ;
    USE SIGNAL ;
    SHAPE ABUTMENT ;
    PORT
      LAYER M4 ;
      RECT 115.904 292.908 116.000 293.004 ;
    END
  END RW0_wmask[5]
  PIN RW0_wmask[6]
    DIRECTION INPUT ;
    USE SIGNAL ;
    SHAPE ABUTMENT ;
    PORT
      LAYER M5 ;
      RECT 114.924 293.904 115.020 294.000 ;
    END
  END RW0_wmask[6]
  PIN RW0_wmask[7]
    DIRECTION INPUT ;
    USE SIGNAL ;
    SHAPE ABUTMENT ;
    PORT
      LAYER M5 ;
      RECT 114.924 0.000 115.020 0.096 ;
    END
  END RW0_wmask[7]
END mem_1_ext

END LIBRARY
